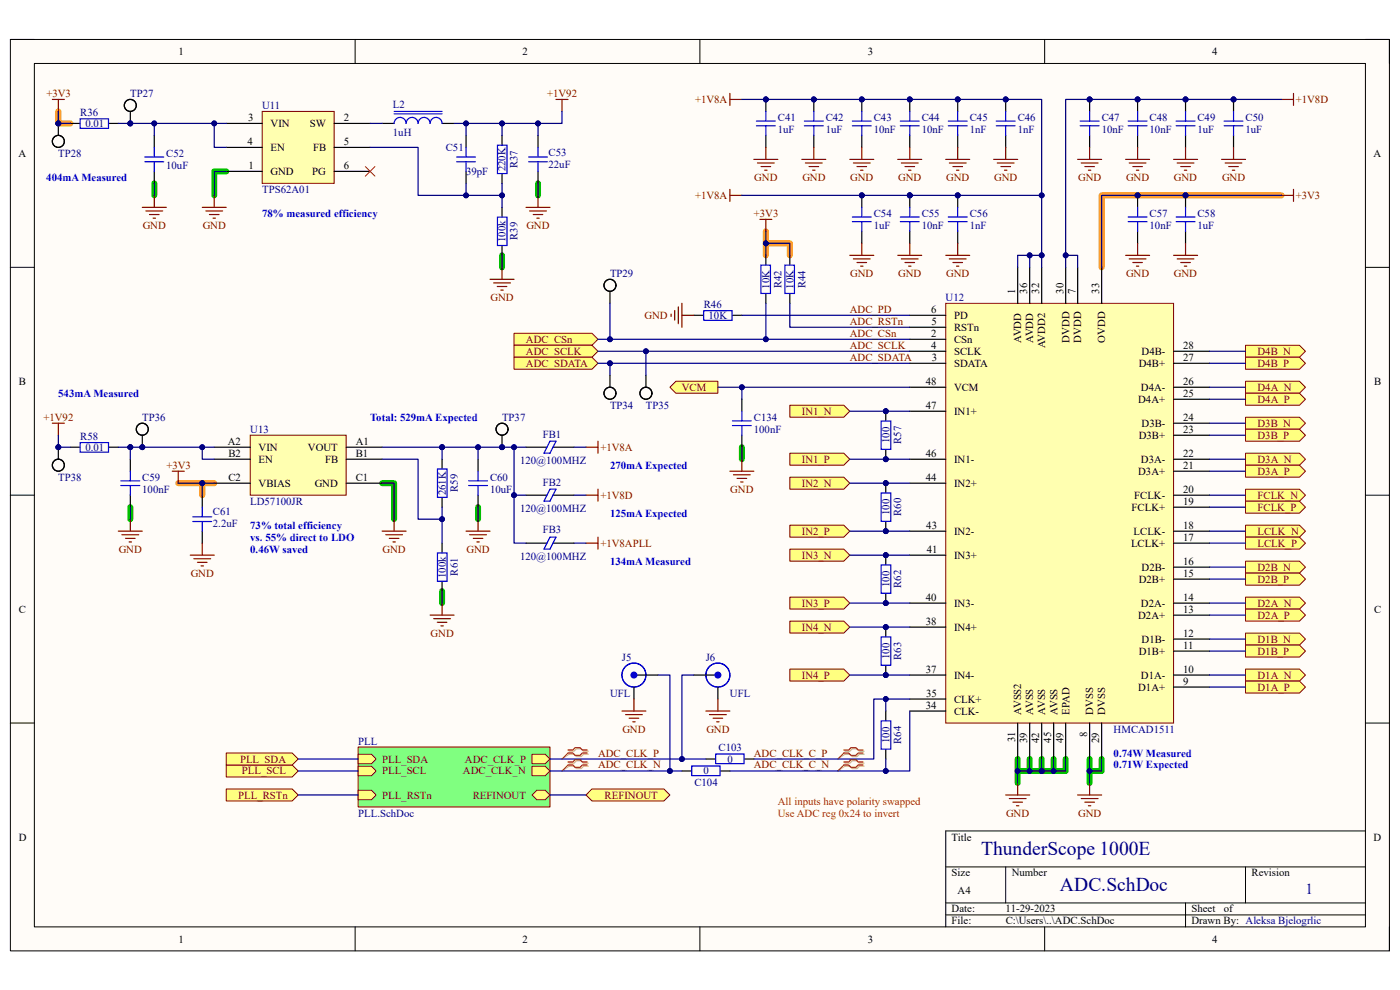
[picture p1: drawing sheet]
<svg xmlns="http://www.w3.org/2000/svg" width="297mm" height="210mm" viewBox="0 0 297 210" stroke-linecap="round" stroke-linejoin="round" font-family="sans-serif">
<defs><g id="words">
<g font-size="4.1" fill="#000080">
<text x="208.2" y="181.5">ThunderScope 1000E</text>
<text x="224.9" y="189.1">ADC.SchDoc</text>
</g>
<text font-size="3.2" fill="#000080" x="276.9" y="189.6">1</text>
<g font-size="2.3">
<text x="37.9" y="11.7">1</text>
<text x="110.9" y="11.7">2</text>
<text x="184.1" y="11.7">3</text>
<text x="257.1" y="11.7">4</text>
<text x="52.6" y="25.7">3</text>
<text x="57.4" y="26.9">VIN</text>
<text x="65.7" y="26.9">SW</text>
<text x="72.9" y="25.7">2</text>
<text x="3.9" y="33.3">A</text>
<text x="52.5" y="30.7">4</text>
<text x="52.7" y="35.9">1</text>
<text x="57.4" y="32">EN</text>
<text x="66.4" y="32">FB</text>
<text x="72.9" y="30.7">5</text>
<text x="72.9" y="35.9">6</text>
<text x="291.4" y="33.3">A</text>
<text x="57.4" y="37.1">GND</text>
<text x="66.2" y="37.1">PG</text>
<text x="215.4" y="62.3" transform="rotate(-90 215.4 62.3)">1</text>
<text x="217.9" y="62.3" transform="rotate(-90 217.9 62.3)">36</text>
<text x="220.5" y="62.3" transform="rotate(-90 220.5 62.3)">32</text>
<text x="225.6" y="62.3" transform="rotate(-90 225.6 62.3)">30</text>
<text x="228.1" y="62.3" transform="rotate(-90 228.1 62.3)">7</text>
<text x="233.2" y="62.3" transform="rotate(-90 233.2 62.3)">33</text>
<text x="197.5" y="66.4">6</text>
<text x="197.5" y="71.5">2</text>
<text x="197.6" y="68.9">5</text>
<text x="202.4" y="67.6">PD</text>
<text x="202.4" y="70.2">RSTn</text>
<text x="197.5" y="74">4</text>
<text x="197.7" y="76.5">3</text>
<text x="202.4" y="72.7">CSn</text>
<text x="202.4" y="75.3">SCLK</text>
<text x="202.4" y="77.8">SDATA</text>
<text x="216.7" y="72.7" transform="rotate(-90 216.7 72.7)">AVDD</text>
<text x="219.2" y="72.7" transform="rotate(-90 219.2 72.7)">AVDD</text>
<text x="221.7" y="73.8" transform="rotate(-90 221.7 73.8)">AVDD2</text>
<text x="226.9" y="72.7" transform="rotate(-90 226.9 72.7)">DVDD</text>
<text x="229.4" y="72.7" transform="rotate(-90 229.4 72.7)">DVDD</text>
<text x="234.5" y="72.7" transform="rotate(-90 234.5 72.7)">OVDD</text>
<text x="241.6" y="77.8">D4B+</text>
<text x="242.2" y="75.3">D4B-</text>
<text x="251" y="76.5">27</text>
<text x="251" y="74">28</text>
<text x="4" y="81.6">B</text>
<text x="196.4" y="81.6">48</text>
<text x="202.4" y="82.9">VCM</text>
<text x="242.1" y="82.9">D4A-</text>
<text x="251" y="81.6">26</text>
<text x="291.5" y="81.6">B</text>
<text x="196.4" y="86.7">47</text>
<text x="202.4" y="88">IN1+</text>
<text x="241.5" y="85.4">D4A+</text>
<text x="251" y="89.3">24</text>
<text x="251" y="84.2">25</text>
<text x="48.3" y="94.4">A2</text>
<text x="54.9" y="95.6">VIN</text>
<text x="65.3" y="95.6">VOUT</text>
<text x="75.5" y="94.4">A1</text>
<text x="241.6" y="93.1">D3B+</text>
<text x="242.2" y="90.6">D3B-</text>
<text x="251" y="91.8">23</text>
<text x="48.5" y="96.9">B2</text>
<text x="48.5" y="102">C2</text>
<text x="54.9" y="98.2">EN</text>
<text x="69" y="98.2">FB</text>
<text x="75.5" y="96.9">B1</text>
<text x="75.5" y="102">C1</text>
<text x="196.4" y="96.9">46</text>
<text x="196.4" y="102">44</text>
<text x="202.4" y="98.2">IN1-</text>
<text x="241.5" y="100.7">D3A+</text>
<text x="242.1" y="98.2">D3A-</text>
<text x="251" y="99.4">21</text>
<text x="251" y="96.9">22</text>
<text x="54.9" y="103.3">VBIAS</text>
<text x="66.8" y="103.3">GND</text>
<text x="202.4" y="103.3">IN2+</text>
<text x="240.6" y="105.8">FCLK-</text>
<text x="251" y="107.1">19</text>
<text x="251" y="104.5">20</text>
<text x="196.5" y="112.1">43</text>
<text x="202.4" y="113.4">IN2-</text>
<text x="240.1" y="108.3">FCLK+</text>
<text x="240.5" y="113.4">LCLK-</text>
<text x="251" y="112.1">18</text>
<text x="196.6" y="117.3">41</text>
<text x="202.4" y="118.5">IN3+</text>
<text x="239.9" y="116">LCLK+</text>
<text x="251" y="119.8">16</text>
<text x="251" y="114.7">17</text>
<text x="241.6" y="123.6">D2B+</text>
<text x="242.2" y="121.1">D2B-</text>
<text x="251" y="122.3">15</text>
<text x="4" y="130">C</text>
<text x="196.4" y="127.4">40</text>
<text x="202.4" y="128.7">IN3-</text>
<text x="241.5" y="131.2">D2A+</text>
<text x="242.1" y="128.7">D2A-</text>
<text x="251" y="130">13</text>
<text x="251" y="127.4">14</text>
<text x="291.5" y="130">C</text>
<text x="196.4" y="132.5">38</text>
<text x="202.4" y="133.8">IN4+</text>
<text x="242.2" y="136.3">D1B-</text>
<text x="251" y="137.6">11</text>
<text x="251" y="135">12</text>
<text x="196.4" y="142.7">37</text>
<text x="202.4" y="144">IN4-</text>
<text x="241.6" y="138.9">D1B+</text>
<text x="242.1" y="144">D1A-</text>
<text x="251" y="142.7">10</text>
<text x="196.5" y="147.8">35</text>
<text x="202.4" y="149.1">CLK+</text>
<text x="241.5" y="146.5">D1A+</text>
<text x="251" y="145.2">9</text>
<text x="196.4" y="150.3">34</text>
<text x="202.4" y="151.6">CLK-</text>
<text x="216.7" y="151.6" transform="rotate(-90 216.7 151.6)">AVSS2</text>
<text x="219.2" y="151.6" transform="rotate(-90 219.2 151.6)">AVSS</text>
<text x="221.7" y="151.6" transform="rotate(-90 221.7 151.6)">AVSS</text>
<text x="224.3" y="151.6" transform="rotate(-90 224.3 151.6)">AVSS</text>
<text x="226.9" y="151.6" transform="rotate(-90 226.9 151.6)">EPAD</text>
<text x="231.9" y="151.6" transform="rotate(-90 231.9 151.6)">DVSS</text>
<text x="234.5" y="151.6" transform="rotate(-90 234.5 151.6)">DVSS</text>
<text x="215.4" y="157.4" transform="rotate(-90 215.4 157.4)">31</text>
<text x="217.9" y="157.6" transform="rotate(-90 217.9 157.6)">39</text>
<text x="220.5" y="157.6" transform="rotate(-90 220.5 157.6)">42</text>
<text x="223" y="157.6" transform="rotate(-90 223 157.6)">45</text>
<text x="225.6" y="157.6" transform="rotate(-90 225.6 157.6)">49</text>
<text x="230.7" y="156.4" transform="rotate(-90 230.7 156.4)">8</text>
<text x="233.2" y="157.6" transform="rotate(-90 233.2 157.6)">29</text>
<text x="4" y="178.3">D</text>
<text x="201.9" y="178.3">Title</text>
<text x="291.4" y="178.3">D</text>
<text x="201.9" y="185.9">Size</text>
<text x="214.6" y="185.9">Number</text>
<text x="265.5" y="185.9">Revision</text>
<text x="203.2" y="189.7">A4</text>
<text x="201.9" y="193.5">Date:</text>
<text x="201.9" y="196.1">File:</text>
<text x="213.3" y="193.5">11-29-2023</text>
<text x="213.4" y="196.1">C:\Users\..\ADC.SchDoc</text>
<text x="252.8" y="193.5">Sheet</text>
<text x="252.8" y="196.1">Drawn By: Aleksa Bjelogrlic</text>
<text x="259.6" y="193.5">of</text>
<text x="37.9" y="199.9">1</text>
<text x="110.9" y="199.9">2</text>
<text x="184.1" y="199.9">3</text>
<text x="257.1" y="199.9">4</text>
</g>
<g font-size="2.3" fill="#800000">
<text x="9.9" y="20.6">+3V3</text>
<text x="116.1" y="20.6">+1V92</text>
<text x="147.4" y="21.8">+1V8A</text>
<text x="274.9" y="21.8">+1V8D</text>
<text x="160" y="38.4">GND</text>
<text x="170.2" y="38.4">GND</text>
<text x="180.4" y="38.4">GND</text>
<text x="190.5" y="38.4">GND</text>
<text x="200.7" y="38.4">GND</text>
<text x="210.9" y="38.4">GND</text>
<text x="228.7" y="38.4">GND</text>
<text x="238.9" y="38.4">GND</text>
<text x="249" y="38.4">GND</text>
<text x="259.2" y="38.4">GND</text>
<text x="147.4" y="42.2">+1V8A</text>
<text x="159.9" y="46">+3V3</text>
<text x="274.9" y="42.2">+3V3</text>
<text x="30.3" y="48.6">GND</text>
<text x="43" y="48.6">GND</text>
<text x="111.7" y="48.6">GND</text>
<text x="180.4" y="58.7">GND</text>
<text x="190.5" y="58.7">GND</text>
<text x="200.7" y="58.7">GND</text>
<text x="238.9" y="58.7">GND</text>
<text x="249" y="58.7">GND</text>
<text x="104.1" y="63.8">GND</text>
<text x="136.7" y="67.6">GND</text>
<text x="180.3" y="66.4">ADC_PD</text>
<text x="180.3" y="68.9">ADC_RSTn</text>
<text x="180.3" y="71.5">ADC_CSn</text>
<text x="111.6" y="72.7">ADC_CSn</text>
<text x="111.6" y="75.3">ADC_SCLK</text>
<text x="111.6" y="77.8">ADC_SDATA</text>
<text x="180.3" y="74">ADC_SCLK</text>
<text x="180.3" y="76.5">ADC_SDATA</text>
<text x="266.8" y="75.3">D4B_N</text>
<text x="266.8" y="77.8">D4B_P</text>
<text x="144.7" y="82.9">VCM</text>
<text x="266.8" y="82.9">D4A_N</text>
<text x="9.2" y="89.3">+1V92</text>
<text x="170.1" y="88">IN1_N</text>
<text x="266.8" y="85.4">D4A_P</text>
<text x="127.4" y="95.6">+1V8A</text>
<text x="266.8" y="90.6">D3B_N</text>
<text x="266.8" y="93.1">D3B_P</text>
<text x="35.3" y="99.4">+3V3</text>
<text x="170.1" y="98.2">IN1_P</text>
<text x="266.8" y="98.2">D3A_N</text>
<text x="266.8" y="100.7">D3A_P</text>
<text x="127.4" y="105.8">+1V8D</text>
<text x="154.9" y="104.5">GND</text>
<text x="170.1" y="103.3">IN2_N</text>
<text x="266.8" y="105.8">FCLK_N</text>
<text x="170.1" y="113.4">IN2_P</text>
<text x="266.8" y="108.3">FCLK_P</text>
<text x="266.8" y="113.4">LCLK_N</text>
<text x="25.2" y="117.3">GND</text>
<text x="81.2" y="117.3">GND</text>
<text x="99" y="117.3">GND</text>
<text x="127.4" y="116">+1V8APLL</text>
<text x="170.1" y="118.5">IN3_N</text>
<text x="266.8" y="116">LCLK_P</text>
<text x="40.5" y="122.3">GND</text>
<text x="266.8" y="121.1">D2B_N</text>
<text x="266.8" y="123.6">D2B_P</text>
<text x="170.1" y="128.7">IN3_P</text>
<text x="266.8" y="128.7">D2A_N</text>
<text x="266.8" y="131.2">D2A_P</text>
<text x="91.4" y="135">GND</text>
<text x="170.1" y="133.8">IN4_N</text>
<text x="266.8" y="136.3">D1B_N</text>
<text x="170.1" y="144">IN4_P</text>
<text x="266.8" y="138.9">D1B_P</text>
<text x="266.8" y="144">D1A_N</text>
<text x="266.8" y="146.5">D1A_P</text>
<text x="132" y="155.4">GND</text>
<text x="149.9" y="155.4">GND</text>
<text x="50.9" y="161.8">PLL_SDA</text>
<text x="81.1" y="161.8">PLL_SDA</text>
<text x="98.6" y="161.8">ADC_CLK_P</text>
<text x="126.9" y="160.5">ADC_CLK_P</text>
<text x="159.9" y="160.5">ADC_CLK_C_P</text>
<text x="51.3" y="164.3">PLL_SCL</text>
<text x="81.1" y="164.3">PLL_SCL</text>
<text x="98.2" y="164.3">ADC_CLK_N</text>
<text x="126.9" y="163">ADC_CLK_N</text>
<text x="159.9" y="163">ADC_CLK_C_N</text>
<text x="50.5" y="169.4">PLL_RSTn</text>
<text x="81.1" y="169.4">PLL_RSTn</text>
<text x="100.3" y="169.4">REFINOUT</text>
<text x="128.3" y="169.4">REFINOUT</text>
<text x="213.4" y="173.2">GND</text>
<text x="228.7" y="173.2">GND</text>
</g>
<g font-size="2.3" fill="#000080">
<text x="27.6" y="20.6">TP27</text>
<text x="55.6" y="23.1">U11</text>
<text x="83.4" y="22.9">L2</text>
<text x="17" y="24.7">R36</text>
<text x="18.1" y="26.9">0.01</text>
<text x="83.4" y="29">1uH</text>
<text x="165" y="25.7">C41</text>
<text x="165" y="28.2">1uF</text>
<text x="175.2" y="25.7">C42</text>
<text x="175.2" y="28.2">1uF</text>
<text x="185.4" y="25.7">C43</text>
<text x="185.4" y="28.2">10nF</text>
<text x="195.5" y="25.7">C44</text>
<text x="195.5" y="28.2">10nF</text>
<text x="205.7" y="25.7">C45</text>
<text x="205.7" y="28.2">1nF</text>
<text x="215.9" y="25.7">C46</text>
<text x="215.9" y="28.2">1nF</text>
<text x="233.7" y="25.7">C47</text>
<text x="233.7" y="28.2">10nF</text>
<text x="243.9" y="25.7">C48</text>
<text x="243.9" y="28.2">10nF</text>
<text x="254" y="25.7">C49</text>
<text x="254" y="28.2">1uF</text>
<text x="264.2" y="25.7">C50</text>
<text x="264.2" y="28.2">1uF</text>
<text x="12.4" y="33.3">TP28</text>
<text x="35.3" y="33.3">C52</text>
<text x="35.3" y="35.9">10uF</text>
<text x="94.6" y="32">C51</text>
<text x="109.8" y="35.7" transform="rotate(-90 109.8 35.7)">R37</text>
<text x="116.4" y="33">C53</text>
<text x="116.4" y="35.6">22uF</text>
<text x="55.6" y="40.9">TPS62A01</text>
<text x="98.9" y="37.1">39pF</text>
<text x="107.3" y="36.4" transform="rotate(-90 107.3 36.4)">220K</text>
<text x="185.4" y="46">C54</text>
<text x="195.5" y="46">C55</text>
<text x="205.7" y="46">C56</text>
<text x="243.9" y="46">C57</text>
<text x="254" y="46">C58</text>
<text x="107.3" y="51.4" transform="rotate(-90 107.3 51.4)">100k</text>
<text x="109.8" y="50.9" transform="rotate(-90 109.8 50.9)">R39</text>
<text x="185.4" y="48.6">1uF</text>
<text x="195.5" y="48.6">10nF</text>
<text x="205.7" y="48.6">1nF</text>
<text x="243.9" y="48.6">10nF</text>
<text x="254" y="48.6">1uF</text>
<text x="129.4" y="58.7">TP29</text>
<text x="149.3" y="65.4">R46</text>
<text x="163.2" y="61.3" transform="rotate(-90 163.2 61.3)">10K</text>
<text x="165.8" y="61.1" transform="rotate(-90 165.8 61.1)">R42</text>
<text x="168.3" y="61.3" transform="rotate(-90 168.3 61.3)">10K</text>
<text x="170.9" y="61.1" transform="rotate(-90 170.9 61.1)">R44</text>
<text x="200.6" y="63.8">U12</text>
<text x="150.3" y="67.6">10K</text>
<text x="30.2" y="89.3">TP36</text>
<text x="106.5" y="89.3">TP37</text>
<text x="129.4" y="86.7">TP34</text>
<text x="137" y="86.7">TP35</text>
<text x="159.9" y="89.3">C134</text>
<text x="17" y="93.4">R58</text>
<text x="18.1" y="95.6">0.01</text>
<text x="53.1" y="91.8">U13</text>
<text x="115.1" y="92.8">FB1</text>
<text x="159.9" y="91.8">100nF</text>
<text x="188.7" y="94" transform="rotate(-90 188.7 94)">100</text>
<text x="191.2" y="94.2" transform="rotate(-90 191.2 94.2)">R57</text>
<text x="12.4" y="102">TP38</text>
<text x="30.2" y="102">C59</text>
<text x="104" y="102">C60</text>
<text x="110.3" y="98.4">120@100MHZ</text>
<text x="30.2" y="104.5">100nF</text>
<text x="53.1" y="107.1">LD57100JR</text>
<text x="94.6" y="105.1" transform="rotate(-90 94.6 105.1)">261K</text>
<text x="97.1" y="104.4" transform="rotate(-90 97.1 104.4)">R59</text>
<text x="104" y="104.5">10uF</text>
<text x="115.1" y="103">FB2</text>
<text x="45.2" y="109.3">C61</text>
<text x="45.2" y="111.9">2.2uF</text>
<text x="110.3" y="108.6">120@100MHZ</text>
<text x="115.1" y="113.2">FB3</text>
<text x="188.7" y="109.3" transform="rotate(-90 188.7 109.3)">100</text>
<text x="191.2" y="109.5" transform="rotate(-90 191.2 109.5)">R60</text>
<text x="110.3" y="118.8">120@100MHZ</text>
<text x="94.6" y="122.6" transform="rotate(-90 94.6 122.6)">100k</text>
<text x="97.1" y="122.1" transform="rotate(-90 97.1 122.1)">R61</text>
<text x="188.7" y="124.5" transform="rotate(-90 188.7 124.5)">100</text>
<text x="191.2" y="124.7" transform="rotate(-90 191.2 124.7)">R62</text>
<text x="132" y="140.1">J5</text>
<text x="149.7" y="140.1">J6</text>
<text x="188.7" y="139.8" transform="rotate(-90 188.7 139.8)">100</text>
<text x="191.2" y="140" transform="rotate(-90 191.2 140)">R63</text>
<text x="129.4" y="147.8">UFL</text>
<text x="154.9" y="147.8">UFL</text>
<text x="236.3" y="155.4">HMCAD1511</text>
<text x="76" y="157.9">PLL</text>
<text x="152.4" y="159.2">C103</text>
<text x="154.3" y="161.8">0</text>
<text x="188.7" y="157.6" transform="rotate(-90 188.7 157.6)">100</text>
<text x="191.2" y="157.8" transform="rotate(-90 191.2 157.8)">R64</text>
<text x="147.3" y="166.8">C104</text>
<text x="149.2" y="164.3">0</text>
<text x="76" y="173.2">PLL.SchDoc</text>
</g>
<g font-size="2.3" fill="#00f">
<text x="9.8" y="38.4">404mA Measured</text>
<text x="55.6" y="46">78% measured efficiency</text>
<text x="12.4" y="84.2">543mA Measured</text>
<text x="78.5" y="89.3">Total: 529mA Expected</text>
<text x="129.4" y="99.4">270mA Expected</text>
<text x="53.1" y="112.1">73% total efficiency</text>
<text x="129.4" y="109.6">125mA Expected</text>
<text x="53.1" y="114.7">vs. 55% direct to LDO</text>
<text x="53.1" y="117.3">0.46W saved</text>
<text x="129.4" y="119.8">134mA Measured</text>
<text x="236.3" y="160.5">0.74W Measured</text>
<text x="236.3" y="163">0.71W Expected</text>
</g>
<g font-size="2.3" fill="#f00">
<text x="165" y="170.7">All inputs have polarity swapped</text>
<text x="165" y="173.2">Use ADC reg 0x24 to invert</text>
</g>
</g></defs>
<path d="M2.2 8.4h292.6v193.3h-292.6z" fill-rule="evenodd" fill="#fffcf8"/>
<path d="M2.2 8.4h292.6v193.3h-292.6z" fill="none" stroke="#000" stroke-width=".21"/>
<path d="M7.3 13.5h282.4v183.1h-282.4z" fill-rule="evenodd" fill="#fffcf8"/>
<g fill="none" stroke="#000" stroke-width=".21">
<path d="M2.2 8.4h5.1M7.3 13.5h282.4v183.1h-282.4zM75.3 8.4v5.1M148.5 8.4v5.1M221.6 8.4v5.1M289.7 8.4h5.1v5.1M2.2 56.7h5.1M289.7 56.7h5.1M2.2 105h5.1M289.7 105.1h5.1M2.2 153.4h5.1M289.7 153.4h5.1"/>
<path d="M289.7 176.3h-89.1v20.3M75.3 196.6v5.1M148.5 196.6v5.1M200.6 183.9h89.1M200.6 191.5h89.1M200.6 194.1h89.1M213.4 183.9v7.6M221.6 196.6v5.1M251.5 191.5v5.1M264.2 183.9v7.6M294.8 196.6v5.1"/>
</g>
<g fill="none" stroke="#00be00" stroke-width="1.3">
<path d="M32.7 38.9v2.5M48 36.4h-2.5v5M114.1 38.9v2.5M106.5 54.2v2.5M157.4 94.9v2.5M27.6 107.6v2.5M81.1 102.5h2.5v7.6M101.4 107.6v2.5M93.8 125.4v2.5M215.9 161v2.6M218.5 161v2.6M221 163.6h-5.1v2.5"/>
<path d="M221 161v2.6M223.5 161v2.6M226.1 161v2.6h-5.1M231.2 161v2.6h2.5v-2.6M231.2 163.6v2.5"/>
</g>
<path d="M12.4 23.6v2.6h2.5M162.5 54.2v-2.6h5.1v2.6M162.5 49.1v2.5M271.9 41.4h-38.2v15.3M37.8 102.5h5.1M45.5 102.5h-2.6v2.5" fill="none" stroke="#f90" stroke-width="1.3"/>
<path d="M93.8 97.4v2M101.4 97.4v2.6M93.8 105.6v2M93.8 115.2v2M101.4 105v2.6M93.8 123.4v2" fill="none" stroke="#000" stroke-width=".25"/>
<path d="M92.8 99.5h2v6h-2zM101.4 100v2M92.8 117.3h2v6h-2zM99.4 103h4M99.4 102h4M101.4 103v2" fill="none" stroke="#00f" stroke-width=".25"/>
<path d="M98.9 112.7h5.1M99.6 113.4h3.6M100.4 114.2h2M101.2 115h.5M101.4 110.1v2.6M91.2 130.5h5.1M92 131.2h3.6M92.8 132h2M93.5 132.8h.5M93.8 127.9v2.6" fill="none" stroke="#800000" stroke-width=".25"/>
<circle cx="241.3" cy="41.4" r=".51" fill="#000080"/>
<circle cx="241.3" cy="41.4" r=".51" fill="none" stroke="#000080" stroke-width=".21"/>
<path d="M241.3 41.4v2.6M241.3 49.1v2.5" fill="none" stroke="#000" stroke-width=".25"/>
<circle cx="241.3" cy="41.4" r=".51" fill="#000080"/>
<circle cx="241.3" cy="41.4" r=".51" fill="none" stroke="#000080" stroke-width=".21"/>
<path d="M239.3 47h4M239.3 46h4M241.3 44v2M241.3 47v2.1" fill="none" stroke="#00f" stroke-width=".25"/>
<circle cx="251.5" cy="41.4" r=".51" fill="#000080"/>
<circle cx="251.5" cy="41.4" r=".51" fill="none" stroke="#000080" stroke-width=".21"/>
<path d="M251.5 41.4v2.6M251.5 49.1v2.5" fill="none" stroke="#000" stroke-width=".25"/>
<circle cx="251.5" cy="41.4" r=".51" fill="#000080"/>
<circle cx="251.5" cy="41.4" r=".51" fill="none" stroke="#000080" stroke-width=".21"/>
<path d="M249.5 47h4M249.5 46h4M251.5 44v2M251.5 47v2.1" fill="none" stroke="#00f" stroke-width=".25"/>
<path d="M238.8 54.2h5.1M239.6 54.9h3.5M240.3 55.7h2.1M241.1 56.5h.5M241.3 51.6v2.6M249 54.2h5.1M249.7 54.9h3.6M250.5 55.7h2M251.3 56.5h.5M251.5 51.6v2.6M271.9 41.4h2.5M274.4 40.2v2.5" fill="none" stroke="#800000" stroke-width=".25"/>
<circle cx="231.2" cy="21.1" r=".51" fill="#000080"/>
<circle cx="231.2" cy="21.1" r=".51" fill="none" stroke="#000080" stroke-width=".21"/>
<path d="M231.2 21.1v2.5M231.2 28.7v2.6" fill="none" stroke="#000" stroke-width=".25"/>
<circle cx="231.2" cy="21.1" r=".51" fill="#000080"/>
<circle cx="231.2" cy="21.1" r=".51" fill="none" stroke="#000080" stroke-width=".21"/>
<path d="M229.2 26.7h4M229.2 25.7h4M231.2 23.6v2.1M231.2 26.7v2" fill="none" stroke="#00f" stroke-width=".25"/>
<circle cx="261.7" cy="21.1" r=".51" fill="#000080"/>
<circle cx="261.7" cy="21.1" r=".51" fill="none" stroke="#000080" stroke-width=".21"/>
<path d="M261.7 21.1v2.5M261.7 28.7v2.6" fill="none" stroke="#000" stroke-width=".25"/>
<circle cx="261.7" cy="21.1" r=".51" fill="#000080"/>
<circle cx="261.7" cy="21.1" r=".51" fill="none" stroke="#000080" stroke-width=".21"/>
<path d="M259.7 26.7h4M259.7 25.7h4M261.7 23.6v2.1M261.7 26.7v2" fill="none" stroke="#00f" stroke-width=".25"/>
<path d="M228.6 33.8h5.1M229.4 34.6h3.5M230.1 35.3h2.1M230.9 36.1h.5M231.2 31.3v2.5M259.2 33.8h5M259.9 34.6h3.6M260.7 35.3h2M261.4 36.1h.5M261.7 31.3v2.5" fill="none" stroke="#800000" stroke-width=".25"/>
<circle cx="241.3" cy="21.1" r=".51" fill="#000080"/>
<circle cx="241.3" cy="21.1" r=".51" fill="none" stroke="#000080" stroke-width=".21"/>
<path d="M241.3 21.1v2.5M241.3 28.7v2.6" fill="none" stroke="#000" stroke-width=".25"/>
<circle cx="241.3" cy="21.1" r=".51" fill="#000080"/>
<circle cx="241.3" cy="21.1" r=".51" fill="none" stroke="#000080" stroke-width=".21"/>
<path d="M239.3 26.7h4M239.3 25.7h4M241.3 23.6v2.1M241.3 26.7v2" fill="none" stroke="#00f" stroke-width=".25"/>
<circle cx="251.5" cy="21.1" r=".51" fill="#000080"/>
<circle cx="251.5" cy="21.1" r=".51" fill="none" stroke="#000080" stroke-width=".21"/>
<path d="M251.5 21.1v2.5M251.5 28.7v2.6" fill="none" stroke="#000" stroke-width=".25"/>
<circle cx="251.5" cy="21.1" r=".51" fill="#000080"/>
<circle cx="251.5" cy="21.1" r=".51" fill="none" stroke="#000080" stroke-width=".21"/>
<path d="M249.5 26.7h4M249.5 25.7h4M251.5 23.6v2.1M251.5 26.7v2" fill="none" stroke="#00f" stroke-width=".25"/>
<path d="M274.4 19.8v2.6M238.8 33.8h5.1M239.6 34.6h3.5M240.3 35.3h2.1M241.1 36.1h.5M241.3 31.3v2.5M249 33.8h5.1M249.7 34.6h3.6M250.5 35.3h2M251.3 36.1h.5M251.5 31.3v2.5M271.9 21.1h2.5" fill="none" stroke="#800000" stroke-width=".25"/>
<circle cx="193" cy="21.1" r=".51" fill="#000080"/>
<circle cx="193" cy="21.1" r=".51" fill="none" stroke="#000080" stroke-width=".21"/>
<path d="M193 21.1v2.5M193 28.7v2.6" fill="none" stroke="#000" stroke-width=".25"/>
<circle cx="193" cy="21.1" r=".51" fill="#000080"/>
<circle cx="193" cy="21.1" r=".51" fill="none" stroke="#000080" stroke-width=".21"/>
<path d="M191 26.7h4M191 25.7h4M193 23.6v2.1M193 26.7v2" fill="none" stroke="#00f" stroke-width=".25"/>
<circle cx="162.5" cy="21.1" r=".51" fill="#000080"/>
<circle cx="162.5" cy="21.1" r=".51" fill="none" stroke="#000080" stroke-width=".21"/>
<path d="M162.5 21.1v2.5M162.5 28.7v2.6" fill="none" stroke="#000" stroke-width=".25"/>
<circle cx="162.5" cy="21.1" r=".51" fill="#000080"/>
<circle cx="162.5" cy="21.1" r=".51" fill="none" stroke="#000080" stroke-width=".21"/>
<path d="M160.5 26.7h4M160.5 25.7h4M162.5 23.6v2.1M162.5 26.7v2" fill="none" stroke="#00f" stroke-width=".25"/>
<path d="M159.9 33.8h5.1M160.7 34.6h3.6M161.5 35.3h2M162.2 36.1h.5M162.5 31.3v2.5M190.5 33.8h5M191.2 34.6h3.6M192 35.3h2M192.8 36.1h.5M193 31.3v2.5" fill="none" stroke="#800000" stroke-width=".25"/>
<circle cx="182.8" cy="21.1" r=".51" fill="#000080"/>
<circle cx="182.8" cy="21.1" r=".51" fill="none" stroke="#000080" stroke-width=".21"/>
<path d="M182.8 21.1v2.5M182.8 28.7v2.6" fill="none" stroke="#000" stroke-width=".25"/>
<circle cx="182.8" cy="21.1" r=".51" fill="#000080"/>
<circle cx="182.8" cy="21.1" r=".51" fill="none" stroke="#000080" stroke-width=".21"/>
<path d="M180.8 26.7h4M180.8 25.7h4M182.8 23.6v2.1M182.8 26.7v2" fill="none" stroke="#00f" stroke-width=".25"/>
<circle cx="172.7" cy="21.1" r=".51" fill="#000080"/>
<circle cx="172.7" cy="21.1" r=".51" fill="none" stroke="#000080" stroke-width=".21"/>
<path d="M172.7 21.1v2.5M172.7 28.7v2.6" fill="none" stroke="#000" stroke-width=".25"/>
<circle cx="172.7" cy="21.1" r=".51" fill="#000080"/>
<circle cx="172.7" cy="21.1" r=".51" fill="none" stroke="#000080" stroke-width=".21"/>
<path d="M170.6 26.7h4.1M170.6 25.7h4.1M172.7 23.6v2.1M172.7 26.7v2" fill="none" stroke="#00f" stroke-width=".25"/>
<path d="M170.1 33.8h5.1M170.9 34.6h3.5M171.6 35.3h2.1M172.4 36.1h.5M172.7 31.3v2.5M180.3 33.8h5.1M181 34.6h3.6M181.8 35.3h2M182.6 36.1h.5M182.8 31.3v2.5" fill="none" stroke="#800000" stroke-width=".25"/>
<circle cx="203.2" cy="21.1" r=".51" fill="#000080"/>
<circle cx="203.2" cy="21.1" r=".51" fill="none" stroke="#000080" stroke-width=".21"/>
<path d="M203.2 21.1v2.5M203.2 28.7v2.6" fill="none" stroke="#000" stroke-width=".25"/>
<circle cx="203.2" cy="21.1" r=".51" fill="#000080"/>
<circle cx="203.2" cy="21.1" r=".51" fill="none" stroke="#000080" stroke-width=".21"/>
<path d="M201.2 26.7h4M201.2 25.7h4M203.2 23.6v2.1M203.2 26.7v2" fill="none" stroke="#00f" stroke-width=".25"/>
<path d="M200.6 33.8h5.1M201.4 34.6h3.6M202.2 35.3h2M202.9 36.1h.5M203.2 31.3v2.5" fill="none" stroke="#800000" stroke-width=".25"/>
<circle cx="213.4" cy="21.1" r=".51" fill="#000080"/>
<circle cx="213.4" cy="21.1" r=".51" fill="none" stroke="#000080" stroke-width=".21"/>
<path d="M213.4 21.1v2.5M213.4 28.7v2.6" fill="none" stroke="#000" stroke-width=".25"/>
<circle cx="213.4" cy="21.1" r=".51" fill="#000080"/>
<circle cx="213.4" cy="21.1" r=".51" fill="none" stroke="#000080" stroke-width=".21"/>
<path d="M211.3 26.7h4.1M211.3 25.7h4.1M213.4 23.6v2.1M213.4 26.7v2" fill="none" stroke="#00f" stroke-width=".25"/>
<path d="M210.8 33.8h5.1M211.6 34.6h3.5M212.3 35.3h2.1M213.1 36.1h.5M213.4 31.3v2.5" fill="none" stroke="#800000" stroke-width=".25"/>
<circle cx="182.8" cy="41.4" r=".51" fill="#000080"/>
<circle cx="182.8" cy="41.4" r=".51" fill="none" stroke="#000080" stroke-width=".21"/>
<path d="M182.8 41.4v2.6M182.8 49.1v2.5" fill="none" stroke="#000" stroke-width=".25"/>
<circle cx="182.8" cy="41.4" r=".51" fill="#000080"/>
<circle cx="182.8" cy="41.4" r=".51" fill="none" stroke="#000080" stroke-width=".21"/>
<path d="M180.8 47h4M180.8 46h4M182.8 44v2M182.8 47v2.1" fill="none" stroke="#00f" stroke-width=".25"/>
<path d="M180.3 54.2h5.1M181 54.9h3.6M181.8 55.7h2M182.6 56.5h.5M182.8 51.6v2.6" fill="none" stroke="#800000" stroke-width=".25"/>
<circle cx="193" cy="41.4" r=".51" fill="#000080"/>
<circle cx="193" cy="41.4" r=".51" fill="none" stroke="#000080" stroke-width=".21"/>
<path d="M193 41.4v2.6M193 49.1v2.5" fill="none" stroke="#000" stroke-width=".25"/>
<circle cx="193" cy="41.4" r=".51" fill="#000080"/>
<circle cx="193" cy="41.4" r=".51" fill="none" stroke="#000080" stroke-width=".21"/>
<path d="M191 47h4M191 46h4M193 44v2M193 47v2.1" fill="none" stroke="#00f" stroke-width=".25"/>
<path d="M190.5 54.2h5M191.2 54.9h3.6M192 55.7h2M192.8 56.5h.5M193 51.6v2.6" fill="none" stroke="#800000" stroke-width=".25"/>
<circle cx="203.2" cy="41.4" r=".51" fill="#000080"/>
<circle cx="203.2" cy="41.4" r=".51" fill="none" stroke="#000080" stroke-width=".21"/>
<path d="M203.2 41.4v2.6M203.2 49.1v2.5" fill="none" stroke="#000" stroke-width=".25"/>
<circle cx="203.2" cy="41.4" r=".51" fill="#000080"/>
<circle cx="203.2" cy="41.4" r=".51" fill="none" stroke="#000080" stroke-width=".21"/>
<path d="M161.4 56.3h2.1v6h-2.1zM166.5 56.3h2v6h-2zM201.2 47h4M201.2 46h4M203.2 44v2M203.2 47v2.1M149.3 65.9h6v2h-6z" fill="none" stroke="#00f" stroke-width=".25"/>
<path d="M200.6 54.2h5.1M201.4 54.9h3.6M202.2 55.7h2M202.9 56.5h.5M203.2 51.6v2.6" fill="none" stroke="#800000" stroke-width=".25"/>
<path d="M162.5 54.2v2M167.6 54.2v2M147.2 66.9h2M155.4 66.9h2M162.5 62.3v2M167.6 62.3v2" fill="none" stroke="#000" stroke-width=".25"/>
<path d="M200.6 64.3h48.4v89.1h-48.4z" fill-rule="evenodd" fill="#ffffb0"/>
<path d="M200.6 64.3h48.4v89.1h-48.4z" fill="none" stroke="#800000" stroke-width=".21"/>
<g fill="none" stroke="#000" stroke-width=".25">
<path d="M215.9 56.7v7.6M218.5 56.7v7.6M221 56.7v7.6M226.1 56.7v7.6M228.6 56.7v7.6M233.7 56.7v7.6M193 66.9h7.6M193 69.4h7.6M193 72h7.6M193 74.5h7.6M193 77.1h7.6M249 74.5h7.6"/>
<path d="M249 77.1h7.6M193 82.1h7.6M193 87.2h7.6M193 97.4h7.6M249 82.1h7.6M249 97.4h7.6M249 100h7.6M249 92.3h7.6M249 89.8h7.6M249 84.7h7.6M193 102.5h7.6M193 112.7h7.6"/>
<path d="M193 117.8h7.6M249 112.7h7.6M249 115.2h7.6M249 107.6h7.6M249 105.1h7.6M193 127.9h7.6M193 133h7.6M249 127.9h7.6M249 138.1h7.6M249 135.6h7.6M249 130.5h7.6M249 122.9h7.6"/>
<path d="M249 120.3h7.6M193 143.2h7.6M193 148.3h7.6M193 150.8h7.6M215.9 153.4v7.6M218.5 153.4v7.6M221 153.4v7.6M223.5 153.4v7.6M226.1 153.4v7.6M231.2 153.4v7.6M233.7 153.4v7.6M249 143.2h7.6"/>
<path d="M249 145.8h7.6"/>
</g>
<g fill="none" stroke="#800000" stroke-width=".25">
<path d="M154.8 19.8v2.6M154.8 21.1h2.6M154.8 40.2v2.5M154.8 41.4h2.6M161.2 46.5h2.5M162.5 46.5v2.6M213.4 168.6h5.1M214.1 169.4h3.6M214.9 170.2h2M215.6 170.9h.6M215.9 166.1v2.5M228.6 168.6h5.1"/>
<path d="M229.4 169.4h3.5M230.1 170.2h2.1M230.9 170.9h.5M231.2 166.1v2.5"/>
</g>
<circle cx="187.9" cy="87.2" r=".51" fill="#000080"/>
<circle cx="187.9" cy="87.2" r=".51" fill="none" stroke="#000080" stroke-width=".21"/>
<circle cx="187.9" cy="97.4" r=".51" fill="#000080"/>
<circle cx="187.9" cy="97.4" r=".51" fill="none" stroke="#000080" stroke-width=".21"/>
<path d="M187.9 87.2v2" fill="none" stroke="#000" stroke-width=".25"/>
<circle cx="187.9" cy="87.2" r=".51" fill="#000080"/>
<circle cx="187.9" cy="87.2" r=".51" fill="none" stroke="#000080" stroke-width=".21"/>
<path d="M187.9 95.4v2" fill="none" stroke="#000" stroke-width=".25"/>
<circle cx="187.9" cy="97.4" r=".51" fill="#000080"/>
<circle cx="187.9" cy="97.4" r=".51" fill="none" stroke="#000080" stroke-width=".21"/>
<path d="M186.9 89.3h2.1v6h-2.1z" fill="none" stroke="#00f" stroke-width=".25"/>
<circle cx="187.9" cy="102.5" r=".51" fill="#000080"/>
<circle cx="187.9" cy="102.5" r=".51" fill="none" stroke="#000080" stroke-width=".21"/>
<circle cx="187.9" cy="112.7" r=".51" fill="#000080"/>
<circle cx="187.9" cy="112.7" r=".51" fill="none" stroke="#000080" stroke-width=".21"/>
<path d="M187.9 102.5v2" fill="none" stroke="#000" stroke-width=".25"/>
<circle cx="187.9" cy="102.5" r=".51" fill="#000080"/>
<circle cx="187.9" cy="102.5" r=".51" fill="none" stroke="#000080" stroke-width=".21"/>
<path d="M187.9 110.7v2" fill="none" stroke="#000" stroke-width=".25"/>
<circle cx="187.9" cy="112.7" r=".51" fill="#000080"/>
<circle cx="187.9" cy="112.7" r=".51" fill="none" stroke="#000080" stroke-width=".21"/>
<path d="M186.9 104.6h2.1v6h-2.1z" fill="none" stroke="#00f" stroke-width=".25"/>
<circle cx="187.9" cy="117.8" r=".51" fill="#000080"/>
<circle cx="187.9" cy="117.8" r=".51" fill="none" stroke="#000080" stroke-width=".21"/>
<circle cx="187.9" cy="127.9" r=".51" fill="#000080"/>
<circle cx="187.9" cy="127.9" r=".51" fill="none" stroke="#000080" stroke-width=".21"/>
<path d="M187.9 117.8v2" fill="none" stroke="#000" stroke-width=".25"/>
<circle cx="187.9" cy="117.8" r=".51" fill="#000080"/>
<circle cx="187.9" cy="117.8" r=".51" fill="none" stroke="#000080" stroke-width=".21"/>
<path d="M187.9 125.9v2" fill="none" stroke="#000" stroke-width=".25"/>
<circle cx="187.9" cy="127.9" r=".51" fill="#000080"/>
<circle cx="187.9" cy="127.9" r=".51" fill="none" stroke="#000080" stroke-width=".21"/>
<path d="M186.9 119.8h2.1v6.1h-2.1z" fill="none" stroke="#00f" stroke-width=".25"/>
<circle cx="187.9" cy="133" r=".51" fill="#000080"/>
<circle cx="187.9" cy="133" r=".51" fill="none" stroke="#000080" stroke-width=".21"/>
<circle cx="187.9" cy="143.2" r=".51" fill="#000080"/>
<circle cx="187.9" cy="143.2" r=".51" fill="none" stroke="#000080" stroke-width=".21"/>
<path d="M187.9 133v2" fill="none" stroke="#000" stroke-width=".25"/>
<circle cx="187.9" cy="133" r=".51" fill="#000080"/>
<circle cx="187.9" cy="133" r=".51" fill="none" stroke="#000080" stroke-width=".21"/>
<path d="M187.9 141.2v2" fill="none" stroke="#000" stroke-width=".25"/>
<circle cx="187.9" cy="143.2" r=".51" fill="#000080"/>
<circle cx="187.9" cy="143.2" r=".51" fill="none" stroke="#000080" stroke-width=".21"/>
<path d="M186.9 135.1h2.1v6h-2.1z" fill="none" stroke="#00f" stroke-width=".25"/>
<path d="M264.2 73.2h11.5l1.3 1.3-1.3 1.3h-11.5z" fill-rule="evenodd" fill="#ffff80"/>
<path d="M264.2 73.2h11.5l1.3 1.3-1.3 1.3h-11.5z" fill="none" stroke="#800000" stroke-width=".21"/>
<path d="M264.2 75.8h11.5l1.3 1.3-1.3 1.2h-11.5z" fill-rule="evenodd" fill="#ffff80"/>
<path d="M264.2 75.8h11.5l1.3 1.3-1.3 1.2h-11.5z" fill="none" stroke="#800000" stroke-width=".21"/>
<path d="M264.2 80.9h11.5l1.3 1.2-1.3 1.3h-11.5z" fill-rule="evenodd" fill="#ffff80"/>
<path d="M264.2 80.9h11.5l1.3 1.2-1.3 1.3h-11.5z" fill="none" stroke="#800000" stroke-width=".21"/>
<path d="M264.2 83.4h11.5l1.3 1.3-1.3 1.3h-11.5z" fill-rule="evenodd" fill="#ffff80"/>
<path d="M264.2 83.4h11.5l1.3 1.3-1.3 1.3h-11.5z" fill="none" stroke="#800000" stroke-width=".21"/>
<path d="M264.2 88.5h11.5l1.3 1.3-1.3 1.3h-11.5z" fill-rule="evenodd" fill="#ffff80"/>
<path d="M264.2 88.5h11.5l1.3 1.3-1.3 1.3h-11.5z" fill="none" stroke="#800000" stroke-width=".21"/>
<path d="M264.2 91.1h11.5l1.3 1.2-1.3 1.3h-11.5z" fill-rule="evenodd" fill="#ffff80"/>
<path d="M264.2 91.1h11.5l1.3 1.2-1.3 1.3h-11.5z" fill="none" stroke="#800000" stroke-width=".21"/>
<path d="M264.2 96.1h11.5l1.3 1.3-1.3 1.3h-11.5z" fill-rule="evenodd" fill="#ffff80"/>
<path d="M264.2 96.1h11.5l1.3 1.3-1.3 1.3h-11.5z" fill="none" stroke="#800000" stroke-width=".21"/>
<path d="M264.2 98.7h11.5l1.3 1.3-1.3 1.2h-11.5z" fill-rule="evenodd" fill="#ffff80"/>
<path d="M264.2 98.7h11.5l1.3 1.3-1.3 1.2h-11.5z" fill="none" stroke="#800000" stroke-width=".21"/>
<path d="M264.2 103.8h11.5l1.3 1.3-1.3 1.2h-11.5z" fill-rule="evenodd" fill="#ffff80"/>
<path d="M264.2 103.8h11.5l1.3 1.3-1.3 1.2h-11.5z" fill="none" stroke="#800000" stroke-width=".21"/>
<path d="M264.2 106.3h11.5l1.3 1.3-1.3 1.3h-11.5z" fill-rule="evenodd" fill="#ffff80"/>
<path d="M264.2 106.3h11.5l1.3 1.3-1.3 1.3h-11.5z" fill="none" stroke="#800000" stroke-width=".21"/>
<path d="M264.2 111.4h11.5l1.3 1.3-1.3 1.3h-11.5z" fill-rule="evenodd" fill="#ffff80"/>
<path d="M264.2 111.4h11.5l1.3 1.3-1.3 1.3h-11.5z" fill="none" stroke="#800000" stroke-width=".21"/>
<path d="M264.2 114h11.5l1.3 1.2-1.3 1.3h-11.5z" fill-rule="evenodd" fill="#ffff80"/>
<path d="M264.2 114h11.5l1.3 1.2-1.3 1.3h-11.5z" fill="none" stroke="#800000" stroke-width=".21"/>
<path d="M264.2 119h11.5l1.3 1.3-1.3 1.3h-11.5z" fill-rule="evenodd" fill="#ffff80"/>
<path d="M264.2 119h11.5l1.3 1.3-1.3 1.3h-11.5z" fill="none" stroke="#800000" stroke-width=".21"/>
<path d="M264.2 121.6h11.5l1.3 1.3-1.3 1.2h-11.5z" fill-rule="evenodd" fill="#ffff80"/>
<path d="M264.2 121.6h11.5l1.3 1.3-1.3 1.2h-11.5z" fill="none" stroke="#800000" stroke-width=".21"/>
<path d="M264.2 126.7h11.5l1.3 1.2-1.3 1.3h-11.5z" fill-rule="evenodd" fill="#ffff80"/>
<path d="M264.2 126.7h11.5l1.3 1.2-1.3 1.3h-11.5z" fill="none" stroke="#800000" stroke-width=".21"/>
<path d="M264.2 129.2h11.5l1.3 1.3-1.3 1.3h-11.5z" fill-rule="evenodd" fill="#ffff80"/>
<path d="M264.2 129.2h11.5l1.3 1.3-1.3 1.3h-11.5z" fill="none" stroke="#800000" stroke-width=".21"/>
<path d="M264.2 134.3h11.5l1.3 1.3-1.3 1.2h-11.5z" fill-rule="evenodd" fill="#ffff80"/>
<path d="M264.2 134.3h11.5l1.3 1.3-1.3 1.2h-11.5z" fill="none" stroke="#800000" stroke-width=".21"/>
<path d="M264.2 136.8h11.5l1.3 1.3-1.3 1.3h-11.5z" fill-rule="evenodd" fill="#ffff80"/>
<path d="M264.2 136.8h11.5l1.3 1.3-1.3 1.3h-11.5z" fill="none" stroke="#800000" stroke-width=".21"/>
<path d="M264.2 141.9h11.5l1.3 1.3-1.3 1.3h-11.5z" fill-rule="evenodd" fill="#ffff80"/>
<path d="M264.2 141.9h11.5l1.3 1.3-1.3 1.3h-11.5z" fill="none" stroke="#800000" stroke-width=".21"/>
<path d="M264.2 144.5h11.5l1.3 1.3-1.3 1.2h-11.5z" fill-rule="evenodd" fill="#ffff80"/>
<path d="M264.2 144.5h11.5l1.3 1.3-1.3 1.2h-11.5z" fill="none" stroke="#800000" stroke-width=".21"/>
<path d="M109.1 70.7h16.5l1.3 1.3-1.3 1.2h-16.5z" fill-rule="evenodd" fill="#ffff80"/>
<path d="M109.1 70.7h16.5l1.3 1.3-1.3 1.2h-16.5z" fill="none" stroke="#800000" stroke-width=".21"/>
<path d="M142.1 82.1l1.3-1.2h8.9v2.5h-8.9z" fill-rule="evenodd" fill="#ffff80"/>
<path d="M142.1 82.1l1.3-1.2h8.9v2.5h-8.9z" fill="none" stroke="#800000" stroke-width=".21"/>
<path d="M109.1 73.2h16.5l1.3 1.3-1.3 1.3h-16.5z" fill-rule="evenodd" fill="#ffff80"/>
<path d="M109.1 73.2h16.5l1.3 1.3-1.3 1.3h-16.5z" fill="none" stroke="#800000" stroke-width=".21"/>
<path d="M109.1 75.8h16.5l1.3 1.3-1.3 1.2h-16.5z" fill-rule="evenodd" fill="#ffff80"/>
<path d="M109.1 75.8h16.5l1.3 1.3-1.3 1.2h-16.5z" fill="none" stroke="#800000" stroke-width=".21"/>
<path d="M111.6 94.9h4.4M117.3 94.9h4.5M111.6 105h4.4M117.3 105h4.5M134.5 143.2h5.1M134.5 145.7v2.6M187.9 150.8v2M187.9 159v2M144.7 163.6h2M149.8 161h2M152.8 163.6h2M157.9 161h2" fill="none" stroke="#000" stroke-width=".25"/>
<g fill="none" stroke="#00f" stroke-width=".25">
<path d="M116.7 93.6h1.3l-1.3 2.5h-1.3zM116.7 103.8h1.3l-1.3 2.5h-1.3zM151.8 160h6.1v2h-6.1zM186.9 152.9h2.1v6h-2.1zM146.7 162.5h6.1v2h-6.1z"/>
<circle cx="134.5" cy="143.2" r="2.54"/>
</g>
<path d="M124.3 94.9h2.6M126.9 93.6v2.5M124.3 105h2.6M126.9 103.8v2.5" fill="none" stroke="#800000" stroke-width=".25"/>
<circle cx="134.5" cy="143.2" r=".64" fill="#00f"/>
<circle cx="134.5" cy="143.2" r=".64" fill="none" stroke="#00f" stroke-width=".21"/>
<path d="M131.9 150.8h5.1M132.7 151.6h3.6M133.5 152.4h2M134.2 153.1h.5M134.5 148.3v2.5" fill="none" stroke="#800000" stroke-width=".25"/>
<circle cx="152.3" cy="143.2" r="2.54" fill="none" stroke="#00f" stroke-width=".25"/>
<path d="M147.2 143.2h5.1M152.3 145.7v2.6" fill="none" stroke="#000" stroke-width=".25"/>
<circle cx="152.3" cy="143.2" r=".64" fill="#00f"/>
<circle cx="152.3" cy="143.2" r=".64" fill="none" stroke="#00f" stroke-width=".21"/>
<path d="M149.8 150.8h5M150.5 151.6h3.6M151.3 152.4h2M152 153.1h.6M152.3 148.3v2.5" fill="none" stroke="#800000" stroke-width=".25"/>
<circle cx="106.5" cy="94.9" r=".51" fill="#000080"/>
<circle cx="106.5" cy="94.9" r=".51" fill="none" stroke="#000080" stroke-width=".21"/>
<path d="M106.5 92.3v2.6" fill="none" stroke="#000" stroke-width=".25"/>
<circle cx="106.5" cy="94.9" r=".51" fill="#000080"/>
<circle cx="106.5" cy="94.9" r=".51" fill="none" stroke="#000080" stroke-width=".21"/>
<g fill="none" stroke="#000" stroke-width=".25">
<path d="M129.4 61.8v2.5M129.4 79.6v2.5M137 79.6v2.5"/>
<circle cx="129.4" cy="60.5" r="1.27"/>
<circle cx="106.5" cy="91.1" r="1.27"/>
<circle cx="129.4" cy="83.4" r="1.27"/>
<circle cx="137" cy="83.4" r="1.27"/>
</g>
<path d="M167.6 96.1h11.4l1.3 1.3-1.3 1.3h-11.4z" fill-rule="evenodd" fill="#ffff80"/>
<path d="M167.6 96.1h11.4l1.3 1.3-1.3 1.3h-11.4z" fill="none" stroke="#800000" stroke-width=".21"/>
<path d="M167.6 86h11.4l1.3 1.2-1.3 1.3h-11.4z" fill-rule="evenodd" fill="#ffff80"/>
<path d="M167.6 86h11.4l1.3 1.2-1.3 1.3h-11.4z" fill="none" stroke="#800000" stroke-width=".21"/>
<path d="M167.6 111.4h11.4l1.3 1.3-1.3 1.3h-11.4z" fill-rule="evenodd" fill="#ffff80"/>
<path d="M167.6 111.4h11.4l1.3 1.3-1.3 1.3h-11.4z" fill="none" stroke="#800000" stroke-width=".21"/>
<path d="M167.6 101.2h11.4l1.3 1.3-1.3 1.3h-11.4z" fill-rule="evenodd" fill="#ffff80"/>
<path d="M167.6 101.2h11.4l1.3 1.3-1.3 1.3h-11.4z" fill="none" stroke="#800000" stroke-width=".21"/>
<path d="M167.6 126.7h11.4l1.3 1.2-1.3 1.3h-11.4z" fill-rule="evenodd" fill="#ffff80"/>
<path d="M167.6 126.7h11.4l1.3 1.2-1.3 1.3h-11.4z" fill="none" stroke="#800000" stroke-width=".21"/>
<path d="M167.6 116.5h11.4l1.3 1.3-1.3 1.2h-11.4z" fill-rule="evenodd" fill="#ffff80"/>
<path d="M167.6 116.5h11.4l1.3 1.3-1.3 1.2h-11.4z" fill="none" stroke="#800000" stroke-width=".21"/>
<path d="M167.6 141.9h11.4l1.3 1.3-1.3 1.3h-11.4z" fill-rule="evenodd" fill="#ffff80"/>
<path d="M167.6 141.9h11.4l1.3 1.3-1.3 1.3h-11.4z" fill="none" stroke="#800000" stroke-width=".21"/>
<path d="M167.6 131.8h11.4l1.3 1.2-1.3 1.3h-11.4z" fill-rule="evenodd" fill="#ffff80"/>
<path d="M167.6 131.8h11.4l1.3 1.2-1.3 1.3h-11.4z" fill="none" stroke="#800000" stroke-width=".21"/>
<path d="M76 158.5h40.7v12.7h-40.7z" fill-rule="evenodd" fill="#80ff80"/>
<path d="M76 158.5h40.7v12.7h-40.7z" fill="none" stroke="#800000" stroke-width=".21"/>
<path d="M112.9 160h2.8l1 1-1 1h-2.8z" fill-rule="evenodd" fill="#ffff80"/>
<path d="M112.9 160h2.8l1 1-1 1h-2.8z" fill="none" stroke="#800000" stroke-width=".21"/>
<path d="M112.9 162.5h2.8l1 1.1-1 1h-2.8z" fill-rule="evenodd" fill="#ffff80"/>
<path d="M112.9 162.5h2.8l1 1.1-1 1h-2.8z" fill="none" stroke="#800000" stroke-width=".21"/>
<path d="M76 167.6h2.8l1 1-1 1.1h-2.8z" fill-rule="evenodd" fill="#ffff80"/>
<path d="M76 167.6h2.8l1 1-1 1.1h-2.8z" fill="none" stroke="#800000" stroke-width=".21"/>
<path d="M76 160h2.8l1 1-1 1h-2.8z" fill-rule="evenodd" fill="#ffff80"/>
<path d="M76 160h2.8l1 1-1 1h-2.8z" fill="none" stroke="#800000" stroke-width=".21"/>
<path d="M76 162.5h2.8l1 1.1-1 1h-2.8z" fill-rule="evenodd" fill="#ffff80"/>
<path d="M76 162.5h2.8l1 1.1-1 1h-2.8z" fill="none" stroke="#800000" stroke-width=".21"/>
<path d="M112.9 168.6l1-1h1.8l1 1-1 1.1h-1.8z" fill-rule="evenodd" fill="#ffff80"/>
<path d="M112.9 168.6l1-1h1.8l1 1-1 1.1h-1.8z" fill="none" stroke="#800000" stroke-width=".21"/>
<path d="M120.8 159.4h1l.5-.5h1l.5 .5h1M120.8 160h1l.5 .5h1l.5-.5h1M120.8 161.9h1l.5-.5h1l.5 .5h1M120.8 162.5h1l.5 .5h1l.5-.5h1" fill="none" stroke="#d0a19e" stroke-width=".25"/>
<path d="M120.8 160l-1.6 1M120.8 162.5l-1.6 1.1" fill="none" stroke="#d0a19e" stroke-width=".21"/>
<path d="M120.5 159.1h1l.5-.5h1l.5 .5h1.1M120.5 159.7h1l.5 .5h1l.5-.5h1.1M120.5 161.6h1l.5-.5h1l.5 .5h1.1M120.5 162.3h1l.5 .5h1l.5-.5h1.1" fill="none" stroke="#f00" stroke-width=".25"/>
<path d="M120.5 159.7l-1.3 1.3M120.5 162.3l-1.3 1.3" fill="none" stroke="#f00" stroke-width=".21"/>
<path d="M55.6 23.6h15.3v15.3h-15.3z" fill-rule="evenodd" fill="#ffffb0"/>
<path d="M55.6 23.6h15.3v15.3h-15.3z" fill="none" stroke="#800000" stroke-width=".21"/>
<g fill="none" stroke="#000" stroke-width=".25">
<path d="M14.9 26.2h2M23.1 26.2h2M32.7 28.7v2.6M32.7 36.4v2.5M48 26.2h7.6M48 36.4h7.6M48 31.3h7.6M70.9 26.2h7.6M70.9 36.4h7.6M70.9 31.3h7.6M81.1 26.2h2.5M93.8 26.2h2.5"/>
<path d="M98.9 28.7v2.6M98.9 36.4v2.5M106.5 28.7v2M106.5 36.9v2M114.1 28.7v2.6M114.1 36.4v2.5M106.5 44v2M106.5 52.2v2"/>
</g>
<g fill="none" stroke="#800000" stroke-width=".25">
<path d="M118 21.1h2.5M119.2 21.1v2.5M30.2 44h5.1M31 44.8h3.5M31.7 45.5h2M32.5 46.3h.5M32.7 41.4v2.6M42.9 44h5.1M43.7 44.8h3.5M44.4 45.5h2.1M45.2 46.3h.5M45.5 41.4v2.6"/>
<path d="M104 59.3h5.1M106.5 56.7v2.6M111.6 44h5.1M112.4 44.8h3.5M113.1 45.5h2.1M113.9 46.3h.5M114.1 41.4v2.6M104.7 60h3.6M105.5 60.8h2M106.3 61.5h.5"/>
</g>
<g fill="none" stroke="#00f" stroke-width=".25">
<path d="M17 25.2h6v2h-6zM30.7 34.3h4M30.7 33.3h4M32.7 31.3v2M32.7 34.3v2.1M83.6 26.2a1.27 1.27 0 0 1 1.3-1.3 1.27 1.27 0 0 1 1.3 1.3 1.27 1.27 0 0 1 1.2-1.3 1.27 1.27 0 0 1 1.3 1.3 1.27 1.27 0 0 1 1.3-1.3 1.27 1.27 0 0 1 1.2 1.3 1.27 1.27 0 0 1 1.3-1.3 1.27 1.27 0 0 1 1.3 1.3M83.6 24.1h10.2M83.6 23.6h10.2M96.9 34.3h4M96.9 33.3h4M98.9 31.3v2M98.9 34.3v2.1"/>
<path d="M105.5 30.8h2.1v6h-2.1zM112.1 34.3h4M112.1 33.3h4M114.1 31.3v2M114.1 34.3v2.1M105.5 46.1h2.1v6h-2.1z"/>
</g>
<path d="M77.5 35.3l2 2.1M79.5 35.3l-2 2.1" fill="none" stroke="#f00" stroke-width=".21"/>
<circle cx="12.4" cy="26.2" r=".51" fill="#000080"/>
<circle cx="12.4" cy="26.2" r=".51" fill="none" stroke="#000080" stroke-width=".21"/>
<path d="M12.4 26.2v2.5" fill="none" stroke="#000" stroke-width=".25"/>
<circle cx="12.4" cy="26.2" r=".51" fill="#000080"/>
<circle cx="12.4" cy="26.2" r=".51" fill="none" stroke="#000080" stroke-width=".21"/>
<circle cx="12.4" cy="30" r="1.27" fill="none" stroke="#000" stroke-width=".25"/>
<circle cx="27.6" cy="26.2" r=".51" fill="#000080"/>
<circle cx="27.6" cy="26.2" r=".51" fill="none" stroke="#000080" stroke-width=".21"/>
<path d="M27.6 23.6v2.6" fill="none" stroke="#000" stroke-width=".25"/>
<circle cx="27.6" cy="26.2" r=".51" fill="#000080"/>
<circle cx="27.6" cy="26.2" r=".51" fill="none" stroke="#000080" stroke-width=".21"/>
<circle cx="27.6" cy="22.4" r="1.27" fill="none" stroke="#000" stroke-width=".25"/>
<path d="M11.1 21.1h2.5M12.4 21.1v2.5" fill="none" stroke="#800000" stroke-width=".25"/>
<path d="M53.1 92.3h20.3v12.7h-20.3z" fill-rule="evenodd" fill="#ffffb0"/>
<path d="M53.1 92.3h20.3v12.7h-20.3z" fill="none" stroke="#800000" stroke-width=".21"/>
<path d="M14.9 94.9h2M23.1 94.9h2M27.6 97.4v2.6M45.5 94.9h7.6M45.5 97.4h7.6M73.4 94.9h7.7M73.4 97.4h7.7M27.6 105v2.6M45.5 102.5h7.6M73.4 102.5h7.7" fill="none" stroke="#000" stroke-width=".25"/>
<path d="M17 93.9h6v2h-6zM27.6 100v2M25.6 103h4M25.6 102h4M27.6 103v2" fill="none" stroke="#00f" stroke-width=".25"/>
<path d="M25.1 112.7h5.1M25.9 113.4h3.5M26.6 114.2h2.1M27.4 115h.5M27.6 110.1v2.6" fill="none" stroke="#800000" stroke-width=".25"/>
<circle cx="12.4" cy="94.9" r=".51" fill="#000080"/>
<circle cx="12.4" cy="94.9" r=".51" fill="none" stroke="#000080" stroke-width=".21"/>
<path d="M12.4 94.9v2.5" fill="none" stroke="#000" stroke-width=".25"/>
<circle cx="12.4" cy="94.9" r=".51" fill="#000080"/>
<circle cx="12.4" cy="94.9" r=".51" fill="none" stroke="#000080" stroke-width=".21"/>
<circle cx="12.4" cy="98.7" r="1.27" fill="none" stroke="#000" stroke-width=".25"/>
<circle cx="30.2" cy="94.9" r=".51" fill="#000080"/>
<circle cx="30.2" cy="94.9" r=".51" fill="none" stroke="#000080" stroke-width=".21"/>
<path d="M30.2 92.3v2.6" fill="none" stroke="#000" stroke-width=".25"/>
<circle cx="30.2" cy="94.9" r=".51" fill="#000080"/>
<circle cx="30.2" cy="94.9" r=".51" fill="none" stroke="#000080" stroke-width=".21"/>
<g fill="none" stroke="#000" stroke-width=".25">
<path d="M42.9 105v2.6M42.9 112.7v2.5M111.6 115.2h4.4M117.3 115.2h4.5"/>
<circle cx="30.2" cy="91.1" r="1.27"/>
</g>
<g fill="none" stroke="#800000" stroke-width=".25">
<path d="M11.1 89.8h2.6M12.4 89.8v2.5M36.5 100h2.6M37.8 100v2.5M40.4 117.8h5.1M41.1 118.5h3.6M41.9 119.3h2M42.9 115.2v2.6M81.1 112.7h5.1M81.8 113.4h3.6M82.6 114.2h2M83.4 115h.5"/>
<path d="M83.6 110.1v2.6M124.3 115.2h2.6M126.9 114v2.5M42.7 120.1h.5"/>
</g>
<path d="M40.9 110.6h4M40.9 109.6h4M42.9 107.6v2M42.9 110.6v2.1M116.7 114h1.3l-1.3 2.5h-1.3z" fill="none" stroke="#00f" stroke-width=".25"/>
<path d="M48 167.4h14l1.3 1.2-1.3 1.3h-14z" fill-rule="evenodd" fill="#ffff80"/>
<path d="M48 167.4h14l1.3 1.2-1.3 1.3h-14z" fill="none" stroke="#800000" stroke-width=".21"/>
<path d="M48 162.3h14l1.3 1.3-1.3 1.2h-14z" fill-rule="evenodd" fill="#ffff80"/>
<path d="M48 162.3h14l1.3 1.3-1.3 1.2h-14z" fill="none" stroke="#800000" stroke-width=".21"/>
<path d="M48 159.7h14l1.3 1.3-1.3 1.3h-14z" fill-rule="evenodd" fill="#ffff80"/>
<path d="M48 159.7h14l1.3 1.3-1.3 1.3h-14z" fill="none" stroke="#800000" stroke-width=".21"/>
<path d="M142.4 66.6v.5M143.1 65.9v2M143.9 65.1v3.6M144.7 64.3v5.1M144.7 66.9h2.5" fill="none" stroke="#800000" stroke-width=".25"/>
<path d="M179.3 159.4h1l.5-.5h1l.5 .5h1M179.3 160h1l.5 .5h1l.5-.5h1M179.3 161.9h1l.5-.5h1l.5 .5h1M179.3 162.5h1l.5 .5h1l.5-.5h1" fill="none" stroke="#d0a19e" stroke-width=".25"/>
<path d="M179.3 160l-1.6 1M179.3 162.5l-1.6 1.1" fill="none" stroke="#d0a19e" stroke-width=".21"/>
<path d="M179 159.1h1l.5-.5h1.1l.5 .5h1M179 159.7h1l.5 .6h1.1l.5-.6h1M179 161.6h1l.5-.5h1.1l.5 .5h1M179 162.3h1l.5 .5h1.1l.5-.5h1" fill="none" stroke="#f00" stroke-width=".25"/>
<path d="M179 159.7l-1.3 1.3M179 162.3l-1.3 1.3" fill="none" stroke="#f00" stroke-width=".21"/>
<path d="M125.6 167.4h15.3l1.2 1.2-1.2 1.3h-15.3l-1.3-1.3z" fill-rule="evenodd" fill="#ffff80"/>
<path d="M125.6 167.4h15.3l1.2 1.2-1.2 1.3h-15.3l-1.3-1.3z" fill="none" stroke="#800000" stroke-width=".21"/>
<path d="M157.4 84.7v2.5M157.4 92.3v2.6" fill="none" stroke="#000" stroke-width=".25"/>
<path d="M155.4 90.3h4M155.4 89.3h4M157.4 87.2v2.1M157.4 90.3v2" fill="none" stroke="#00f" stroke-width=".25"/>
<path d="M154.8 100h5.1M157.4 97.4v2.6M155.6 100.7h3.6M156.4 101.5h2M157.1 102.2h.5" fill="none" stroke="#800000" stroke-width=".25"/>
<path d="M93.8 107.6v2.5M101.4 107.6v2.5M93.8 125.4v2.5" fill="none" stroke="#000080" stroke-width=".25"/>
<circle cx="93.8" cy="110.1" r=".51" fill="#000080"/>
<circle cx="93.8" cy="110.1" r=".51" fill="none" stroke="#000080" stroke-width=".21"/>
<path d="M93.8 94.9v2.5" fill="none" stroke="#000080" stroke-width=".25"/>
<circle cx="93.8" cy="94.9" r=".51" fill="#000080"/>
<circle cx="93.8" cy="94.9" r=".51" fill="none" stroke="#000080" stroke-width=".21"/>
<path d="M221 163.6h-5.1v2.5" fill="none" stroke="#000080" stroke-width=".25"/>
<circle cx="215.9" cy="163.6" r=".51" fill="#000080"/>
<circle cx="215.9" cy="163.6" r=".51" fill="none" stroke="#000080" stroke-width=".21"/>
<circle cx="218.4" cy="163.6" r=".51" fill="#000080"/>
<circle cx="218.4" cy="163.6" r=".51" fill="none" stroke="#000080" stroke-width=".21"/>
<circle cx="221" cy="163.6" r=".51" fill="#000080"/>
<circle cx="221" cy="163.6" r=".51" fill="none" stroke="#000080" stroke-width=".21"/>
<path d="M218.5 161v2.6" fill="none" stroke="#000080" stroke-width=".25"/>
<circle cx="218.4" cy="163.6" r=".51" fill="#000080"/>
<circle cx="218.4" cy="163.6" r=".51" fill="none" stroke="#000080" stroke-width=".21"/>
<path d="M221 161v2.6" fill="none" stroke="#000080" stroke-width=".25"/>
<circle cx="221" cy="163.6" r=".51" fill="#000080"/>
<circle cx="221" cy="163.6" r=".51" fill="none" stroke="#000080" stroke-width=".21"/>
<path d="M223.5 161v2.6" fill="none" stroke="#000080" stroke-width=".25"/>
<circle cx="223.5" cy="163.6" r=".51" fill="#000080"/>
<circle cx="223.5" cy="163.6" r=".51" fill="none" stroke="#000080" stroke-width=".21"/>
<path d="M231.2 161v2.6h2.5v-2.6" fill="none" stroke="#000080" stroke-width=".25"/>
<circle cx="231.2" cy="163.6" r=".51" fill="#000080"/>
<circle cx="231.2" cy="163.6" r=".51" fill="none" stroke="#000080" stroke-width=".21"/>
<path d="M231.2 163.6v2.5" fill="none" stroke="#000080" stroke-width=".25"/>
<circle cx="231.2" cy="163.6" r=".51" fill="#000080"/>
<circle cx="231.2" cy="163.6" r=".51" fill="none" stroke="#000080" stroke-width=".21"/>
<path d="M226.1 161v2.6h-5.1" fill="none" stroke="#000080" stroke-width=".25"/>
<circle cx="223.5" cy="163.6" r=".51" fill="#000080"/>
<circle cx="223.5" cy="163.6" r=".51" fill="none" stroke="#000080" stroke-width=".21"/>
<circle cx="221" cy="163.6" r=".51" fill="#000080"/>
<circle cx="221" cy="163.6" r=".51" fill="none" stroke="#000080" stroke-width=".21"/>
<path d="M215.9 161v2.6" fill="none" stroke="#000080" stroke-width=".25"/>
<circle cx="215.9" cy="163.6" r=".51" fill="#000080"/>
<circle cx="215.9" cy="163.6" r=".51" fill="none" stroke="#000080" stroke-width=".21"/>
<path d="M193 41.4h28v12.8" fill="none" stroke="#000080" stroke-width=".25"/>
<circle cx="221" cy="54.2" r=".51" fill="#000080"/>
<circle cx="221" cy="54.2" r=".51" fill="none" stroke="#000080" stroke-width=".21"/>
<circle cx="221" cy="41.4" r=".51" fill="#000080"/>
<circle cx="221" cy="41.4" r=".51" fill="none" stroke="#000080" stroke-width=".21"/>
<circle cx="203.2" cy="41.4" r=".51" fill="#000080"/>
<circle cx="203.2" cy="41.4" r=".51" fill="none" stroke="#000080" stroke-width=".21"/>
<circle cx="193" cy="41.4" r=".51" fill="#000080"/>
<circle cx="193" cy="41.4" r=".51" fill="none" stroke="#000080" stroke-width=".21"/>
<path d="M271.9 21.1h-45.8v33.1" fill="none" stroke="#000080" stroke-width=".25"/>
<circle cx="226.1" cy="54.2" r=".51" fill="#000080"/>
<circle cx="226.1" cy="54.2" r=".51" fill="none" stroke="#000080" stroke-width=".21"/>
<circle cx="231.2" cy="21.1" r=".51" fill="#000080"/>
<circle cx="231.2" cy="21.1" r=".51" fill="none" stroke="#000080" stroke-width=".21"/>
<circle cx="241.3" cy="21.1" r=".51" fill="#000080"/>
<circle cx="241.3" cy="21.1" r=".51" fill="none" stroke="#000080" stroke-width=".21"/>
<circle cx="251.5" cy="21.1" r=".51" fill="#000080"/>
<circle cx="251.5" cy="21.1" r=".51" fill="none" stroke="#000080" stroke-width=".21"/>
<circle cx="261.7" cy="21.1" r=".51" fill="#000080"/>
<circle cx="261.7" cy="21.1" r=".51" fill="none" stroke="#000080" stroke-width=".21"/>
<path d="M162.5 54.2v-2.6h5.1v2.6" fill="none" stroke="#000080" stroke-width=".25"/>
<circle cx="162.5" cy="51.6" r=".51" fill="#000080"/>
<circle cx="162.5" cy="51.6" r=".51" fill="none" stroke="#000080" stroke-width=".21"/>
<path d="M162.5 49.1v2.5" fill="none" stroke="#000080" stroke-width=".25"/>
<circle cx="162.5" cy="51.6" r=".51" fill="#000080"/>
<circle cx="162.5" cy="51.6" r=".51" fill="none" stroke="#000080" stroke-width=".21"/>
<path d="M271.9 41.4h-38.2v15.3" fill="none" stroke="#000080" stroke-width=".25"/>
<circle cx="251.5" cy="41.4" r=".51" fill="#000080"/>
<circle cx="251.5" cy="41.4" r=".51" fill="none" stroke="#000080" stroke-width=".21"/>
<circle cx="241.3" cy="41.4" r=".51" fill="#000080"/>
<circle cx="241.3" cy="41.4" r=".51" fill="none" stroke="#000080" stroke-width=".21"/>
<path d="M218.5 54.2v2.5" fill="none" stroke="#000080" stroke-width=".25"/>
<circle cx="218.4" cy="54.2" r=".51" fill="#000080"/>
<circle cx="218.4" cy="54.2" r=".51" fill="none" stroke="#000080" stroke-width=".21"/>
<path d="M226.1 56.7v-2.5h2.5v2.5" fill="none" stroke="#000080" stroke-width=".25"/>
<circle cx="226.1" cy="54.2" r=".51" fill="#000080"/>
<circle cx="226.1" cy="54.2" r=".51" fill="none" stroke="#000080" stroke-width=".21"/>
<path d="M215.9 56.7v-2.5h5.1v2.5" fill="none" stroke="#000080" stroke-width=".25"/>
<circle cx="218.4" cy="54.2" r=".51" fill="#000080"/>
<circle cx="218.4" cy="54.2" r=".51" fill="none" stroke="#000080" stroke-width=".21"/>
<circle cx="221" cy="54.2" r=".51" fill="#000080"/>
<circle cx="221" cy="54.2" r=".51" fill="none" stroke="#000080" stroke-width=".21"/>
<path d="M157.4 21.1h63.6v20.3" fill="none" stroke="#000080" stroke-width=".25"/>
<circle cx="221" cy="41.4" r=".51" fill="#000080"/>
<circle cx="221" cy="41.4" r=".51" fill="none" stroke="#000080" stroke-width=".21"/>
<circle cx="213.4" cy="21.1" r=".51" fill="#000080"/>
<circle cx="213.4" cy="21.1" r=".51" fill="none" stroke="#000080" stroke-width=".21"/>
<circle cx="203.2" cy="21.1" r=".51" fill="#000080"/>
<circle cx="203.2" cy="21.1" r=".51" fill="none" stroke="#000080" stroke-width=".21"/>
<circle cx="193" cy="21.1" r=".51" fill="#000080"/>
<circle cx="193" cy="21.1" r=".51" fill="none" stroke="#000080" stroke-width=".21"/>
<circle cx="182.8" cy="21.1" r=".51" fill="#000080"/>
<circle cx="182.8" cy="21.1" r=".51" fill="none" stroke="#000080" stroke-width=".21"/>
<circle cx="172.7" cy="21.1" r=".51" fill="#000080"/>
<circle cx="172.7" cy="21.1" r=".51" fill="none" stroke="#000080" stroke-width=".21"/>
<circle cx="162.5" cy="21.1" r=".51" fill="#000080"/>
<circle cx="162.5" cy="21.1" r=".51" fill="none" stroke="#000080" stroke-width=".21"/>
<path d="M157.4 41.4h35.6" fill="none" stroke="#000080" stroke-width=".25"/>
<circle cx="182.8" cy="41.4" r=".51" fill="#000080"/>
<circle cx="182.8" cy="41.4" r=".51" fill="none" stroke="#000080" stroke-width=".21"/>
<circle cx="193" cy="41.4" r=".51" fill="#000080"/>
<circle cx="193" cy="41.4" r=".51" fill="none" stroke="#000080" stroke-width=".21"/>
<path d="M180.3 87.2h12.7" fill="none" stroke="#000080" stroke-width=".25"/>
<circle cx="187.9" cy="87.2" r=".51" fill="#000080"/>
<circle cx="187.9" cy="87.2" r=".51" fill="none" stroke="#000080" stroke-width=".21"/>
<path d="M180.3 97.4h12.7" fill="none" stroke="#000080" stroke-width=".25"/>
<circle cx="187.9" cy="97.4" r=".51" fill="#000080"/>
<circle cx="187.9" cy="97.4" r=".51" fill="none" stroke="#000080" stroke-width=".21"/>
<path d="M180.3 102.5h12.7" fill="none" stroke="#000080" stroke-width=".25"/>
<circle cx="187.9" cy="102.5" r=".51" fill="#000080"/>
<circle cx="187.9" cy="102.5" r=".51" fill="none" stroke="#000080" stroke-width=".21"/>
<path d="M180.3 112.7h12.7" fill="none" stroke="#000080" stroke-width=".25"/>
<circle cx="187.9" cy="112.7" r=".51" fill="#000080"/>
<circle cx="187.9" cy="112.7" r=".51" fill="none" stroke="#000080" stroke-width=".21"/>
<path d="M180.3 117.8h12.7" fill="none" stroke="#000080" stroke-width=".25"/>
<circle cx="187.9" cy="117.8" r=".51" fill="#000080"/>
<circle cx="187.9" cy="117.8" r=".51" fill="none" stroke="#000080" stroke-width=".21"/>
<path d="M180.3 127.9h12.7" fill="none" stroke="#000080" stroke-width=".25"/>
<circle cx="187.9" cy="127.9" r=".51" fill="#000080"/>
<circle cx="187.9" cy="127.9" r=".51" fill="none" stroke="#000080" stroke-width=".21"/>
<path d="M180.3 133h12.7" fill="none" stroke="#000080" stroke-width=".25"/>
<circle cx="187.9" cy="133" r=".51" fill="#000080"/>
<circle cx="187.9" cy="133" r=".51" fill="none" stroke="#000080" stroke-width=".21"/>
<path d="M180.3 143.2h12.7" fill="none" stroke="#000080" stroke-width=".25"/>
<circle cx="187.9" cy="143.2" r=".51" fill="#000080"/>
<circle cx="187.9" cy="143.2" r=".51" fill="none" stroke="#000080" stroke-width=".21"/>
<g fill="none" stroke="#000080" stroke-width=".25">
<path d="M256.6 74.5h7.6M256.6 77.1h7.6M109.1 94.9v10.1h2.5M256.6 82.1h7.6M256.6 84.7h7.6M256.6 89.8h7.6M256.6 92.3h7.6M256.6 97.4h7.6M256.6 100h7.6M256.6 105.1h7.6M256.6 107.6h7.6M256.6 112.7h7.6"/>
<path d="M256.6 115.2h7.6M256.6 120.3h7.6M256.6 122.9h7.6M256.6 127.9h7.6M256.6 130.5h7.6M256.6 135.6h7.6M256.6 138.1h7.6M256.6 143.2h7.6M256.6 145.8h7.6"/>
</g>
<circle cx="109" cy="105" r=".51" fill="#000080"/>
<circle cx="109" cy="105" r=".51" fill="none" stroke="#000080" stroke-width=".21"/>
<circle cx="109" cy="94.9" r=".51" fill="#000080"/>
<circle cx="109" cy="94.9" r=".51" fill="none" stroke="#000080" stroke-width=".21"/>
<path d="M93.8 94.9h17.8M121.8 94.9h2.5M121.8 105h2.5" fill="none" stroke="#000080" stroke-width=".25"/>
<circle cx="93.8" cy="94.9" r=".51" fill="#000080"/>
<circle cx="93.8" cy="94.9" r=".51" fill="none" stroke="#000080" stroke-width=".21"/>
<circle cx="101.4" cy="94.9" r=".51" fill="#000080"/>
<circle cx="101.4" cy="94.9" r=".51" fill="none" stroke="#000080" stroke-width=".21"/>
<circle cx="106.5" cy="94.9" r=".51" fill="#000080"/>
<circle cx="106.5" cy="94.9" r=".51" fill="none" stroke="#000080" stroke-width=".21"/>
<circle cx="109" cy="94.9" r=".51" fill="#000080"/>
<circle cx="109" cy="94.9" r=".51" fill="none" stroke="#000080" stroke-width=".21"/>
<path d="M81.1 94.9h12.7" fill="none" stroke="#000080" stroke-width=".25"/>
<circle cx="93.8" cy="94.9" r=".51" fill="#000080"/>
<circle cx="93.8" cy="94.9" r=".51" fill="none" stroke="#000080" stroke-width=".21"/>
<path d="M101.4 94.9v2.5" fill="none" stroke="#000080" stroke-width=".25"/>
<circle cx="101.4" cy="94.9" r=".51" fill="#000080"/>
<circle cx="101.4" cy="94.9" r=".51" fill="none" stroke="#000080" stroke-width=".21"/>
<path d="M187.9 161v2.6" fill="none" stroke="#000080" stroke-width=".25"/>
<circle cx="187.9" cy="163.6" r=".51" fill="#000080"/>
<circle cx="187.9" cy="163.6" r=".51" fill="none" stroke="#000080" stroke-width=".21"/>
<path d="M187.9 148.3v2.5" fill="none" stroke="#000080" stroke-width=".25"/>
<circle cx="187.9" cy="148.3" r=".51" fill="#000080"/>
<circle cx="187.9" cy="148.3" r=".51" fill="none" stroke="#000080" stroke-width=".21"/>
<path d="M139.6 143.2h2.5v20.4" fill="none" stroke="#000080" stroke-width=".25"/>
<circle cx="142.1" cy="163.6" r=".51" fill="#000080"/>
<circle cx="142.1" cy="163.6" r=".51" fill="none" stroke="#000080" stroke-width=".21"/>
<path d="M147.2 143.2h-2.5v17.8" fill="none" stroke="#000080" stroke-width=".25"/>
<circle cx="144.7" cy="161" r=".51" fill="#000080"/>
<circle cx="144.7" cy="161" r=".51" fill="none" stroke="#000080" stroke-width=".21"/>
<path d="M129.4 77.1v2.5" fill="none" stroke="#000080" stroke-width=".25"/>
<circle cx="129.4" cy="77.1" r=".51" fill="#000080"/>
<circle cx="129.4" cy="77.1" r=".51" fill="none" stroke="#000080" stroke-width=".21"/>
<path d="M45.5 26.2v5.1h2.5M48 36.4h-2.5v5" fill="none" stroke="#000080" stroke-width=".25"/>
<circle cx="45.4" cy="26.2" r=".51" fill="#000080"/>
<circle cx="45.4" cy="26.2" r=".51" fill="none" stroke="#000080" stroke-width=".21"/>
<path d="M32.7 38.9v2.5M48 26.2h-15.3v2.5M78.5 26.2h2.6" fill="none" stroke="#000080" stroke-width=".25"/>
<circle cx="45.4" cy="26.2" r=".51" fill="#000080"/>
<circle cx="45.4" cy="26.2" r=".51" fill="none" stroke="#000080" stroke-width=".21"/>
<circle cx="32.7" cy="26.2" r=".51" fill="#000080"/>
<circle cx="32.7" cy="26.2" r=".51" fill="none" stroke="#000080" stroke-width=".21"/>
<path d="M114.1 38.9v2.5M119.2 23.6v2.6h-5.1" fill="none" stroke="#000080" stroke-width=".25"/>
<circle cx="114.1" cy="26.2" r=".51" fill="#000080"/>
<circle cx="114.1" cy="26.2" r=".51" fill="none" stroke="#000080" stroke-width=".21"/>
<path d="M106.5 26.2v2.5" fill="none" stroke="#000080" stroke-width=".25"/>
<circle cx="106.5" cy="26.2" r=".51" fill="#000080"/>
<circle cx="106.5" cy="26.2" r=".51" fill="none" stroke="#000080" stroke-width=".21"/>
<path d="M96.3 26.2h17.8v2.5" fill="none" stroke="#000080" stroke-width=".25"/>
<circle cx="98.9" cy="26.2" r=".51" fill="#000080"/>
<circle cx="98.9" cy="26.2" r=".51" fill="none" stroke="#000080" stroke-width=".21"/>
<circle cx="106.5" cy="26.2" r=".51" fill="#000080"/>
<circle cx="106.5" cy="26.2" r=".51" fill="none" stroke="#000080" stroke-width=".21"/>
<circle cx="114.1" cy="26.2" r=".51" fill="#000080"/>
<circle cx="114.1" cy="26.2" r=".51" fill="none" stroke="#000080" stroke-width=".21"/>
<path d="M98.9 26.2v2.5" fill="none" stroke="#000080" stroke-width=".25"/>
<circle cx="98.9" cy="26.2" r=".51" fill="#000080"/>
<circle cx="98.9" cy="26.2" r=".51" fill="none" stroke="#000080" stroke-width=".21"/>
<path d="M106.5 38.9v5.1M106.5 54.2v2.5" fill="none" stroke="#000080" stroke-width=".25"/>
<circle cx="106.5" cy="41.4" r=".51" fill="#000080"/>
<circle cx="106.5" cy="41.4" r=".51" fill="none" stroke="#000080" stroke-width=".21"/>
<path d="M78.5 31.3h10.2v10.1h17.8" fill="none" stroke="#000080" stroke-width=".25"/>
<circle cx="106.5" cy="41.4" r=".51" fill="#000080"/>
<circle cx="106.5" cy="41.4" r=".51" fill="none" stroke="#000080" stroke-width=".21"/>
<circle cx="98.9" cy="41.4" r=".51" fill="#000080"/>
<circle cx="98.9" cy="41.4" r=".51" fill="none" stroke="#000080" stroke-width=".21"/>
<path d="M98.9 38.9v2.5" fill="none" stroke="#000080" stroke-width=".25"/>
<circle cx="98.9" cy="41.4" r=".51" fill="#000080"/>
<circle cx="98.9" cy="41.4" r=".51" fill="none" stroke="#000080" stroke-width=".21"/>
<path d="M12.4 23.6v2.6h2.5" fill="none" stroke="#000080" stroke-width=".25"/>
<circle cx="12.4" cy="26.2" r=".51" fill="#000080"/>
<circle cx="12.4" cy="26.2" r=".51" fill="none" stroke="#000080" stroke-width=".21"/>
<path d="M25.1 26.2h7.6" fill="none" stroke="#000080" stroke-width=".25"/>
<circle cx="27.6" cy="26.2" r=".51" fill="#000080"/>
<circle cx="27.6" cy="26.2" r=".51" fill="none" stroke="#000080" stroke-width=".21"/>
<circle cx="32.7" cy="26.2" r=".51" fill="#000080"/>
<circle cx="32.7" cy="26.2" r=".51" fill="none" stroke="#000080" stroke-width=".21"/>
<path d="M12.4 92.3v2.6h2.5M27.6 107.6v2.5" fill="none" stroke="#000080" stroke-width=".25"/>
<circle cx="12.4" cy="94.9" r=".51" fill="#000080"/>
<circle cx="12.4" cy="94.9" r=".51" fill="none" stroke="#000080" stroke-width=".21"/>
<path d="M25.1 94.9h2.5" fill="none" stroke="#000080" stroke-width=".25"/>
<circle cx="27.6" cy="94.9" r=".51" fill="#000080"/>
<circle cx="27.6" cy="94.9" r=".51" fill="none" stroke="#000080" stroke-width=".21"/>
<path d="M27.6 94.9v2.5" fill="none" stroke="#000080" stroke-width=".25"/>
<circle cx="27.6" cy="94.9" r=".51" fill="#000080"/>
<circle cx="27.6" cy="94.9" r=".51" fill="none" stroke="#000080" stroke-width=".21"/>
<path d="M42.9 94.9v2.5h2.6" fill="none" stroke="#000080" stroke-width=".25"/>
<circle cx="42.9" cy="94.9" r=".51" fill="#000080"/>
<circle cx="42.9" cy="94.9" r=".51" fill="none" stroke="#000080" stroke-width=".21"/>
<path d="M27.6 94.9h17.9M81.1 102.5h2.5v7.6" fill="none" stroke="#000080" stroke-width=".25"/>
<circle cx="27.6" cy="94.9" r=".51" fill="#000080"/>
<circle cx="27.6" cy="94.9" r=".51" fill="none" stroke="#000080" stroke-width=".21"/>
<circle cx="30.2" cy="94.9" r=".51" fill="#000080"/>
<circle cx="30.2" cy="94.9" r=".51" fill="none" stroke="#000080" stroke-width=".21"/>
<circle cx="42.9" cy="94.9" r=".51" fill="#000080"/>
<circle cx="42.9" cy="94.9" r=".51" fill="none" stroke="#000080" stroke-width=".21"/>
<path d="M81.1 97.4h7.6v12.7h5.1v5.1" fill="none" stroke="#000080" stroke-width=".25"/>
<circle cx="93.8" cy="110.1" r=".51" fill="#000080"/>
<circle cx="93.8" cy="110.1" r=".51" fill="none" stroke="#000080" stroke-width=".21"/>
<path d="M45.5 102.5h-2.6v2.5" fill="none" stroke="#000080" stroke-width=".25"/>
<circle cx="42.9" cy="102.5" r=".51" fill="#000080"/>
<circle cx="42.9" cy="102.5" r=".51" fill="none" stroke="#000080" stroke-width=".21"/>
<path d="M37.8 102.5h5.1" fill="none" stroke="#000080" stroke-width=".25"/>
<circle cx="42.9" cy="102.5" r=".51" fill="#000080"/>
<circle cx="42.9" cy="102.5" r=".51" fill="none" stroke="#000080" stroke-width=".21"/>
<path d="M109.1 105v10.2h2.5M121.8 115.2h2.5" fill="none" stroke="#000080" stroke-width=".25"/>
<circle cx="109" cy="105" r=".51" fill="#000080"/>
<circle cx="109" cy="105" r=".51" fill="none" stroke="#000080" stroke-width=".21"/>
<path d="M162.5 64.3v7.7M63.3 161h12.7M63.3 163.6h12.7M63.3 168.6h12.7" fill="none" stroke="#000080" stroke-width=".25"/>
<circle cx="162.5" cy="72" r=".51" fill="#000080"/>
<circle cx="162.5" cy="72" r=".51" fill="none" stroke="#000080" stroke-width=".21"/>
<path d="M157.4 66.9h35.6M167.6 64.3v5.1h25.4M193 150.8v12.8h-38.2" fill="none" stroke="#000080" stroke-width=".25"/>
<circle cx="187.9" cy="163.6" r=".51" fill="#000080"/>
<circle cx="187.9" cy="163.6" r=".51" fill="none" stroke="#000080" stroke-width=".21"/>
<path d="M193 148.3h-7.6v12.7h-25.5" fill="none" stroke="#000080" stroke-width=".25"/>
<circle cx="187.9" cy="148.3" r=".51" fill="#000080"/>
<circle cx="187.9" cy="148.3" r=".51" fill="none" stroke="#000080" stroke-width=".21"/>
<path d="M116.7 163.6h28" fill="none" stroke="#000080" stroke-width=".25"/>
<circle cx="142.1" cy="163.6" r=".51" fill="#000080"/>
<circle cx="142.1" cy="163.6" r=".51" fill="none" stroke="#000080" stroke-width=".21"/>
<path d="M116.7 161h33.1" fill="none" stroke="#000080" stroke-width=".25"/>
<circle cx="144.7" cy="161" r=".51" fill="#000080"/>
<circle cx="144.7" cy="161" r=".51" fill="none" stroke="#000080" stroke-width=".21"/>
<path d="M126.9 77.1h66.1M116.7 168.6h7.6" fill="none" stroke="#000080" stroke-width=".25"/>
<circle cx="129.4" cy="77.1" r=".51" fill="#000080"/>
<circle cx="129.4" cy="77.1" r=".51" fill="none" stroke="#000080" stroke-width=".21"/>
<path d="M137 74.5v5.1" fill="none" stroke="#000080" stroke-width=".25"/>
<circle cx="137" cy="74.5" r=".51" fill="#000080"/>
<circle cx="137" cy="74.5" r=".51" fill="none" stroke="#000080" stroke-width=".21"/>
<path d="M126.9 74.5h66.1" fill="none" stroke="#000080" stroke-width=".25"/>
<circle cx="137" cy="74.5" r=".51" fill="#000080"/>
<circle cx="137" cy="74.5" r=".51" fill="none" stroke="#000080" stroke-width=".21"/>
<path d="M157.4 82.1v2.6M157.4 94.9v2.5" fill="none" stroke="#000080" stroke-width=".25"/>
<circle cx="157.4" cy="82.1" r=".51" fill="#000080"/>
<circle cx="157.4" cy="82.1" r=".51" fill="none" stroke="#000080" stroke-width=".21"/>
<path d="M126.9 72h66.1" fill="none" stroke="#000080" stroke-width=".25"/>
<circle cx="129.4" cy="72" r=".51" fill="#000080"/>
<circle cx="129.4" cy="72" r=".51" fill="none" stroke="#000080" stroke-width=".21"/>
<circle cx="162.5" cy="72" r=".51" fill="#000080"/>
<circle cx="162.5" cy="72" r=".51" fill="none" stroke="#000080" stroke-width=".21"/>
<path d="M129.4 64.3v7.7" fill="none" stroke="#000080" stroke-width=".25"/>
<circle cx="129.4" cy="72" r=".51" fill="#000080"/>
<circle cx="129.4" cy="72" r=".51" fill="none" stroke="#000080" stroke-width=".21"/>
<path d="M152.3 82.1h40.7" fill="none" stroke="#000080" stroke-width=".25"/>
<circle cx="157.4" cy="82.1" r=".51" fill="#000080"/>
<circle cx="157.4" cy="82.1" r=".51" fill="none" stroke="#000080" stroke-width=".21"/>
<use href="#words"/>
</svg>
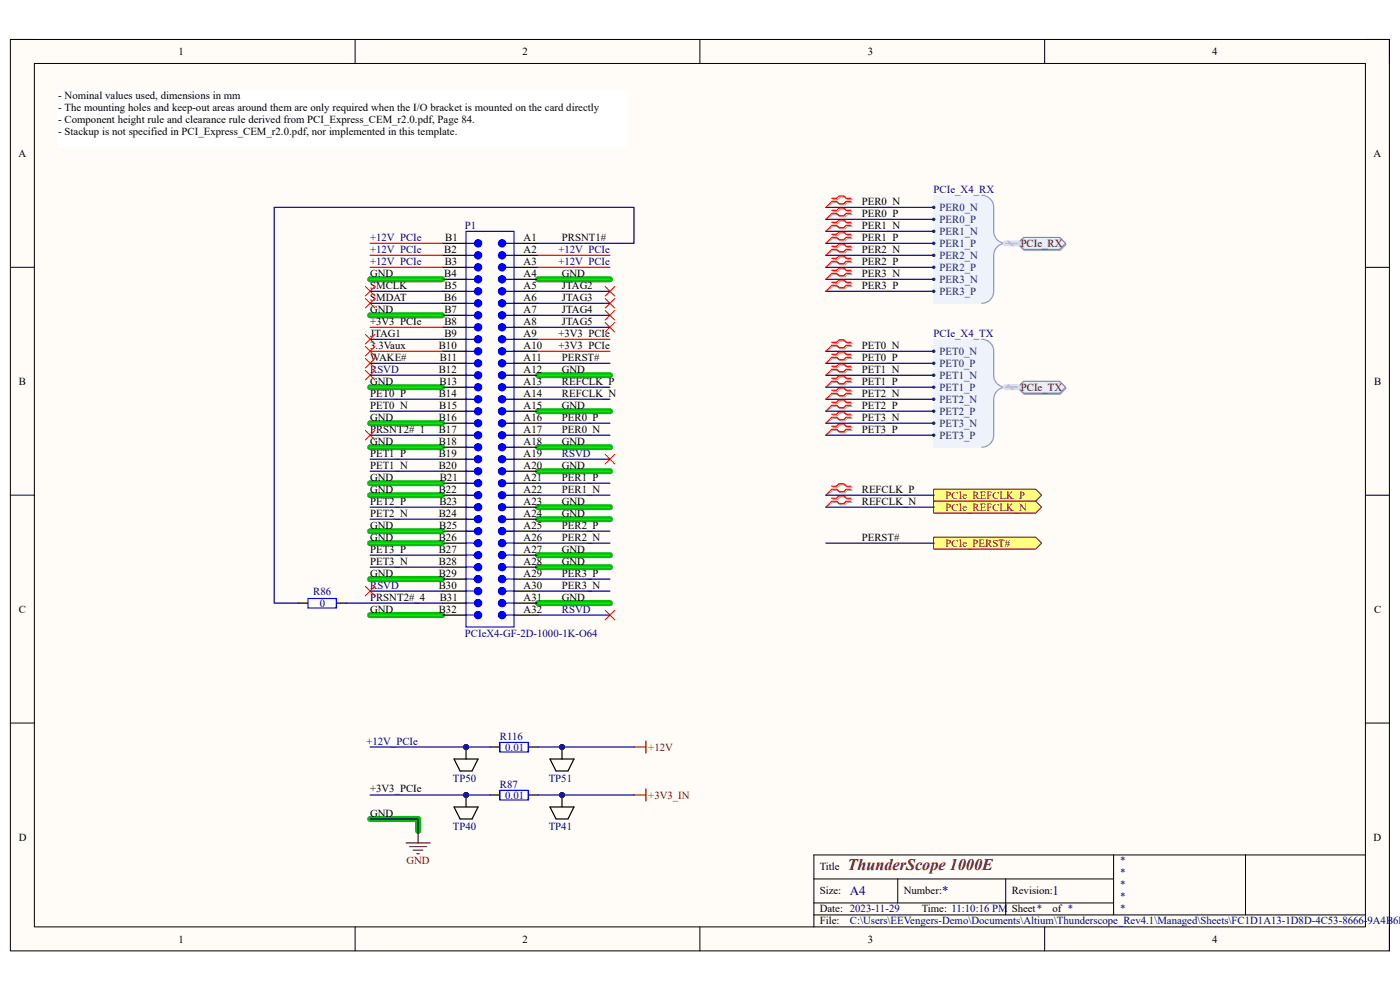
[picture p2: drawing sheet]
<svg xmlns="http://www.w3.org/2000/svg" width="297mm" height="210mm" viewBox="0 0 297 210" stroke-linecap="round" stroke-linejoin="round" font-family="sans-serif">
<defs><g id="words">
<text font-size="3.4" fill="#800000" x="179.8" y="184.7">ThunderScope 1000E</text>
<g font-size="2.8" fill="#000080">
<text x="180.3" y="189.9">A4</text>
<text x="199.9" y="189.9">*</text>
<text x="223.3" y="189.9">1</text>
</g>
<g font-size="2.3">
<text x="37.9" y="11.7">1</text>
<text x="110.9" y="11.7">2</text>
<text x="184.1" y="11.7">3</text>
<text x="257.1" y="11.7">4</text>
<text x="12.4" y="21.1">- Nominal values used, dimensions in mm</text>
<text x="12.4" y="23.6">- The mounting holes and keep-out areas around them are only required when the I/O bracket is mounted on the card directly</text>
<text x="12.4" y="26.2">- Component height rule and clearance rule derived from PCI_Express_CEM_r2.0.pdf, Page 84.</text>
<text x="12.4" y="28.7">- Stackup is not specified in PCI_Express_CEM_r2.0.pdf, nor implemented in this template.</text>
<text x="3.9" y="33.3">A</text>
<text x="291.4" y="33.3">A</text>
<text x="182.8" y="43.5">PER0_N</text>
<text x="182.8" y="46">PER0_P</text>
<text x="94.2" y="53.6">B2</text>
<text x="94.4" y="51.1">B1</text>
<text x="111.1" y="51.1">A1</text>
<text x="111.1" y="53.6">A2</text>
<text x="119.2" y="51.1">PRSNT1#</text>
<text x="182.8" y="48.6">PER1_N</text>
<text x="182.8" y="51.1">PER1_P</text>
<text x="182.8" y="53.6">PER2_N</text>
<text x="78.5" y="58.7">GND</text>
<text x="94.2" y="58.7">B4</text>
<text x="94.4" y="56.2">B3</text>
<text x="111.1" y="56.2">A3</text>
<text x="111.1" y="58.7">A4</text>
<text x="119.2" y="58.7">GND</text>
<text x="182.8" y="56.2">PER2_P</text>
<text x="182.8" y="58.7">PER3_N</text>
<text x="78.5" y="61.3">SMCLK</text>
<text x="78.5" y="63.8">SMDAT</text>
<text x="94.2" y="63.8">B6</text>
<text x="94.3" y="61.3">B5</text>
<text x="111.1" y="61.3">A5</text>
<text x="111.1" y="63.8">A6</text>
<text x="119.2" y="61.3">JTAG2</text>
<text x="119.2" y="63.8">JTAG3</text>
<text x="182.8" y="61.3">PER3_P</text>
<text x="78.5" y="66.4">GND</text>
<text x="78.5" y="71.5">JTAG1</text>
<text x="78.5" y="68.9">+3V3_PCIe</text>
<text x="94.3" y="66.4">B7</text>
<text x="94.3" y="68.9">B8</text>
<text x="94.3" y="71.5">B9</text>
<text x="111.1" y="66.4">A7</text>
<text x="111.1" y="68.9">A8</text>
<text x="111.1" y="71.5">A9</text>
<text x="118.5" y="71.5">+3V3_PCIe</text>
<text x="119.2" y="66.4">JTAG4</text>
<text x="119.2" y="68.9">JTAG5</text>
<text x="78.5" y="74">3.3Vaux</text>
<text x="78.5" y="76.5">WAKE#</text>
<text x="93.1" y="74">B10</text>
<text x="93.3" y="76.5">B11</text>
<text x="111.1" y="74">A10</text>
<text x="111.1" y="76.5">A11</text>
<text x="118.5" y="74">+3V3_PCIe</text>
<text x="119.2" y="76.5">PERST#</text>
<text x="182.8" y="74">PET0_N</text>
<text x="182.8" y="76.5">PET0_P</text>
<text x="4" y="81.6">B</text>
<text x="78.5" y="81.6">GND</text>
<text x="93.1" y="79.1">B12</text>
<text x="93.2" y="81.6">B13</text>
<text x="111.1" y="79.1">A12</text>
<text x="111.1" y="81.6">A13</text>
<text x="119.2" y="79.1">GND</text>
<text x="119.2" y="81.6">REFCLK_P</text>
<text x="182.8" y="79.1">PET1_N</text>
<text x="182.8" y="81.6">PET1_P</text>
<text x="291.5" y="81.6">B</text>
<text x="78.5" y="84.2">PET0_P</text>
<text x="78.5" y="86.7">PET0_N</text>
<text x="78.5" y="89.3">GND</text>
<text x="93.1" y="84.2">B14</text>
<text x="93.1" y="89.3">B16</text>
<text x="93.2" y="86.7">B15</text>
<text x="111.1" y="84.2">A14</text>
<text x="111.1" y="86.7">A15</text>
<text x="111.1" y="89.3">A16</text>
<text x="119.2" y="86.7">GND</text>
<text x="119.2" y="89.3">PER0_P</text>
<text x="119.2" y="84.2">REFCLK_N</text>
<text x="182.8" y="84.2">PET2_N</text>
<text x="182.8" y="86.7">PET2_P</text>
<text x="182.8" y="89.3">PET3_N</text>
<text x="78.5" y="91.8">PRSNT2#_1</text>
<text x="78.5" y="94.4">GND</text>
<text x="93.1" y="91.8">B17</text>
<text x="93.1" y="94.4">B18</text>
<text x="111.1" y="91.8">A17</text>
<text x="111.1" y="94.4">A18</text>
<text x="119.2" y="91.8">PER0_N</text>
<text x="119.2" y="94.4">GND</text>
<text x="182.8" y="91.8">PET3_P</text>
<text x="78.5" y="96.9">PET1_P</text>
<text x="78.5" y="99.4">PET1_N</text>
<text x="78.5" y="102">GND</text>
<text x="93.1" y="96.9">B19</text>
<text x="93.1" y="99.4">B20</text>
<text x="93.3" y="102">B21</text>
<text x="111.1" y="96.9">A19</text>
<text x="111.1" y="99.4">A20</text>
<text x="111.1" y="102">A21</text>
<text x="119.2" y="99.4">GND</text>
<text x="119.2" y="102">PER1_P</text>
<text x="78.5" y="104.5">GND</text>
<text x="78.5" y="107.1">PET2_P</text>
<text x="93.1" y="104.5">B22</text>
<text x="93.2" y="107.1">B23</text>
<text x="111.1" y="104.5">A22</text>
<text x="111.1" y="107.1">A23</text>
<text x="119.2" y="104.5">PER1_N</text>
<text x="119.2" y="107.1">GND</text>
<text x="182.8" y="107.1">REFCLK_N</text>
<text x="182.8" y="104.5">REFCLK_P</text>
<text x="78.5" y="109.6">PET2_N</text>
<text x="78.5" y="112.1">GND</text>
<text x="93.1" y="109.6">B24</text>
<text x="93.2" y="112.1">B25</text>
<text x="111.1" y="109.6">A24</text>
<text x="111.1" y="112.1">A25</text>
<text x="119.2" y="109.6">GND</text>
<text x="119.2" y="112.1">PER2_P</text>
<text x="78.5" y="114.7">GND</text>
<text x="78.5" y="117.3">PET3_P</text>
<text x="78.5" y="119.8">PET3_N</text>
<text x="93.1" y="114.7">B26</text>
<text x="93.1" y="117.3">B27</text>
<text x="93.1" y="119.8">B28</text>
<text x="111.1" y="114.7">A26</text>
<text x="111.1" y="117.3">A27</text>
<text x="111.1" y="119.8">A28</text>
<text x="119.2" y="114.7">PER2_N</text>
<text x="119.2" y="117.3">GND</text>
<text x="119.2" y="119.8">GND</text>
<text x="182.8" y="114.7">PERST#</text>
<text x="78.5" y="122.3">GND</text>
<text x="93.1" y="122.3">B29</text>
<text x="93.1" y="124.9">B30</text>
<text x="111.1" y="122.3">A29</text>
<text x="111.1" y="124.9">A30</text>
<text x="119.2" y="122.3">PER3_P</text>
<text x="119.2" y="124.9">PER3_N</text>
<text x="4" y="130">C</text>
<text x="78.5" y="127.4">PRSNT2#_4</text>
<text x="78.5" y="130">GND</text>
<text x="93.1" y="130">B32</text>
<text x="93.3" y="127.4">B31</text>
<text x="111.1" y="127.4">A31</text>
<text x="111.1" y="130">A32</text>
<text x="119.2" y="127.4">GND</text>
<text x="291.5" y="130">C</text>
<text x="78.5" y="173.2">GND</text>
<text x="78.5" y="168.1">+3V3_PCIe</text>
<text x="4" y="178.3">D</text>
<text x="291.4" y="178.3">D</text>
<text x="173.9" y="184.7">Title</text>
<text x="173.9" y="189.7">Size:</text>
<text x="191.7" y="189.7">Number:</text>
<text x="214.6" y="189.7">Revision:</text>
<text x="173.9" y="193.5">Date: 2023-11-29</text>
<text x="173.9" y="196.1">File:</text>
<text x="195.5" y="193.5">Time: 11:10:16 PM</text>
<text x="214.6" y="193.5">Sheet*</text>
<text x="223.3" y="193.5">of *</text>
<text x="37.9" y="199.9">1</text>
<text x="110.9" y="199.9">2</text>
<text x="184.1" y="199.9">3</text>
<text x="257.1" y="199.9">4</text>
</g>
<g font-size="2.3" fill="#000080">
<text x="198.1" y="40.9">PCIe_X4_RX</text>
<text x="78.5" y="51.1">+12V_PCIe</text>
<text x="78.5" y="53.6">+12V_PCIe</text>
<text x="98.6" y="48.6">P1</text>
<text x="118.5" y="53.6">+12V_PCIe</text>
<text x="78.5" y="56.2">+12V_PCIe</text>
<text x="118.5" y="56.2">+12V_PCIe</text>
<text x="198.1" y="71.5">PCIe_X4_TX</text>
<text x="78.5" y="79.1">RSVD</text>
<text x="119.2" y="96.9">RSVD</text>
<text x="78.5" y="124.9">RSVD</text>
<text x="66.5" y="126.2">R86</text>
<text x="67.8" y="128.7">0</text>
<text x="119.2" y="130">RSVD</text>
<text x="98.6" y="135">PCIeX4-GF-2D-1000-1K-O64</text>
<text x="77.8" y="157.9">+12V_PCIe</text>
<text x="106" y="157">R116</text>
<text x="107.2" y="159.2">0.01</text>
<text x="96.1" y="165.8">TP50</text>
<text x="106" y="167.1">R87</text>
<text x="116.4" y="165.8">TP51</text>
<text x="107.2" y="169.4">0.01</text>
<text x="96.1" y="176">TP40</text>
<text x="116.4" y="176">TP41</text>
<text x="237.5" y="183.4">*</text>
<text x="237.5" y="185.9">*</text>
<text x="237.5" y="188.5">*</text>
<text x="237.5" y="191">*</text>
<text x="180.3" y="196.1">C:\Users\EEVengers-Demo\Documents\Altium\Thunderscope_Rev4.1\Managed\Sheets\FC1D1A13-1D8D-4C53-8666-9A4B6D</text>
<text x="237.5" y="193.5">*</text>
</g>
<g font-size="2.3" fill="#003a70">
<text x="199.3" y="44.7">PER0_N</text>
<text x="199.3" y="47.3">PER0_P</text>
<text x="199.3" y="49.8">PER1_N</text>
<text x="199.3" y="52.4">PER1_P</text>
<text x="199.3" y="54.9">PER2_N</text>
<text x="199.3" y="57.4">PER2_P</text>
<text x="199.3" y="60">PER3_N</text>
<text x="199.3" y="62.6">PER3_P</text>
<text x="199.3" y="75.3">PET0_N</text>
<text x="199.3" y="77.8">PET0_P</text>
<text x="199.3" y="80.3">PET1_N</text>
<text x="199.3" y="82.9">PET1_P</text>
<text x="199.3" y="85.4">PET2_N</text>
<text x="199.3" y="88">PET2_P</text>
<text x="199.3" y="90.6">PET3_N</text>
<text x="199.3" y="93.1">PET3_P</text>
</g>
<g font-size="2.3" fill="#800000">
<text x="216.5" y="52.4">PCIe_RX</text>
<text x="216.6" y="82.9">PCIe_TX</text>
<text x="200.6" y="105.8">PCIe_REFCLK_P</text>
<text x="200.6" y="108.3">PCIe_REFCLK_N</text>
<text x="200.6" y="116">PCIe_PERST#</text>
<text x="137.5" y="159.2">+12V</text>
<text x="137.5" y="169.4">+3V3_IN</text>
<text x="86.2" y="183.4">GND</text>
</g>
</g></defs>
<path d="M2.2 8.4h292.6v193.3h-292.6z" fill-rule="evenodd" fill="#fffcf8"/>
<path d="M2.2 8.4h292.6v193.3h-292.6z" fill="none" stroke="#000" stroke-width=".21"/>
<path d="M7.3 13.5h282.4v183.1h-282.4z" fill-rule="evenodd" fill="#fffcf8"/>
<g fill="none" stroke="#000" stroke-width=".21">
<path d="M2.2 8.4h5.1M7.3 13.5h282.4v183.1h-282.4zM75.3 8.4v5.1M148.5 8.4v5.1M221.6 8.4v5.1M289.7 8.4h5.1v5.1M2.2 56.7h5.1M289.7 56.7h5.1M2.2 105h5.1M289.7 105.1h5.1M2.2 153.4h5.1M289.7 153.4h5.1"/>
<path d="M75.3 196.6v5.1M148.5 196.6v5.1M172.7 186.5h63.6M172.7 194.1h117M172.7 191.5h63.6M190.5 186.5v5M213.4 186.5v7.6M221.6 196.6v5.1M236.3 181.4v12.7M264.2 181.4v12.7M289.7 181.4h-117v15.2M294.8 196.6v5.1"/>
</g>
<g fill="none" stroke="#00be00" stroke-width="1.3">
<path d="M78.5 59.3h15.3M114.1 59.3h15.3M78.5 66.9h15.3M114.1 79.6h15.3M78.5 94.9h15.3M78.5 82.1h15.3M78.5 89.8h15.3M114.1 87.2h15.3M114.1 94.9h15.3M114.1 100h15.3M78.5 102.5h15.3M78.5 105h15.3"/>
<path d="M78.5 112.7h15.3M78.5 115.2h15.3M114.1 107.6h15.3M114.1 110.1h15.3M114.1 117.8h15.3M78.5 122.9h15.3M78.5 130.5h15.3M114.1 120.3h15.3M114.1 127.9h15.3M78.5 173.7h10.2v2.6"/>
</g>
<path d="M77.5 78.6l2 2M79.5 78.6l-2 2M128.4 96.4l2 2M130.4 96.4l-2 2M77.5 124.4l2 2M79.5 124.4l-2 2M128.4 129.5l2 2M130.4 129.5l-2 2" fill="none" stroke="#f00" stroke-width=".21"/>
<path d="M98.9 49.1h10.2v83.9h-10.2zM107.3 51.6h1.8" fill="none" stroke="#00f" stroke-width=".25"/>
<path d="M109.1 51.6h5" fill="none" stroke="#000" stroke-width=".25"/>
<circle cx="106.5" cy="51.6" r=".76" fill="#00f"/>
<g fill="none" stroke="#00f" stroke-width=".25">
<path d="M98.9 51.6h1.8"/>
<circle cx="106.5" cy="51.6" r=".76"/>
</g>
<circle cx="101.4" cy="51.6" r=".76" fill="#00f"/>
<g fill="none" stroke="#00f" stroke-width=".25">
<path d="M107.3 54.2h1.8"/>
<circle cx="101.4" cy="51.6" r=".76"/>
</g>
<circle cx="106.5" cy="54.2" r=".76" fill="#00f"/>
<g fill="none" stroke="#00f" stroke-width=".25">
<path d="M98.9 54.2h1.8"/>
<circle cx="106.5" cy="54.2" r=".76"/>
</g>
<circle cx="101.4" cy="54.2" r=".76" fill="#00f"/>
<g fill="none" stroke="#00f" stroke-width=".25">
<path d="M107.3 56.7h1.8"/>
<circle cx="101.4" cy="54.2" r=".76"/>
</g>
<circle cx="106.5" cy="56.7" r=".76" fill="#00f"/>
<g fill="none" stroke="#00f" stroke-width=".25">
<path d="M98.9 56.7h1.8"/>
<circle cx="106.5" cy="56.7" r=".76"/>
</g>
<circle cx="101.4" cy="56.7" r=".76" fill="#00f"/>
<g fill="none" stroke="#00f" stroke-width=".25">
<path d="M107.3 59.3h1.8"/>
<circle cx="101.4" cy="56.7" r=".76"/>
</g>
<circle cx="106.5" cy="59.3" r=".76" fill="#00f"/>
<g fill="none" stroke="#00f" stroke-width=".25">
<path d="M98.9 59.3h1.8"/>
<circle cx="106.5" cy="59.3" r=".76"/>
</g>
<circle cx="101.4" cy="59.3" r=".76" fill="#00f"/>
<g fill="none" stroke="#00f" stroke-width=".25">
<path d="M107.3 61.8h1.8"/>
<circle cx="101.4" cy="59.3" r=".76"/>
</g>
<circle cx="106.5" cy="61.8" r=".76" fill="#00f"/>
<g fill="none" stroke="#00f" stroke-width=".25">
<path d="M98.9 61.8h1.8"/>
<circle cx="106.5" cy="61.8" r=".76"/>
</g>
<circle cx="101.4" cy="61.8" r=".76" fill="#00f"/>
<g fill="none" stroke="#00f" stroke-width=".25">
<path d="M107.3 64.3h1.8"/>
<circle cx="101.4" cy="61.8" r=".76"/>
</g>
<circle cx="106.5" cy="64.3" r=".76" fill="#00f"/>
<g fill="none" stroke="#00f" stroke-width=".25">
<path d="M98.9 64.3h1.8"/>
<circle cx="106.5" cy="64.3" r=".76"/>
</g>
<circle cx="101.4" cy="64.3" r=".76" fill="#00f"/>
<g fill="none" stroke="#00f" stroke-width=".25">
<path d="M107.3 66.9h1.8"/>
<circle cx="101.4" cy="64.3" r=".76"/>
</g>
<circle cx="106.5" cy="66.9" r=".76" fill="#00f"/>
<g fill="none" stroke="#00f" stroke-width=".25">
<path d="M98.9 66.9h1.8"/>
<circle cx="106.5" cy="66.9" r=".76"/>
</g>
<circle cx="101.4" cy="66.9" r=".76" fill="#00f"/>
<g fill="none" stroke="#00f" stroke-width=".25">
<path d="M107.3 69.4h1.8"/>
<circle cx="101.4" cy="66.9" r=".76"/>
</g>
<circle cx="106.5" cy="69.4" r=".76" fill="#00f"/>
<g fill="none" stroke="#00f" stroke-width=".25">
<path d="M98.9 69.4h1.8"/>
<circle cx="106.5" cy="69.4" r=".76"/>
</g>
<circle cx="101.4" cy="69.4" r=".76" fill="#00f"/>
<g fill="none" stroke="#00f" stroke-width=".25">
<path d="M107.3 72h1.8"/>
<circle cx="101.4" cy="69.4" r=".76"/>
</g>
<circle cx="106.5" cy="72" r=".76" fill="#00f"/>
<g fill="none" stroke="#00f" stroke-width=".25">
<path d="M98.9 72h1.8"/>
<circle cx="106.5" cy="72" r=".76"/>
</g>
<circle cx="101.4" cy="72" r=".76" fill="#00f"/>
<g fill="none" stroke="#00f" stroke-width=".25">
<path d="M107.3 74.5h1.8"/>
<circle cx="101.4" cy="72" r=".76"/>
</g>
<circle cx="106.5" cy="74.5" r=".76" fill="#00f"/>
<g fill="none" stroke="#00f" stroke-width=".25">
<path d="M98.9 74.5h1.8"/>
<circle cx="106.5" cy="74.5" r=".76"/>
</g>
<circle cx="101.4" cy="74.5" r=".76" fill="#00f"/>
<g fill="none" stroke="#00f" stroke-width=".25">
<path d="M107.3 77.1h1.8"/>
<circle cx="101.4" cy="74.5" r=".76"/>
</g>
<circle cx="106.5" cy="77.1" r=".76" fill="#00f"/>
<g fill="none" stroke="#00f" stroke-width=".25">
<path d="M98.9 77.1h1.8"/>
<circle cx="106.5" cy="77.1" r=".76"/>
</g>
<circle cx="101.4" cy="77.1" r=".76" fill="#00f"/>
<g fill="none" stroke="#00f" stroke-width=".25">
<path d="M107.3 79.6h1.8"/>
<circle cx="101.4" cy="77.1" r=".76"/>
</g>
<circle cx="106.5" cy="79.6" r=".76" fill="#00f"/>
<g fill="none" stroke="#00f" stroke-width=".25">
<path d="M98.9 79.6h1.8"/>
<circle cx="106.5" cy="79.6" r=".76"/>
</g>
<circle cx="101.4" cy="79.6" r=".76" fill="#00f"/>
<g fill="none" stroke="#00f" stroke-width=".25">
<path d="M107.3 82.1h1.8"/>
<circle cx="101.4" cy="79.6" r=".76"/>
</g>
<circle cx="106.5" cy="82.1" r=".76" fill="#00f"/>
<g fill="none" stroke="#00f" stroke-width=".25">
<path d="M98.9 82.1h1.8"/>
<circle cx="106.5" cy="82.1" r=".76"/>
</g>
<circle cx="101.4" cy="82.1" r=".76" fill="#00f"/>
<g fill="none" stroke="#00f" stroke-width=".25">
<path d="M107.3 84.7h1.8"/>
<circle cx="101.4" cy="82.1" r=".76"/>
</g>
<circle cx="106.5" cy="84.7" r=".76" fill="#00f"/>
<g fill="none" stroke="#00f" stroke-width=".25">
<path d="M98.9 84.7h1.8"/>
<circle cx="106.5" cy="84.7" r=".76"/>
</g>
<circle cx="101.4" cy="84.7" r=".76" fill="#00f"/>
<g fill="none" stroke="#00f" stroke-width=".25">
<path d="M107.3 87.2h1.8"/>
<circle cx="101.4" cy="84.7" r=".76"/>
</g>
<circle cx="106.5" cy="87.2" r=".76" fill="#00f"/>
<g fill="none" stroke="#00f" stroke-width=".25">
<path d="M98.9 87.2h1.8"/>
<circle cx="106.5" cy="87.2" r=".76"/>
</g>
<circle cx="101.4" cy="87.2" r=".76" fill="#00f"/>
<g fill="none" stroke="#00f" stroke-width=".25">
<path d="M107.3 89.8h1.8"/>
<circle cx="101.4" cy="87.2" r=".76"/>
</g>
<circle cx="106.5" cy="89.8" r=".76" fill="#00f"/>
<g fill="none" stroke="#00f" stroke-width=".25">
<path d="M98.9 89.8h1.8"/>
<circle cx="106.5" cy="89.8" r=".76"/>
</g>
<circle cx="101.4" cy="89.8" r=".76" fill="#00f"/>
<g fill="none" stroke="#00f" stroke-width=".25">
<path d="M107.3 92.3h1.8"/>
<circle cx="101.4" cy="89.8" r=".76"/>
</g>
<circle cx="106.5" cy="92.3" r=".76" fill="#00f"/>
<g fill="none" stroke="#00f" stroke-width=".25">
<path d="M98.9 92.3h1.8"/>
<circle cx="106.5" cy="92.3" r=".76"/>
</g>
<circle cx="101.4" cy="92.3" r=".76" fill="#00f"/>
<g fill="none" stroke="#00f" stroke-width=".25">
<path d="M107.3 94.9h1.8"/>
<circle cx="101.4" cy="92.3" r=".76"/>
</g>
<circle cx="106.5" cy="94.9" r=".76" fill="#00f"/>
<g fill="none" stroke="#00f" stroke-width=".25">
<path d="M98.9 94.9h1.8"/>
<circle cx="106.5" cy="94.9" r=".76"/>
</g>
<circle cx="101.4" cy="94.9" r=".76" fill="#00f"/>
<g fill="none" stroke="#00f" stroke-width=".25">
<path d="M107.3 97.4h1.8"/>
<circle cx="101.4" cy="94.9" r=".76"/>
</g>
<g fill="none" stroke="#000" stroke-width=".25">
<path d="M93.8 54.2h5.1M93.8 56.7h5.1M93.8 59.3h5.1M93.8 51.6h5.1M109.1 54.2h5M109.1 56.7h5M109.1 59.3h5M93.8 61.8h5.1M93.8 64.3h5.1M93.8 66.9h5.1M93.8 69.4h5.1M93.8 72h5.1"/>
<path d="M93.8 74.5h5.1M93.8 77.1h5.1M93.8 79.6h5.1M109.1 61.8h5M109.1 64.3h5M109.1 66.9h5M109.1 69.4h5M109.1 72h5M109.1 74.5h5M109.1 77.1h5M109.1 79.6h5M93.8 82.1h5.1"/>
<path d="M93.8 84.7h5.1M93.8 87.2h5.1M93.8 89.8h5.1M93.8 92.3h5.1M93.8 94.9h5.1M109.1 82.1h5M109.1 84.7h5M109.1 87.2h5M109.1 89.8h5M109.1 92.3h5M109.1 94.9h5"/>
</g>
<circle cx="106.5" cy="97.4" r=".76" fill="#00f"/>
<g fill="none" stroke="#00f" stroke-width=".25">
<path d="M98.9 97.4h1.8"/>
<circle cx="106.5" cy="97.4" r=".76"/>
</g>
<circle cx="101.4" cy="97.4" r=".76" fill="#00f"/>
<g fill="none" stroke="#00f" stroke-width=".25">
<path d="M107.3 100h1.8"/>
<circle cx="101.4" cy="97.4" r=".76"/>
</g>
<circle cx="106.5" cy="100" r=".76" fill="#00f"/>
<g fill="none" stroke="#00f" stroke-width=".25">
<path d="M98.9 100h1.8"/>
<circle cx="106.5" cy="100" r=".76"/>
</g>
<circle cx="101.4" cy="100" r=".76" fill="#00f"/>
<g fill="none" stroke="#00f" stroke-width=".25">
<path d="M107.3 102.5h1.8"/>
<circle cx="101.4" cy="100" r=".76"/>
</g>
<circle cx="106.5" cy="102.5" r=".76" fill="#00f"/>
<g fill="none" stroke="#00f" stroke-width=".25">
<path d="M98.9 102.5h1.8"/>
<circle cx="106.5" cy="102.5" r=".76"/>
</g>
<circle cx="101.4" cy="102.5" r=".76" fill="#00f"/>
<g fill="none" stroke="#00f" stroke-width=".25">
<path d="M107.3 105h1.8"/>
<circle cx="101.4" cy="102.5" r=".76"/>
</g>
<circle cx="106.5" cy="105" r=".76" fill="#00f"/>
<g fill="none" stroke="#00f" stroke-width=".25">
<path d="M98.9 105h1.8"/>
<circle cx="106.5" cy="105" r=".76"/>
</g>
<circle cx="101.4" cy="105" r=".76" fill="#00f"/>
<g fill="none" stroke="#00f" stroke-width=".25">
<path d="M107.3 107.6h1.8"/>
<circle cx="101.4" cy="105" r=".76"/>
</g>
<circle cx="106.5" cy="107.6" r=".76" fill="#00f"/>
<g fill="none" stroke="#00f" stroke-width=".25">
<path d="M98.9 107.6h1.8"/>
<circle cx="106.5" cy="107.6" r=".76"/>
</g>
<circle cx="101.4" cy="107.6" r=".76" fill="#00f"/>
<g fill="none" stroke="#00f" stroke-width=".25">
<path d="M107.3 110.1h1.8"/>
<circle cx="101.4" cy="107.6" r=".76"/>
</g>
<circle cx="106.5" cy="110.1" r=".76" fill="#00f"/>
<g fill="none" stroke="#00f" stroke-width=".25">
<path d="M98.9 110.1h1.8"/>
<circle cx="106.5" cy="110.1" r=".76"/>
</g>
<circle cx="101.4" cy="110.1" r=".76" fill="#00f"/>
<g fill="none" stroke="#00f" stroke-width=".25">
<path d="M107.3 112.7h1.8"/>
<circle cx="101.4" cy="110.1" r=".76"/>
</g>
<circle cx="106.5" cy="112.7" r=".76" fill="#00f"/>
<g fill="none" stroke="#00f" stroke-width=".25">
<path d="M98.9 112.7h1.8"/>
<circle cx="106.5" cy="112.7" r=".76"/>
</g>
<circle cx="101.4" cy="112.7" r=".76" fill="#00f"/>
<g fill="none" stroke="#00f" stroke-width=".25">
<path d="M107.3 115.2h1.8"/>
<circle cx="101.4" cy="112.7" r=".76"/>
</g>
<circle cx="106.5" cy="115.2" r=".76" fill="#00f"/>
<g fill="none" stroke="#00f" stroke-width=".25">
<path d="M98.9 115.2h1.8"/>
<circle cx="106.5" cy="115.2" r=".76"/>
</g>
<circle cx="101.4" cy="115.2" r=".76" fill="#00f"/>
<g fill="none" stroke="#00f" stroke-width=".25">
<path d="M107.3 117.8h1.8"/>
<circle cx="101.4" cy="115.2" r=".76"/>
</g>
<circle cx="106.5" cy="117.8" r=".76" fill="#00f"/>
<g fill="none" stroke="#00f" stroke-width=".25">
<path d="M98.9 117.8h1.8"/>
<circle cx="106.5" cy="117.8" r=".76"/>
</g>
<circle cx="101.4" cy="117.8" r=".76" fill="#00f"/>
<g fill="none" stroke="#00f" stroke-width=".25">
<path d="M107.3 120.3h1.8"/>
<circle cx="101.4" cy="117.8" r=".76"/>
</g>
<circle cx="106.5" cy="120.3" r=".76" fill="#00f"/>
<g fill="none" stroke="#00f" stroke-width=".25">
<path d="M98.9 120.3h1.8"/>
<circle cx="106.5" cy="120.3" r=".76"/>
</g>
<circle cx="101.4" cy="120.3" r=".76" fill="#00f"/>
<g fill="none" stroke="#00f" stroke-width=".25">
<path d="M107.3 122.9h1.8"/>
<circle cx="101.4" cy="120.3" r=".76"/>
</g>
<circle cx="106.5" cy="122.9" r=".76" fill="#00f"/>
<g fill="none" stroke="#00f" stroke-width=".25">
<path d="M98.9 122.9h1.8"/>
<circle cx="106.5" cy="122.9" r=".76"/>
</g>
<circle cx="101.4" cy="122.9" r=".76" fill="#00f"/>
<g fill="none" stroke="#00f" stroke-width=".25">
<path d="M107.3 125.4h1.8"/>
<circle cx="101.4" cy="122.9" r=".76"/>
</g>
<circle cx="106.5" cy="125.4" r=".76" fill="#00f"/>
<g fill="none" stroke="#00f" stroke-width=".25">
<path d="M98.9 125.4h1.8"/>
<circle cx="106.5" cy="125.4" r=".76"/>
</g>
<circle cx="101.4" cy="125.4" r=".76" fill="#00f"/>
<g fill="none" stroke="#00f" stroke-width=".25">
<path d="M107.3 127.9h1.8"/>
<circle cx="101.4" cy="125.4" r=".76"/>
</g>
<circle cx="106.5" cy="127.9" r=".76" fill="#00f"/>
<g fill="none" stroke="#00f" stroke-width=".25">
<path d="M98.9 127.9h1.8"/>
<circle cx="106.5" cy="127.9" r=".76"/>
</g>
<circle cx="101.4" cy="127.9" r=".76" fill="#00f"/>
<g fill="none" stroke="#00f" stroke-width=".25">
<path d="M107.3 130.5h1.8"/>
<circle cx="101.4" cy="127.9" r=".76"/>
</g>
<circle cx="106.5" cy="130.5" r=".76" fill="#00f"/>
<g fill="none" stroke="#00f" stroke-width=".25">
<path d="M98.9 130.5h1.8"/>
<circle cx="106.5" cy="130.5" r=".76"/>
</g>
<circle cx="101.4" cy="130.5" r=".76" fill="#00f"/>
<circle cx="101.4" cy="130.5" r=".76" fill="none" stroke="#00f" stroke-width=".25"/>
<g fill="none" stroke="#000" stroke-width=".25">
<path d="M93.8 97.4h5.1M93.8 100h5.1M109.1 97.4h5M109.1 100h5M93.8 102.5h5.1M93.8 105h5.1M93.8 107.6h5.1M93.8 110.1h5.1M93.8 112.7h5.1M93.8 115.2h5.1M93.8 117.8h5.1M109.1 102.5h5"/>
<path d="M109.1 105h5M109.1 107.6h5M109.1 110.1h5M109.1 112.7h5M109.1 115.2h5M109.1 117.8h5M93.8 120.3h5.1M93.8 122.9h5.1M93.8 125.4h5.1M93.8 127.9h5.1M93.8 130.5h5.1M109.1 120.3h5"/>
<path d="M109.1 122.9h5M109.1 125.4h5M109.1 127.9h5M109.1 130.5h5"/>
</g>
<path d="M86.2 178.8h5M86.9 179.6h3.6M88.7 176.3v2.5M134.5 168.6h2.5M137 167.4v2.5M87.7 180.4h2M88.4 181.1h.6" fill="none" stroke="#800000" stroke-width=".25"/>
<path d="M12.4 19.1h120.7v12.2h-120.7z" fill-rule="evenodd" fill="#fff"/>
<path d="M12.4 19.1h120.7v12.2h-120.7z" fill="none" stroke="#fff" stroke-width=".21"/>
<g fill="none" stroke="#f00" stroke-width=".21">
<path d="M77.5 71l2 2M77.5 73.5l2 2M77.5 60.8l2 2M77.5 63.3l2 2.1M77.5 76l2 2.1M79.5 71l-2 2M79.5 73.5l-2 2M79.5 60.8l-2 2M79.5 63.3l-2 2.1M79.5 76l-2 2.1M128.4 60.8l2 2M128.4 63.3l2 2.1"/>
<path d="M128.4 65.9l2 2M128.4 68.4l2 2M130.4 60.8l-2 2M130.4 63.3l-2 2.1M130.4 65.9l-2 2M130.4 68.4l-2 2"/>
</g>
<path d="M63.3 127.9h2M71.4 127.9h2" fill="none" stroke="#000" stroke-width=".25"/>
<path d="M65.3 127h6.1v2h-6.1z" fill="none" stroke="#00f" stroke-width=".25"/>
<path d="M198.1 103.8h21.6l1.3 1.3-1.3 1.2h-21.6z" fill-rule="evenodd" fill="#ffff80"/>
<path d="M198.1 103.8h21.6l1.3 1.3-1.3 1.2h-21.6z" fill="none" stroke="#800000" stroke-width=".21"/>
<path d="M198.1 106.3h21.6l1.3 1.3-1.3 1.3h-21.6z" fill-rule="evenodd" fill="#ffff80"/>
<path d="M198.1 106.3h21.6l1.3 1.3-1.3 1.3h-21.6z" fill="none" stroke="#800000" stroke-width=".21"/>
<path d="M198.1 114h21.6l1.3 1.2-1.3 1.3h-21.6z" fill-rule="evenodd" fill="#ffff80"/>
<path d="M198.1 114h21.6l1.3 1.2-1.3 1.3h-21.6z" fill="none" stroke="#800000" stroke-width=".21"/>
<path d="M104 168.6h2M112.1 168.6h2" fill="none" stroke="#000" stroke-width=".25"/>
<path d="M106 167.7h6.1v2h-6.1z" fill="none" stroke="#00f" stroke-width=".25"/>
<circle cx="98.9" cy="168.6" r=".51" fill="#000080"/>
<circle cx="98.9" cy="168.6" r=".51" fill="none" stroke="#000080" stroke-width=".21"/>
<path d="M98.9 168.6v2.6" fill="none" stroke="#000" stroke-width=".25"/>
<circle cx="98.9" cy="168.6" r=".51" fill="#000080"/>
<circle cx="98.9" cy="168.6" r=".51" fill="none" stroke="#000080" stroke-width=".21"/>
<path d="M96.3 171.2h5.1l-1.2 2.5h-2.6z" fill="none" stroke="#000" stroke-width=".25"/>
<circle cx="119.2" cy="168.6" r=".51" fill="#000080"/>
<circle cx="119.2" cy="168.6" r=".51" fill="none" stroke="#000080" stroke-width=".21"/>
<path d="M119.2 168.6v2.6" fill="none" stroke="#000" stroke-width=".25"/>
<circle cx="119.2" cy="168.6" r=".51" fill="#000080"/>
<circle cx="119.2" cy="168.6" r=".51" fill="none" stroke="#000080" stroke-width=".21"/>
<path d="M116.7 171.2h5.1l-1.3 2.5h-2.5z" fill="none" stroke="#000" stroke-width=".25"/>
<path d="M198.1 41.4h10.2l1.2 .4 1 .9 .3 1.3v5.7l.6 1.1 1.3 .8-1.3 .9-.6 1v8.3l-.3 1.3-1 .9-1.2 .3h-10.2z" fill-rule="evenodd" fill="#edf2fb"/>
<path d="M198.1 41.4h10.2l1.2 .4 1 .9 .3 1.3v5.7l.6 1.1 1.3 .8-1.3 .9-.6 1v8.3l-.3 1.3-1 .9-1.2 .3h-10.2z" fill="none" stroke="#edf2fb" stroke-width=".21"/>
<path d="M208.3 41.4a2.54 2.54 0 0 1 2.5 2.6v5.1a2.55 2.55 0 0 0 2.6 2.5 2.54 2.54 0 0 0-2.6 2.6v7.6a2.54 2.54 0 0 1-2.5 2.5" fill="none" stroke="#8f9ec9" stroke-width=".25"/>
<circle cx="198.1" cy="44" r=".26" fill="#003a70"/>
<circle cx="198.1" cy="44" r=".26" fill="none" stroke="#003a70" stroke-width=".21"/>
<circle cx="198.1" cy="46.5" r=".26" fill="#003a70"/>
<circle cx="198.1" cy="46.5" r=".26" fill="none" stroke="#003a70" stroke-width=".21"/>
<circle cx="198.1" cy="49.1" r=".26" fill="#003a70"/>
<circle cx="198.1" cy="49.1" r=".26" fill="none" stroke="#003a70" stroke-width=".21"/>
<circle cx="198.1" cy="51.6" r=".26" fill="#003a70"/>
<circle cx="198.1" cy="51.6" r=".26" fill="none" stroke="#003a70" stroke-width=".21"/>
<circle cx="198.1" cy="54.2" r=".26" fill="#003a70"/>
<circle cx="198.1" cy="54.2" r=".26" fill="none" stroke="#003a70" stroke-width=".21"/>
<circle cx="198.1" cy="56.7" r=".26" fill="#003a70"/>
<circle cx="198.1" cy="56.7" r=".26" fill="none" stroke="#003a70" stroke-width=".21"/>
<circle cx="198.1" cy="59.3" r=".26" fill="#003a70"/>
<circle cx="198.1" cy="59.3" r=".26" fill="none" stroke="#003a70" stroke-width=".21"/>
<circle cx="198.1" cy="61.8" r=".26" fill="#003a70"/>
<circle cx="198.1" cy="61.8" r=".26" fill="none" stroke="#003a70" stroke-width=".21"/>
<path d="M198.1 72h10.2l1.2 .3 1 1 .3 1.2v5.8l.6 1 1.3 .9-1.3 .8-.6 1.1v8.2l-.3 1.3-1 1-1.2 .3h-10.2z" fill-rule="evenodd" fill="#edf2fb"/>
<path d="M198.1 72h10.2l1.2 .3 1 1 .3 1.2v5.8l.6 1 1.3 .9-1.3 .8-.6 1.1v8.2l-.3 1.3-1 1-1.2 .3h-10.2z" fill="none" stroke="#edf2fb" stroke-width=".21"/>
<path d="M208.3 72a2.53 2.53 0 0 1 2.5 2.5v5.1a2.54 2.54 0 0 0 2.6 2.5 2.55 2.55 0 0 0-2.6 2.6v7.6a2.53 2.53 0 0 1-2.5 2.6" fill="none" stroke="#8f9ec9" stroke-width=".25"/>
<circle cx="198.1" cy="74.5" r=".26" fill="#003a70"/>
<circle cx="198.1" cy="74.5" r=".26" fill="none" stroke="#003a70" stroke-width=".21"/>
<circle cx="198.1" cy="77.1" r=".26" fill="#003a70"/>
<circle cx="198.1" cy="77.1" r=".26" fill="none" stroke="#003a70" stroke-width=".21"/>
<circle cx="198.1" cy="79.6" r=".26" fill="#003a70"/>
<circle cx="198.1" cy="79.6" r=".26" fill="none" stroke="#003a70" stroke-width=".21"/>
<circle cx="198.1" cy="82.1" r=".26" fill="#003a70"/>
<circle cx="198.1" cy="82.1" r=".26" fill="none" stroke="#003a70" stroke-width=".21"/>
<circle cx="198.1" cy="84.7" r=".26" fill="#003a70"/>
<circle cx="198.1" cy="84.7" r=".26" fill="none" stroke="#003a70" stroke-width=".21"/>
<circle cx="198.1" cy="87.2" r=".26" fill="#003a70"/>
<circle cx="198.1" cy="87.2" r=".26" fill="none" stroke="#003a70" stroke-width=".21"/>
<circle cx="198.1" cy="89.8" r=".26" fill="#003a70"/>
<circle cx="198.1" cy="89.8" r=".26" fill="none" stroke="#003a70" stroke-width=".21"/>
<circle cx="198.1" cy="92.3" r=".26" fill="#003a70"/>
<circle cx="198.1" cy="92.3" r=".26" fill="none" stroke="#003a70" stroke-width=".21"/>
<path d="M216 51.9l1.3-1.3h7.6l1.3 1.3-1.3 1.2h-7.6z" fill-rule="evenodd" fill="#bac0ca"/>
<path d="M216 51.9l1.3-1.3h7.6l1.3 1.3-1.3 1.2h-7.6z" fill="none" stroke="#a6acb6" stroke-width=".21"/>
<path d="M215.9 51.6l1.3-1.2h7.6l1.3 1.2-1.3 1.3h-7.6z" fill-rule="evenodd" fill="#d5e4ff"/>
<path d="M215.9 51.6l1.3-1.2h7.6l1.3 1.2-1.3 1.3h-7.6z" fill="none" stroke="#71809b" stroke-width=".21"/>
<path d="M216 82.4l1.3-1.3h7.6l1.3 1.3-1.3 1.3h-7.6z" fill-rule="evenodd" fill="#bac0ca"/>
<path d="M216 82.4l1.3-1.3h7.6l1.3 1.3-1.3 1.3h-7.6z" fill="none" stroke="#a6acb6" stroke-width=".21"/>
<path d="M217.2 80.9h7.6l1.3 1.2-1.3 1.3h-7.6l-1.3-1.3z" fill-rule="evenodd" fill="#d5e4ff"/>
<path d="M217.2 80.9h7.6l1.3 1.2-1.3 1.3h-7.6l-1.3-1.3z" fill="none" stroke="#71809b" stroke-width=".21"/>
<g fill="none" stroke="#f00" stroke-width=".21">
<path d="M176.5 42.7l-1.3 1.3M176.5 45.3l-1.3 1.2M176.5 47.8l-1.3 1.3M176.5 50.4l-1.3 1.2M176.5 52.9l-1.3 1.3M176.5 55.4l-1.3 1.3M176.5 58l-1.3 1.3M176.5 60.5l-1.3 1.3M176.5 73.2l-1.3 1.3M176.5 75.8l-1.3 1.3M176.5 78.3l-1.3 1.3M77.5 91.3l2 2"/>
<path d="M79.5 91.3l-2 2M176.5 80.9l-1.3 1.2M176.5 83.4l-1.3 1.3M176.5 86l-1.3 1.2M176.5 88.5l-1.3 1.3M176.5 91.1l-1.3 1.2M176.5 103.8l-1.3 1.3M176.5 106.3l-1.3 1.3"/>
</g>
<g fill="none" stroke="#d0a19e" stroke-width=".25">
<path d="M176.7 42.3h1l.6-.5h1l.5 .5h1M176.7 43h1l.6 .5h1l.5-.5h1M176.7 44.9h1l.6-.5h1l.5 .5h1M176.7 45.5h1l.6 .5h1l.5-.5h1M176.7 47.4h1l.6-.5h1l.5 .5h1M176.7 48.1h1l.6 .5h1l.5-.5h1M176.7 50h1l.6-.5h1l.5 .5h1M176.7 50.6h1l.6 .5h1l.5-.5h1M176.7 52.5h1l.6-.5h1l.5 .5h1M176.7 53.1h1l.6 .6h1l.5-.6h1M176.7 55.1h1l.6-.6h1l.5 .6h1M176.7 55.7h1l.6 .5h1l.5-.5h1"/>
<path d="M176.7 57.6h1l.6-.5h1l.5 .5h1M176.7 58.2h1l.6 .5h1l.5-.5h1M176.7 60.1h1l.6-.5h1l.5 .5h1M176.7 60.8h1l.6 .5h1l.5-.5h1M176.7 72.9h1l.6-.5h1l.5 .5h1M176.7 73.5h1l.6 .5h1l.5-.5h1M176.7 75.4h1l.6-.5h1l.5 .5h1M176.7 76h1l.6 .6h1l.5-.6h1M176.7 78h1l.6-.6h1l.5 .6h1M176.7 78.6h1l.6 .5h1l.5-.5h1M176.7 80.5h1l.6-.5h1l.5 .5h1M176.7 81.1h1l.6 .5h1l.5-.5h1"/>
<path d="M176.7 83h1l.6-.5h1l.5 .5h1M176.7 83.7h1l.6 .5h1l.5-.5h1M176.7 85.6h1l.6-.5h1l.5 .5h1M176.7 86.2h1l.6 .5h1l.5-.5h1M176.7 88.1h1l.6-.5h1l.5 .5h1M176.7 88.8h1l.6 .5h1l.5-.5h1M176.7 90.7h1l.6-.5h1l.5 .5h1M176.7 91.3h1l.6 .5h1l.5-.5h1M176.7 103.4h1l.6-.5h1l.5 .5h1M176.7 104h1l.6 .5h1l.5-.5h1M176.7 105.9h1l.6-.5h1l.5 .5h1M176.7 106.6h1l.6 .5h1l.5-.5h1"/>
</g>
<g fill="none" stroke="#d0a19e" stroke-width=".21">
<path d="M176.7 43l-1.5 1M176.7 45.5l-1.5 1M176.7 48.1l-1.5 1M176.7 50.6l-1.5 1M176.7 53.1l-1.5 1.1M176.7 55.7l-1.5 1M176.7 58.2l-1.5 1.1M176.7 60.8l-1.5 1M176.7 73.5l-1.5 1M176.7 76l-1.5 1.1M176.7 78.6l-1.5 1M176.7 81.1l-1.5 1"/>
<path d="M176.7 83.7l-1.5 1M176.7 86.2l-1.5 1M176.7 88.8l-1.5 1M176.7 91.3l-1.5 1M176.7 104l-1.5 1.1M176.7 106.6l-1.5 1"/>
</g>
<g fill="none" stroke="#f00" stroke-width=".25">
<path d="M78.5 54.2h15.3M78.5 56.7h15.3M78.5 51.6h15.3M114.1 54.2h15.3M114.1 56.7h15.3M176.5 42.1h1l.5-.5h1l.5 .5h1M176.5 42.7h1l.5 .5h1l.5-.5h1M176.5 44.6h1l.5-.5h1l.5 .5h1M176.5 45.3h1l.5 .5h1l.5-.5h1M176.5 47.2h1l.5-.5h1l.5 .5h1M176.5 47.8h1l.5 .5h1l.5-.5h1M176.5 49.7h1l.5-.5h1l.5 .5h1"/>
<path d="M176.5 50.4h1l.5 .5h1l.5-.5h1M176.5 52.3h1l.5-.5h1l.5 .5h1M176.5 52.9h1l.5 .5h1l.5-.5h1M176.5 54.8h1l.5-.5h1l.5 .5h1M176.5 55.4h1l.5 .5h1l.5-.5h1M176.5 57.4h1l.5-.6h1l.5 .6h1M176.5 58h1l.5 .5h1l.5-.5h1M176.5 59.9h1l.5-.5h1l.5 .5h1M78.5 74.5h15.3M78.5 69.4h15.3M114.1 72h15.3M114.1 74.5h15.3"/>
<path d="M176.5 60.5h1l.5 .5h1l.5-.5h1M176.5 72.6h1l.5-.5h1l.5 .5h1M176.5 73.2h1l.5 .6h1l.5-.6h1M176.5 75.2h1l.5-.6h1l.5 .6h1M176.5 75.8h1l.5 .5h1l.5-.5h1M176.5 77.7h1l.5-.5h1l.5 .5h1M176.5 78.3h1l.5 .5h1l.5-.5h1M176.5 80.2h1l.5-.5h1l.5 .5h1M176.5 80.9h1l.5 .5h1l.5-.5h1M176.5 82.8h1l.5-.5h1l.5 .5h1M176.5 83.4h1l.5 .5h1l.5-.5h1M176.5 85.3h1l.5-.5h1l.5 .5h1"/>
<path d="M176.5 86h1l.5 .5h1l.5-.5h1M176.5 87.9h1l.5-.5h1l.5 .5h1M176.5 88.5h1l.5 .5h1l.5-.5h1M176.5 90.4h1l.5-.5h1l.5 .5h1M176.5 91.1h1l.5 .5h1l.5-.5h1M176.5 103.1h1l.5-.5h1l.5 .5h1M176.5 103.8h1l.5 .5h1l.5-.5h1M176.5 105.7h1l.5-.5h1l.5 .5h1M176.5 106.3h1l.5 .5h1l.5-.5h1"/>
</g>
<path d="M134.5 158.5h2.5M137 157.2v2.5" fill="none" stroke="#800000" stroke-width=".25"/>
<g fill="none" stroke="#0f0" stroke-width=".25">
<path d="M78.5 59.3h15.3M114.1 59.3h15.3M78.5 66.9h15.3M114.1 79.6h15.3M78.5 94.9h15.3M78.5 82.1h15.3M78.5 89.8h15.3M114.1 87.2h15.3M114.1 94.9h15.3M114.1 100h15.3M78.5 102.5h15.3M78.5 105h15.3"/>
<path d="M78.5 112.7h15.3M78.5 115.2h15.3M114.1 107.6h15.3M114.1 110.1h15.3M114.1 117.8h15.3M78.5 122.9h15.3M78.5 130.5h15.3M114.1 120.3h15.3M114.1 127.9h15.3"/>
</g>
<g fill="none" stroke="#000080" stroke-width=".25">
<path d="M175.2 44h22.9M175.2 46.5h22.9M175.2 49.1h22.9M175.2 51.6h22.9M175.2 54.2h22.9M175.2 56.7h22.9M175.2 59.3h22.9M78.5 61.8h15.3M78.5 64.3h15.3M78.5 77.1h15.3M78.5 72h15.3M78.5 79.6h15.3"/>
<path d="M114.1 61.8h15.3M114.1 64.3h15.3M114.1 66.9h15.3M114.1 69.4h15.3M114.1 77.1h15.3M175.2 61.8h22.9M175.2 77.1h22.9M175.2 79.6h22.9M175.2 74.5h22.9M78.5 84.7h15.3M78.5 97.4h15.3M78.5 87.2h15.3"/>
<path d="M78.5 100h15.3M114.1 82.1h15.3M114.1 84.7h15.3M114.1 89.8h15.3M114.1 92.3h15.3M114.1 97.4h15.3M175.2 82.1h22.9M175.2 84.7h22.9M175.2 89.8h22.9M175.2 92.3h22.9M175.2 87.2h22.9M78.5 107.6h15.3"/>
<path d="M78.5 110.1h15.3M78.5 117.8h15.3M114.1 102.5h15.3M114.1 105h15.3M114.1 112.7h15.3M114.1 115.2h15.3M175.2 105.1h22.9M175.2 115.2h22.9M175.2 107.6h22.9M78.5 125.4h15.3M78.5 120.3h15.3M114.1 122.9h15.3"/>
<path d="M114.1 125.4h15.3M114.1 130.5h15.3M78.5 168.6h25.5M78.5 173.7h10.2v2.6"/>
</g>
<circle cx="98.9" cy="168.6" r=".51" fill="#000080"/>
<circle cx="98.9" cy="168.6" r=".51" fill="none" stroke="#000080" stroke-width=".21"/>
<path d="M78.5 92.3h15.3M73.4 127.9h20.4M114.1 168.6h20.4" fill="none" stroke="#000080" stroke-width=".25"/>
<circle cx="119.2" cy="168.6" r=".51" fill="#000080"/>
<circle cx="119.2" cy="168.6" r=".51" fill="none" stroke="#000080" stroke-width=".21"/>
<path d="M114.1 51.6h20.4v-7.6h-76.3v83.9h5.1" fill="none" stroke="#000080" stroke-width=".25"/>
<path d="M213.4 51.6h2.5M213.4 82.1h2.5" fill="none" stroke="#cbdaff" stroke-width="1.3"/>
<path d="M213.9 51.2l1 .9M213.9 81.7l1 .9" fill="none" stroke="#adbce7" stroke-width=".38"/>
<path d="M213.4 51.6h2.5M213.4 82.1h2.5" fill="none" stroke="#adbce7" stroke-width=".25"/>
<path d="M104 158.5h2M112.1 158.5h2" fill="none" stroke="#000" stroke-width=".25"/>
<path d="M106 157.5h6.1v2h-6.1z" fill="none" stroke="#00f" stroke-width=".25"/>
<circle cx="98.9" cy="158.5" r=".51" fill="#000080"/>
<circle cx="98.9" cy="158.5" r=".51" fill="none" stroke="#000080" stroke-width=".21"/>
<path d="M98.9 158.5v2.5" fill="none" stroke="#000" stroke-width=".25"/>
<circle cx="98.9" cy="158.5" r=".51" fill="#000080"/>
<circle cx="98.9" cy="158.5" r=".51" fill="none" stroke="#000080" stroke-width=".21"/>
<path d="M96.3 161h5.1l-1.3 2.6h-2.5z" fill="none" stroke="#000" stroke-width=".25"/>
<circle cx="119.2" cy="158.5" r=".51" fill="#000080"/>
<circle cx="119.2" cy="158.5" r=".51" fill="none" stroke="#000080" stroke-width=".21"/>
<path d="M119.2 158.5v2.5" fill="none" stroke="#000" stroke-width=".25"/>
<circle cx="119.2" cy="158.5" r=".51" fill="#000080"/>
<circle cx="119.2" cy="158.5" r=".51" fill="none" stroke="#000080" stroke-width=".21"/>
<path d="M116.7 161h5.1l-1.3 2.6h-2.5z" fill="none" stroke="#000" stroke-width=".25"/>
<path d="M78.5 158.5h25.5" fill="none" stroke="#000080" stroke-width=".25"/>
<circle cx="98.9" cy="158.5" r=".51" fill="#000080"/>
<circle cx="98.9" cy="158.5" r=".51" fill="none" stroke="#000080" stroke-width=".21"/>
<path d="M114.1 158.5h20.4" fill="none" stroke="#000080" stroke-width=".25"/>
<circle cx="119.2" cy="158.5" r=".51" fill="#000080"/>
<circle cx="119.2" cy="158.5" r=".51" fill="none" stroke="#000080" stroke-width=".21"/>
<use href="#words"/>
</svg>
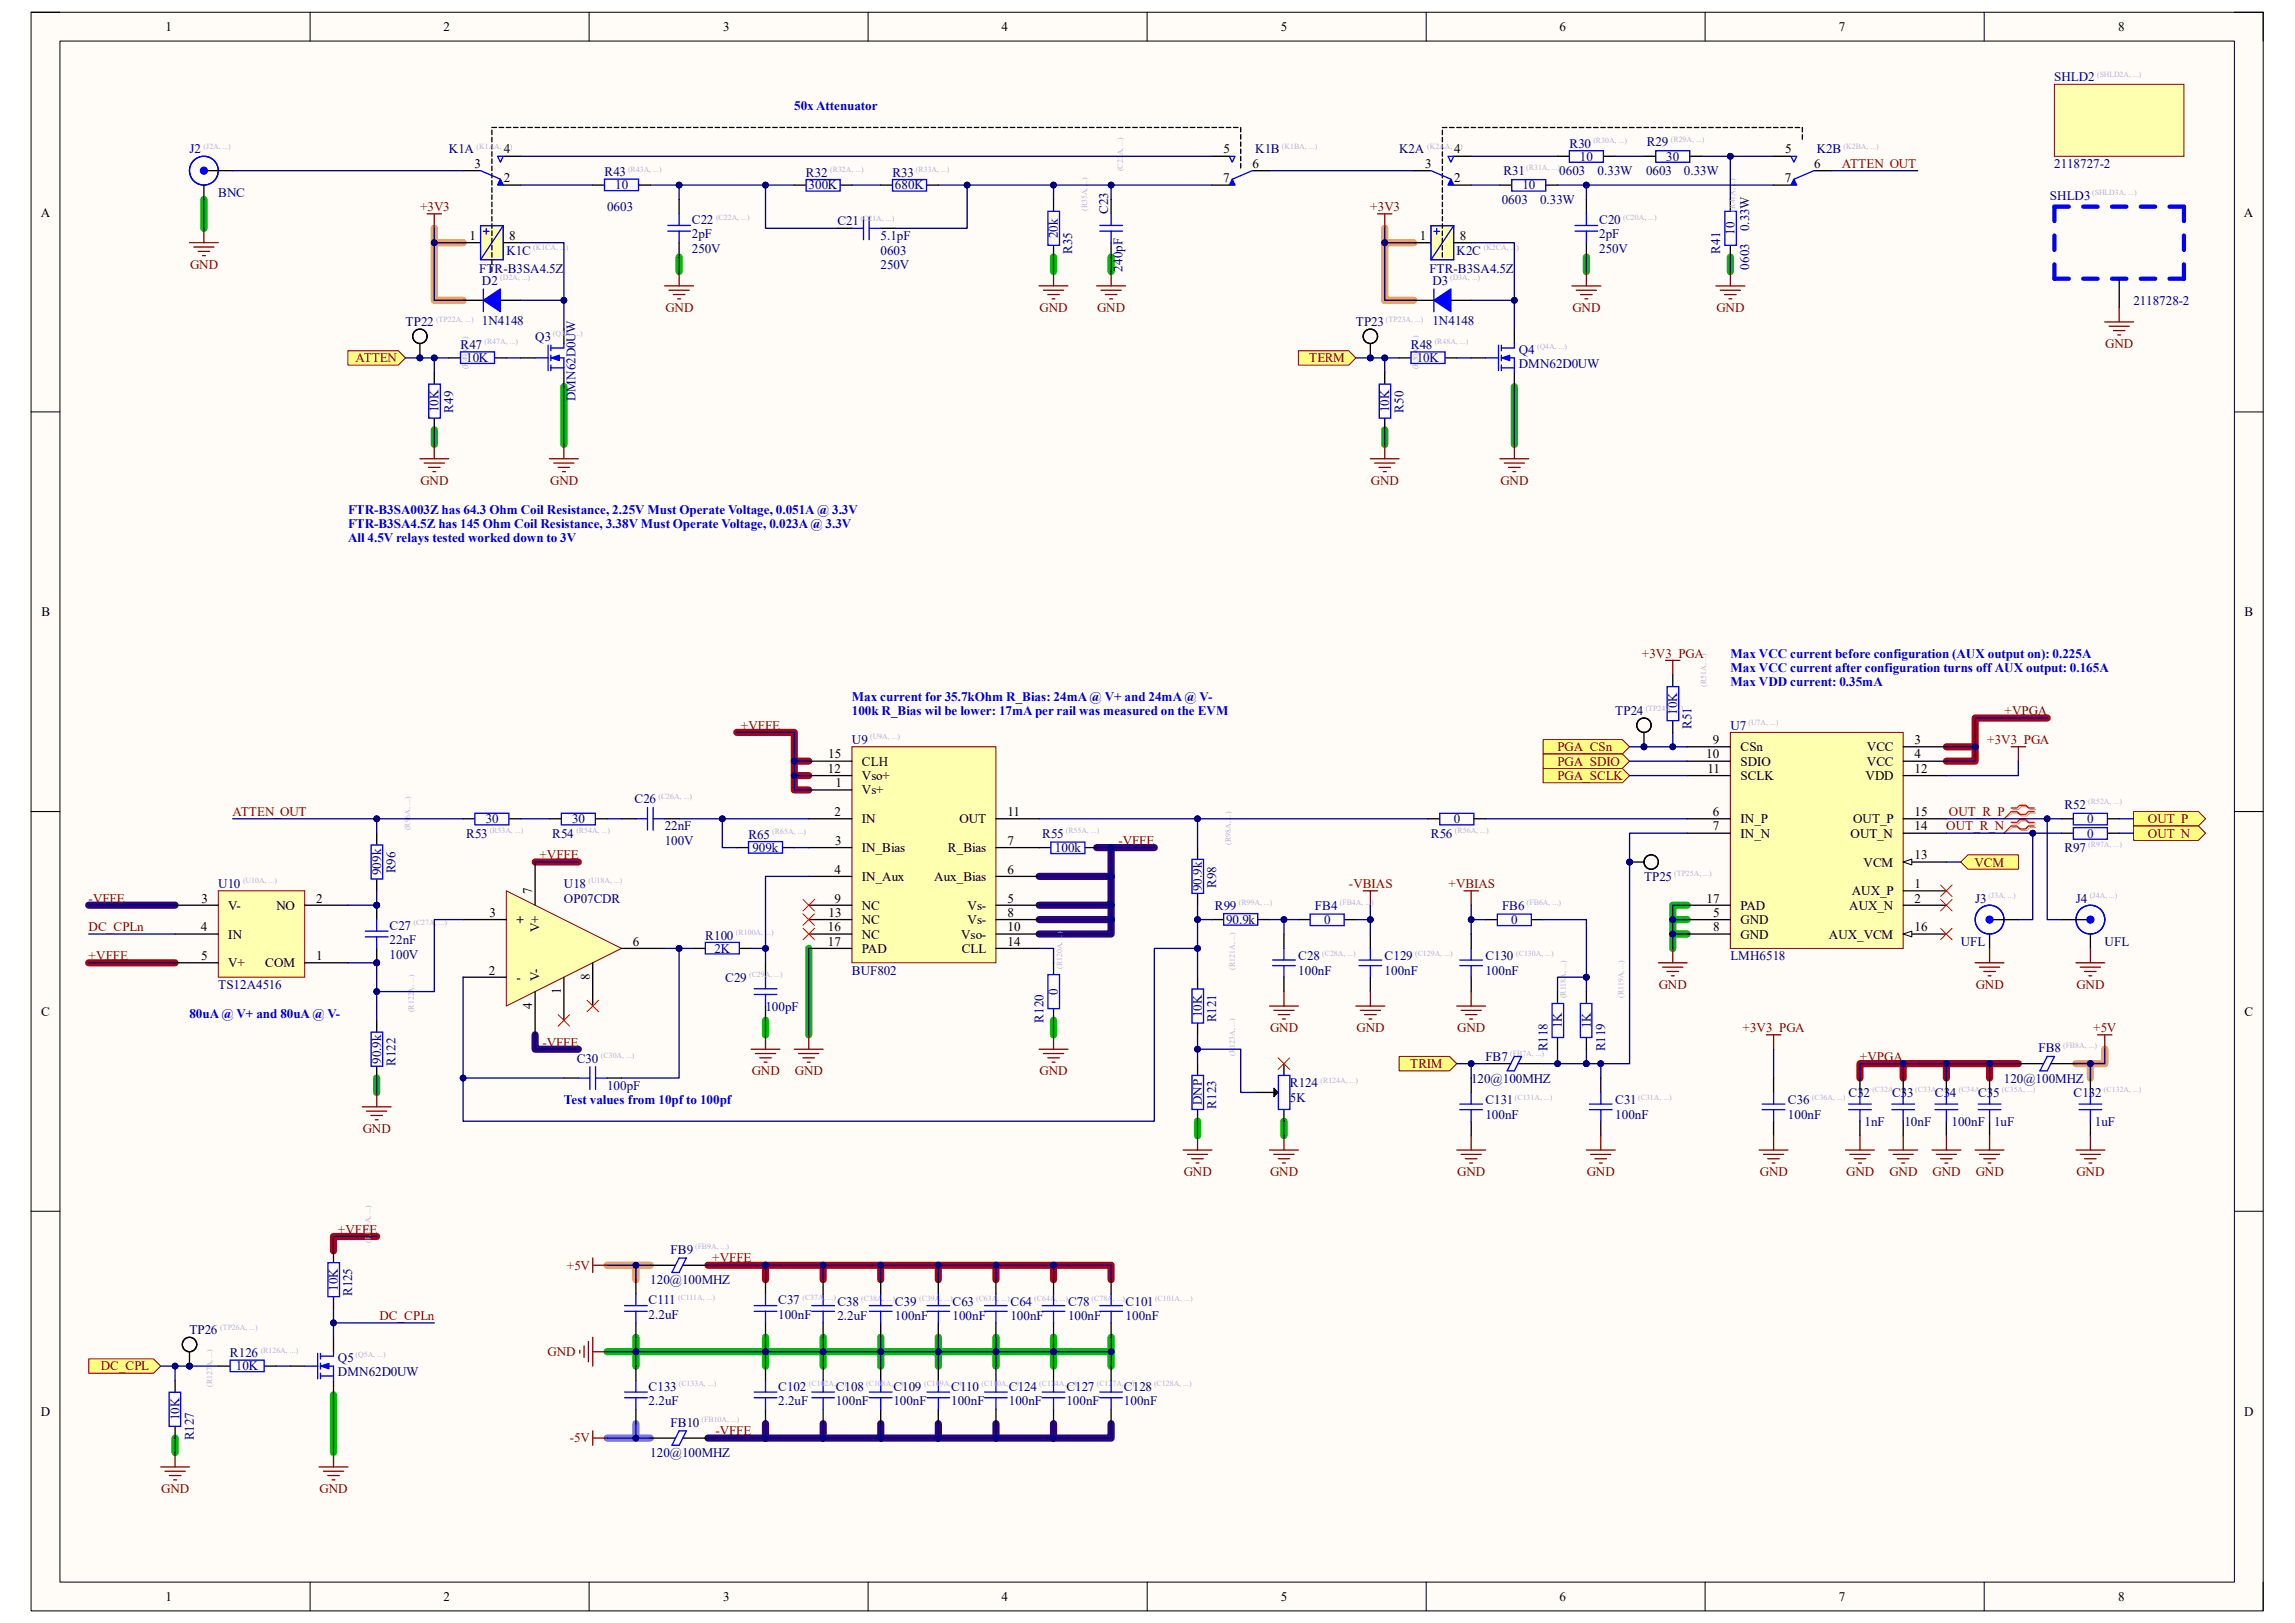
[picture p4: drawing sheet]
<svg xmlns="http://www.w3.org/2000/svg" width="297mm" height="210mm" viewBox="0 0 297 210" stroke-linecap="round" stroke-linejoin="round" font-family="sans-serif">
<defs><g id="words">
<g font-size="1.7">
<text x="21.4" y="4">1</text>
<text x="57.4" y="4">2</text>
<text x="93.6" y="4">3</text>
<text x="129.6" y="4">4</text>
<text x="165.8" y="4">5</text>
<text x="201.8" y="4">6</text>
<text x="238" y="4">7</text>
<text x="274.1" y="4">8</text>
<text x="61.4" y="21.7">3</text>
<text x="65.2" y="23.6">2</text>
<text x="65.2" y="19.9">4</text>
<text x="158.3" y="23.6">7</text>
<text x="158.3" y="19.9">5</text>
<text x="162.1" y="21.7">6</text>
<text x="184.4" y="21.7">3</text>
<text x="188.2" y="23.6">2</text>
<text x="188.2" y="19.9">4</text>
<text x="231" y="23.6">7</text>
<text x="231" y="19.9">5</text>
<text x="234.8" y="21.7">6</text>
<text x="5.3" y="28">A</text>
<text x="290.4" y="28">A</text>
<text x="60.7" y="31.1">1</text>
<text x="65.9" y="31.1">8</text>
<text x="183.8" y="31.1">1</text>
<text x="188.9" y="31.1">8</text>
<text x="5.4" y="79.8">B</text>
<text x="290.5" y="79.8">B</text>
<text x="107.1" y="100">12</text>
<text x="107.2" y="98.1">15</text>
<text x="108.1" y="101.9">1</text>
<text x="111.5" y="100.9">Vso+</text>
<text x="111.5" y="99.1">CLH</text>
<text x="220.8" y="98.1">10</text>
<text x="221" y="100">11</text>
<text x="221.7" y="96.3">9</text>
<text x="225.3" y="97.2">CSn</text>
<text x="225.3" y="99.1">SDIO</text>
<text x="225.3" y="100.9">SCLK</text>
<text x="241.4" y="100.9">VDD</text>
<text x="241.6" y="97.2">VCC</text>
<text x="241.6" y="99.1">VCC</text>
<text x="247.8" y="100">12</text>
<text x="247.8" y="96.3">3</text>
<text x="247.8" y="98.1">4</text>
<text x="108" y="105.6">2</text>
<text x="111.5" y="102.8">Vs+</text>
<text x="111.5" y="106.5">IN</text>
<text x="124.2" y="106.5">OUT</text>
<text x="130.4" y="105.6">11</text>
<text x="221.7" y="105.6">6</text>
<text x="221.7" y="107.4">7</text>
<text x="225.3" y="106.5">IN_P</text>
<text x="239.8" y="106.5">OUT_P</text>
<text x="247.8" y="107.4">14</text>
<text x="247.8" y="105.6">15</text>
<text x="108" y="113.1">4</text>
<text x="108.1" y="109.3">3</text>
<text x="111.5" y="110.3">IN_Bias</text>
<text x="122.7" y="110.3">R_Bias</text>
<text x="130.4" y="113.1">6</text>
<text x="130.4" y="109.3">7</text>
<text x="225.3" y="108.4">IN_N</text>
<text x="239.5" y="108.4">OUT_N</text>
<text x="241.2" y="112.1">VCM</text>
<text x="247.8" y="111.2">13</text>
<text x="26.1" y="116.8">3</text>
<text x="29.5" y="117.7">V-</text>
<text x="35.8" y="117.7">NO</text>
<text x="40.9" y="116.8">2</text>
<text x="63.3" y="118.7">3</text>
<text x="66.8" y="119.6">+</text>
<text x="68.9" y="115.7" transform="rotate(-90 68.9 115.7)">7</text>
<text x="107.2" y="118.7">13</text>
<text x="108" y="116.8">9</text>
<text x="111.5" y="114">IN_Aux</text>
<text x="111.5" y="117.7">NC</text>
<text x="111.5" y="119.6">NC</text>
<text x="120.9" y="114">Aux_Bias</text>
<text x="125.2" y="117.7">Vs-</text>
<text x="125.2" y="119.6">Vs-</text>
<text x="130.4" y="116.8">5</text>
<text x="130.4" y="118.7">8</text>
<text x="220.9" y="116.8">17</text>
<text x="221.7" y="118.7">5</text>
<text x="225.3" y="119.6">GND</text>
<text x="225.3" y="117.7">PAD</text>
<text x="239.3" y="117.7">AUX_N</text>
<text x="239.6" y="115.9">AUX_P</text>
<text x="247.8" y="114.9">1</text>
<text x="247.8" y="116.8">2</text>
<text x="26" y="120.5">4</text>
<text x="26" y="124.2">5</text>
<text x="29.5" y="125.2">V+</text>
<text x="29.5" y="121.5">IN</text>
<text x="34.3" y="125.2">COM</text>
<text x="40.9" y="124.2">1</text>
<text x="69.8" y="120.6" transform="rotate(-90 69.8 120.6)">V+</text>
<text x="81.9" y="122.4">6</text>
<text x="107.1" y="120.5">16</text>
<text x="107.1" y="122.4">17</text>
<text x="111.5" y="121.5">NC</text>
<text x="111.5" y="123.3">PAD</text>
<text x="124.4" y="121.5">Vso-</text>
<text x="124.5" y="123.3">CLL</text>
<text x="130.4" y="120.5">10</text>
<text x="130.4" y="122.4">14</text>
<text x="221.7" y="120.5">8</text>
<text x="225.3" y="121.5">GND</text>
<text x="236.7" y="121.5">AUX_VCM</text>
<text x="247.8" y="120.5">16</text>
<text x="5.3" y="131.4">C</text>
<text x="63.2" y="126.1">2</text>
<text x="66.8" y="127">-</text>
<text x="68.9" y="130.6" transform="rotate(-90 68.9 130.6)">4</text>
<text x="69.8" y="127" transform="rotate(-90 69.8 127)">V-</text>
<text x="72.6" y="128.6" transform="rotate(-90 72.6 128.6)">1</text>
<text x="76.3" y="126.8" transform="rotate(-90 76.3 126.8)">8</text>
<text x="290.5" y="131.4">C</text>
<text x="5.3" y="183.2">D</text>
<text x="290.4" y="183.2">D</text>
<text x="21.4" y="207.2">1</text>
<text x="57.4" y="207.2">2</text>
<text x="93.6" y="207.2">3</text>
<text x="129.6" y="207.2">4</text>
<text x="165.8" y="207.2">5</text>
<text x="201.8" y="207.2">6</text>
<text x="238" y="207.2">7</text>
<text x="274.1" y="207.2">8</text>
</g>
<g font-size="1.7" fill="#000080">
<text x="265.9" y="10.5">SHLD2</text>
<text x="24.5" y="19.9">J2</text>
<text x="58.1" y="19.9">K1A</text>
<text x="78.2" y="22.8">R43</text>
<text x="104.3" y="22.9">R32</text>
<text x="115.5" y="22.9">R33</text>
<text x="162.4" y="19.9">K1B</text>
<text x="181.1" y="19.9">K2A</text>
<text x="194.6" y="22.6">R31</text>
<text x="201.8" y="22.6">0603</text>
<text x="203.1" y="19.1">R30</text>
<text x="204.5" y="20.8">10</text>
<text x="206.8" y="22.6">0.33W</text>
<text x="213" y="22.6">0603</text>
<text x="213.1" y="18.9">R29</text>
<text x="215.6" y="20.8">30</text>
<text x="217.9" y="22.6">0.33W</text>
<text x="235.1" y="19.9">K2B</text>
<text x="265.9" y="21.7">2118727-2</text>
<text x="28.2" y="25.4">BNC</text>
<text x="78.6" y="27.3">0603</text>
<text x="79.6" y="24.5">10</text>
<text x="89.5" y="29">C22</text>
<text x="104.6" y="24.5">300K</text>
<text x="108.4" y="29.2">C21</text>
<text x="115.8" y="24.5">680K</text>
<text x="143.4" y="27.7" transform="rotate(-90 143.4 27.7)">C23</text>
<text x="194.4" y="26.4">0603</text>
<text x="197" y="24.5">10</text>
<text x="199.3" y="26.4">0.33W</text>
<text x="207" y="29">C20</text>
<text x="226.4" y="29.9" transform="rotate(-90 226.4 29.9)">0.33W</text>
<text x="265.3" y="25.8">SHLD3</text>
<text x="62" y="35.3">FTR-B3SA4.5Z</text>
<text x="65.5" y="32.9">K1C</text>
<text x="89.5" y="32.7">250V</text>
<text x="89.5" y="30.9">2pF</text>
<text x="114" y="32.9">0603</text>
<text x="114" y="34.8">250V</text>
<text x="114" y="31.1">5.1pF</text>
<text x="136.9" y="30.8" transform="rotate(-90 136.9 30.8)">20k</text>
<text x="138.8" y="32.9" transform="rotate(-90 138.8 32.9)">R35</text>
<text x="145.3" y="35.1" transform="rotate(-90 145.3 35.1)">240pF</text>
<text x="185" y="35.3">FTR-B3SA4.5Z</text>
<text x="188.5" y="32.9">K2C</text>
<text x="207" y="32.7">250V</text>
<text x="207" y="30.9">2pF</text>
<text x="222.6" y="32.8" transform="rotate(-90 222.6 32.8)">R41</text>
<text x="224.5" y="30.4" transform="rotate(-90 224.5 30.4)">10</text>
<text x="226.4" y="34.9" transform="rotate(-90 226.4 34.9)">0603</text>
<text x="62.4" y="36.9">D2</text>
<text x="185.4" y="36.9">D3</text>
<text x="276.1" y="39.5">2118728-2</text>
<text x="52.5" y="42.2">TP22</text>
<text x="59.6" y="45.2">R47</text>
<text x="60.3" y="46.9">10K</text>
<text x="62.4" y="42">1N4148</text>
<text x="69.3" y="44.1">Q3</text>
<text x="175.5" y="42.2">TP23</text>
<text x="182.6" y="45.2">R48</text>
<text x="183.3" y="46.9">10K</text>
<text x="185.4" y="42">1N4148</text>
<text x="196.6" y="45.8">Q4</text>
<text x="196.6" y="47.6">DMN62D0UW</text>
<text x="56.8" y="53.3" transform="rotate(-90 56.8 53.3)">10K</text>
<text x="58.6" y="53.4" transform="rotate(-90 58.6 53.4)">R49</text>
<text x="74.5" y="51.9" transform="rotate(-90 74.5 51.9)">DMN62D0UW</text>
<text x="179.8" y="53.3" transform="rotate(-90 179.8 53.3)">10K</text>
<text x="181.6" y="53.4" transform="rotate(-90 181.6 53.4)">R50</text>
<text x="209" y="92.5">TP24</text>
<text x="217" y="92.5" transform="rotate(-90 217 92.5)">10K</text>
<text x="218.9" y="94.3" transform="rotate(-90 218.9 94.3)">R51</text>
<text x="223.9" y="94.4">U7</text>
<text x="110.2" y="96.3">U9</text>
<text x="62.9" y="106.5">30</text>
<text x="74" y="106.5">30</text>
<text x="82.1" y="103.9">C26</text>
<text x="86" y="107.4">22nF</text>
<text x="188.1" y="106.5">0</text>
<text x="267.2" y="104.6">R52</text>
<text x="270.1" y="106.5">0</text>
<text x="49.3" y="113.2" transform="rotate(-90 49.3 113.2)">909k</text>
<text x="51.2" y="113" transform="rotate(-90 51.2 113)">R96</text>
<text x="60.3" y="108.4">R53</text>
<text x="71.5" y="108.4">R54</text>
<text x="86" y="109.3">100V</text>
<text x="96.9" y="108.5">R65</text>
<text x="97.4" y="110.3">909k</text>
<text x="134.9" y="108.4">R55</text>
<text x="136.5" y="110.3">100k</text>
<text x="185.2" y="108.4">R56</text>
<text x="267.2" y="110.3">R97</text>
<text x="270.1" y="108.4">0</text>
<text x="28.2" y="114.9">U10</text>
<text x="73" y="114.9">U18</text>
<text x="73" y="116.8">OP07CDR</text>
<text x="155.5" y="115.3" transform="rotate(-90 155.5 115.3)">90.9k</text>
<text x="157.2" y="117.7">R99</text>
<text x="157.4" y="114.9" transform="rotate(-90 157.4 114.9)">R98</text>
<text x="158.7" y="119.6">90.9k</text>
<text x="170.2" y="117.7">FB4</text>
<text x="171.4" y="119.6">0</text>
<text x="194.4" y="117.7">FB6</text>
<text x="195.6" y="119.6">0</text>
<text x="212.8" y="114">TP25</text>
<text x="255.6" y="116.8">J3</text>
<text x="268.6" y="116.8">J4</text>
<text x="50.4" y="124">100V</text>
<text x="50.4" y="120.3">C27</text>
<text x="50.4" y="122.2">22nF</text>
<text x="91.3" y="121.6">R100</text>
<text x="92.5" y="123.3">2K</text>
<text x="168" y="124.2">C28</text>
<text x="179.2" y="124.2">C129</text>
<text x="192.2" y="124.2">C130</text>
<text x="223.9" y="124.2">LMH6518</text>
<text x="253.7" y="122.4">UFL</text>
<text x="272.4" y="122.4">UFL</text>
<text x="28.2" y="128">TS12A4516</text>
<text x="93.9" y="127">C29</text>
<text x="99.1" y="130.8">100pF</text>
<text x="110.2" y="126.1">BUF802</text>
<text x="136.9" y="128.7" transform="rotate(-90 136.9 128.7)">0</text>
<text x="155.5" y="131.6" transform="rotate(-90 155.5 131.6)">10K</text>
<text x="168" y="126.1">100nF</text>
<text x="179.2" y="126.1">100nF</text>
<text x="192.2" y="126.1">100nF</text>
<text x="49.3" y="137.7" transform="rotate(-90 49.3 137.7)">90.9k</text>
<text x="51.2" y="137.9" transform="rotate(-90 51.2 137.9)">R122</text>
<text x="74.6" y="137.5">C30</text>
<text x="135" y="132.3" transform="rotate(-90 135 132.3)">R120</text>
<text x="157.4" y="132.3" transform="rotate(-90 157.4 132.3)">R121</text>
<text x="192.2" y="137.3">FB7</text>
<text x="200.3" y="136.1" transform="rotate(-90 200.3 136.1)">R118</text>
<text x="202.1" y="133.1" transform="rotate(-90 202.1 133.1)">1K</text>
<text x="205.9" y="133.1" transform="rotate(-90 205.9 133.1)">1K</text>
<text x="207.7" y="136.1" transform="rotate(-90 207.7 136.1)">R119</text>
<text x="263.8" y="136.1">FB8</text>
<text x="78.6" y="141">100pF</text>
<text x="155.5" y="143" transform="rotate(-90 155.5 143)">DNP</text>
<text x="157.4" y="143.5" transform="rotate(-90 157.4 143.5)">R123</text>
<text x="166.9" y="140.7">R124</text>
<text x="166.9" y="142.5">5K</text>
<text x="190.4" y="140.1">120@100MHZ</text>
<text x="192.2" y="142.9">C131</text>
<text x="209" y="142.9">C31</text>
<text x="231.4" y="142.9">C36</text>
<text x="239.2" y="141.9">C32</text>
<text x="244.9" y="141.9">C33</text>
<text x="250.4" y="141.9">C34</text>
<text x="256" y="141.9">C35</text>
<text x="259.3" y="140.1">120@100MHZ</text>
<text x="268.4" y="141.9">C132</text>
<text x="192.2" y="144.7">100nF</text>
<text x="209" y="144.7">100nF</text>
<text x="231.4" y="144.7">100nF</text>
<text x="241.3" y="145.7">1nF</text>
<text x="246.5" y="145.7">10nF</text>
<text x="252.6" y="145.7">100nF 1uF</text>
<text x="271.1" y="145.7">1uF</text>
<text x="43.7" y="167" transform="rotate(-90 43.7 167)">10K</text>
<text x="45.6" y="167.7" transform="rotate(-90 45.6 167.7)">R125</text>
<text x="84.2" y="166.2">120@100MHZ</text>
<text x="86.8" y="162.3">FB9</text>
<text x="24.5" y="172.7">TP26</text>
<text x="83.9" y="168.8">C111</text>
<text x="83.9" y="170.6">2.2uF</text>
<text x="100.7" y="168.8">C37</text>
<text x="100.7" y="170.6">100nF</text>
<text x="108.4" y="169">C38</text>
<text x="108.4" y="170.8">2.2uF</text>
<text x="115.8" y="169">C39</text>
<text x="115.8" y="170.8">100nF</text>
<text x="123.3" y="169">C63</text>
<text x="123.3" y="170.8">100nF</text>
<text x="130.8" y="169">C64</text>
<text x="130.8" y="170.8">100nF</text>
<text x="138.2" y="169">C78</text>
<text x="138.2" y="170.8">100nF</text>
<text x="145.7" y="169">C101</text>
<text x="145.7" y="170.8">100nF</text>
<text x="29.8" y="175.6">R126</text>
<text x="30.5" y="177.3">10K</text>
<text x="43.7" y="176.2">Q5</text>
<text x="43.7" y="178.1">DMN62D0UW</text>
<text x="83.9" y="180">C133</text>
<text x="100.7" y="180">C102</text>
<text x="108.2" y="180">C108</text>
<text x="115.6" y="180">C109</text>
<text x="123.1" y="180">C110</text>
<text x="130.6" y="180">C124</text>
<text x="138" y="180">C127</text>
<text x="145.5" y="180">C128</text>
<text x="23.2" y="183.8" transform="rotate(-90 23.2 183.8)">10K</text>
<text x="83.9" y="181.8">2.2uF</text>
<text x="86.8" y="184.6">FB10</text>
<text x="100.7" y="181.8">2.2uF</text>
<text x="108.2" y="181.8">100nF</text>
<text x="115.6" y="181.8">100nF</text>
<text x="123.1" y="181.8">100nF</text>
<text x="130.6" y="181.8">100nF</text>
<text x="138" y="181.8">100nF</text>
<text x="145.5" y="181.8">100nF</text>
<text x="25.1" y="186.4" transform="rotate(-90 25.1 186.4)">R127</text>
<text x="84.2" y="188.5">120@100MHZ</text>
</g>
<g font-size="1.7" fill="#00f">
<text x="102.8" y="14.3">50x Attenuator</text>
<text x="45" y="66.5">FTR-B3SA003Z has 64.3 Ohm Coil Resistance, 2.25V Must Operate Voltage, 0.051A @ 3.3V</text>
<text x="45" y="68.3">FTR-B3SA4.5Z has 145 Ohm Coil Resistance, 3.38V Must Operate Voltage, 0.023A @ 3.3V</text>
<text x="45" y="70.2">All 4.5V relays tested worked down to 3V</text>
<text x="223.9" y="85.1">Max VCC current before configuration (AUX output on): 0.225A</text>
<text x="223.9" y="87">Max VCC current after configuration turns off AUX output: 0.165A</text>
<text x="223.9" y="88.8">Max VDD current: 0.35mA</text>
<text x="110.2" y="90.7">Max current for 35.7kOhm R_Bias: 24mA @ V+ and 24mA @ V-</text>
<text x="110.2" y="92.5">100k R_Bias wil be lower: 17mA per rail was measured on the EVM</text>
<text x="24.5" y="131.7">80uA @ V+ and 80uA @ V-</text>
<text x="73" y="142.9">Test values from 10pf to 100pf</text>
</g>
<g font-size="1.7" fill="#800000">
<text x="238.4" y="21.7">ATTEN_OUT</text>
<text x="54.4" y="27.3">+3V3</text>
<text x="177.3" y="27.3">+3V3</text>
<text x="24.6" y="34.8">GND</text>
<text x="86.1" y="40.4">GND</text>
<text x="134.5" y="40.4">GND</text>
<text x="142" y="40.4">GND</text>
<text x="203.5" y="40.4">GND</text>
<text x="222.1" y="40.4">GND</text>
<text x="46" y="46.9">ATTEN</text>
<text x="169.4" y="46.9">TERM</text>
<text x="272.5" y="45">GND</text>
<text x="54.4" y="62.7">GND</text>
<text x="71.2" y="62.7">GND</text>
<text x="177.4" y="62.7">GND</text>
<text x="194.2" y="62.7">GND</text>
<text x="212.5" y="85.1">+3V3_PGA</text>
<text x="95.9" y="94.4">+VFFE</text>
<text x="259.4" y="92.5">+VPGA</text>
<text x="201.5" y="97.2">PGA_CSn</text>
<text x="201.5" y="100.9">PGA_SCLK</text>
<text x="201.5" y="99.1">PGA_SDIO</text>
<text x="257.2" y="96.3">+3V3_PGA</text>
<text x="30.1" y="105.6">ATTEN_OUT</text>
<text x="251.9" y="107.4">OUT_R_N</text>
<text x="252.2" y="105.6">OUT_R_P</text>
<text x="278" y="106.5">OUT_P</text>
<text x="69.8" y="111.2">+VFFE</text>
<text x="144.7" y="109.3">-VFFE</text>
<text x="255.5" y="112.1">VCM</text>
<text x="278" y="108.4">OUT_N</text>
<text x="11.5" y="116.8">-VFFE</text>
<text x="174.6" y="114.9">-VBIAS</text>
<text x="187.5" y="114.9">+VBIAS</text>
<text x="11.5" y="120.5">DC_CPLn</text>
<text x="11.5" y="124.2">+VFFE</text>
<text x="214.7" y="128">GND</text>
<text x="255.7" y="128">GND</text>
<text x="268.7" y="128">GND</text>
<text x="70.2" y="135.4">-VFFE</text>
<text x="164.4" y="133.6">GND</text>
<text x="175.6" y="133.6">GND</text>
<text x="188.6" y="133.6">GND</text>
<text x="225.5" y="133.6">+3V3_PGA</text>
<text x="240.7" y="137.3">+VPGA</text>
<text x="270.9" y="133.6">+5V</text>
<text x="97.3" y="139.1">GND</text>
<text x="102.9" y="139.1">GND</text>
<text x="134.5" y="139.1">GND</text>
<text x="182.5" y="138.2">TRIM</text>
<text x="46.9" y="146.6">GND</text>
<text x="153.2" y="152.2">GND</text>
<text x="164.4" y="152.2">GND</text>
<text x="188.6" y="152.2">GND</text>
<text x="205.4" y="152.2">GND</text>
<text x="227.8" y="152.2">GND</text>
<text x="238.9" y="152.2">GND</text>
<text x="244.5" y="152.2">GND</text>
<text x="250.1" y="152.2">GND</text>
<text x="255.7" y="152.2">GND</text>
<text x="268.7" y="152.2">GND</text>
<text x="43.7" y="159.6">+VFFE</text>
<text x="73.4" y="164.3">+5V</text>
<text x="92.2" y="163.4">+VFFE</text>
<text x="49.1" y="170.8">DC_CPLn</text>
<text x="13" y="177.3">DC_CPL</text>
<text x="70.9" y="175.5">GND</text>
<text x="92.6" y="185.7">-VFFE</text>
<text x="73.7" y="186.6">-5V</text>
<text x="20.9" y="193.2">GND</text>
<text x="41.4" y="193.2">GND</text>
</g>
<g font-size="1" fill="#b2b0d4">
<text x="271.4" y="9.9">(SHLD2A, ...)</text>
<text x="26.3" y="19.3">(J2A, ...)</text>
<text x="61.7" y="19.3">(K1AA, ...)</text>
<text x="81.3" y="22.2">(R43A, ...)</text>
<text x="107.4" y="22.3">(R32A, ...)</text>
<text x="118.5" y="22.3">(R33A, ...)</text>
<text x="145.3" y="22.1" transform="rotate(-90 145.3 22.1)">(C23A, ...)</text>
<text x="165.9" y="19.3">(K1BA, ...)</text>
<text x="184.7" y="19.3">(K2AA, ...)</text>
<text x="197.5" y="22.1">(R31A, ...)</text>
<text x="206.2" y="18.5">(R30A, ...)</text>
<text x="216.2" y="18.3">(R29A, ...)</text>
<text x="238.6" y="19.3">(K2BA, ...)</text>
<text x="92.7" y="28.4">(C22A, ...)</text>
<text x="111.4" y="28.6">(C21A, ...)</text>
<text x="140.7" y="27.3" transform="rotate(-90 140.7 27.3)">(R35A, ...)</text>
<text x="210.1" y="28.4">(C20A, ...)</text>
<text x="224.5" y="27.4" transform="rotate(-90 224.5 27.4)">(R41A, ...)</text>
<text x="270.8" y="25.2">(SHLD3A, ...)</text>
<text x="69" y="32.3">(K1CA, ...)</text>
<text x="192" y="32.3">(K2CA, ...)</text>
<text x="56.4" y="41.6">(TP22A, ...)</text>
<text x="64.7" y="36.2">(D2A, ...)</text>
<text x="179.4" y="41.6">(TP23A, ...)</text>
<text x="187.7" y="36.2">(D3A, ...)</text>
<text x="60.5" y="47.8" transform="rotate(-90 60.5 47.8)">(R49A, ...)</text>
<text x="62.7" y="44.6">(R47A, ...)</text>
<text x="71.5" y="43.5">(Q3A, ...)</text>
<text x="183.5" y="47.8" transform="rotate(-90 183.5 47.8)">(R50A, ...)</text>
<text x="185.7" y="44.6">(R48A, ...)</text>
<text x="198.9" y="45.2">(Q4A, ...)</text>
<text x="220.8" y="88.9" transform="rotate(-90 220.8 88.9)">(R51A, ...)</text>
<text x="112.6" y="95.7">(U9A, ...)</text>
<text x="213" y="91.9">(TP24A, ...)</text>
<text x="226.3" y="93.8">(U7A, ...)</text>
<text x="53.1" y="107.4" transform="rotate(-90 53.1 107.4)">(R96A, ...)</text>
<text x="63.4" y="107.8">(R53A, ...)</text>
<text x="74.6" y="107.8">(R54A, ...)</text>
<text x="85.2" y="103.3">(C26A, ...)</text>
<text x="99.9" y="107.9">(R65A, ...)</text>
<text x="137.9" y="107.8">(R55A, ...)</text>
<text x="188.3" y="107.8">(R56A, ...)</text>
<text x="270.3" y="104.1">(R52A, ...)</text>
<text x="159.3" y="109.3" transform="rotate(-90 159.3 109.3)">(R98A, ...)</text>
<text x="216.7" y="113.4">(TP25A, ...)</text>
<text x="270.3" y="109.6">(R97A, ...)</text>
<text x="31.5" y="114.3">(U10A, ...)</text>
<text x="53.5" y="119.7">(C27A, ...)</text>
<text x="76.2" y="114.3">(U18A, ...)</text>
<text x="160.3" y="117.1">(R99A, ...)</text>
<text x="173.4" y="117.1">(FB4A, ...)</text>
<text x="197.6" y="117.1">(FB6A, ...)</text>
<text x="257.3" y="116.2">(J3A, ...)</text>
<text x="270.5" y="116.2">(J4A, ...)</text>
<text x="95.2" y="121">(R100A, ...)</text>
<text x="137.5" y="125.4" transform="rotate(-90 137.5 125.4)">(R120A, ...)</text>
<text x="159.8" y="125.5" transform="rotate(-90 159.8 125.5)">(R121A, ...)</text>
<text x="171.1" y="123.7">(C28A, ...)</text>
<text x="183.1" y="123.7">(C129A, ...)</text>
<text x="196.2" y="123.7">(C130A, ...)</text>
<text x="53.6" y="131" transform="rotate(-90 53.6 131)">(R122A, ...)</text>
<text x="96.9" y="126.4">(C29A, ...)</text>
<text x="202.7" y="129.2" transform="rotate(-90 202.7 129.2)">(R118A, ...)</text>
<text x="210.1" y="129.1" transform="rotate(-90 210.1 129.1)">(R119A, ...)</text>
<text x="77.8" y="136.9">(C30A, ...)</text>
<text x="159.8" y="136.6" transform="rotate(-90 159.8 136.6)">(R123A, ...)</text>
<text x="195.5" y="136.7">(FB7A, ...)</text>
<text x="267" y="135.6">(FB8A, ...)</text>
<text x="170.9" y="140.1">(R124A, ...)</text>
<text x="196" y="142.3">(C131A, ...)</text>
<text x="212" y="142.3">(C31A, ...)</text>
<text x="234.5" y="142.3">(C36A, ...)</text>
<text x="242.3" y="141.4">(C32A, ...)</text>
<text x="247.9" y="141.4">(C33A, ...)</text>
<text x="253.5" y="141.4">(C34A, ...)</text>
<text x="259.1" y="141.4">(C35A, ...)</text>
<text x="272.3" y="141.4">(C132A, ...)</text>
<text x="48" y="160.8" transform="rotate(-90 48 160.8)">(R125A, ...)</text>
<text x="90" y="161.7">(FB9A, ...)</text>
<text x="28.5" y="172.1">(TP26A, ...)</text>
<text x="87.8" y="168.2">(C111A, ...)</text>
<text x="103.8" y="168.2">(C37A, ...)</text>
<text x="111.5" y="168.4">(C38A, ...)</text>
<text x="119" y="168.4">(C39A, ...)</text>
<text x="126.3" y="168.4">(C63A, ...)</text>
<text x="133.9" y="168.4">(C64A, ...)</text>
<text x="141.3" y="168.4">(C78A, ...)</text>
<text x="149.5" y="168.4">(C101A, ...)</text>
<text x="27.5" y="179.4" transform="rotate(-90 27.5 179.4)">(R127A, ...)</text>
<text x="33.7" y="175">(R126A, ...)</text>
<text x="46" y="175.6">(Q5A, ...)</text>
<text x="87.8" y="179.4">(C133A, ...)</text>
<text x="104.7" y="179.4">(C102A, ...)</text>
<text x="112.1" y="179.4">(C108A, ...)</text>
<text x="119.6" y="179.4">(C109A, ...)</text>
<text x="127" y="179.4">(C110A, ...)</text>
<text x="134.5" y="179.4">(C124A, ...)</text>
<text x="141.9" y="179.4">(C127A, ...)</text>
<text x="149.4" y="179.4">(C128A, ...)</text>
<text x="90.8" y="184">(FB10A, ...)</text>
</g>
</g></defs>
<path d="M4 1.6h288.9v206.8h-288.9z" fill-rule="evenodd" fill="#fffcf8"/>
<path d="M4 1.6h288.9v206.8h-288.9z" fill="none" stroke="#000" stroke-width=".13"/>
<path d="M7.8 5.3h281.4v199.4h-281.4z" fill-rule="evenodd" fill="#fffcf8"/>
<g fill="none" stroke="#000" stroke-width=".13">
<path d="M4 1.6h3.7M7.8 5.3h281.4v199.4h-281.4zM40.1 1.6v3.7M76.2 1.6v3.7M112.3 1.6v3.7M148.5 1.6v3.7M184.6 1.6v3.7M220.7 1.6v3.7M256.8 1.6v3.7M289.2 1.6h3.7v3.7M4 53.3h3.7M289.2 53.3h3.7"/>
<path d="M4 105h3.8M289.2 105h3.7M4 156.7h3.8M289.2 156.7h3.7M40.1 204.7v3.7M76.2 204.7v3.7M112.4 204.7v3.7M148.5 204.7v3.7M184.6 204.7v3.7M220.7 204.7v3.7M256.8 204.7v3.7M292.9 204.7v3.7"/>
</g>
<g fill="none" stroke="#00be00" stroke-width=".93">
<path d="M26.4 25.8v3.7M87.9 33.3v1.8M136.3 33.3v1.8M143.8 33.3v1.8M205.3 33.3v1.8M223.9 33.3v1.8M56.2 55.6v1.9M73 50v7.5M179.2 55.6v1.9M196 50v7.5M216.5 119h1.8M218.3 117.1h-1.8v3.8h1.8"/>
<path d="M48.8 139.5v1.9M99.1 132v1.9M104.7 122.7v11.2M136.3 132v1.9M216.5 120.9v1.8M155 145.1v1.8M166.2 145.1v1.8M82.3 173v3.8M99.1 173v3.8M106.5 173v3.8M114 173v3.8M121.4 173v3.8"/>
<path d="M128.9 173v3.8M136.3 173v3.8M143.8 173v1.9h-65.2M143.8 174.9v1.9M22.7 186.1v1.8M43.2 180.5v7.4"/>
</g>
<g fill="none" stroke="#a50021" stroke-width=".93">
<path d="M95.3 94.8h7.5v7.4h1.9M102.8 98.5h1.9M251.9 96.6h3.7M264.9 92.9h-9.3v5.6h-3.7M69.3 111.5h5.5M102.8 100.4h1.9M11.5 124.6h11.2M246.3 137.6h-5.6v1.9M251.9 137.6h-5.6v1.9M257.5 137.6v1.9M261.2 137.6h-9.3v1.9M48.8 160h-5.6v1.9"/>
<path d="M91.6 163.7h7.5M99.1 163.7h7.4v1.9M99.1 163.7v1.9M106.5 163.7h29.8v1.9M114 163.7v1.9M121.4 163.7v1.9M128.9 163.7v1.9M136.3 163.7h7.5v1.9"/>
</g>
<path d="M56.2 31.4v7.5h3.7M56.2 29.5v1.9h3.7M179.2 31.4v7.5h3.7M179.2 29.5v1.9h3.7" fill="none" stroke="#f90" stroke-width=".93"/>
<g fill="none" stroke="#30007b" stroke-width=".93">
<path d="M11.5 117.1h11.2M134.5 113.4h9.3v3.7h-9.3M134.5 119h9.3v1.9h-9.3M141.9 109.7h1.9v3.7M143.8 117.1v1.9M143.8 109.7h5.6M69.3 133.9v1.9h5.5M91.6 186.1h7.5M99.1 184.2v1.9M106.5 184.2v1.9M114 184.2v1.9M121.4 184.2v1.9"/>
<path d="M128.9 184.2v1.9M136.3 184.2v1.9h-37.2M143.8 184.2v1.9h-7.5"/>
</g>
<path d="M270.5 137.6v1.9M272.4 135.8v1.8h-3.7M78.6 163.7h5.6M82.3 163.7v1.9" fill="none" stroke="#ff6e6e" stroke-width=".93"/>
<path d="M78.6 186.1h5.6M82.3 184.2v1.9" fill="none" stroke="#6e6eff" stroke-width=".93"/>
<path d="M265.9 30.5v1.8M265.9 34.2v1.9h1.8M267.7 26.7h-1.8v1.9M269.6 36.1h1.9M269.6 26.7h1.9M273.3 36.1h1.9M273.3 26.7h1.9M277.1 36.1h1.8M277.1 26.7h1.8M280.8 26.7h1.8v1.9M282.6 34.2v1.9h-1.8M282.6 30.5v1.8" fill="none" stroke="#00f" stroke-width=".55"/>
<path d="M274.3 36.1v3.7" fill="none" stroke="#000" stroke-width=".17"/>
<path d="M274.3 39.8v1.9M272.4 41.7h3.7M273 42.2h2.6M273.5 42.8h1.5M274.1 43.3h.3" fill="none" stroke="#800000" stroke-width=".17"/>
<path d="M265.9 10.9h16.7v9.3h-16.7z" fill-rule="evenodd" fill="#ffffb0"/>
<path d="M265.9 10.9h16.7v9.3h-16.7z" fill="none" stroke="#800000" stroke-width=".13"/>
<path d="M24.5 31.4h3.7M25.1 32h2.6M25.6 32.5h1.5M26.2 33.1h.4M26.4 29.5v1.9" fill="none" stroke="#800000" stroke-width=".17"/>
<circle cx="26.4" cy="22.1" r="1.86" fill="none" stroke="#00f" stroke-width=".17"/>
<path d="M26.4 22.1h3.7M26.4 23.9v1.9" fill="none" stroke="#000" stroke-width=".17"/>
<circle cx="26.4" cy="22.1" r=".47" fill="#00f"/>
<circle cx="26.4" cy="22.1" r=".47" fill="none" stroke="#00f" stroke-width=".13"/>
<path d="M184.8 105.9h1.5M190.8 105.9h1.5" fill="none" stroke="#000" stroke-width=".17"/>
<path d="M186.3 105.2h4.4v1.5h-4.4z" fill="none" stroke="#00f" stroke-width=".17"/>
<path d="M223.9 94.8h22.4v27.9h-22.4z" fill-rule="evenodd" fill="#ffffb0"/>
<path d="M223.9 94.8h22.4v27.9h-22.4z" fill="none" stroke="#800000" stroke-width=".13"/>
<path d="M218.3 96.6h5.6M218.3 98.5h5.6M218.3 100.4h5.6M246.3 100.4h5.6M246.3 111.5h5.6" fill="none" stroke="#000" stroke-width=".17"/>
<path d="M246.3 111.5l1.1-.3v.7z" fill="#f8fcff"/>
<path d="M246.3 111.5l1.1-.3v.7z" fill="none" stroke="#000" stroke-width=".13"/>
<path d="M246.3 107.8h5.6M246.3 105.9h5.6M246.3 115.3h5.6M246.3 117.1h5.6M246.3 120.9h5.6" fill="none" stroke="#000" stroke-width=".17"/>
<path d="M246.3 120.9l1.1-.4v.7z" fill="#f8fcff"/>
<path d="M246.3 120.9l1.1-.4v.7z" fill="none" stroke="#000" stroke-width=".13"/>
<path d="M246.3 96.6h5.6M246.3 98.5h5.6M218.3 119h5.6M218.3 117.1h5.6M218.3 105.9h5.6M218.3 107.8h5.6M218.3 120.9h5.6" fill="none" stroke="#000" stroke-width=".17"/>
<path d="M199.7 95.7h10.3l.9 .9-.9 1h-10.3z" fill-rule="evenodd" fill="#ffff80"/>
<path d="M199.7 95.7h10.3l.9 .9-.9 1h-10.3z" fill="none" stroke="#800000" stroke-width=".13"/>
<path d="M216.5 87.3v1.5M216.5 93.3v1.5" fill="none" stroke="#000" stroke-width=".17"/>
<path d="M215.8 88.8h1.5v4.4h-1.5z" fill="none" stroke="#00f" stroke-width=".17"/>
<path d="M199.7 99.4h10.3l.9 1-.9 .9h-10.3z" fill-rule="evenodd" fill="#ffff80"/>
<path d="M199.7 99.4h10.3l.9 1-.9 .9h-10.3z" fill="none" stroke="#800000" stroke-width=".13"/>
<path d="M199.7 97.6h10.3l.9 .9-.9 .9h-10.3z" fill-rule="evenodd" fill="#ffff80"/>
<path d="M199.7 97.6h10.3l.9 .9-.9 .9h-10.3z" fill="none" stroke="#800000" stroke-width=".13"/>
<path d="M214.6 124.6h3.7M215.2 125.1h2.6M215.7 125.7h1.5M216.3 126.3h.4M216.5 122.7v1.9" fill="none" stroke="#800000" stroke-width=".17"/>
<path d="M254.7 110.6h6.5v1.9h-6.5l-.9-1z" fill-rule="evenodd" fill="#ffff80"/>
<path d="M254.7 110.6h6.5v1.9h-6.5l-.9-1z" fill="none" stroke="#800000" stroke-width=".13"/>
<path d="M251.1 114.5l1.5 1.5M251.1 116.4l1.5 1.5M252.6 114.5l-1.5 1.5M252.6 116.4l-1.5 1.5M251.1 120.1l1.5 1.5M252.6 120.1l-1.5 1.5" fill="none" stroke="#f00" stroke-width=".13"/>
<path d="M276.1 105h8.4l.9 .9-.9 1h-8.4z" fill-rule="evenodd" fill="#ffff80"/>
<path d="M276.1 105h8.4l.9 .9-.9 1h-8.4z" fill="none" stroke="#800000" stroke-width=".13"/>
<path d="M276.1 106.9h8.4l.9 .9-.9 .9h-8.4z" fill-rule="evenodd" fill="#ffff80"/>
<path d="M276.1 106.9h8.4l.9 .9-.9 .9h-8.4z" fill="none" stroke="#800000" stroke-width=".13"/>
<path d="M257.5 119h3.7M266.8 105.9h1.5M266.8 107.8h1.5M272.8 105.9h1.5M272.8 107.8h1.5M257.5 120.9v1.8" fill="none" stroke="#000" stroke-width=".17"/>
<g fill="none" stroke="#00f" stroke-width=".17">
<path d="M268.3 105.2h4.4v1.5h-4.4zM268.3 107.1h4.4v1.5h-4.4z"/>
<circle cx="257.5" cy="119" r="1.86"/>
</g>
<circle cx="257.5" cy="119" r=".47" fill="#00f"/>
<circle cx="257.5" cy="119" r=".47" fill="none" stroke="#00f" stroke-width=".13"/>
<path d="M255.6 124.6h3.7M256.2 125.1h2.6M256.7 125.7h1.5M257.3 126.3h.4M257.5 122.7v1.9" fill="none" stroke="#800000" stroke-width=".17"/>
<circle cx="270.5" cy="119" r="1.86" fill="none" stroke="#00f" stroke-width=".17"/>
<path d="M266.8 119h3.7M270.5 120.9v1.8" fill="none" stroke="#000" stroke-width=".17"/>
<circle cx="270.5" cy="119" r=".47" fill="#00f"/>
<circle cx="270.5" cy="119" r=".47" fill="none" stroke="#00f" stroke-width=".13"/>
<path d="M268.7 124.6h3.7M269.2 125.1h2.6M269.8 125.7h1.5M270.3 126.3h.4M270.5 122.7v1.9" fill="none" stroke="#800000" stroke-width=".17"/>
<path d="M260.5 104.7h.7l.4-.3h.7l.4 .3h.8M260.5 105.2h.7l.4 .4h.7l.4-.4h.8" fill="none" stroke="#d0a19e" stroke-width=".17"/>
<path d="M260.5 105.2l-1.2 .7" fill="none" stroke="#d0a19e" stroke-width=".13"/>
<path d="M260.3 104.6h.7l.4-.4h.7l.4 .4h.8M260.3 105h.7l.4 .4h.7l.4-.4h.8" fill="none" stroke="#f00" stroke-width=".17"/>
<path d="M260.3 105l-1 .9" fill="none" stroke="#f00" stroke-width=".13"/>
<circle cx="212.8" cy="96.6" r=".37" fill="#000080"/>
<circle cx="212.8" cy="96.6" r=".37" fill="none" stroke="#000080" stroke-width=".13"/>
<path d="M212.8 94.8v1.8" fill="none" stroke="#000" stroke-width=".17"/>
<circle cx="212.8" cy="96.6" r=".37" fill="#000080"/>
<circle cx="212.8" cy="96.6" r=".37" fill="none" stroke="#000080" stroke-width=".13"/>
<g fill="none" stroke="#000" stroke-width=".17">
<path d="M201.6 128.3v1.5M201.6 134.3v1.5M205.3 128.3v1.5M205.3 134.3v1.5M229.5 139.5v1.9M240.7 139.5v1.9M246.3 139.5v1.9M251.9 139.5v1.9M257.5 139.5v1.9M229.5 145.1v1.8M240.7 145.1v1.8M246.3 145.1v1.8"/>
<path d="M251.9 145.1v1.8M257.5 145.1v1.8"/>
<circle cx="212.8" cy="93.8" r=".93"/>
</g>
<g fill="none" stroke="#00f" stroke-width=".17">
<path d="M200.9 129.8h1.5v4.4h-1.5zM204.5 129.8h1.5v4.4h-1.5zM228.1 143.6h2.9M228.1 142.9h2.9M229.5 141.4v1.5M229.5 143.6v1.5M239.2 143.6h3M239.2 142.9h3M240.7 141.4v1.5M240.7 143.6v1.5M244.8 143.6h3M244.8 142.9h3"/>
<path d="M246.3 141.4v1.5M246.3 143.6v1.5M250.4 143.6h3M250.4 142.9h3M251.9 141.4v1.5M251.9 143.6v1.5M256 143.6h3M256 142.9h3M257.5 141.4v1.5M257.5 143.6v1.5"/>
</g>
<g fill="none" stroke="#800000" stroke-width=".17">
<path d="M271.5 133.9h1.8M272.4 133.9v1.9M227.7 148.8h3.7M228.2 149.4h2.6M228.8 149.9h1.5M229.3 150.5h.4M229.5 146.9v1.9M238.8 148.8h3.8M239.4 149.4h2.6M240 149.9h1.5M240.5 150.5h.4M240.7 146.9v1.9"/>
<path d="M244.4 148.8h3.8M245 149.4h2.6M245.6 149.9h1.4M246.1 150.5h.4M246.3 146.9v1.9M250 148.8h3.8M250.6 149.4h2.6M251.1 149.9h1.5M251.7 150.5h.4M251.9 146.9v1.9M255.6 148.8h3.7M256.2 149.4h2.6"/>
<path d="M256.7 149.9h1.5M257.3 150.5h.4M257.5 146.9v1.9"/>
</g>
<path d="M260.5 106.6h.7l.4-.4h.7l.4 .4h.8M260.5 107.1h.7l.4 .3h.7l.4-.3h.8" fill="none" stroke="#d0a19e" stroke-width=".17"/>
<path d="M260.5 107.1l-1.2 .7" fill="none" stroke="#d0a19e" stroke-width=".13"/>
<path d="M260.3 106.4h.7l.4-.4h.7l.4 .4h.8M260.3 106.9h.7l.4 .4h.7l.4-.4h.8" fill="none" stroke="#f00" stroke-width=".17"/>
<path d="M260.3 106.9l-1 .9" fill="none" stroke="#f00" stroke-width=".13"/>
<path d="M181.1 136.7h6.5l.9 .9-.9 1h-6.5z" fill-rule="evenodd" fill="#ffff80"/>
<path d="M181.1 136.7h6.5l.9 .9-.9 1h-6.5z" fill="none" stroke="#800000" stroke-width=".13"/>
<circle cx="210.9" cy="111.5" r=".37" fill="#000080"/>
<circle cx="210.9" cy="111.5" r=".37" fill="none" stroke="#000080" stroke-width=".13"/>
<path d="M210.9 111.5h1.9" fill="none" stroke="#000" stroke-width=".17"/>
<circle cx="210.9" cy="111.5" r=".37" fill="#000080"/>
<circle cx="210.9" cy="111.5" r=".37" fill="none" stroke="#000080" stroke-width=".13"/>
<g fill="none" stroke="#000" stroke-width=".17">
<path d="M207.2 139.5v1.9M207.2 145.1v1.8"/>
<circle cx="213.7" cy="111.5" r=".93"/>
</g>
<path d="M205.7 142.9h2.9M205.7 143.6h2.9M207.2 141.4v1.5M207.2 143.6v1.5" fill="none" stroke="#00f" stroke-width=".17"/>
<path d="M215.6 85.4h1.8M216.5 85.4v1.9M260.3 96.6h1.8M261.2 96.6v1.9M228.6 133.9h1.9M229.5 133.9v1.9M205.3 148.8h3.7M205.9 149.4h2.6M206.4 149.9h1.5M207 150.5h.3M207.2 146.9v1.9" fill="none" stroke="#800000" stroke-width=".17"/>
<path d="M62.2 29.2h2.9v4.4h-2.9z" fill-rule="evenodd" fill="#ffffb0"/>
<path d="M62.2 29.2h2.9v4.4h-2.9z" fill="none" stroke="#800000" stroke-width=".13"/>
<path d="M62.6 29.9h.7M62.9 29.6v.7M65.1 29.2l-2.9 4.4M65.1 29.2h-2.9v4.4M65.1 29.2v4.4h-2.9" fill="none" stroke="#00f" stroke-width=".17"/>
<path d="M59.9 31.4h2.2M59.9 38.9h2.8M64.6 38.9h2.8M65.2 31.4h2.2" fill="none" stroke="#000" stroke-width=".17"/>
<path d="M55.3 27.7h1.8M56.2 27.7v1.8" fill="none" stroke="#800000" stroke-width=".17"/>
<path d="M62.6 38.9l2.2-1.5v2.9z" fill="#00f"/>
<path d="M62.6 38.9l2.2-1.5v2.9zM62.6 37.4v2.9M69.3 46.3h1.6M70.9 44.7v3.3M71.3 45h1.7M71.3 46.3h1.7v1.9M71.3 47.6h1.7M71.3 44.7v.7M71.3 45.9v.8M71.3 47.2v.8" fill="none" stroke="#00f" stroke-width=".17"/>
<path d="M67.4 46.3h1.9M73 42.6v1.8M73 48.2v1.8" fill="none" stroke="#000" stroke-width=".17"/>
<path d="M71.3 46.3l1.1-.4v.8z" fill="#00f"/>
<path d="M71.3 46.3l1.1-.4v.8z" fill="none" stroke="#00f" stroke-width=".13"/>
<path d="M55.5 49.7h1.5v4.4h-1.5zM73 44.4v.6" fill="none" stroke="#00f" stroke-width=".17"/>
<path d="M54.3 59.4h3.8M54.9 59.9h2.6M56.2 57.5v1.9M71.1 59.4h3.7M71.7 59.9h2.6M73 57.5v1.9M55.5 60.5h1.5M56 61h.4M72.2 60.5h1.5M72.8 61h.4" fill="none" stroke="#800000" stroke-width=".17"/>
<path d="M56.2 48.2v1.4M56.2 54.2v1.4" fill="none" stroke="#000" stroke-width=".17"/>
<path d="M45 45.4h6.5l1 .9-1 .9h-6.5z" fill-rule="evenodd" fill="#ffff80"/>
<path d="M45 45.4h6.5l1 .9-1 .9h-6.5z" fill="none" stroke="#800000" stroke-width=".13"/>
<g fill="none" stroke="#000" stroke-width=".17">
<path d="M63.7 16.8v.6M63.7 17.8v.6M63.7 18.7v.6M63.7 19.6v.6M63.7 16.5h.5M64.6 16.5h.6M65.5 16.5h.6M66.5 16.5h.5M67.4 16.5h.6M68.3 16.5h.6M69.3 16.5h.5M70.2 16.5h.6"/>
<path d="M71.1 16.5h.6M72 16.5h.6M73 16.5h.6M73.9 16.5h.6M74.8 16.5h.6M75.8 16.5h.6M76.7 16.5h.6M77.6 16.5h.6M78.6 16.5h.6M79.5 16.5h.6M80.4 16.5h.6M81.4 16.5h.5"/>
<path d="M82.3 16.5h.6M83.2 16.5h.6M84.2 16.5h.5M85.1 16.5h.6M86 16.5h.6M87 16.5h.5M87.9 16.5h.6M88.8 16.5h.6M89.8 16.5h.5M90.7 16.5h.6M91.6 16.5h.6M92.5 16.5h.6"/>
<path d="M93.5 16.5h.6M94.4 16.5h.6M95.3 16.5h.6M96.3 16.5h.6M97.2 16.5h.6M98.1 16.5h.6M99.1 16.5h.6M100 16.5h.6M100.9 16.5h.6M101.9 16.5h.5M102.8 16.5h.6M103.7 16.5h.6"/>
<path d="M104.7 16.5h.5M105.6 16.5h.6M106.5 16.5h.6M107.5 16.5h.5M108.4 16.5h.6M109.3 16.5h.6M110.3 16.5h.5M111.2 16.5h.6M112.1 16.5h.6M113 16.5h.6M114 16.5h.6M114.9 16.5h.6"/>
<path d="M115.8 16.5h.6M116.8 16.5h.6M117.7 16.5h.6M118.6 16.5h.6M119.6 16.5h.6M120.5 16.5h.6M121.4 16.5h.6M122.4 16.5h.5M123.3 16.5h.6M124.2 16.5h.6M125.2 16.5h.5M126.1 16.5h.6"/>
<path d="M127 16.5h.6M128 16.5h.5M128.9 16.5h.6M129.8 16.5h.6M130.8 16.5h.5M131.7 16.5h.6M132.6 16.5h.6M133.5 16.5h.6M134.5 16.5h.6M135.4 16.5h.6M136.3 16.5h.6M137.3 16.5h.6"/>
<path d="M138.2 16.5h.6M139.1 16.5h.6M140.1 16.5h.6M141 16.5h.6M141.9 16.5h.6M142.9 16.5h.5M143.8 16.5h.6M144.7 16.5h.6M145.7 16.5h.5M146.6 16.5h.6M147.5 16.5h.6M148.5 16.5h.5"/>
<path d="M149.4 16.5h.6M150.3 16.5h.6M151.3 16.5h.5M152.2 16.5h.6M153.1 16.5h.6M154 16.5h.6M155 16.5h.6M155.9 16.5h.6M156.8 16.5h.6M157.8 16.5h.6M158.7 16.5h.6M159.6 16.5h.6"/>
<path d="M160.6 16.5v.6M160.6 17.4v.6M160.6 18.4v.5M160.6 19.3v.6M59.9 22.1h2.2M63.7 20.6v.6M63.7 21.5v.6M63.7 22.4v.6M63.7 23.4v.5M63.7 24.3v.6M63.7 25.2v.6M63.7 26.2v.5"/>
<path d="M63.7 27.1v.6M63.7 28v.6M63.7 29v.5M63.7 29.9v.6M63.7 30.8v.6M63.7 31.8v.5M63.7 32.7v.6M63.7 33.6v.6M63.7 34.5v.6M102.8 24h1.5M108.4 29.5h1.9M108.8 24h1.5"/>
<path d="M114 24h1.4M114 29.5h1.8M120 24h1.4M136.3 25.8v1.5M136.3 31.8v1.5M143.8 25.8v1.9M143.8 31.4v1.9M160.6 20.2v.6M160.6 21.2v.5"/>
</g>
<path d="M62.2 22.1l2.6 1.1M104.3 23.2h4.4v1.5h-4.4zM110.3 29.5h1.4M111.7 28.1v2.9M112.5 29.5h1.5M112.5 28.1v2.9M115.5 23.2h4.4v1.5h-4.4zM135.6 27.3h1.5v4.4h-1.5zM142.3 29.9h3M142.3 29.2h3M143.8 27.7v1.5M143.8 29.9v1.5" fill="none" stroke="#00f" stroke-width=".17"/>
<path d="M134.5 37h3.7M135 37.6h2.6M135.6 38.1h1.5M136.2 38.7h.3M136.3 35.1v1.9M141.9 37h3.8M142.5 37.6h2.6M143.1 38.1h1.4M143.6 38.7h.4M143.8 35.1v1.9" fill="none" stroke="#800000" stroke-width=".17"/>
<path d="M64.8 23.2l.3 .7h-.7z" fill="#00f"/>
<path d="M64.4 20.2h.7l-.3 .8zM64.8 23.2l.3 .7h-.7zM159.1 20.2h.7l-.3 .8zM162.1 22.1l-2.6 1.1" fill="none" stroke="#00f" stroke-width=".17"/>
<path d="M65.2 23.9h2.2M65.2 20.2h2.2M162.1 22.1h2.2" fill="none" stroke="#000" stroke-width=".17"/>
<path d="M159.5 23.2l.3 .8h-.7z" fill="#00f"/>
<path d="M159.5 23.2l.3 .8h-.7zM59.6 45.5h4.4v1.5h-4.4z" fill="none" stroke="#00f" stroke-width=".17"/>
<path d="M156.8 20.2h2.2M156.8 24h2.2M58.1 46.3h1.4M64.1 46.3h1.4" fill="none" stroke="#000" stroke-width=".17"/>
<circle cx="54.3" cy="46.3" r=".37" fill="#000080"/>
<circle cx="54.3" cy="46.3" r=".37" fill="none" stroke="#000080" stroke-width=".13"/>
<path d="M54.3 44.4v1.9" fill="none" stroke="#000" stroke-width=".17"/>
<circle cx="54.3" cy="46.3" r=".37" fill="#000080"/>
<circle cx="54.3" cy="46.3" r=".37" fill="none" stroke="#000080" stroke-width=".13"/>
<circle cx="54.3" cy="43.5" r=".93" fill="none" stroke="#000" stroke-width=".17"/>
<path d="M168 45.4h6.6l.9 .9-.9 .9h-6.6z" fill-rule="evenodd" fill="#ffff80"/>
<path d="M168 45.4h6.6l.9 .9-.9 .9h-6.6z" fill="none" stroke="#800000" stroke-width=".13"/>
<path d="M203.4 37h3.8M204 37.6h2.6M204.6 38.1h1.4M205.1 38.7h.4M205.3 35.1v1.9" fill="none" stroke="#800000" stroke-width=".17"/>
<path d="M205.3 25.8v1.9M205.3 31.4v1.9" fill="none" stroke="#000" stroke-width=".17"/>
<path d="M203.8 29.2h3M203.8 29.9h3M205.3 27.7v1.5M205.3 29.9v1.5" fill="none" stroke="#00f" stroke-width=".17"/>
<path d="M185.2 29.2h2.9v4.4h-2.9z" fill-rule="evenodd" fill="#ffffb0"/>
<path d="M185.2 29.2h2.9v4.4h-2.9z" fill="none" stroke="#800000" stroke-width=".13"/>
<path d="M185.6 29.9h.7M185.9 29.6v.7M188.1 29.2l-2.9 4.4M188.1 29.2h-2.9v4.4M188.1 29.2v4.4h-2.9" fill="none" stroke="#00f" stroke-width=".17"/>
<path d="M182.9 31.4h2.2M182.9 38.9h2.8M187.6 38.9h2.8M188.2 31.4h2.2" fill="none" stroke="#000" stroke-width=".17"/>
<path d="M178.3 27.7h1.8M179.2 27.7v1.8" fill="none" stroke="#800000" stroke-width=".17"/>
<path d="M185.6 38.9l2.2-1.5v2.9z" fill="#00f"/>
<path d="M185.6 38.9l2.2-1.5v2.9zM185.6 37.4v2.9M192.3 46.3h1.6M193.9 44.7v3.3M194.3 45h1.7M194.3 46.3h1.7v1.9M194.3 47.6h1.7M194.3 44.7v.7M194.3 46v.7M194.3 47.2v.8" fill="none" stroke="#00f" stroke-width=".17"/>
<path d="M190.4 46.3h1.9M196 42.6v1.8M196 48.2v1.8" fill="none" stroke="#000" stroke-width=".17"/>
<path d="M194.3 46.3l1.1-.3v.7z" fill="#00f"/>
<path d="M194.3 46.3l1.1-.3v.7z" fill="none" stroke="#00f" stroke-width=".13"/>
<path d="M185.2 22.1l2.6 1.1M178.5 49.7h1.5v4.4h-1.5zM196 44.4v.6" fill="none" stroke="#00f" stroke-width=".17"/>
<path d="M177.3 59.4h3.8M177.9 59.9h2.6M179.2 57.5v1.9M194.1 59.4h3.7M194.7 59.9h2.6M196 57.5v1.9M178.5 60.5h1.5M179 61h.4M195.2 60.5h1.5M195.8 61h.4" fill="none" stroke="#800000" stroke-width=".17"/>
<g fill="none" stroke="#000" stroke-width=".17">
<path d="M186.7 16.8v.6M186.7 17.8v.6M186.7 18.7v.6M186.7 19.6v.6M186.7 16.5h.6M187.6 16.5h.6M188.5 16.5h.6M189.5 16.5h.5M190.4 16.5h.6M191.3 16.5h.6M192.3 16.5h.5M193.2 16.5h.6"/>
<path d="M194.1 16.5h.6M195.1 16.5h.5M196 16.5h.6M196.9 16.5h.6M197.8 16.5h.6M198.8 16.5h.6M199.7 16.5h.6M200.6 16.5h.6M201.6 16.5h.6M202.5 16.5h.6M203.4 16.5h.6M204.4 16.5h.6"/>
<path d="M205.3 16.5h.6M206.2 16.5h.6M207.2 16.5h.6M208.1 16.5h.6M209 16.5h.6M210 16.5h.5M210.9 16.5h.6M211.8 16.5h.6M212.8 16.5h.5M213.7 16.5h.6M214.6 16.5h.6M215.6 16.5h.5"/>
<path d="M216.5 16.5h.6M217.4 16.5h.6M218.3 16.5h.6M219.3 16.5h.6M220.2 16.5h.6M221.1 16.5h.6M222.1 16.5h.6M223 16.5h.6M223.9 16.5h.6M224.9 16.5h.6M225.8 16.5h.6M226.7 16.5h.6"/>
<path d="M227.7 16.5h.6M228.6 16.5h.6M229.5 16.5h.6M230.5 16.5h.5M231.4 16.5h.6M232.3 16.5h.6M233.3 16.5v.6M233.3 17.4v.6M182.9 22.1h2.2M186.7 20.6v.6M186.7 21.5v.6M186.7 22.4v.6"/>
<path d="M186.7 23.4v.6M186.7 24.3v.6M186.7 25.2v.6M186.7 26.2v.5M186.7 27.1v.6M186.7 28v.6M186.7 29v.5M186.7 29.9v.6M186.7 30.8v.6M186.7 31.8v.5M186.7 32.7v.6M179.2 48.2v1.4"/>
<path d="M179.2 54.2v1.4"/>
</g>
<path d="M187.8 23.2l.3 .8h-.7z" fill="#00f"/>
<path d="M187.4 20.2h.7l-.3 .8zM187.8 23.2l.3 .8h-.7zM231.8 20.2h.7l-.3 .8zM234.7 22.1l-2.5 1.1" fill="none" stroke="#00f" stroke-width=".17"/>
<path d="M188.2 24h2.2M188.2 20.2h2.2M234.8 22.1h2.2" fill="none" stroke="#000" stroke-width=".17"/>
<path d="M232.2 23.2l.3 .8h-.7z" fill="#00f"/>
<path d="M232.2 23.2l.3 .8h-.7zM182.6 45.5h4.4v1.5h-4.4z" fill="none" stroke="#00f" stroke-width=".17"/>
<path d="M229.5 20.2h2.2M229.5 24h2.2M181.1 46.3h1.4M187.1 46.3h1.4" fill="none" stroke="#000" stroke-width=".17"/>
<circle cx="177.3" cy="46.3" r=".37" fill="#000080"/>
<circle cx="177.3" cy="46.3" r=".37" fill="none" stroke="#000080" stroke-width=".13"/>
<path d="M177.3 44.4v1.9" fill="none" stroke="#000" stroke-width=".17"/>
<circle cx="177.3" cy="46.3" r=".37" fill="#000080"/>
<circle cx="177.3" cy="46.3" r=".37" fill="none" stroke="#000080" stroke-width=".13"/>
<g fill="none" stroke="#000" stroke-width=".17">
<path d="M76.7 23.9h1.5M82.7 23.9h1.5M87.9 25.8v1.9M87.9 31.4v1.9M194.1 24h1.5M200.1 24h1.5M201.6 20.2h1.4M207.6 20.2h1.4M212.8 20.2h1.4M218.7 20.2h1.5M223.9 25.8v1.5M223.9 31.8v1.5"/>
<circle cx="177.3" cy="43.5" r=".93"/>
</g>
<path d="M203.1 19.5h4.4v1.5h-4.4zM214.3 19.5h4.4v1.5h-4.4zM78.2 23.2h4.4v1.5h-4.4zM86.4 29.9h3M86.4 29.2h3M87.9 27.7v1.5M87.9 29.9v1.5M195.6 23.2h4.4v1.5h-4.4zM223.2 27.3h1.5v4.4h-1.5z" fill="none" stroke="#00f" stroke-width=".17"/>
<g fill="none" stroke="#800000" stroke-width=".17">
<path d="M86 37h3.8M86.6 37.6h2.6M87.1 38.1h1.5M87.7 38.7h.4M87.9 35.1v1.9M222.1 37h3.7M222.6 37.6h2.6M223.2 38.1h1.5M223.8 38.7h.3M223.9 35.1v1.9M46.9 143.2h3.7M47.4 143.8h2.7"/>
<path d="M48 144.3h1.5M48.6 144.9h.3M48.8 141.4v1.8"/>
</g>
<path d="M65.5 115.3l14.9 7.4-14.9 7.5z" fill="#ffffb0"/>
<path d="M65.5 115.3l14.9 7.4-14.9 7.5z" fill="none" stroke="#800000" stroke-width=".13"/>
<g fill="none" stroke="#000" stroke-width=".17">
<path d="M48.8 107.8v1.5M48.8 113.8v1.5M59.9 119h5.6M69.3 111.5v5.6M71.1 105.9h1.5M77.1 105.9h1.5M80.4 105.9h1.9M86 105.9h1.9M155 109.7v1.4M155 115.7v1.4M156.8 119h1.5M162.8 119h1.5"/>
<path d="M48.8 132v1.5M48.8 138v1.5M59.9 126.4h5.6M69.3 128.3v5.6M73 126.4v5.6M73 139.5h1.8M76.7 124.6v5.6M78.6 139.5h1.8M80.4 122.7h5.6M89.8 122.7h1.4M95.7 122.7h1.5M155 126.4v1.5"/>
<path d="M155 132.4v1.5M155 137.6v1.5M166.2 120.9v1.8M166.2 126.4v1.9M155 143.6v1.5M106.5 165.6v1.8M106.5 171.2v1.8M114 165.6v1.8M114 171.2v1.8M121.4 165.6v1.8M121.4 171.2v1.8M128.9 165.6v1.8"/>
<path d="M128.9 171.2v1.8M136.3 165.6v1.8M136.3 171.2v1.8"/>
</g>
<path d="M72.2 131.3l1.5 1.5M73.7 131.3l-1.5 1.5M76 129.4l1.5 1.5M77.5 129.4l-1.5 1.5" fill="none" stroke="#f00" stroke-width=".13"/>
<g fill="none" stroke="#00f" stroke-width=".17">
<path d="M48 109.3h1.5v4.4h-1.5zM72.6 105.2h4.4v1.5h-4.4zM82.3 105.9h1.5M83.8 104.5v2.9M84.5 105.9h1.5M84.5 104.5v2.9M154.3 111.2h1.5v4.4h-1.5zM158.4 118.2h4.4v1.5h-4.4zM48 133.6h1.5v4.4h-1.5zM74.8 139.5h1.5M76.3 138v3M77.1 139.5h1.5"/>
<path d="M77.1 138v3M91.3 121.9h4.4v1.5h-4.4zM154.3 128h1.5v4.4h-1.5zM154.3 139.2h1.5v4.4h-1.5zM164.7 124.2h2.9M164.7 125h2.9M166.2 122.7v1.5M166.2 125v1.4M105.1 168.9h2.9M105.1 169.7h2.9M106.5 167.4v1.5M106.5 169.7v1.5"/>
<path d="M112.5 168.9h2.9M112.5 169.7h2.9M114 167.4v1.5M114 169.7v1.5M120 168.9h2.9M120 169.7h2.9M121.4 167.4v1.5M121.4 169.7v1.5M127.4 168.9h3M127.4 169.7h3M128.9 167.4v1.5M128.9 169.7v1.5"/>
<path d="M134.9 168.9h2.9M134.9 169.7h2.9M136.3 167.4v1.5M136.3 169.7v1.5"/>
</g>
<path d="M176.4 115.3h1.9M177.3 115.3v1.8M164.3 130.2h3.7M164.9 130.7h2.6M165.4 131.3h1.5M166 131.9h.3M166.2 128.3v1.9M153.1 148.8h3.7M153.7 149.4h2.6M154.2 149.9h1.5M154.8 150.5h.4M155 146.9v1.9" fill="none" stroke="#800000" stroke-width=".17"/>
<path d="M110.3 96.6h18.6v28h-18.6z" fill-rule="evenodd" fill="#ffffb0"/>
<path d="M110.3 96.6h18.6v28h-18.6z" fill="none" stroke="#800000" stroke-width=".13"/>
<g fill="none" stroke="#000" stroke-width=".17">
<path d="M104.7 98.5h5.6M95.3 109.7h1.5M101.3 109.7h1.5M104.7 102.2h5.6M104.7 105.9h5.6M104.7 109.7h5.6M104.7 113.4h5.6M104.7 117.1h5.6M104.7 119h5.6M104.7 100.4h5.6M128.9 105.9h5.6M128.9 109.7h7"/>
<path d="M128.9 113.4h5.6M128.9 117.1h5.6M128.9 119h5.6M140.5 109.7h1.4M99.1 124.6v1.8M99.1 130.2v1.8M104.7 120.9h5.6M104.7 122.7h5.6M128.9 120.9h5.6M128.9 122.7h5.6M136.3 124.6v1.5M136.3 130.6v1.4"/>
<path d="M166.2 137.6v1.5M162.4 141.4h3M166.2 143.6v1.5M43.2 161.9v1.4M43.2 167.8v1.5M99.1 165.6v1.8M99.1 171.2v1.8M106.5 176.8v1.8M114 176.8v1.8M121.4 176.8v1.8M128.9 176.8v1.8M106.5 182.4v1.8"/>
<path d="M114 182.4v1.8M121.4 182.4v1.8M128.9 182.4v1.8"/>
</g>
<path d="M103.9 116.4l1.5 1.5M103.9 118.3l1.5 1.4M105.4 116.4l-1.5 1.5M105.4 118.3l-1.5 1.4M103.9 120.1l1.5 1.5M105.4 120.1l-1.5 1.5M165.4 136.9l1.5 1.5M166.9 136.9l-1.5 1.5" fill="none" stroke="#f00" stroke-width=".13"/>
<g fill="none" stroke="#800000" stroke-width=".17">
<path d="M97.2 135.8h3.7M97.8 136.3h2.6M98.3 136.9h1.5M98.9 137.4h.4M99.1 133.9v1.9M102.8 135.8h3.7M103.4 136.3h2.6M103.9 136.9h1.5M104.5 137.4h.3M104.7 133.9v1.9M134.5 135.8h3.7M135 136.3h2.6"/>
<path d="M135.6 136.9h1.5M136.2 137.4h.3M136.3 133.9v1.9M164.3 148.8h3.7M164.9 149.4h2.6M165.4 149.9h1.5M166 150.5h.3M166.2 146.9v1.9M75 174.7v.4M75.6 174.2v1.5M76.1 173.6v2.6M76.7 162.8v1.9"/>
<path d="M76.7 173v3.8M76.7 163.7h1.9M76.7 174.9h1.9M76.7 185.2v1.8M76.7 186.1h1.9"/>
</g>
<g fill="none" stroke="#00f" stroke-width=".17">
<path d="M96.9 108.9h4.4v1.5h-4.4zM136 109h4.4v1.5h-4.4zM97.6 128.7h2.9M97.6 127.9h2.9M99.1 126.4v1.5M99.1 128.7v1.5M135.6 126.1h1.5v4.4h-1.5zM165.4 139.2h1.5v4.4h-1.5zM42.4 163.4h1.5v4.4h-1.5zM97.6 169.7h2.9M97.6 168.9h2.9M99.1 167.4v1.5"/>
<path d="M99.1 169.7v1.5M106.5 178.6v1.5M114 178.6v1.5M121.4 178.6v1.5M128.9 178.6v1.5M105.1 180.9h2.9M105.1 180.1h2.9M106.5 180.9v1.5M112.5 180.9h3M112.5 180.1h3M114 180.9v1.5M120 180.9h2.9"/>
<path d="M120 180.1h2.9M121.4 180.9v1.5M127.4 180.9h3M127.4 180.1h3M128.9 180.9v1.5"/>
</g>
<path d="M164.9 140.8l.5 .6-.5 .5z" fill="#000"/>
<path d="M164.9 140.8l.5 .6-.5 .5z" fill="none" stroke="#000" stroke-width=".13"/>
<circle cx="24.5" cy="176.8" r=".37" fill="#000080"/>
<circle cx="24.5" cy="176.8" r=".37" fill="none" stroke="#000080" stroke-width=".13"/>
<path d="M24.5 174.9v1.9" fill="none" stroke="#000" stroke-width=".17"/>
<circle cx="24.5" cy="176.8" r=".37" fill="#000080"/>
<circle cx="24.5" cy="176.8" r=".37" fill="none" stroke="#000080" stroke-width=".13"/>
<g fill="none" stroke="#000" stroke-width=".17">
<path d="M22.7 178.6v1.5M22.7 184.6v1.5"/>
<circle cx="24.5" cy="174" r=".93"/>
</g>
<path d="M21.9 180.2h1.5v4.4h-1.5z" fill="none" stroke="#00f" stroke-width=".17"/>
<path d="M20.8 189.8h3.7M21.4 190.4h2.6M21.9 190.9h1.5M22.5 191.5h.3M22.7 187.9v1.9" fill="none" stroke="#800000" stroke-width=".17"/>
<path d="M11.5 175.8h8.4l.9 1-.9 .9h-8.4z" fill-rule="evenodd" fill="#ffff80"/>
<path d="M11.5 175.8h8.4l.9 1-.9 .9h-8.4z" fill="none" stroke="#800000" stroke-width=".13"/>
<path d="M99.1 176.8v1.8M136.3 176.8v1.8M143.8 165.6v1.8M143.8 171.2v1.8M143.8 176.8v1.8M99.1 182.4v1.8M136.3 182.4v1.8M143.8 182.4v1.8" fill="none" stroke="#000" stroke-width=".17"/>
<g fill="none" stroke="#00f" stroke-width=".17">
<path d="M99.1 178.6v1.5M136.3 178.6v1.5M142.3 169.7h3M142.3 168.9h3M143.8 167.4v1.5M143.8 169.7v1.5M143.8 178.6v1.5M97.6 180.1h2.9M97.6 180.9h2.9M99.1 180.9v1.5M134.9 180.1h2.9M134.9 180.9h2.9"/>
<path d="M136.3 180.9v1.5M142.3 180.1h3M142.3 180.9h3M143.8 180.9v1.5"/>
</g>
<path d="M28.3 115.3h11.1v11.1h-11.1z" fill-rule="evenodd" fill="#ffffb0"/>
<path d="M28.3 115.3h11.1v11.1h-11.1z" fill="none" stroke="#800000" stroke-width=".13"/>
<path d="M22.7 117.1h5.6M39.4 117.1h5.6M22.7 124.6h5.6M22.7 120.9h5.6M39.4 124.6h5.6" fill="none" stroke="#000" stroke-width=".17"/>
<circle cx="48.8" cy="117.1" r=".37" fill="#000080"/>
<circle cx="48.8" cy="117.1" r=".37" fill="none" stroke="#000080" stroke-width=".13"/>
<circle cx="48.8" cy="124.6" r=".37" fill="#000080"/>
<circle cx="48.8" cy="124.6" r=".37" fill="none" stroke="#000080" stroke-width=".13"/>
<path d="M48.8 117.1v1.9" fill="none" stroke="#000" stroke-width=".17"/>
<circle cx="48.8" cy="117.1" r=".37" fill="#000080"/>
<circle cx="48.8" cy="117.1" r=".37" fill="none" stroke="#000080" stroke-width=".13"/>
<path d="M48.8 122.7v1.9" fill="none" stroke="#000" stroke-width=".17"/>
<circle cx="48.8" cy="124.6" r=".37" fill="#000080"/>
<circle cx="48.8" cy="124.6" r=".37" fill="none" stroke="#000080" stroke-width=".13"/>
<path d="M48.8 119v1.5M47.3 120.5h2.9M47.3 121.2h2.9M48.8 121.2v1.5M39.4 176.8h1.7M41.1 175.1v3.3M41.5 175.5h1.7M41.5 176.8h1.7v1.8M41.5 178.1h1.7M41.5 175.1v.8M41.5 176.4v.7M41.5 177.7v.7" fill="none" stroke="#00f" stroke-width=".17"/>
<path d="M37.6 176.8h1.8M43.2 173v1.9M43.2 178.6v1.9" fill="none" stroke="#000" stroke-width=".17"/>
<path d="M41.5 176.8l1.1-.4v.7z" fill="#00f"/>
<path d="M41.5 176.8l1.1-.4v.7z" fill="none" stroke="#00f" stroke-width=".13"/>
<g fill="none" stroke="#00f" stroke-width=".17">
<path d="M61.5 105.2h4.4v1.5h-4.4zM169.6 118.3h4.4v1.5h-4.4zM193.8 118.3h4.4v1.5h-4.4zM175.9 124.2h2.9M175.9 125h2.9M177.3 122.7v1.5M177.3 125v1.4M188.9 124.2h3M188.9 125h3M190.4 122.7v1.5M190.4 125v1.4M196 136.7h.9l-.9 1.9h-.9z"/>
<path d="M264.9 136.7h1l-1 1.9h-.9zM188.9 142.9h3M188.9 143.6h3M190.4 141.4v1.5M190.4 143.6v1.5M269.1 142.9h2.9M269.1 143.6h2.9M270.5 141.4v1.5M270.5 143.6v1.5M29.8 176h4.4v1.5h-4.4zM43.2 174.9v.6M80.8 169.7h3"/>
<path d="M80.8 168.9h3M82.3 167.4v1.5M82.3 169.7v1.5M82.3 178.6v1.5M87.9 162.8h.9l-.9 1.9h-.9zM80.8 180.9h3M80.8 180.1h3M82.3 180.9v1.5M87.9 185.2h.9l-.9 1.8h-.9z"/>
</g>
<g fill="none" stroke="#800000" stroke-width=".17">
<path d="M189.5 115.3h1.8M190.4 115.3v1.8M175.5 130.2h3.7M176 130.7h2.6M176.6 131.3h1.5M177.2 131.9h.3M177.3 128.3v1.9M188.5 130.2h3.8M189.1 130.7h2.6M189.6 131.3h1.5M190.2 131.9h.4M190.4 128.3v1.9"/>
<path d="M188.5 148.8h3.8M189.1 149.4h2.6M189.6 149.9h1.5M190.2 150.5h.4M190.4 146.9v1.9M268.7 148.8h3.7M269.2 149.4h2.6M269.8 149.9h1.5M270.3 150.5h.4M270.5 146.9v1.9M41.3 189.8h3.7M41.9 190.4h2.6"/>
<path d="M42.4 190.9h1.5M43 191.5h.3M43.2 187.9v1.9"/>
</g>
<g fill="none" stroke="#000" stroke-width=".17">
<path d="M59.9 105.9h1.5M65.9 105.9h1.5M168 119h1.5M174 119h1.5M192.3 119h1.4M198.2 119h1.5M177.3 120.9v1.8M177.3 126.4v1.9M190.4 120.9v1.8M190.4 126.4v1.9M190.4 139.5v1.9M192.3 137.6h3.2"/>
<path d="M196.4 137.6h3.3M261.2 137.6h3.3M265.4 137.6h3.3M270.5 139.5v1.9M190.4 145.1v1.8M270.5 145.1v1.8M28.3 176.8h1.4M34.2 176.8h1.5M82.3 165.6v1.8M82.3 171.2v1.8M82.3 176.8v1.8M84.2 163.7h3.2"/>
<path d="M88.4 163.7h3.2M82.3 182.4v1.8M84.2 186.1h3.2M88.4 186.1h3.2"/>
</g>
<path d="M26.4 25.8v3.7M210.9 98.5h7.4M192.3 105.9h26M210.9 100.4h7.4M216.5 119h1.8" fill="none" stroke="#000080" stroke-width=".17"/>
<circle cx="216.5" cy="119" r=".37" fill="#000080"/>
<circle cx="216.5" cy="119" r=".37" fill="none" stroke="#000080" stroke-width=".13"/>
<path d="M251.9 96.6h3.7M251.9 111.5h1.9" fill="none" stroke="#000080" stroke-width=".17"/>
<circle cx="255.6" cy="96.6" r=".37" fill="#000080"/>
<circle cx="255.6" cy="96.6" r=".37" fill="none" stroke="#000080" stroke-width=".13"/>
<path d="M216.5 120.9v1.8" fill="none" stroke="#000080" stroke-width=".17"/>
<circle cx="216.5" cy="120.9" r=".37" fill="#000080"/>
<circle cx="216.5" cy="120.9" r=".37" fill="none" stroke="#000080" stroke-width=".13"/>
<path d="M216.5 94.8v1.8" fill="none" stroke="#000080" stroke-width=".17"/>
<circle cx="216.5" cy="96.6" r=".37" fill="#000080"/>
<circle cx="216.5" cy="96.6" r=".37" fill="none" stroke="#000080" stroke-width=".13"/>
<path d="M261.2 98.5v1.9h-9.3M263.1 107.8v11.2h-1.9M274.3 105.9h1.8M274.3 107.8h1.8" fill="none" stroke="#000080" stroke-width=".17"/>
<circle cx="263.1" cy="107.8" r=".37" fill="#000080"/>
<circle cx="263.1" cy="107.8" r=".37" fill="none" stroke="#000080" stroke-width=".13"/>
<path d="M257.5 137.6v1.9" fill="none" stroke="#000080" stroke-width=".17"/>
<circle cx="257.5" cy="137.6" r=".37" fill="#000080"/>
<circle cx="257.5" cy="137.6" r=".37" fill="none" stroke="#000080" stroke-width=".13"/>
<path d="M246.3 137.6h-5.6v1.9" fill="none" stroke="#000080" stroke-width=".17"/>
<circle cx="246.3" cy="137.6" r=".37" fill="#000080"/>
<circle cx="246.3" cy="137.6" r=".37" fill="none" stroke="#000080" stroke-width=".13"/>
<path d="M251.9 137.6h-5.6v1.9" fill="none" stroke="#000080" stroke-width=".17"/>
<circle cx="246.3" cy="137.6" r=".37" fill="#000080"/>
<circle cx="246.3" cy="137.6" r=".37" fill="none" stroke="#000080" stroke-width=".13"/>
<circle cx="251.9" cy="137.6" r=".37" fill="#000080"/>
<circle cx="251.9" cy="137.6" r=".37" fill="none" stroke="#000080" stroke-width=".13"/>
<path d="M264.9 105.9v13.1h1.9M229.5 135.8v3.7" fill="none" stroke="#000080" stroke-width=".17"/>
<circle cx="264.9" cy="105.9" r=".37" fill="#000080"/>
<circle cx="264.9" cy="105.9" r=".37" fill="none" stroke="#000080" stroke-width=".13"/>
<path d="M52.5 46.3h3.7" fill="none" stroke="#000080" stroke-width=".17"/>
<circle cx="56.2" cy="46.3" r=".37" fill="#000080"/>
<circle cx="56.2" cy="46.3" r=".37" fill="none" stroke="#000080" stroke-width=".13"/>
<circle cx="54.3" cy="46.3" r=".37" fill="#000080"/>
<circle cx="54.3" cy="46.3" r=".37" fill="none" stroke="#000080" stroke-width=".13"/>
<path d="M58.1 46.3h-1.9v1.9" fill="none" stroke="#000080" stroke-width=".17"/>
<circle cx="56.2" cy="46.3" r=".37" fill="#000080"/>
<circle cx="56.2" cy="46.3" r=".37" fill="none" stroke="#000080" stroke-width=".13"/>
<path d="M56.2 31.4v7.5h3.7" fill="none" stroke="#000080" stroke-width=".17"/>
<circle cx="56.2" cy="31.4" r=".37" fill="#000080"/>
<circle cx="56.2" cy="31.4" r=".37" fill="none" stroke="#000080" stroke-width=".13"/>
<path d="M56.2 29.5v1.9h3.7" fill="none" stroke="#000080" stroke-width=".17"/>
<circle cx="56.2" cy="31.4" r=".37" fill="#000080"/>
<circle cx="56.2" cy="31.4" r=".37" fill="none" stroke="#000080" stroke-width=".13"/>
<path d="M67.4 38.9h5.6M65.5 46.3h1.9" fill="none" stroke="#000080" stroke-width=".17"/>
<circle cx="73" cy="38.9" r=".37" fill="#000080"/>
<circle cx="73" cy="38.9" r=".37" fill="none" stroke="#000080" stroke-width=".13"/>
<path d="M67.4 31.4h5.6v11.2M110.3 24h3.7M136.3 33.3v1.8M56.2 55.6v1.9M73 50v7.5" fill="none" stroke="#000080" stroke-width=".17"/>
<circle cx="73" cy="38.9" r=".37" fill="#000080"/>
<circle cx="73" cy="38.9" r=".37" fill="none" stroke="#000080" stroke-width=".13"/>
<path d="M164.3 22.1h18.6M205.3 33.3v1.8M175.5 46.3h3.7" fill="none" stroke="#000080" stroke-width=".17"/>
<circle cx="179.2" cy="46.3" r=".37" fill="#000080"/>
<circle cx="179.2" cy="46.3" r=".37" fill="none" stroke="#000080" stroke-width=".13"/>
<circle cx="177.3" cy="46.3" r=".37" fill="#000080"/>
<circle cx="177.3" cy="46.3" r=".37" fill="none" stroke="#000080" stroke-width=".13"/>
<path d="M181.1 46.3h-1.9v1.9" fill="none" stroke="#000080" stroke-width=".17"/>
<circle cx="179.2" cy="46.3" r=".37" fill="#000080"/>
<circle cx="179.2" cy="46.3" r=".37" fill="none" stroke="#000080" stroke-width=".13"/>
<path d="M179.2 31.4v7.5h3.7" fill="none" stroke="#000080" stroke-width=".17"/>
<circle cx="179.2" cy="31.4" r=".37" fill="#000080"/>
<circle cx="179.2" cy="31.4" r=".37" fill="none" stroke="#000080" stroke-width=".13"/>
<path d="M179.2 29.5v1.9h3.7" fill="none" stroke="#000080" stroke-width=".17"/>
<circle cx="179.2" cy="31.4" r=".37" fill="#000080"/>
<circle cx="179.2" cy="31.4" r=".37" fill="none" stroke="#000080" stroke-width=".13"/>
<path d="M190.4 38.9h5.6M188.5 46.3h1.9" fill="none" stroke="#000080" stroke-width=".17"/>
<circle cx="196" cy="38.9" r=".37" fill="#000080"/>
<circle cx="196" cy="38.9" r=".37" fill="none" stroke="#000080" stroke-width=".13"/>
<path d="M190.4 31.4h5.6v11.2M179.2 55.6v1.9M196 50v7.5" fill="none" stroke="#000080" stroke-width=".17"/>
<circle cx="196" cy="38.9" r=".37" fill="#000080"/>
<circle cx="196" cy="38.9" r=".37" fill="none" stroke="#000080" stroke-width=".13"/>
<path d="M67.4 20.2h89.4M87.9 33.3v1.8M143.8 33.3v1.8M190.4 20.2h11.2M190.4 24h3.7M201.6 24h27.9M209 20.2h3.8M223.9 33.3v1.8M237 22.1h11.2" fill="none" stroke="#000080" stroke-width=".17"/>
<circle cx="205.3" cy="23.9" r=".37" fill="#000080"/>
<circle cx="205.3" cy="23.9" r=".37" fill="none" stroke="#000080" stroke-width=".13"/>
<path d="M205.3 24v1.8" fill="none" stroke="#000080" stroke-width=".17"/>
<circle cx="205.3" cy="23.9" r=".37" fill="#000080"/>
<circle cx="205.3" cy="23.9" r=".37" fill="none" stroke="#000080" stroke-width=".13"/>
<path d="M220.2 20.2h9.3" fill="none" stroke="#000080" stroke-width=".17"/>
<circle cx="223.9" cy="20.2" r=".37" fill="#000080"/>
<circle cx="223.9" cy="20.2" r=".37" fill="none" stroke="#000080" stroke-width=".13"/>
<path d="M223.9 20.2v5.6" fill="none" stroke="#000080" stroke-width=".17"/>
<circle cx="223.9" cy="20.2" r=".37" fill="#000080"/>
<circle cx="223.9" cy="20.2" r=".37" fill="none" stroke="#000080" stroke-width=".13"/>
<path d="M136.3 24v1.8" fill="none" stroke="#000080" stroke-width=".17"/>
<circle cx="136.3" cy="23.9" r=".37" fill="#000080"/>
<circle cx="136.3" cy="23.9" r=".37" fill="none" stroke="#000080" stroke-width=".13"/>
<path d="M30.1 22.1h29.8M166.2 119v1.9" fill="none" stroke="#000080" stroke-width=".17"/>
<circle cx="166.2" cy="119" r=".37" fill="#000080"/>
<circle cx="166.2" cy="119" r=".37" fill="none" stroke="#000080" stroke-width=".13"/>
<path d="M86 122.7h1.9v16.8h-7.5" fill="none" stroke="#000080" stroke-width=".17"/>
<circle cx="87.9" cy="122.7" r=".37" fill="#000080"/>
<circle cx="87.9" cy="122.7" r=".37" fill="none" stroke="#000080" stroke-width=".13"/>
<path d="M155 119h1.8" fill="none" stroke="#000080" stroke-width=".17"/>
<circle cx="155" cy="119" r=".37" fill="#000080"/>
<circle cx="155" cy="119" r=".37" fill="none" stroke="#000080" stroke-width=".13"/>
<path d="M99.1 163.7v1.9" fill="none" stroke="#000080" stroke-width=".17"/>
<circle cx="99.1" cy="163.7" r=".37" fill="#000080"/>
<circle cx="99.1" cy="163.7" r=".37" fill="none" stroke="#000080" stroke-width=".13"/>
<path d="M114 163.7v1.9" fill="none" stroke="#000080" stroke-width=".17"/>
<circle cx="114" cy="163.7" r=".37" fill="#000080"/>
<circle cx="114" cy="163.7" r=".37" fill="none" stroke="#000080" stroke-width=".13"/>
<path d="M121.4 163.7v1.9" fill="none" stroke="#000080" stroke-width=".17"/>
<circle cx="121.4" cy="163.7" r=".37" fill="#000080"/>
<circle cx="121.4" cy="163.7" r=".37" fill="none" stroke="#000080" stroke-width=".13"/>
<path d="M48.8 139.5v1.9M128.9 163.7v1.9" fill="none" stroke="#000080" stroke-width=".17"/>
<circle cx="128.9" cy="163.7" r=".37" fill="#000080"/>
<circle cx="128.9" cy="163.7" r=".37" fill="none" stroke="#000080" stroke-width=".13"/>
<path d="M78.6 105.9h1.8M87.9 122.7h1.9M155 145.1v1.8" fill="none" stroke="#000080" stroke-width=".17"/>
<circle cx="87.9" cy="122.7" r=".37" fill="#000080"/>
<circle cx="87.9" cy="122.7" r=".37" fill="none" stroke="#000080" stroke-width=".13"/>
<path d="M141.9 109.7h1.9v3.7M104.7 122.7v11.2M136.3 132v1.9" fill="none" stroke="#000080" stroke-width=".17"/>
<circle cx="143.8" cy="109.7" r=".37" fill="#000080"/>
<circle cx="143.8" cy="109.7" r=".37" fill="none" stroke="#000080" stroke-width=".13"/>
<circle cx="143.8" cy="113.4" r=".37" fill="#000080"/>
<circle cx="143.8" cy="113.4" r=".37" fill="none" stroke="#000080" stroke-width=".13"/>
<path d="M102.8 100.4h1.9" fill="none" stroke="#000080" stroke-width=".17"/>
<circle cx="102.8" cy="100.4" r=".37" fill="#000080"/>
<circle cx="102.8" cy="100.4" r=".37" fill="none" stroke="#000080" stroke-width=".13"/>
<path d="M102.8 98.5h1.9" fill="none" stroke="#000080" stroke-width=".17"/>
<circle cx="102.8" cy="98.5" r=".37" fill="#000080"/>
<circle cx="102.8" cy="98.5" r=".37" fill="none" stroke="#000080" stroke-width=".13"/>
<path d="M99.1 122.7v1.9" fill="none" stroke="#000080" stroke-width=".17"/>
<circle cx="99.1" cy="122.7" r=".37" fill="#000080"/>
<circle cx="99.1" cy="122.7" r=".37" fill="none" stroke="#000080" stroke-width=".13"/>
<path d="M99.1 132v1.9M155 135.8h5.6v5.6h1.8M166.2 145.1v1.8" fill="none" stroke="#000080" stroke-width=".17"/>
<circle cx="155" cy="135.8" r=".37" fill="#000080"/>
<circle cx="155" cy="135.8" r=".37" fill="none" stroke="#000080" stroke-width=".13"/>
<path d="M121.4 184.2v1.9" fill="none" stroke="#000080" stroke-width=".17"/>
<circle cx="121.4" cy="186.1" r=".37" fill="#000080"/>
<circle cx="121.4" cy="186.1" r=".37" fill="none" stroke="#000080" stroke-width=".13"/>
<path d="M114 184.2v1.9" fill="none" stroke="#000080" stroke-width=".17"/>
<circle cx="114" cy="186.1" r=".37" fill="#000080"/>
<circle cx="114" cy="186.1" r=".37" fill="none" stroke="#000080" stroke-width=".13"/>
<path d="M106.5 184.2v1.9" fill="none" stroke="#000080" stroke-width=".17"/>
<circle cx="106.5" cy="186.1" r=".37" fill="#000080"/>
<circle cx="106.5" cy="186.1" r=".37" fill="none" stroke="#000080" stroke-width=".13"/>
<path d="M93.5 105.9v3.8h1.8M102.8 109.7h1.9" fill="none" stroke="#000080" stroke-width=".17"/>
<circle cx="93.5" cy="105.9" r=".37" fill="#000080"/>
<circle cx="93.5" cy="105.9" r=".37" fill="none" stroke="#000080" stroke-width=".13"/>
<path d="M134.5 113.4h9.3v3.7h-9.3M134.5 122.7h1.8v1.9" fill="none" stroke="#000080" stroke-width=".17"/>
<circle cx="143.8" cy="117.1" r=".37" fill="#000080"/>
<circle cx="143.8" cy="117.1" r=".37" fill="none" stroke="#000080" stroke-width=".13"/>
<circle cx="143.8" cy="113.4" r=".37" fill="#000080"/>
<circle cx="143.8" cy="113.4" r=".37" fill="none" stroke="#000080" stroke-width=".13"/>
<path d="M143.8 117.1v1.9" fill="none" stroke="#000080" stroke-width=".17"/>
<circle cx="143.8" cy="119" r=".37" fill="#000080"/>
<circle cx="143.8" cy="119" r=".37" fill="none" stroke="#000080" stroke-width=".13"/>
<circle cx="143.8" cy="117.1" r=".37" fill="#000080"/>
<circle cx="143.8" cy="117.1" r=".37" fill="none" stroke="#000080" stroke-width=".13"/>
<path d="M104.7 113.4h-5.6v9.3h-1.9" fill="none" stroke="#000080" stroke-width=".17"/>
<circle cx="99.1" cy="122.7" r=".37" fill="#000080"/>
<circle cx="99.1" cy="122.7" r=".37" fill="none" stroke="#000080" stroke-width=".13"/>
<path d="M99.1 184.2v1.9" fill="none" stroke="#000080" stroke-width=".17"/>
<circle cx="99.1" cy="186.1" r=".37" fill="#000080"/>
<circle cx="99.1" cy="186.1" r=".37" fill="none" stroke="#000080" stroke-width=".13"/>
<path d="M128.9 184.2v1.9" fill="none" stroke="#000080" stroke-width=".17"/>
<circle cx="128.9" cy="186.1" r=".37" fill="#000080"/>
<circle cx="128.9" cy="186.1" r=".37" fill="none" stroke="#000080" stroke-width=".13"/>
<path d="M22.7 176.8v1.8M22.7 186.1v1.8" fill="none" stroke="#000080" stroke-width=".17"/>
<circle cx="22.7" cy="176.8" r=".37" fill="#000080"/>
<circle cx="22.7" cy="176.8" r=".37" fill="none" stroke="#000080" stroke-width=".13"/>
<path d="M155 122.7h-5.6v22.4h-89.5v-5.6h13.1" fill="none" stroke="#000080" stroke-width=".17"/>
<circle cx="155" cy="122.7" r=".37" fill="#000080"/>
<circle cx="155" cy="122.7" r=".37" fill="none" stroke="#000080" stroke-width=".13"/>
<circle cx="59.9" cy="139.5" r=".37" fill="#000080"/>
<circle cx="59.9" cy="139.5" r=".37" fill="none" stroke="#000080" stroke-width=".13"/>
<path d="M59.9 126.4v13.1" fill="none" stroke="#000080" stroke-width=".17"/>
<circle cx="59.9" cy="139.5" r=".37" fill="#000080"/>
<circle cx="59.9" cy="139.5" r=".37" fill="none" stroke="#000080" stroke-width=".13"/>
<path d="M134.5 119h9.3v1.9h-9.3" fill="none" stroke="#000080" stroke-width=".17"/>
<circle cx="143.8" cy="119" r=".37" fill="#000080"/>
<circle cx="143.8" cy="119" r=".37" fill="none" stroke="#000080" stroke-width=".13"/>
<path d="M121.4 174.9v1.9" fill="none" stroke="#000080" stroke-width=".17"/>
<circle cx="121.4" cy="174.9" r=".37" fill="#000080"/>
<circle cx="121.4" cy="174.9" r=".37" fill="none" stroke="#000080" stroke-width=".13"/>
<path d="M136.3 163.7h7.5v1.9" fill="none" stroke="#000080" stroke-width=".17"/>
<circle cx="136.3" cy="163.7" r=".37" fill="#000080"/>
<circle cx="136.3" cy="163.7" r=".37" fill="none" stroke="#000080" stroke-width=".13"/>
<path d="M143.8 184.2v1.9h-7.5" fill="none" stroke="#000080" stroke-width=".17"/>
<circle cx="136.3" cy="186.1" r=".37" fill="#000080"/>
<circle cx="136.3" cy="186.1" r=".37" fill="none" stroke="#000080" stroke-width=".13"/>
<path d="M143.8 173v1.9h-7.5" fill="none" stroke="#000080" stroke-width=".17"/>
<circle cx="136.3" cy="174.9" r=".37" fill="#000080"/>
<circle cx="136.3" cy="174.9" r=".37" fill="none" stroke="#000080" stroke-width=".13"/>
<circle cx="143.8" cy="174.9" r=".37" fill="#000080"/>
<circle cx="143.8" cy="174.9" r=".37" fill="none" stroke="#000080" stroke-width=".13"/>
<path d="M143.8 174.9v1.9" fill="none" stroke="#000080" stroke-width=".17"/>
<circle cx="143.8" cy="174.9" r=".37" fill="#000080"/>
<circle cx="143.8" cy="174.9" r=".37" fill="none" stroke="#000080" stroke-width=".13"/>
<path d="M128.9 173v1.9" fill="none" stroke="#000080" stroke-width=".17"/>
<circle cx="128.9" cy="174.9" r=".37" fill="#000080"/>
<circle cx="128.9" cy="174.9" r=".37" fill="none" stroke="#000080" stroke-width=".13"/>
<path d="M128.9 174.9v1.9" fill="none" stroke="#000080" stroke-width=".17"/>
<circle cx="128.9" cy="174.9" r=".37" fill="#000080"/>
<circle cx="128.9" cy="174.9" r=".37" fill="none" stroke="#000080" stroke-width=".13"/>
<path d="M121.4 173v1.9" fill="none" stroke="#000080" stroke-width=".17"/>
<circle cx="121.4" cy="174.9" r=".37" fill="#000080"/>
<circle cx="121.4" cy="174.9" r=".37" fill="none" stroke="#000080" stroke-width=".13"/>
<path d="M114 173v1.9" fill="none" stroke="#000080" stroke-width=".17"/>
<circle cx="114" cy="174.9" r=".37" fill="#000080"/>
<circle cx="114" cy="174.9" r=".37" fill="none" stroke="#000080" stroke-width=".13"/>
<path d="M114 174.9v1.9" fill="none" stroke="#000080" stroke-width=".17"/>
<circle cx="114" cy="174.9" r=".37" fill="#000080"/>
<circle cx="114" cy="174.9" r=".37" fill="none" stroke="#000080" stroke-width=".13"/>
<path d="M106.5 174.9v1.9" fill="none" stroke="#000080" stroke-width=".17"/>
<circle cx="106.5" cy="174.9" r=".37" fill="#000080"/>
<circle cx="106.5" cy="174.9" r=".37" fill="none" stroke="#000080" stroke-width=".13"/>
<path d="M106.5 173v1.9" fill="none" stroke="#000080" stroke-width=".17"/>
<circle cx="106.5" cy="174.9" r=".37" fill="#000080"/>
<circle cx="106.5" cy="174.9" r=".37" fill="none" stroke="#000080" stroke-width=".13"/>
<path d="M30.1 105.9h18.7" fill="none" stroke="#000080" stroke-width=".17"/>
<circle cx="48.8" cy="105.9" r=".37" fill="#000080"/>
<circle cx="48.8" cy="105.9" r=".37" fill="none" stroke="#000080" stroke-width=".13"/>
<path d="M48.8 115.3v1.8" fill="none" stroke="#000080" stroke-width=".17"/>
<circle cx="48.8" cy="117.1" r=".37" fill="#000080"/>
<circle cx="48.8" cy="117.1" r=".37" fill="none" stroke="#000080" stroke-width=".13"/>
<path d="M59.9 119h-3.7v9.3h-7.4" fill="none" stroke="#000080" stroke-width=".17"/>
<circle cx="48.8" cy="128.3" r=".37" fill="#000080"/>
<circle cx="48.8" cy="128.3" r=".37" fill="none" stroke="#000080" stroke-width=".13"/>
<path d="M11.5 124.6h11.2M35.7 176.8h1.9M43.2 171.2h13M43.2 180.5v7.4" fill="none" stroke="#000080" stroke-width=".17"/>
<circle cx="43.2" cy="171.2" r=".37" fill="#000080"/>
<circle cx="43.2" cy="171.2" r=".37" fill="none" stroke="#000080" stroke-width=".13"/>
<path d="M45 117.1h3.8M11.5 120.9h11.2" fill="none" stroke="#000080" stroke-width=".17"/>
<circle cx="48.8" cy="117.1" r=".37" fill="#000080"/>
<circle cx="48.8" cy="117.1" r=".37" fill="none" stroke="#000080" stroke-width=".13"/>
<path d="M45 124.6h3.8" fill="none" stroke="#000080" stroke-width=".17"/>
<circle cx="48.8" cy="124.6" r=".37" fill="#000080"/>
<circle cx="48.8" cy="124.6" r=".37" fill="none" stroke="#000080" stroke-width=".13"/>
<path d="M59.9 105.9h-11.1v1.9" fill="none" stroke="#000080" stroke-width=".17"/>
<circle cx="48.8" cy="105.9" r=".37" fill="#000080"/>
<circle cx="48.8" cy="105.9" r=".37" fill="none" stroke="#000080" stroke-width=".13"/>
<path d="M67.4 105.9h3.7M78.6 174.9h20.5" fill="none" stroke="#000080" stroke-width=".17"/>
<circle cx="82.3" cy="174.9" r=".37" fill="#000080"/>
<circle cx="82.3" cy="174.9" r=".37" fill="none" stroke="#000080" stroke-width=".13"/>
<circle cx="99.1" cy="174.9" r=".37" fill="#000080"/>
<circle cx="99.1" cy="174.9" r=".37" fill="none" stroke="#000080" stroke-width=".13"/>
<path d="M205.3 126.4v1.9" fill="none" stroke="#000080" stroke-width=".17"/>
<circle cx="205.3" cy="126.4" r=".37" fill="#000080"/>
<circle cx="205.3" cy="126.4" r=".37" fill="none" stroke="#000080" stroke-width=".13"/>
<path d="M205.3 126.4h-3.7v1.9" fill="none" stroke="#000080" stroke-width=".17"/>
<circle cx="205.3" cy="126.4" r=".37" fill="#000080"/>
<circle cx="205.3" cy="126.4" r=".37" fill="none" stroke="#000080" stroke-width=".13"/>
<path d="M207.2 137.6v1.9" fill="none" stroke="#000080" stroke-width=".17"/>
<circle cx="207.2" cy="137.6" r=".37" fill="#000080"/>
<circle cx="207.2" cy="137.6" r=".37" fill="none" stroke="#000080" stroke-width=".13"/>
<path d="M125.2 24v5.5h-9.4" fill="none" stroke="#000080" stroke-width=".17"/>
<circle cx="125.2" cy="23.9" r=".37" fill="#000080"/>
<circle cx="125.2" cy="23.9" r=".37" fill="none" stroke="#000080" stroke-width=".13"/>
<path d="M20.8 176.8h7.5" fill="none" stroke="#000080" stroke-width=".17"/>
<circle cx="22.7" cy="176.8" r=".37" fill="#000080"/>
<circle cx="22.7" cy="176.8" r=".37" fill="none" stroke="#000080" stroke-width=".13"/>
<circle cx="24.5" cy="176.8" r=".37" fill="#000080"/>
<circle cx="24.5" cy="176.8" r=".37" fill="none" stroke="#000080" stroke-width=".13"/>
<path d="M87.9 105.9h16.8" fill="none" stroke="#000080" stroke-width=".17"/>
<circle cx="93.5" cy="105.9" r=".37" fill="#000080"/>
<circle cx="93.5" cy="105.9" r=".37" fill="none" stroke="#000080" stroke-width=".13"/>
<path d="M99.1 174.9h37.2" fill="none" stroke="#000080" stroke-width=".17"/>
<circle cx="136.3" cy="174.9" r=".37" fill="#000080"/>
<circle cx="136.3" cy="174.9" r=".37" fill="none" stroke="#000080" stroke-width=".13"/>
<circle cx="128.9" cy="174.9" r=".37" fill="#000080"/>
<circle cx="128.9" cy="174.9" r=".37" fill="none" stroke="#000080" stroke-width=".13"/>
<circle cx="121.4" cy="174.9" r=".37" fill="#000080"/>
<circle cx="121.4" cy="174.9" r=".37" fill="none" stroke="#000080" stroke-width=".13"/>
<circle cx="114" cy="174.9" r=".37" fill="#000080"/>
<circle cx="114" cy="174.9" r=".37" fill="none" stroke="#000080" stroke-width=".13"/>
<circle cx="106.5" cy="174.9" r=".37" fill="#000080"/>
<circle cx="106.5" cy="174.9" r=".37" fill="none" stroke="#000080" stroke-width=".13"/>
<circle cx="99.1" cy="174.9" r=".37" fill="#000080"/>
<circle cx="99.1" cy="174.9" r=".37" fill="none" stroke="#000080" stroke-width=".13"/>
<path d="M106.5 163.7h29.8v1.9" fill="none" stroke="#000080" stroke-width=".17"/>
<circle cx="106.5" cy="163.7" r=".37" fill="#000080"/>
<circle cx="106.5" cy="163.7" r=".37" fill="none" stroke="#000080" stroke-width=".13"/>
<circle cx="114" cy="163.7" r=".37" fill="#000080"/>
<circle cx="114" cy="163.7" r=".37" fill="none" stroke="#000080" stroke-width=".13"/>
<circle cx="121.4" cy="163.7" r=".37" fill="#000080"/>
<circle cx="121.4" cy="163.7" r=".37" fill="none" stroke="#000080" stroke-width=".13"/>
<circle cx="128.9" cy="163.7" r=".37" fill="#000080"/>
<circle cx="128.9" cy="163.7" r=".37" fill="none" stroke="#000080" stroke-width=".13"/>
<circle cx="136.3" cy="163.7" r=".37" fill="#000080"/>
<circle cx="136.3" cy="163.7" r=".37" fill="none" stroke="#000080" stroke-width=".13"/>
<path d="M210.9 96.6h7.4" fill="none" stroke="#000080" stroke-width=".17"/>
<circle cx="212.8" cy="96.6" r=".37" fill="#000080"/>
<circle cx="212.8" cy="96.6" r=".37" fill="none" stroke="#000080" stroke-width=".13"/>
<circle cx="216.5" cy="96.6" r=".37" fill="#000080"/>
<circle cx="216.5" cy="96.6" r=".37" fill="none" stroke="#000080" stroke-width=".13"/>
<path d="M218.3 117.1h-1.8v3.8h1.8" fill="none" stroke="#000080" stroke-width=".17"/>
<circle cx="216.5" cy="119" r=".37" fill="#000080"/>
<circle cx="216.5" cy="119" r=".37" fill="none" stroke="#000080" stroke-width=".13"/>
<circle cx="216.5" cy="120.9" r=".37" fill="#000080"/>
<circle cx="216.5" cy="120.9" r=".37" fill="none" stroke="#000080" stroke-width=".13"/>
<path d="M251.9 107.8h14.9" fill="none" stroke="#000080" stroke-width=".17"/>
<circle cx="263.1" cy="107.8" r=".37" fill="#000080"/>
<circle cx="263.1" cy="107.8" r=".37" fill="none" stroke="#000080" stroke-width=".13"/>
<path d="M251.9 105.9h14.9" fill="none" stroke="#000080" stroke-width=".17"/>
<circle cx="264.9" cy="105.9" r=".37" fill="#000080"/>
<circle cx="264.9" cy="105.9" r=".37" fill="none" stroke="#000080" stroke-width=".13"/>
<path d="M43.2 169.3v3.7" fill="none" stroke="#000080" stroke-width=".17"/>
<circle cx="43.2" cy="171.2" r=".37" fill="#000080"/>
<circle cx="43.2" cy="171.2" r=".37" fill="none" stroke="#000080" stroke-width=".13"/>
<path d="M48.8 124.6v7.4" fill="none" stroke="#000080" stroke-width=".17"/>
<circle cx="48.8" cy="128.3" r=".37" fill="#000080"/>
<circle cx="48.8" cy="128.3" r=".37" fill="none" stroke="#000080" stroke-width=".13"/>
<circle cx="48.8" cy="124.6" r=".37" fill="#000080"/>
<circle cx="48.8" cy="124.6" r=".37" fill="none" stroke="#000080" stroke-width=".13"/>
<path d="M99.1 173v3.8" fill="none" stroke="#000080" stroke-width=".17"/>
<circle cx="99.1" cy="174.9" r=".37" fill="#000080"/>
<circle cx="99.1" cy="174.9" r=".37" fill="none" stroke="#000080" stroke-width=".13"/>
<path d="M136.3 173v3.8" fill="none" stroke="#000080" stroke-width=".17"/>
<circle cx="136.3" cy="174.9" r=".37" fill="#000080"/>
<circle cx="136.3" cy="174.9" r=".37" fill="none" stroke="#000080" stroke-width=".13"/>
<path d="M175.5 119h1.8v1.9" fill="none" stroke="#000080" stroke-width=".17"/>
<circle cx="177.3" cy="119" r=".37" fill="#000080"/>
<circle cx="177.3" cy="119" r=".37" fill="none" stroke="#000080" stroke-width=".13"/>
<path d="M177.3 117.1v1.9" fill="none" stroke="#000080" stroke-width=".17"/>
<circle cx="177.3" cy="119" r=".37" fill="#000080"/>
<circle cx="177.3" cy="119" r=".37" fill="none" stroke="#000080" stroke-width=".13"/>
<path d="M192.3 119h-1.9v1.9" fill="none" stroke="#000080" stroke-width=".17"/>
<circle cx="190.4" cy="119" r=".37" fill="#000080"/>
<circle cx="190.4" cy="119" r=".37" fill="none" stroke="#000080" stroke-width=".13"/>
<path d="M190.4 117.1v1.9" fill="none" stroke="#000080" stroke-width=".17"/>
<circle cx="190.4" cy="119" r=".37" fill="#000080"/>
<circle cx="190.4" cy="119" r=".37" fill="none" stroke="#000080" stroke-width=".13"/>
<path d="M199.7 119h5.6v7.4" fill="none" stroke="#000080" stroke-width=".17"/>
<circle cx="205.3" cy="126.4" r=".37" fill="#000080"/>
<circle cx="205.3" cy="126.4" r=".37" fill="none" stroke="#000080" stroke-width=".13"/>
<path d="M155 105.9v3.8" fill="none" stroke="#000080" stroke-width=".17"/>
<circle cx="155" cy="105.9" r=".37" fill="#000080"/>
<circle cx="155" cy="105.9" r=".37" fill="none" stroke="#000080" stroke-width=".13"/>
<path d="M205.3 135.8v1.8" fill="none" stroke="#000080" stroke-width=".17"/>
<circle cx="205.3" cy="137.6" r=".37" fill="#000080"/>
<circle cx="205.3" cy="137.6" r=".37" fill="none" stroke="#000080" stroke-width=".13"/>
<path d="M218.3 107.8h-7.4v29.8h-5.6" fill="none" stroke="#000080" stroke-width=".17"/>
<circle cx="205.3" cy="137.6" r=".37" fill="#000080"/>
<circle cx="205.3" cy="137.6" r=".37" fill="none" stroke="#000080" stroke-width=".13"/>
<circle cx="207.2" cy="137.6" r=".37" fill="#000080"/>
<circle cx="207.2" cy="137.6" r=".37" fill="none" stroke="#000080" stroke-width=".13"/>
<circle cx="210.9" cy="111.5" r=".37" fill="#000080"/>
<circle cx="210.9" cy="111.5" r=".37" fill="none" stroke="#000080" stroke-width=".13"/>
<path d="M201.6 135.8v1.8" fill="none" stroke="#000080" stroke-width=".17"/>
<circle cx="201.6" cy="137.6" r=".37" fill="#000080"/>
<circle cx="201.6" cy="137.6" r=".37" fill="none" stroke="#000080" stroke-width=".13"/>
<path d="M199.7 137.6h5.6" fill="none" stroke="#000080" stroke-width=".17"/>
<circle cx="201.6" cy="137.6" r=".37" fill="#000080"/>
<circle cx="201.6" cy="137.6" r=".37" fill="none" stroke="#000080" stroke-width=".13"/>
<circle cx="205.3" cy="137.6" r=".37" fill="#000080"/>
<circle cx="205.3" cy="137.6" r=".37" fill="none" stroke="#000080" stroke-width=".13"/>
<path d="M190.4 137.6v1.9" fill="none" stroke="#000080" stroke-width=".17"/>
<circle cx="190.4" cy="137.6" r=".37" fill="#000080"/>
<circle cx="190.4" cy="137.6" r=".37" fill="none" stroke="#000080" stroke-width=".13"/>
<path d="M188.5 137.6h3.8" fill="none" stroke="#000080" stroke-width=".17"/>
<circle cx="190.4" cy="137.6" r=".37" fill="#000080"/>
<circle cx="190.4" cy="137.6" r=".37" fill="none" stroke="#000080" stroke-width=".13"/>
<path d="M261.2 137.6h-9.3v1.9" fill="none" stroke="#000080" stroke-width=".17"/>
<circle cx="251.9" cy="137.6" r=".37" fill="#000080"/>
<circle cx="251.9" cy="137.6" r=".37" fill="none" stroke="#000080" stroke-width=".13"/>
<circle cx="257.5" cy="137.6" r=".37" fill="#000080"/>
<circle cx="257.5" cy="137.6" r=".37" fill="none" stroke="#000080" stroke-width=".13"/>
<path d="M272.4 135.8v1.8h-3.7" fill="none" stroke="#000080" stroke-width=".17"/>
<circle cx="270.5" cy="137.6" r=".37" fill="#000080"/>
<circle cx="270.5" cy="137.6" r=".37" fill="none" stroke="#000080" stroke-width=".13"/>
<path d="M264.9 92.9h-9.3v5.6h-3.7" fill="none" stroke="#000080" stroke-width=".17"/>
<circle cx="255.6" cy="96.6" r=".37" fill="#000080"/>
<circle cx="255.6" cy="96.6" r=".37" fill="none" stroke="#000080" stroke-width=".13"/>
<path d="M270.5 137.6v1.9" fill="none" stroke="#000080" stroke-width=".17"/>
<circle cx="270.5" cy="137.6" r=".37" fill="#000080"/>
<circle cx="270.5" cy="137.6" r=".37" fill="none" stroke="#000080" stroke-width=".13"/>
<path d="M91.6 163.7h7.5" fill="none" stroke="#000080" stroke-width=".17"/>
<circle cx="99.1" cy="163.7" r=".37" fill="#000080"/>
<circle cx="99.1" cy="163.7" r=".37" fill="none" stroke="#000080" stroke-width=".13"/>
<path d="M99.1 163.7h7.4v1.9" fill="none" stroke="#000080" stroke-width=".17"/>
<circle cx="99.1" cy="163.7" r=".37" fill="#000080"/>
<circle cx="99.1" cy="163.7" r=".37" fill="none" stroke="#000080" stroke-width=".13"/>
<circle cx="106.5" cy="163.7" r=".37" fill="#000080"/>
<circle cx="106.5" cy="163.7" r=".37" fill="none" stroke="#000080" stroke-width=".13"/>
<path d="M82.3 163.7v1.9" fill="none" stroke="#000080" stroke-width=".17"/>
<circle cx="82.3" cy="163.7" r=".37" fill="#000080"/>
<circle cx="82.3" cy="163.7" r=".37" fill="none" stroke="#000080" stroke-width=".13"/>
<path d="M82.3 173v1.9" fill="none" stroke="#000080" stroke-width=".17"/>
<circle cx="82.3" cy="174.9" r=".37" fill="#000080"/>
<circle cx="82.3" cy="174.9" r=".37" fill="none" stroke="#000080" stroke-width=".13"/>
<path d="M78.6 163.7h5.6" fill="none" stroke="#000080" stroke-width=".17"/>
<circle cx="82.3" cy="163.7" r=".37" fill="#000080"/>
<circle cx="82.3" cy="163.7" r=".37" fill="none" stroke="#000080" stroke-width=".13"/>
<path d="M95.3 94.8h7.5v7.4h1.9M69.3 111.5h5.5" fill="none" stroke="#000080" stroke-width=".17"/>
<circle cx="102.8" cy="100.4" r=".37" fill="#000080"/>
<circle cx="102.8" cy="100.4" r=".37" fill="none" stroke="#000080" stroke-width=".13"/>
<circle cx="102.8" cy="98.5" r=".37" fill="#000080"/>
<circle cx="102.8" cy="98.5" r=".37" fill="none" stroke="#000080" stroke-width=".13"/>
<path d="M48.8 160h-5.6v1.9M82.3 174.9v1.9" fill="none" stroke="#000080" stroke-width=".17"/>
<circle cx="82.3" cy="174.9" r=".37" fill="#000080"/>
<circle cx="82.3" cy="174.9" r=".37" fill="none" stroke="#000080" stroke-width=".13"/>
<path d="M82.3 184.2v1.9" fill="none" stroke="#000080" stroke-width=".17"/>
<circle cx="82.3" cy="186.1" r=".37" fill="#000080"/>
<circle cx="82.3" cy="186.1" r=".37" fill="none" stroke="#000080" stroke-width=".13"/>
<path d="M78.6 186.1h5.6" fill="none" stroke="#000080" stroke-width=".17"/>
<circle cx="82.3" cy="186.1" r=".37" fill="#000080"/>
<circle cx="82.3" cy="186.1" r=".37" fill="none" stroke="#000080" stroke-width=".13"/>
<path d="M91.6 186.1h7.5" fill="none" stroke="#000080" stroke-width=".17"/>
<circle cx="99.1" cy="186.1" r=".37" fill="#000080"/>
<circle cx="99.1" cy="186.1" r=".37" fill="none" stroke="#000080" stroke-width=".13"/>
<path d="M136.3 184.2v1.9h-37.2" fill="none" stroke="#000080" stroke-width=".17"/>
<circle cx="99.1" cy="186.1" r=".37" fill="#000080"/>
<circle cx="99.1" cy="186.1" r=".37" fill="none" stroke="#000080" stroke-width=".13"/>
<circle cx="106.5" cy="186.1" r=".37" fill="#000080"/>
<circle cx="106.5" cy="186.1" r=".37" fill="none" stroke="#000080" stroke-width=".13"/>
<circle cx="114" cy="186.1" r=".37" fill="#000080"/>
<circle cx="114" cy="186.1" r=".37" fill="none" stroke="#000080" stroke-width=".13"/>
<circle cx="121.4" cy="186.1" r=".37" fill="#000080"/>
<circle cx="121.4" cy="186.1" r=".37" fill="none" stroke="#000080" stroke-width=".13"/>
<circle cx="128.9" cy="186.1" r=".37" fill="#000080"/>
<circle cx="128.9" cy="186.1" r=".37" fill="none" stroke="#000080" stroke-width=".13"/>
<circle cx="136.3" cy="186.1" r=".37" fill="#000080"/>
<circle cx="136.3" cy="186.1" r=".37" fill="none" stroke="#000080" stroke-width=".13"/>
<path d="M11.5 117.1h11.2M143.8 109.7h5.6M69.3 133.9v1.9h5.5" fill="none" stroke="#000080" stroke-width=".17"/>
<circle cx="143.8" cy="109.7" r=".37" fill="#000080"/>
<circle cx="143.8" cy="109.7" r=".37" fill="none" stroke="#000080" stroke-width=".13"/>
<path d="M134.5 105.9h50.3" fill="none" stroke="#000080" stroke-width=".17"/>
<circle cx="155" cy="105.9" r=".37" fill="#000080"/>
<circle cx="155" cy="105.9" r=".37" fill="none" stroke="#000080" stroke-width=".13"/>
<path d="M164.3 119h3.7" fill="none" stroke="#000080" stroke-width=".17"/>
<circle cx="166.2" cy="119" r=".37" fill="#000080"/>
<circle cx="166.2" cy="119" r=".37" fill="none" stroke="#000080" stroke-width=".13"/>
<path d="M155 133.9v3.7" fill="none" stroke="#000080" stroke-width=".17"/>
<circle cx="155" cy="135.8" r=".37" fill="#000080"/>
<circle cx="155" cy="135.8" r=".37" fill="none" stroke="#000080" stroke-width=".13"/>
<path d="M155 117.1v9.3" fill="none" stroke="#000080" stroke-width=".17"/>
<circle cx="155" cy="119" r=".37" fill="#000080"/>
<circle cx="155" cy="119" r=".37" fill="none" stroke="#000080" stroke-width=".13"/>
<circle cx="155" cy="122.7" r=".37" fill="#000080"/>
<circle cx="155" cy="122.7" r=".37" fill="none" stroke="#000080" stroke-width=".13"/>
<path d="M67.4 23.9h9.3M143.8 24v1.8" fill="none" stroke="#000080" stroke-width=".17"/>
<circle cx="143.8" cy="23.9" r=".37" fill="#000080"/>
<circle cx="143.8" cy="23.9" r=".37" fill="none" stroke="#000080" stroke-width=".13"/>
<path d="M99.1 24v5.5h9.3" fill="none" stroke="#000080" stroke-width=".17"/>
<circle cx="99.1" cy="23.9" r=".37" fill="#000080"/>
<circle cx="99.1" cy="23.9" r=".37" fill="none" stroke="#000080" stroke-width=".13"/>
<path d="M87.9 24v1.8" fill="none" stroke="#000080" stroke-width=".17"/>
<circle cx="87.9" cy="23.9" r=".37" fill="#000080"/>
<circle cx="87.9" cy="23.9" r=".37" fill="none" stroke="#000080" stroke-width=".13"/>
<path d="M84.2 24h18.6" fill="none" stroke="#000080" stroke-width=".17"/>
<circle cx="87.9" cy="23.9" r=".37" fill="#000080"/>
<circle cx="87.9" cy="23.9" r=".37" fill="none" stroke="#000080" stroke-width=".13"/>
<circle cx="99.1" cy="23.9" r=".37" fill="#000080"/>
<circle cx="99.1" cy="23.9" r=".37" fill="none" stroke="#000080" stroke-width=".13"/>
<path d="M121.4 24h35.4" fill="none" stroke="#000080" stroke-width=".17"/>
<circle cx="125.2" cy="23.9" r=".37" fill="#000080"/>
<circle cx="125.2" cy="23.9" r=".37" fill="none" stroke="#000080" stroke-width=".13"/>
<circle cx="136.3" cy="23.9" r=".37" fill="#000080"/>
<circle cx="136.3" cy="23.9" r=".37" fill="none" stroke="#000080" stroke-width=".13"/>
<circle cx="143.8" cy="23.9" r=".37" fill="#000080"/>
<circle cx="143.8" cy="23.9" r=".37" fill="none" stroke="#000080" stroke-width=".13"/>
<use href="#words"/>
</svg>
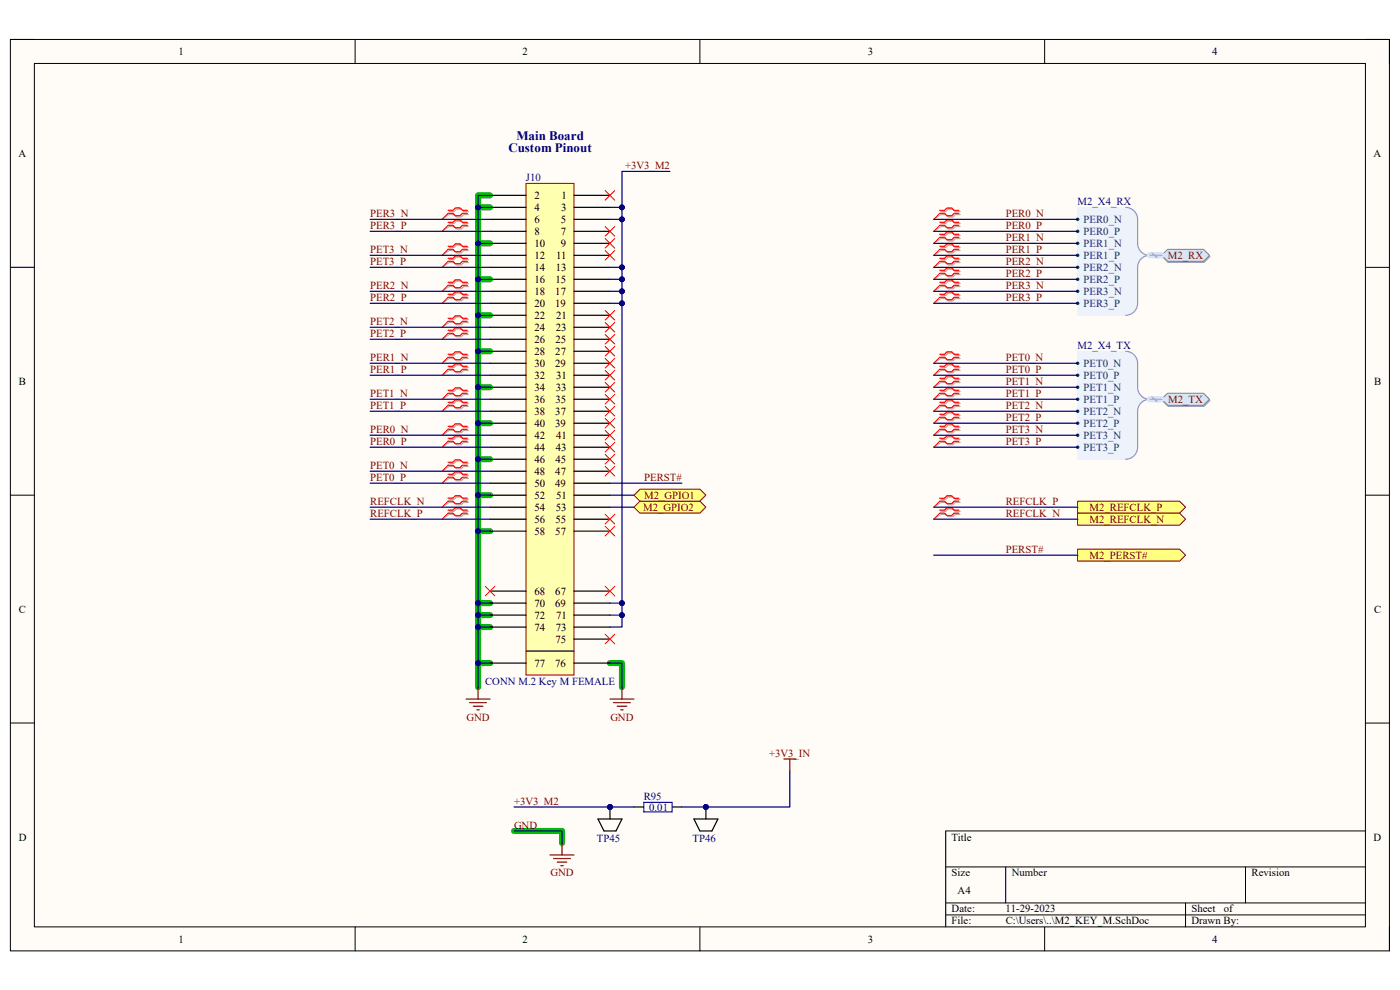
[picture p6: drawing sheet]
<svg xmlns="http://www.w3.org/2000/svg" width="297mm" height="210mm" viewBox="0 0 297 210" stroke-linecap="round" stroke-linejoin="round" font-family="sans-serif">
<defs><g id="words">
<g font-size="2.8" fill="#000080">
<text x="109.6" y="29.6">Main Board</text>
<text x="107.9" y="32.2">Custom Pinout</text>
</g>
<g font-size="2.3">
<text x="37.9" y="11.7">1</text>
<text x="110.9" y="11.7">2</text>
<text x="184.1" y="11.7">3</text>
<text x="257.1" y="11.7">4</text>
<text x="3.9" y="33.3">A</text>
<text x="291.4" y="33.3">A</text>
<text x="113.4" y="42.2">2</text>
<text x="113.4" y="44.7">4</text>
<text x="113.4" y="47.3">6</text>
<text x="119" y="47.3">5</text>
<text x="119" y="44.7">3</text>
<text x="119.1" y="42.2">1</text>
<text x="113.4" y="49.8">8</text>
<text x="113.4" y="52.4">10</text>
<text x="119" y="49.8">7</text>
<text x="119" y="52.4">9</text>
<text x="113.4" y="54.9">12</text>
<text x="113.4" y="57.4">14</text>
<text x="113.4" y="60">16</text>
<text x="117.9" y="60">15</text>
<text x="117.9" y="57.4">13</text>
<text x="118" y="54.9">11</text>
<text x="113.4" y="62.6">18</text>
<text x="113.4" y="65.1">20</text>
<text x="117.8" y="65.1">19</text>
<text x="117.8" y="62.6">17</text>
<text x="113.4" y="67.6">22</text>
<text x="113.4" y="70.2">24</text>
<text x="117.9" y="70.2">23</text>
<text x="118" y="67.6">21</text>
<text x="113.4" y="72.7">26</text>
<text x="113.4" y="75.3">28</text>
<text x="113.4" y="77.8">30</text>
<text x="117.8" y="77.8">29</text>
<text x="117.8" y="75.3">27</text>
<text x="117.9" y="72.7">25</text>
<text x="4" y="81.6">B</text>
<text x="113.4" y="80.3">32</text>
<text x="113.4" y="82.9">34</text>
<text x="117.9" y="82.9">33</text>
<text x="118" y="80.3">31</text>
<text x="291.5" y="81.6">B</text>
<text x="113.4" y="85.4">36</text>
<text x="113.4" y="88">38</text>
<text x="117.8" y="88">37</text>
<text x="117.9" y="85.4">35</text>
<text x="113.4" y="90.6">40</text>
<text x="113.4" y="93.1">42</text>
<text x="113.4" y="95.6">44</text>
<text x="117.8" y="90.6">39</text>
<text x="117.9" y="95.6">43</text>
<text x="118" y="93.1">41</text>
<text x="113.4" y="98.2">46</text>
<text x="113.4" y="100.7">48</text>
<text x="117.8" y="100.7">47</text>
<text x="117.9" y="98.2">45</text>
<text x="113.4" y="103.3">50</text>
<text x="113.4" y="105.8">52</text>
<text x="117.8" y="103.3">49</text>
<text x="118" y="105.8">51</text>
<text x="113.4" y="108.3">54</text>
<text x="113.4" y="110.9">56</text>
<text x="113.4" y="113.4">58</text>
<text x="117.8" y="113.4">57</text>
<text x="117.9" y="110.9">55</text>
<text x="117.9" y="108.3">53</text>
<text x="4" y="130">C</text>
<text x="113.4" y="126.2">68</text>
<text x="113.4" y="128.7">70</text>
<text x="113.4" y="131.2">72</text>
<text x="117.8" y="128.7">69</text>
<text x="117.8" y="126.2">67</text>
<text x="118" y="131.2">71</text>
<text x="291.5" y="130">C</text>
<text x="113.4" y="133.8">74</text>
<text x="117.9" y="136.3">75</text>
<text x="117.9" y="133.8">73</text>
<text x="113.4" y="141.4">77</text>
<text x="117.8" y="141.4">76</text>
<text x="4" y="178.3">D</text>
<text x="201.9" y="178.3">Title</text>
<text x="291.4" y="178.3">D</text>
<text x="201.9" y="185.9">Size</text>
<text x="214.6" y="185.9">Number</text>
<text x="265.5" y="185.9">Revision</text>
<text x="203.2" y="189.7">A4</text>
<text x="201.9" y="193.5">Date:</text>
<text x="201.9" y="196.1">File:</text>
<text x="213.3" y="193.5">11-29-2023</text>
<text x="213.4" y="196.1">C:\Users\..\M2_KEY_M.SchDoc</text>
<text x="252.8" y="193.5">Sheet</text>
<text x="252.8" y="196.1">Drawn By:</text>
<text x="259.6" y="193.5">of</text>
<text x="37.9" y="199.9">1</text>
<text x="110.9" y="199.9">2</text>
<text x="184.1" y="199.9">3</text>
<text x="257.1" y="199.9">4</text>
</g>
<g font-size="2.3" fill="#800000">
<text x="132.6" y="35.9">+3V3_M2</text>
<text x="78.5" y="46">PER3_N</text>
<text x="213.4" y="46">PER0_N</text>
<text x="78.5" y="48.6">PER3_P</text>
<text x="78.5" y="53.6">PET3_N</text>
<text x="213.4" y="48.6">PER0_P</text>
<text x="213.4" y="51.1">PER1_N</text>
<text x="213.4" y="53.6">PER1_P</text>
<text x="78.5" y="56.2">PET3_P</text>
<text x="213.4" y="56.2">PER2_N</text>
<text x="213.4" y="58.7">PER2_P</text>
<text x="247.8" y="54.9">M2_RX</text>
<text x="78.5" y="61.3">PER2_N</text>
<text x="78.5" y="63.8">PER2_P</text>
<text x="213.4" y="61.3">PER3_N</text>
<text x="213.4" y="63.8">PER3_P</text>
<text x="78.5" y="68.9">PET2_N</text>
<text x="78.5" y="71.5">PET2_P</text>
<text x="78.5" y="76.5">PER1_N</text>
<text x="213.4" y="76.5">PET0_N</text>
<text x="78.5" y="79.1">PER1_P</text>
<text x="213.4" y="79.1">PET0_P</text>
<text x="213.4" y="81.6">PET1_N</text>
<text x="78.5" y="84.2">PET1_N</text>
<text x="78.5" y="86.7">PET1_P</text>
<text x="213.4" y="84.2">PET1_P</text>
<text x="213.4" y="86.7">PET2_N</text>
<text x="213.4" y="89.3">PET2_P</text>
<text x="247.8" y="85.4">M2_TX</text>
<text x="78.5" y="91.8">PER0_N</text>
<text x="78.5" y="94.4">PER0_P</text>
<text x="213.4" y="91.8">PET3_N</text>
<text x="213.4" y="94.4">PET3_P</text>
<text x="78.5" y="99.4">PET0_N</text>
<text x="78.5" y="102">PET0_P</text>
<text x="136.7" y="102">PERST#</text>
<text x="78.5" y="107.1">REFCLK_N</text>
<text x="136.7" y="105.8">M2_GPIO1</text>
<text x="213.4" y="107.1">REFCLK_P</text>
<text x="78.5" y="109.6">REFCLK_P</text>
<text x="136.4" y="108.3">M2_GPIO2</text>
<text x="213.4" y="109.6">REFCLK_N</text>
<text x="231.1" y="108.3">M2_REFCLK_P</text>
<text x="231.1" y="110.9">M2_REFCLK_N</text>
<text x="213.4" y="117.3">PERST#</text>
<text x="231.1" y="118.5">M2_PERST#</text>
<text x="99" y="152.9">GND</text>
<text x="129.5" y="152.9">GND</text>
<text x="163.2" y="160.5">+3V3_IN</text>
<text x="109.1" y="170.7">+3V3_M2</text>
<text x="109.1" y="175.8">GND</text>
<text x="116.8" y="185.9">GND</text>
</g>
<g font-size="2.3" fill="#000080">
<text x="111.6" y="38.4">J10</text>
<text x="228.6" y="43.5">M2_X4_RX</text>
<text x="228.6" y="74">M2_X4_TX</text>
<text x="102.9" y="145.2">CONN M.2 Key M FEMALE</text>
<text x="136.6" y="169.7">R95</text>
<text x="137.7" y="172">0.01</text>
<text x="126.6" y="178.6">TP45</text>
<text x="146.9" y="178.6">TP46</text>
</g>
<g font-size="2.3" fill="#003a70">
<text x="229.9" y="47.3">PER0_N</text>
<text x="229.9" y="49.8">PER0_P</text>
<text x="229.9" y="52.4">PER1_N</text>
<text x="229.9" y="54.9">PER1_P</text>
<text x="229.9" y="57.4">PER2_N</text>
<text x="229.9" y="60">PER2_P</text>
<text x="229.9" y="62.6">PER3_N</text>
<text x="229.9" y="65.1">PER3_P</text>
<text x="229.9" y="77.8">PET0_N</text>
<text x="229.9" y="80.3">PET0_P</text>
<text x="229.9" y="82.9">PET1_N</text>
<text x="229.9" y="85.4">PET1_P</text>
<text x="229.9" y="88">PET2_N</text>
<text x="229.9" y="90.6">PET2_P</text>
<text x="229.9" y="93.1">PET3_N</text>
<text x="229.9" y="95.6">PET3_P</text>
</g>
</g></defs>
<path d="M2.2 8.4h292.6v193.3h-292.6z" fill-rule="evenodd" fill="#fffcf8"/>
<path d="M2.2 8.4h292.6v193.3h-292.6z" fill="none" stroke="#000" stroke-width=".21"/>
<path d="M7.3 13.5h282.4v183.1h-282.4z" fill-rule="evenodd" fill="#fffcf8"/>
<g fill="none" stroke="#000" stroke-width=".21">
<path d="M2.2 8.4h5.1M7.3 13.5h282.4v183.1h-282.4zM75.3 8.4v5.1M148.5 8.4v5.1M221.6 8.4v5.1M289.7 8.4h5.1v5.1M2.2 56.7h5.1M289.7 56.7h5.1M2.2 105h5.1M289.7 105.1h5.1M2.2 153.4h5.1M289.7 153.4h5.1"/>
<path d="M289.7 176.3h-89.1v20.3M75.3 196.6v5.1M148.5 196.6v5.1M200.6 183.9h89.1M200.6 191.5h89.1M200.6 194.1h89.1M213.4 183.9v7.6M221.6 196.6v5.1M251.5 191.5v5.1M264.2 183.9v7.6M294.8 196.6v5.1"/>
</g>
<g fill="none" stroke="#00be00" stroke-width="1.3">
<path d="M101.4 44h2.6M101.4 51.6h2.6M101.4 59.3h2.6M104 41.4h-2.6v104.3M101.4 66.9h2.6M101.4 74.5h2.6M101.4 82.1h2.6M101.4 89.8h2.6M101.4 97.4h2.6M101.4 105h2.6M101.4 112.7h2.6M101.4 130.5h2.6"/>
<path d="M101.4 133h2.6M101.4 127.9h2.6M101.4 140.7h2.6M129.4 140.7h2.5v5M109.1 176.3h10.1v2.5"/>
</g>
<path d="M119.2 178.8v2.6M116.7 181.4h5.1M117.5 182.1h3.5M118.2 182.9h2M119 183.7h.5" fill="none" stroke="#800000" stroke-width=".25"/>
<path d="M228.6 106.3h21.6l1.3 1.3-1.3 1.3h-21.6z" fill-rule="evenodd" fill="#ffff80"/>
<path d="M228.6 106.3h21.6l1.3 1.3-1.3 1.3h-21.6z" fill="none" stroke="#800000" stroke-width=".21"/>
<path d="M228.6 108.9h21.6l1.3 1.2-1.3 1.3h-21.6z" fill-rule="evenodd" fill="#ffff80"/>
<path d="M228.6 108.9h21.6l1.3 1.2-1.3 1.3h-21.6z" fill="none" stroke="#800000" stroke-width=".21"/>
<path d="M228.6 116.5h21.6l1.3 1.3-1.3 1.2h-21.6z" fill-rule="evenodd" fill="#ffff80"/>
<path d="M228.6 116.5h21.6l1.3 1.3-1.3 1.2h-21.6z" fill="none" stroke="#800000" stroke-width=".21"/>
<path d="M134.5 171.2h2M142.7 171.2h2" fill="none" stroke="#000" stroke-width=".25"/>
<path d="M136.6 170.2h6v2h-6z" fill="none" stroke="#00f" stroke-width=".25"/>
<circle cx="129.4" cy="171.2" r=".51" fill="#000080"/>
<circle cx="129.4" cy="171.2" r=".51" fill="none" stroke="#000080" stroke-width=".21"/>
<path d="M129.4 171.2v2.5" fill="none" stroke="#000" stroke-width=".25"/>
<circle cx="129.4" cy="171.2" r=".51" fill="#000080"/>
<circle cx="129.4" cy="171.2" r=".51" fill="none" stroke="#000080" stroke-width=".21"/>
<path d="M126.9 173.7h5.1l-1.3 2.6h-2.6z" fill="none" stroke="#000" stroke-width=".25"/>
<circle cx="149.8" cy="171.2" r=".51" fill="#000080"/>
<circle cx="149.8" cy="171.2" r=".51" fill="none" stroke="#000080" stroke-width=".21"/>
<path d="M149.8 171.2v2.5" fill="none" stroke="#000" stroke-width=".25"/>
<circle cx="149.8" cy="171.2" r=".51" fill="#000080"/>
<circle cx="149.8" cy="171.2" r=".51" fill="none" stroke="#000080" stroke-width=".21"/>
<path d="M147.2 173.7h5.1l-1.3 2.6h-2.5z" fill="none" stroke="#000" stroke-width=".25"/>
<path d="M228.6 44h10.2l1.3 .3 .9 1 .3 1.2v5.8l.7 1 1.3 .9-1.3 .8-.7 1.1v8.2l-.3 1.3-.9 1-1.3 .3h-10.2z" fill-rule="evenodd" fill="#edf2fb"/>
<path d="M228.6 44h10.2l1.3 .3 .9 1 .3 1.2v5.8l.7 1 1.3 .9-1.3 .8-.7 1.1v8.2l-.3 1.3-.9 1-1.3 .3h-10.2z" fill="none" stroke="#edf2fb" stroke-width=".21"/>
<path d="M238.8 44a2.54 2.54 0 0 1 2.5 2.5v5.1a2.54 2.54 0 0 0 2.6 2.6 2.55 2.55 0 0 0-2.6 2.5v7.6a2.55 2.55 0 0 1-2.5 2.6" fill="none" stroke="#8f9ec9" stroke-width=".25"/>
<circle cx="228.6" cy="46.5" r=".26" fill="#003a70"/>
<circle cx="228.6" cy="46.5" r=".26" fill="none" stroke="#003a70" stroke-width=".21"/>
<circle cx="228.6" cy="49.1" r=".26" fill="#003a70"/>
<circle cx="228.6" cy="49.1" r=".26" fill="none" stroke="#003a70" stroke-width=".21"/>
<circle cx="228.6" cy="51.6" r=".26" fill="#003a70"/>
<circle cx="228.6" cy="51.6" r=".26" fill="none" stroke="#003a70" stroke-width=".21"/>
<circle cx="228.6" cy="54.2" r=".26" fill="#003a70"/>
<circle cx="228.6" cy="54.2" r=".26" fill="none" stroke="#003a70" stroke-width=".21"/>
<circle cx="228.6" cy="56.7" r=".26" fill="#003a70"/>
<circle cx="228.6" cy="56.7" r=".26" fill="none" stroke="#003a70" stroke-width=".21"/>
<circle cx="228.6" cy="59.3" r=".26" fill="#003a70"/>
<circle cx="228.6" cy="59.3" r=".26" fill="none" stroke="#003a70" stroke-width=".21"/>
<circle cx="228.6" cy="61.8" r=".26" fill="#003a70"/>
<circle cx="228.6" cy="61.8" r=".26" fill="none" stroke="#003a70" stroke-width=".21"/>
<circle cx="228.6" cy="64.3" r=".26" fill="#003a70"/>
<circle cx="228.6" cy="64.3" r=".26" fill="none" stroke="#003a70" stroke-width=".21"/>
<path d="M228.6 74.5h10.2l1.3 .3 .9 1 .3 1.3v5.7l.7 1.1 1.3 .8-1.3 .8-.7 1.1v8.3l-.3 1.2-.9 1-1.3 .3h-10.2z" fill-rule="evenodd" fill="#edf2fb"/>
<path d="M228.6 74.5h10.2l1.3 .3 .9 1 .3 1.3v5.7l.7 1.1 1.3 .8-1.3 .8-.7 1.1v8.3l-.3 1.2-.9 1-1.3 .3h-10.2z" fill="none" stroke="#edf2fb" stroke-width=".21"/>
<path d="M238.8 74.5a2.55 2.55 0 0 1 2.5 2.6v5a2.55 2.55 0 0 0 2.6 2.6 2.54 2.54 0 0 0-2.6 2.5v7.7a2.55 2.55 0 0 1-2.5 2.5" fill="none" stroke="#8f9ec9" stroke-width=".25"/>
<circle cx="228.6" cy="77.1" r=".26" fill="#003a70"/>
<circle cx="228.6" cy="77.1" r=".26" fill="none" stroke="#003a70" stroke-width=".21"/>
<circle cx="228.6" cy="79.6" r=".26" fill="#003a70"/>
<circle cx="228.6" cy="79.6" r=".26" fill="none" stroke="#003a70" stroke-width=".21"/>
<circle cx="228.6" cy="82.1" r=".26" fill="#003a70"/>
<circle cx="228.6" cy="82.1" r=".26" fill="none" stroke="#003a70" stroke-width=".21"/>
<circle cx="228.6" cy="84.7" r=".26" fill="#003a70"/>
<circle cx="228.6" cy="84.7" r=".26" fill="none" stroke="#003a70" stroke-width=".21"/>
<circle cx="228.6" cy="87.2" r=".26" fill="#003a70"/>
<circle cx="228.6" cy="87.2" r=".26" fill="none" stroke="#003a70" stroke-width=".21"/>
<circle cx="228.6" cy="89.8" r=".26" fill="#003a70"/>
<circle cx="228.6" cy="89.8" r=".26" fill="none" stroke="#003a70" stroke-width=".21"/>
<circle cx="228.6" cy="92.3" r=".26" fill="#003a70"/>
<circle cx="228.6" cy="92.3" r=".26" fill="none" stroke="#003a70" stroke-width=".21"/>
<circle cx="228.6" cy="94.9" r=".26" fill="#003a70"/>
<circle cx="228.6" cy="94.9" r=".26" fill="none" stroke="#003a70" stroke-width=".21"/>
<path d="M246.6 54.4l1.2-1.3h7.7l1.2 1.3-1.2 1.3h-7.7z" fill-rule="evenodd" fill="#bac0ca"/>
<path d="M246.6 54.4l1.2-1.3h7.7l1.2 1.3-1.2 1.3h-7.7z" fill="none" stroke="#a6acb6" stroke-width=".21"/>
<path d="M247.7 52.9h7.6l1.3 1.3-1.3 1.2h-7.6l-1.3-1.2z" fill-rule="evenodd" fill="#d5e4ff"/>
<path d="M247.7 52.9h7.6l1.3 1.3-1.3 1.2h-7.6l-1.3-1.2z" fill="none" stroke="#71809b" stroke-width=".21"/>
<path d="M246.6 85l1.2-1.3h7.7l1.2 1.3-1.2 1.2h-7.7z" fill-rule="evenodd" fill="#bac0ca"/>
<path d="M246.6 85l1.2-1.3h7.7l1.2 1.3-1.2 1.2h-7.7z" fill="none" stroke="#a6acb6" stroke-width=".21"/>
<path d="M246.4 84.7l1.3-1.3h7.6l1.3 1.3-1.3 1.3h-7.6z" fill-rule="evenodd" fill="#d5e4ff"/>
<path d="M246.4 84.7l1.3-1.3h7.6l1.3 1.3-1.3 1.3h-7.6z" fill="none" stroke="#71809b" stroke-width=".21"/>
<path d="M111.6 38.9h10.2v104.3h-10.2z" fill-rule="evenodd" fill="#ffffb0"/>
<path d="M111.6 38.9h10.2v104.3h-10.2z" fill="none" stroke="#800000" stroke-width=".21"/>
<g fill="none" stroke="#000" stroke-width=".25">
<path d="M104 41.4h7.6M104 44h7.6M104 46.5h7.6M104 49.1h7.6M104 51.6h7.6M104 54.2h7.6M104 56.7h7.6M104 59.3h7.6M121.8 41.4h7.6M121.8 44h7.6M121.8 46.5h7.6M121.8 49.1h7.6"/>
<path d="M121.8 51.6h7.6M121.8 54.2h7.6M121.8 56.7h7.6M121.8 59.3h7.6M104 61.8h7.6M104 64.3h7.6M104 66.9h7.6M104 69.4h7.6M104 72h7.6M104 74.5h7.6M104 77.1h7.6M104 79.6h7.6"/>
<path d="M121.8 61.8h7.6M121.8 64.3h7.6M121.8 66.9h7.6M121.8 69.4h7.6M121.8 72h7.6M121.8 74.5h7.6M121.8 77.1h7.6M121.8 79.6h7.6M104 82.1h7.6M104 84.7h7.6M104 87.2h7.6M104 89.8h7.6"/>
<path d="M104 92.3h7.6M104 94.9h7.6M104 97.4h7.6M104 100h7.6M121.8 82.1h7.6M121.8 84.7h7.6M121.8 87.2h7.6M121.8 89.8h7.6M121.8 92.3h7.6M121.8 94.9h7.6M121.8 97.4h7.6M121.8 100h7.6"/>
<path d="M104 102.5h7.6M104 105h7.6M104 107.6h7.6M104 110.1h7.6M104 112.7h7.6M121.8 102.5h7.6M121.8 105h7.6M121.8 107.6h7.6M121.8 110.1h7.6M121.8 112.7h7.6M104 125.4h7.6M104 127.9h7.6"/>
<path d="M104 130.5h7.6M104 133h7.6M111.6 138.1h10.2M121.8 125.4h7.6M121.8 127.9h7.6M121.8 130.5h7.6M121.8 133h7.6M121.8 135.6h7.6M104 140.7h7.6M121.8 140.7h7.6"/>
</g>
<path d="M98.9 148.3h5.1M99.6 149.1h3.6M100.4 149.8h2M101.2 150.6h.5M101.4 145.7v2.6M129.4 148.3h5.1M130.2 149.1h3.5M130.9 149.8h2.1M131.7 150.6h.5M131.9 145.7v2.6M166.3 161h2.5M167.6 161v2.6" fill="none" stroke="#800000" stroke-width=".25"/>
<g fill="none" stroke="#f00" stroke-width=".21">
<path d="M95.1 45.3l-1.3 1.2M95.1 47.8l-1.3 1.3M95.1 52.9l-1.3 1.3M95.1 55.4l-1.3 1.3M128.4 50.6l2 2M128.4 48.1l2 2M128.4 53.1l2 2.1M128.4 40.4l2 2.1M130.4 50.6l-2 2M130.4 48.1l-2 2M130.4 40.4l-2 2.1M130.4 53.1l-2 2.1"/>
<path d="M199.4 55.4l-1.3 1.3M199.4 45.3l-1.3 1.2M199.4 47.8l-1.3 1.3M199.4 50.4l-1.3 1.2M199.4 52.9l-1.3 1.3M199.4 58l-1.3 1.3M95.1 60.5l-1.3 1.3M95.1 63.1l-1.3 1.2M95.1 68.2l-1.3 1.2M95.1 70.7l-1.3 1.3M95.1 75.8l-1.3 1.3M95.1 78.3l-1.3 1.3"/>
<path d="M128.4 78.6l2 2M128.4 76l2 2.1M128.4 73.5l2 2M128.4 71l2 2M128.4 68.4l2 2M128.4 65.9l2 2M130.4 78.6l-2 2M130.4 76l-2 2.1M130.4 73.5l-2 2M130.4 71l-2 2M130.4 68.4l-2 2M130.4 65.9l-2 2"/>
<path d="M199.4 60.5l-1.3 1.3M199.4 63.1l-1.3 1.2M199.4 75.8l-1.3 1.3M199.4 78.3l-1.3 1.3M95.1 83.4l-1.3 1.3M95.1 86l-1.3 1.2M95.1 91.1l-1.3 1.2M95.1 93.6l-1.3 1.3M95.1 98.7l-1.3 1.3M128.4 98.9l2 2.1M128.4 96.4l2 2M128.4 93.9l2 2"/>
<path d="M128.4 91.3l2 2M128.4 88.8l2 2M128.4 86.2l2 2.1M128.4 83.7l2 2M128.4 81.1l2 2.1M130.4 98.9l-2 2.1M130.4 96.4l-2 2M130.4 93.9l-2 2M130.4 91.3l-2 2M130.4 88.8l-2 2M130.4 86.2l-2 2.1M130.4 83.7l-2 2"/>
<path d="M130.4 81.1l-2 2.1M199.4 80.9l-1.3 1.2M199.4 83.4l-1.3 1.3M199.4 86l-1.3 1.2M199.4 88.5l-1.3 1.3M199.4 91.1l-1.3 1.2M199.4 93.6l-1.3 1.3M95.1 108.9l-1.3 1.2M95.1 106.3l-1.3 1.3M95.1 101.2l-1.3 1.3M128.4 111.7l2 2M128.4 109.1l2 2.1"/>
<path d="M130.4 111.7l-2 2M130.4 109.1l-2 2.1M199.4 106.3l-1.3 1.3M199.4 108.9l-1.3 1.2M102.9 124.4l2.1 2M105 124.4l-2.1 2M128.4 134.6l2 2M128.4 124.4l2 2M130.4 134.6l-2 2M130.4 124.4l-2 2"/>
</g>
<g fill="none" stroke="#d0a19e" stroke-width=".25">
<path d="M95.3 44.9h1l.5-.5h1.1l.5 .5h1M95.3 45.5h1l.5 .5h1.1l.5-.5h1M95.3 47.4h1l.5-.5h1.1l.5 .5h1M95.3 48.1h1l.5 .5h1.1l.5-.5h1M95.3 52.5h1l.5-.5h1.1l.5 .5h1M95.3 53.1h1l.5 .6h1.1l.5-.6h1M95.3 55.1h1l.5-.6h1.1l.5 .6h1M95.3 55.7h1l.5 .5h1.1l.5-.5h1M199.6 44.9h1l.5-.5h1.1l.5 .5h1M199.6 45.5h1l.5 .5h1.1l.5-.5h1M199.6 47.4h1l.5-.5h1.1l.5 .5h1M199.6 48.1h1l.5 .5h1.1l.5-.5h1"/>
<path d="M199.6 50h1l.5-.5h1.1l.5 .5h1M199.6 50.6h1l.5 .5h1.1l.5-.5h1M199.6 52.5h1l.5-.5h1.1l.5 .5h1M199.6 53.1h1l.5 .6h1.1l.5-.6h1M199.6 55.1h1l.5-.6h1.1l.5 .6h1M199.6 55.7h1l.5 .5h1.1l.5-.5h1M199.6 57.6h1l.5-.5h1.1l.5 .5h1M199.6 58.2h1l.5 .5h1.1l.5-.5h1M95.3 60.1h1l.5-.5h1.1l.5 .5h1M95.3 60.8h1l.5 .5h1.1l.5-.5h1M95.3 62.7h1l.5-.5h1.1l.5 .5h1M95.3 63.3h1l.5 .5h1.1l.5-.5h1"/>
<path d="M95.3 67.8h1l.5-.5h1.1l.5 .5h1M95.3 68.4h1l.5 .5h1.1l.5-.5h1M95.3 70.3h1l.5-.5h1.1l.5 .5h1M95.3 71h1l.5 .5h1.1l.5-.5h1M95.3 75.4h1l.5-.5h1.1l.5 .5h1M95.3 76h1l.5 .6h1.1l.5-.6h1M95.3 78h1l.5-.6h1.1l.5 .6h1M95.3 78.6h1l.5 .5h1.1l.5-.5h1M199.6 60.1h1l.5-.5h1.1l.5 .5h1M199.6 60.8h1l.5 .5h1.1l.5-.5h1M199.6 62.7h1l.5-.5h1.1l.5 .5h1M199.6 63.3h1l.5 .5h1.1l.5-.5h1"/>
<path d="M199.6 75.4h1l.5-.5h1.1l.5 .5h1M199.6 76h1l.5 .6h1.1l.5-.6h1M199.6 78h1l.5-.6h1.1l.5 .6h1M199.6 78.6h1l.5 .5h1.1l.5-.5h1M95.3 83h1l.5-.5h1.1l.5 .5h1M95.3 83.7h1l.5 .5h1.1l.5-.5h1M95.3 85.6h1l.5-.5h1.1l.5 .5h1M95.3 86.2h1l.5 .5h1.1l.5-.5h1M95.3 90.7h1l.5-.5h1.1l.5 .5h1M95.3 91.3h1l.5 .5h1.1l.5-.5h1M95.3 93.2h1l.5-.5h1.1l.5 .5h1M95.3 93.9h1l.5 .5h1.1l.5-.5h1"/>
<path d="M95.3 98.3h1l.5-.5h1.1l.5 .5h1M95.3 98.9h1l.5 .5h1.1l.5-.5h1M199.6 80.5h1l.5-.5h1.1l.5 .5h1M199.6 81.1h1l.5 .5h1.1l.5-.5h1M199.6 83h1l.5-.5h1.1l.5 .5h1M199.6 83.7h1l.5 .5h1.1l.5-.5h1M199.6 85.6h1l.5-.5h1.1l.5 .5h1M199.6 86.2h1l.5 .5h1.1l.5-.5h1M199.6 88.1h1l.5-.5h1.1l.5 .5h1M199.6 88.8h1l.5 .5h1.1l.5-.5h1M199.6 90.7h1l.5-.5h1.1l.5 .5h1M199.6 91.3h1l.5 .5h1.1l.5-.5h1"/>
<path d="M199.6 93.2h1l.5-.5h1.1l.5 .5h1M199.6 93.9h1l.5 .5h1.1l.5-.5h1M95.3 100.8h1l.5-.5h1.1l.5 .5h1M95.3 101.5h1l.5 .5h1.1l.5-.5h1M95.3 105.9h1l.5-.5h1.1l.5 .5h1M95.3 106.6h1l.5 .5h1.1l.5-.5h1M95.3 108.5h1l.5-.5h1.1l.5 .5h1M95.3 109.1h1l.5 .5h1.1l.5-.5h1M199.6 105.9h1l.5-.5h1.1l.5 .5h1M199.6 106.6h1l.5 .5h1.1l.5-.5h1M199.6 108.5h1l.5-.5h1.1l.5 .5h1M199.6 109.1h1l.5 .5h1.1l.5-.5h1"/>
</g>
<g fill="none" stroke="#d0a19e" stroke-width=".21">
<path d="M95.3 45.5l-1.5 1M95.3 48.1l-1.5 1M95.3 53.1l-1.5 1.1M95.3 55.7l-1.5 1M199.6 45.5l-1.5 1M199.6 48.1l-1.5 1M199.6 50.6l-1.5 1M199.6 53.1l-1.5 1.1M199.6 55.7l-1.5 1M199.6 58.2l-1.5 1.1M95.3 60.8l-1.5 1M95.3 63.3l-1.5 1"/>
<path d="M95.3 68.4l-1.5 1M95.3 71l-1.5 1M95.3 76l-1.5 1.1M95.3 78.6l-1.5 1M199.6 60.8l-1.5 1M199.6 63.3l-1.5 1M199.6 76l-1.5 1.1M199.6 78.6l-1.5 1M95.3 83.7l-1.5 1M95.3 86.2l-1.5 1M95.3 91.3l-1.5 1M95.3 93.9l-1.5 1"/>
<path d="M95.3 98.9l-1.5 1.1M199.6 81.1l-1.5 1M199.6 83.7l-1.5 1M199.6 86.2l-1.5 1M199.6 88.8l-1.5 1M199.6 91.3l-1.5 1M199.6 93.9l-1.5 1M95.3 101.5l-1.5 1M95.3 106.6l-1.5 1M95.3 109.1l-1.5 1M199.6 106.6l-1.5 1M199.6 109.1l-1.5 1"/>
</g>
<g fill="none" stroke="#f00" stroke-width=".25">
<path d="M95.1 44.6h1l.5-.5h1l.5 .5h1M95.1 45.3h1l.5 .5h1l.5-.5h1M95.1 47.2h1l.5-.5h1l.5 .5h1M95.1 47.8h1l.5 .5h1l.5-.5h1M95.1 52.3h1l.5-.6h1l.5 .6h1M95.1 52.9h1l.5 .5h1l.5-.5h1M95.1 54.8h1l.5-.5h1l.5 .5h1M95.1 55.4h1l.5 .5h1l.5-.5h1M95.1 59.9h1l.5-.5h1l.5 .5h1M199.4 44.6h1l.5-.5h1l.5 .5h1M199.4 45.3h1l.5 .5h1l.5-.5h1M199.4 47.2h1l.5-.5h1l.5 .5h1"/>
<path d="M199.4 47.8h1l.5 .5h1l.5-.5h1M199.4 49.7h1l.5-.5h1l.5 .5h1M199.4 50.4h1l.5 .5h1l.5-.5h1M199.4 52.3h1l.5-.5h1l.5 .5h1M199.4 52.9h1l.5 .5h1l.5-.5h1M199.4 54.8h1l.5-.5h1l.5 .5h1M199.4 55.4h1l.5 .5h1l.5-.5h1M199.4 57.4h1l.5-.6h1l.5 .6h1M199.4 58h1l.5 .5h1l.5-.5h1M199.4 59.9h1l.5-.5h1l.5 .5h1M95.1 60.5h1l.5 .5h1l.5-.5h1M95.1 62.4h1l.5-.5h1l.5 .5h1"/>
<path d="M95.1 63.1h1l.5 .5h1l.5-.5h1M95.1 67.5h1l.5-.5h1l.5 .5h1M95.1 68.2h1l.5 .5h1l.5-.5h1M95.1 70.1h1l.5-.5h1l.5 .5h1M95.1 70.7h1l.5 .5h1l.5-.5h1M95.1 75.2h1l.5-.6h1l.5 .6h1M95.1 75.8h1l.5 .5h1l.5-.5h1M95.1 77.7h1l.5-.5h1l.5 .5h1M95.1 78.3h1l.5 .5h1l.5-.5h1M199.4 60.5h1l.5 .5h1l.5-.5h1M199.4 62.4h1l.5-.5h1l.5 .5h1M199.4 63.1h1l.5 .5h1l.5-.5h1"/>
<path d="M199.4 75.2h1l.5-.6h1l.5 .6h1M199.4 75.8h1l.5 .5h1l.5-.5h1M199.4 77.7h1l.5-.5h1l.5 .5h1M199.4 78.3h1l.5 .5h1l.5-.5h1M95.1 82.8h1l.5-.5h1l.5 .5h1M95.1 83.4h1l.5 .5h1l.5-.5h1M95.1 85.3h1l.5-.5h1l.5 .5h1M95.1 86h1l.5 .5h1l.5-.5h1M95.1 90.4h1l.5-.5h1l.5 .5h1M95.1 91.1h1l.5 .5h1l.5-.5h1M95.1 93h1l.5-.5h1l.5 .5h1M95.1 93.6h1l.5 .5h1l.5-.5h1"/>
<path d="M95.1 98h1l.5-.5h1l.5 .5h1M95.1 98.7h1l.5 .5h1l.5-.5h1M199.4 80.2h1l.5-.5h1l.5 .5h1M199.4 80.9h1l.5 .5h1l.5-.5h1M199.4 82.8h1l.5-.5h1l.5 .5h1M199.4 83.4h1l.5 .5h1l.5-.5h1M199.4 85.3h1l.5-.5h1l.5 .5h1M199.4 86h1l.5 .5h1l.5-.5h1M199.4 87.9h1l.5-.5h1l.5 .5h1M199.4 88.5h1l.5 .5h1l.5-.5h1M199.4 90.4h1l.5-.5h1l.5 .5h1M199.4 91.1h1l.5 .5h1l.5-.5h1"/>
<path d="M199.4 93h1l.5-.5h1l.5 .5h1M199.4 93.6h1l.5 .5h1l.5-.5h1M95.1 100.6h1l.5-.5h1l.5 .5h1M95.1 101.2h1l.5 .5h1l.5-.5h1M95.1 105.7h1l.5-.5h1l.5 .5h1M95.1 106.3h1l.5 .5h1l.5-.5h1M95.1 108.2h1l.5-.5h1l.5 .5h1M95.1 108.9h1l.5 .5h1l.5-.5h1M199.4 105.7h1l.5-.5h1l.5 .5h1M199.4 106.3h1l.5 .5h1l.5-.5h1M199.4 108.2h1l.5-.5h1l.5 .5h1M199.4 108.9h1l.5 .5h1l.5-.5h1"/>
</g>
<path d="M135.8 106.3h12.7l1.3 1.3-1.3 1.3h-12.7l-1.3-1.3z" fill-rule="evenodd" fill="#ffff80"/>
<path d="M135.8 106.3h12.7l1.3 1.3-1.3 1.3h-12.7l-1.3-1.3z" fill="none" stroke="#800000" stroke-width=".21"/>
<path d="M134.5 105l1.3-1.2h12.7l1.3 1.2-1.3 1.3h-12.7z" fill-rule="evenodd" fill="#ffff80"/>
<path d="M134.5 105l1.3-1.2h12.7l1.3 1.2-1.3 1.3h-12.7z" fill="none" stroke="#800000" stroke-width=".21"/>
<g fill="none" stroke="#000080" stroke-width=".25">
<path d="M198.1 46.5h30.5M198.1 49.1h30.5M198.1 51.6h30.5M198.1 54.2h30.5M198.1 56.7h30.5M198.1 59.3h30.5M198.1 77.1h30.5M198.1 79.6h30.5M198.1 64.3h30.5M198.1 61.8h30.5M198.1 82.1h30.5M198.1 84.7h30.5"/>
<path d="M198.1 87.2h30.5M198.1 89.8h30.5M198.1 92.3h30.5M198.1 94.9h30.5M198.1 110.1h30.5M198.1 107.6h30.5M198.1 117.8h30.5M109.1 176.3h10.1v2.5M109.1 171.2h25.4"/>
</g>
<circle cx="129.4" cy="171.2" r=".51" fill="#000080"/>
<circle cx="129.4" cy="171.2" r=".51" fill="none" stroke="#000080" stroke-width=".21"/>
<path d="M167.6 163.6v7.6h-22.9" fill="none" stroke="#000080" stroke-width=".25"/>
<circle cx="149.8" cy="171.2" r=".51" fill="#000080"/>
<circle cx="149.8" cy="171.2" r=".51" fill="none" stroke="#000080" stroke-width=".21"/>
<path d="M104 41.4h-2.6v104.3" fill="none" stroke="#000080" stroke-width=".25"/>
<circle cx="101.4" cy="44" r=".51" fill="#000080"/>
<circle cx="101.4" cy="44" r=".51" fill="none" stroke="#000080" stroke-width=".21"/>
<circle cx="101.4" cy="51.6" r=".51" fill="#000080"/>
<circle cx="101.4" cy="51.6" r=".51" fill="none" stroke="#000080" stroke-width=".21"/>
<circle cx="101.4" cy="59.3" r=".51" fill="#000080"/>
<circle cx="101.4" cy="59.3" r=".51" fill="none" stroke="#000080" stroke-width=".21"/>
<circle cx="101.4" cy="66.9" r=".51" fill="#000080"/>
<circle cx="101.4" cy="66.9" r=".51" fill="none" stroke="#000080" stroke-width=".21"/>
<circle cx="101.4" cy="74.5" r=".51" fill="#000080"/>
<circle cx="101.4" cy="74.5" r=".51" fill="none" stroke="#000080" stroke-width=".21"/>
<circle cx="101.4" cy="82.1" r=".51" fill="#000080"/>
<circle cx="101.4" cy="82.1" r=".51" fill="none" stroke="#000080" stroke-width=".21"/>
<circle cx="101.4" cy="89.8" r=".51" fill="#000080"/>
<circle cx="101.4" cy="89.8" r=".51" fill="none" stroke="#000080" stroke-width=".21"/>
<circle cx="101.4" cy="97.4" r=".51" fill="#000080"/>
<circle cx="101.4" cy="97.4" r=".51" fill="none" stroke="#000080" stroke-width=".21"/>
<circle cx="101.4" cy="105" r=".51" fill="#000080"/>
<circle cx="101.4" cy="105" r=".51" fill="none" stroke="#000080" stroke-width=".21"/>
<circle cx="101.4" cy="112.7" r=".51" fill="#000080"/>
<circle cx="101.4" cy="112.7" r=".51" fill="none" stroke="#000080" stroke-width=".21"/>
<circle cx="101.4" cy="127.9" r=".51" fill="#000080"/>
<circle cx="101.4" cy="127.9" r=".51" fill="none" stroke="#000080" stroke-width=".21"/>
<circle cx="101.4" cy="130.5" r=".51" fill="#000080"/>
<circle cx="101.4" cy="130.5" r=".51" fill="none" stroke="#000080" stroke-width=".21"/>
<circle cx="101.4" cy="133" r=".51" fill="#000080"/>
<circle cx="101.4" cy="133" r=".51" fill="none" stroke="#000080" stroke-width=".21"/>
<circle cx="101.4" cy="140.7" r=".51" fill="#000080"/>
<circle cx="101.4" cy="140.7" r=".51" fill="none" stroke="#000080" stroke-width=".21"/>
<path d="M101.4 44h2.6" fill="none" stroke="#000080" stroke-width=".25"/>
<circle cx="101.4" cy="44" r=".51" fill="#000080"/>
<circle cx="101.4" cy="44" r=".51" fill="none" stroke="#000080" stroke-width=".21"/>
<path d="M101.4 51.6h2.6" fill="none" stroke="#000080" stroke-width=".25"/>
<circle cx="101.4" cy="51.6" r=".51" fill="#000080"/>
<circle cx="101.4" cy="51.6" r=".51" fill="none" stroke="#000080" stroke-width=".21"/>
<path d="M101.4 59.3h2.6" fill="none" stroke="#000080" stroke-width=".25"/>
<circle cx="101.4" cy="59.3" r=".51" fill="#000080"/>
<circle cx="101.4" cy="59.3" r=".51" fill="none" stroke="#000080" stroke-width=".21"/>
<path d="M101.4 66.9h2.6" fill="none" stroke="#000080" stroke-width=".25"/>
<circle cx="101.4" cy="66.9" r=".51" fill="#000080"/>
<circle cx="101.4" cy="66.9" r=".51" fill="none" stroke="#000080" stroke-width=".21"/>
<path d="M101.4 74.5h2.6" fill="none" stroke="#000080" stroke-width=".25"/>
<circle cx="101.4" cy="74.5" r=".51" fill="#000080"/>
<circle cx="101.4" cy="74.5" r=".51" fill="none" stroke="#000080" stroke-width=".21"/>
<path d="M101.4 82.1h2.6" fill="none" stroke="#000080" stroke-width=".25"/>
<circle cx="101.4" cy="82.1" r=".51" fill="#000080"/>
<circle cx="101.4" cy="82.1" r=".51" fill="none" stroke="#000080" stroke-width=".21"/>
<path d="M101.4 89.8h2.6" fill="none" stroke="#000080" stroke-width=".25"/>
<circle cx="101.4" cy="89.8" r=".51" fill="#000080"/>
<circle cx="101.4" cy="89.8" r=".51" fill="none" stroke="#000080" stroke-width=".21"/>
<path d="M101.4 97.4h2.6" fill="none" stroke="#000080" stroke-width=".25"/>
<circle cx="101.4" cy="97.4" r=".51" fill="#000080"/>
<circle cx="101.4" cy="97.4" r=".51" fill="none" stroke="#000080" stroke-width=".21"/>
<path d="M101.4 105h2.6" fill="none" stroke="#000080" stroke-width=".25"/>
<circle cx="101.4" cy="105" r=".51" fill="#000080"/>
<circle cx="101.4" cy="105" r=".51" fill="none" stroke="#000080" stroke-width=".21"/>
<path d="M101.4 112.7h2.6" fill="none" stroke="#000080" stroke-width=".25"/>
<circle cx="101.4" cy="112.7" r=".51" fill="#000080"/>
<circle cx="101.4" cy="112.7" r=".51" fill="none" stroke="#000080" stroke-width=".21"/>
<path d="M101.4 130.5h2.6" fill="none" stroke="#000080" stroke-width=".25"/>
<circle cx="101.4" cy="130.5" r=".51" fill="#000080"/>
<circle cx="101.4" cy="130.5" r=".51" fill="none" stroke="#000080" stroke-width=".21"/>
<path d="M101.4 133h2.6" fill="none" stroke="#000080" stroke-width=".25"/>
<circle cx="101.4" cy="133" r=".51" fill="#000080"/>
<circle cx="101.4" cy="133" r=".51" fill="none" stroke="#000080" stroke-width=".21"/>
<path d="M101.4 127.9h2.6" fill="none" stroke="#000080" stroke-width=".25"/>
<circle cx="101.4" cy="127.9" r=".51" fill="#000080"/>
<circle cx="101.4" cy="127.9" r=".51" fill="none" stroke="#000080" stroke-width=".21"/>
<path d="M129.4 130.5h2.5" fill="none" stroke="#000080" stroke-width=".25"/>
<circle cx="131.9" cy="130.5" r=".51" fill="#000080"/>
<circle cx="131.9" cy="130.5" r=".51" fill="none" stroke="#000080" stroke-width=".21"/>
<path d="M129.4 127.9h2.5" fill="none" stroke="#000080" stroke-width=".25"/>
<circle cx="131.9" cy="127.9" r=".51" fill="#000080"/>
<circle cx="131.9" cy="127.9" r=".51" fill="none" stroke="#000080" stroke-width=".21"/>
<path d="M129.4 61.8h2.5" fill="none" stroke="#000080" stroke-width=".25"/>
<circle cx="131.9" cy="61.8" r=".51" fill="#000080"/>
<circle cx="131.9" cy="61.8" r=".51" fill="none" stroke="#000080" stroke-width=".21"/>
<path d="M129.4 59.3h2.5" fill="none" stroke="#000080" stroke-width=".25"/>
<circle cx="131.9" cy="59.3" r=".51" fill="#000080"/>
<circle cx="131.9" cy="59.3" r=".51" fill="none" stroke="#000080" stroke-width=".21"/>
<path d="M129.4 56.7h2.5" fill="none" stroke="#000080" stroke-width=".25"/>
<circle cx="131.9" cy="56.7" r=".51" fill="#000080"/>
<circle cx="131.9" cy="56.7" r=".51" fill="none" stroke="#000080" stroke-width=".21"/>
<g fill="none" stroke="#000080" stroke-width=".25">
<path d="M78.5 56.7h25.5M78.5 54.2h25.5M78.5 49.1h25.5M78.5 46.5h25.5M78.5 79.6h25.5M78.5 77.1h25.5M78.5 72h25.5M78.5 69.4h25.5M78.5 64.3h25.5M78.5 61.8h25.5M129.4 64.3h2.5M78.5 100h25.5"/>
<path d="M78.5 94.9h25.5M78.5 92.3h25.5M78.5 87.2h25.5M78.5 84.7h25.5M78.5 102.5h25.5M78.5 107.6h25.5M129.4 102.5h15.3"/>
</g>
<circle cx="131.9" cy="64.3" r=".51" fill="#000080"/>
<circle cx="131.9" cy="64.3" r=".51" fill="none" stroke="#000080" stroke-width=".21"/>
<path d="M131.9 44v89h-2.5" fill="none" stroke="#000080" stroke-width=".25"/>
<circle cx="131.9" cy="130.5" r=".51" fill="#000080"/>
<circle cx="131.9" cy="130.5" r=".51" fill="none" stroke="#000080" stroke-width=".21"/>
<circle cx="131.9" cy="127.9" r=".51" fill="#000080"/>
<circle cx="131.9" cy="127.9" r=".51" fill="none" stroke="#000080" stroke-width=".21"/>
<circle cx="131.9" cy="64.3" r=".51" fill="#000080"/>
<circle cx="131.9" cy="64.3" r=".51" fill="none" stroke="#000080" stroke-width=".21"/>
<circle cx="131.9" cy="61.8" r=".51" fill="#000080"/>
<circle cx="131.9" cy="61.8" r=".51" fill="none" stroke="#000080" stroke-width=".21"/>
<circle cx="131.9" cy="59.3" r=".51" fill="#000080"/>
<circle cx="131.9" cy="59.3" r=".51" fill="none" stroke="#000080" stroke-width=".21"/>
<circle cx="131.9" cy="56.7" r=".51" fill="#000080"/>
<circle cx="131.9" cy="56.7" r=".51" fill="none" stroke="#000080" stroke-width=".21"/>
<circle cx="131.9" cy="46.5" r=".51" fill="#000080"/>
<circle cx="131.9" cy="46.5" r=".51" fill="none" stroke="#000080" stroke-width=".21"/>
<circle cx="131.9" cy="44" r=".51" fill="#000080"/>
<circle cx="131.9" cy="44" r=".51" fill="none" stroke="#000080" stroke-width=".21"/>
<path d="M129.4 46.5h2.5" fill="none" stroke="#000080" stroke-width=".25"/>
<circle cx="131.9" cy="46.5" r=".51" fill="#000080"/>
<circle cx="131.9" cy="46.5" r=".51" fill="none" stroke="#000080" stroke-width=".21"/>
<path d="M78.5 110.1h25.5M101.4 140.7h2.6" fill="none" stroke="#000080" stroke-width=".25"/>
<circle cx="101.4" cy="140.7" r=".51" fill="#000080"/>
<circle cx="101.4" cy="140.7" r=".51" fill="none" stroke="#000080" stroke-width=".21"/>
<path d="M142.1 36.4h-10.2v7.6h-2.5M129.4 140.7h2.5v5" fill="none" stroke="#000080" stroke-width=".25"/>
<circle cx="131.9" cy="44" r=".51" fill="#000080"/>
<circle cx="131.9" cy="44" r=".51" fill="none" stroke="#000080" stroke-width=".21"/>
<path d="M129.4 105h5.1M129.4 107.6h5.1" fill="none" stroke="#000080" stroke-width=".25"/>
<path d="M243.9 54.2h2.5M243.9 84.7h2.5" fill="none" stroke="#cbdaff" stroke-width="1.3"/>
<path d="M244.4 53.7l1 .9M244.4 84.3l1 .8" fill="none" stroke="#adbce7" stroke-width=".38"/>
<path d="M243.9 54.2h2.5M243.9 84.7h2.5" fill="none" stroke="#adbce7" stroke-width=".25"/>
<use href="#words"/>
</svg>
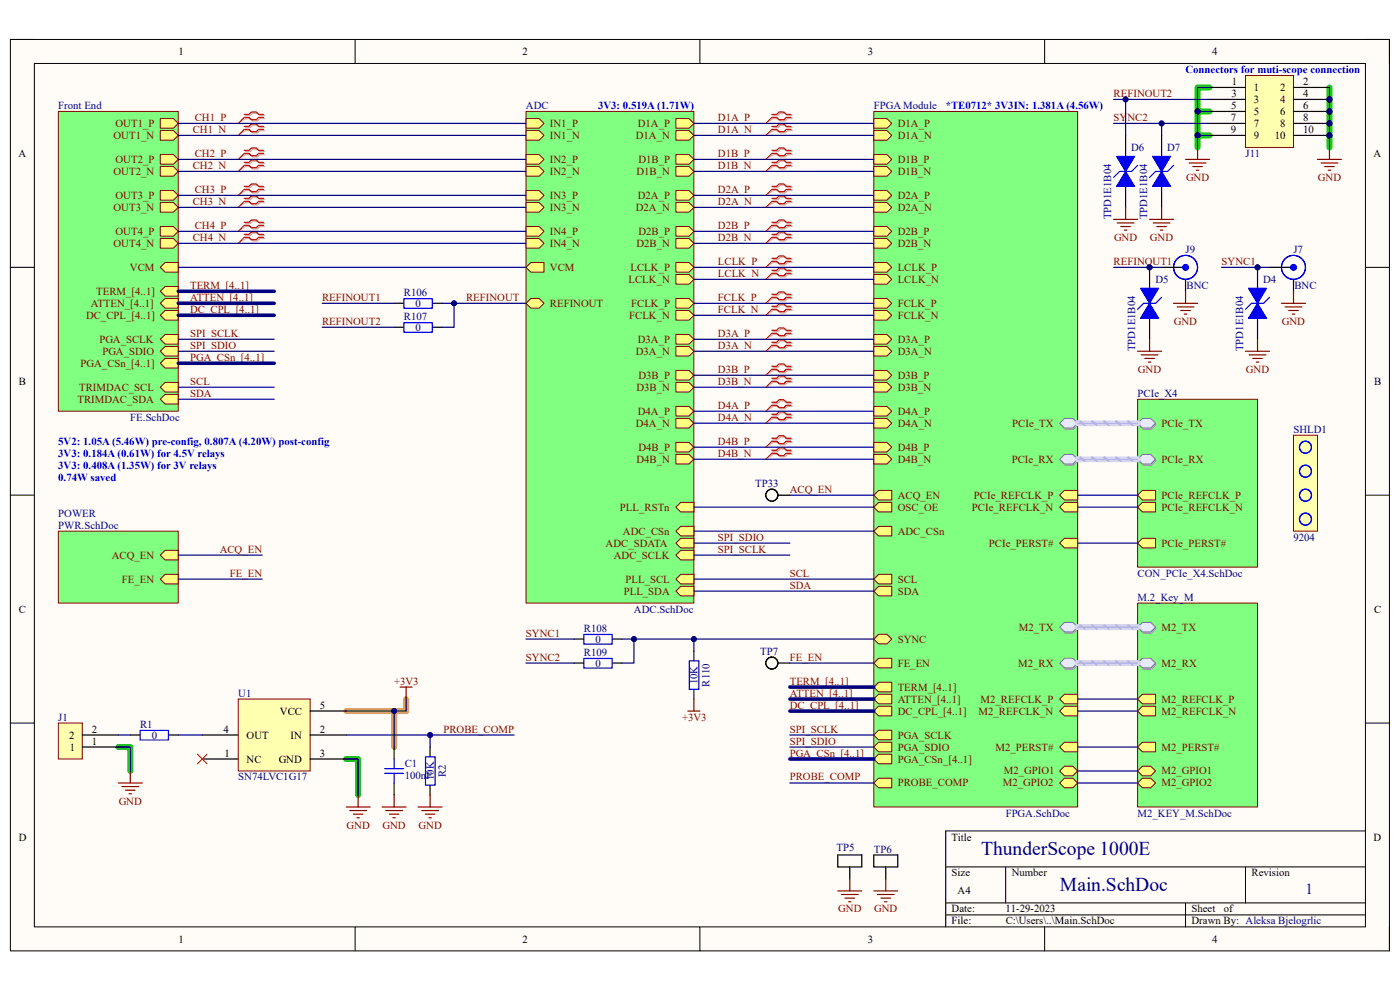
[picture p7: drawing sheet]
<svg xmlns="http://www.w3.org/2000/svg" width="297mm" height="210mm" viewBox="0 0 297 210" stroke-linecap="round" stroke-linejoin="round" font-family="sans-serif">
<defs><g id="words">
<g font-size="4.1" fill="#000080">
<text x="208.2" y="181.5">ThunderScope 1000E</text>
<text x="224.9" y="189.1">Main.SchDoc</text>
</g>
<text font-size="3.2" fill="#000080" x="276.9" y="189.6">1</text>
<g font-size="2.3">
<text x="37.9" y="11.7">1</text>
<text x="110.9" y="11.7">2</text>
<text x="184.1" y="11.7">3</text>
<text x="257.1" y="11.7">4</text>
<text x="261.2" y="23.1">5</text>
<text x="261.2" y="20.6">3</text>
<text x="261.3" y="18">1</text>
<text x="266" y="19.3">1</text>
<text x="266" y="21.8">3</text>
<text x="271.6" y="19.3">2</text>
<text x="271.6" y="21.8">4</text>
<text x="276.4" y="18">2</text>
<text x="276.4" y="20.6">4</text>
<text x="276.4" y="23.1">6</text>
<text x="261.2" y="25.7">7</text>
<text x="261.2" y="28.2">9</text>
<text x="266" y="24.4">5</text>
<text x="266" y="26.9">7</text>
<text x="266" y="29.5">9</text>
<text x="270.4" y="29.5">10</text>
<text x="271.6" y="24.4">6</text>
<text x="271.6" y="26.9">8</text>
<text x="276.4" y="25.7">8</text>
<text x="276.4" y="28.2">10</text>
<text x="3.9" y="33.3">A</text>
<text x="291.4" y="33.3">A</text>
<text x="4" y="81.6">B</text>
<text x="291.5" y="81.6">B</text>
<text x="4" y="130">C</text>
<text x="291.5" y="130">C</text>
<text x="19.5" y="155.4">2</text>
<text x="47.4" y="155.4">4</text>
<text x="59.4" y="151.6">VCC</text>
<text x="67.8" y="155.4">2</text>
<text x="67.8" y="150.3">5</text>
<text x="14.6" y="156.7">2</text>
<text x="14.8" y="159.2">1</text>
<text x="19.5" y="157.9">1</text>
<text x="47.6" y="160.5">1</text>
<text x="52.3" y="156.7">OUT</text>
<text x="52.3" y="161.8">NC</text>
<text x="59.1" y="161.8">GND</text>
<text x="61.6" y="156.7">IN</text>
<text x="67.8" y="160.5">3</text>
<text x="4" y="178.3">D</text>
<text x="201.9" y="178.3">Title</text>
<text x="291.4" y="178.3">D</text>
<text x="201.9" y="185.9">Size</text>
<text x="214.6" y="185.9">Number</text>
<text x="265.5" y="185.9">Revision</text>
<text x="203.2" y="189.7">A4</text>
<text x="201.9" y="193.5">Date:</text>
<text x="201.9" y="196.1">File:</text>
<text x="213.3" y="193.5">11-29-2023</text>
<text x="213.4" y="196.1">C:\Users\..\Main.SchDoc</text>
<text x="252.8" y="196.1">Drawn By: Aleksa Bjelogrlic</text>
<text x="252.8" y="193.5">Sheet</text>
<text x="259.6" y="193.5">of</text>
<text x="37.9" y="199.9">1</text>
<text x="110.9" y="199.9">2</text>
<text x="184.1" y="199.9">3</text>
<text x="257.1" y="199.9">4</text>
</g>
<g font-size="2.3" fill="#00f">
<text x="251.5" y="15.5">Connectors for muti-scope connection</text>
<text x="126.9" y="23.1">3V3: 0.519A (1.71W)</text>
<text x="200.6" y="23.1">*TE0712* 3V3IN: 1.381A (4.56W)</text>
<text x="12.4" y="94.4">5V2: 1.05A (5.46W) pre-config, 0.807A (4.20W) post-config</text>
<text x="12.4" y="96.9">3V3: 0.184A (0.61W) for 4.5V relays</text>
<text x="12.4" y="99.4">3V3: 0.408A (1.35W) for 3V relays</text>
<text x="12.4" y="102">0.74W saved</text>
</g>
<g font-size="2.3" fill="#000080">
<text x="12.4" y="23.1">Front End</text>
<text x="111.6" y="23.1">ADC</text>
<text x="185.4" y="23.1">FPGA Module</text>
<text x="240" y="32">D6</text>
<text x="247.6" y="32">D7</text>
<text x="264.2" y="33.3">J11</text>
<text x="235.8" y="46.5" transform="rotate(-90 235.8 46.5)">TPD1E1B04</text>
<text x="243.4" y="46.5" transform="rotate(-90 243.4 46.5)">TPD1E1B04</text>
<text x="251.5" y="53.6">J9</text>
<text x="274.4" y="53.6">J7</text>
<text x="245.1" y="60">D5</text>
<text x="268" y="60">D4</text>
<text x="85.7" y="62.9">R106</text>
<text x="88.2" y="65.1">0</text>
<text x="251.7" y="61.3">BNC</text>
<text x="274.6" y="61.3">BNC</text>
<text x="85.7" y="67.9">R107</text>
<text x="88.2" y="70.2">0</text>
<text x="240.8" y="74.5" transform="rotate(-90 240.8 74.5)">TPD1E1B04</text>
<text x="263.7" y="74.5" transform="rotate(-90 263.7 74.5)">TPD1E1B04</text>
<text x="27.6" y="89.3">FE.SchDoc</text>
<text x="241.3" y="84.2">PCIe_X4</text>
<text x="274.4" y="91.8">SHLD1</text>
<text x="160.2" y="103.3">TP33</text>
<text x="12.4" y="109.6">POWER</text>
<text x="12.4" y="112.1">PWR.SchDoc</text>
<text x="274.4" y="114.7">9204</text>
<text x="241.3" y="122.3">CON_PCIe_X4.SchDoc</text>
<text x="134.5" y="130">ADC.SchDoc</text>
<text x="241.3" y="127.4">M.2_Key_M</text>
<text x="123.9" y="134.1">R108</text>
<text x="126.3" y="136.3">0</text>
<text x="123.9" y="139.1">R109</text>
<text x="126.3" y="141.4">0</text>
<text x="161.3" y="138.9">TP7</text>
<text x="50.5" y="147.8">U1</text>
<text x="148" y="145.2" transform="rotate(-90 148 145.2)">10K</text>
<text x="150.5" y="145.7" transform="rotate(-90 150.5 145.7)">R110</text>
<text x="12.4" y="152.9">J1</text>
<text x="29.7" y="154.4">R1</text>
<text x="32.2" y="156.7">0</text>
<text x="50.5" y="165.6">SN74LVC1G17</text>
<text x="85.9" y="162.8">C1</text>
<text x="85.9" y="165.3">100nF</text>
<text x="92" y="165.5" transform="rotate(-90 92 165.5)">10K</text>
<text x="94.6" y="164.8" transform="rotate(-90 94.6 164.8)">R2</text>
<text x="213.4" y="173.2">FPGA.SchDoc</text>
<text x="241.3" y="173.2">M2_KEY_M.SchDoc</text>
<text x="177.5" y="180.6">TP5</text>
<text x="185.4" y="180.8">TP6</text>
</g>
<g font-size="2.3" fill="#800000">
<text x="236.3" y="20.6">REFINOUT2</text>
<text x="24.1" y="29.5">OUT1_N</text>
<text x="24.5" y="26.9">OUT1_P</text>
<text x="40.9" y="28.2">CH1_N</text>
<text x="41.3" y="25.7">CH1_P</text>
<text x="116.7" y="29.5">IN1_N</text>
<text x="116.7" y="26.9">IN1_P</text>
<text x="134.9" y="29.5">D1A_N</text>
<text x="135.3" y="26.9">D1A_P</text>
<text x="152.3" y="25.7">D1A_P</text>
<text x="152.3" y="28.2">D1A_N</text>
<text x="190.5" y="26.9">D1A_P</text>
<text x="190.5" y="29.5">D1A_N</text>
<text x="236.3" y="25.7">SYNC2</text>
<text x="24.5" y="34.6">OUT2_P</text>
<text x="40.9" y="35.9">CH2_N</text>
<text x="41.3" y="33.3">CH2_P</text>
<text x="116.7" y="34.6">IN2_P</text>
<text x="135.4" y="34.6">D1B_P</text>
<text x="152.3" y="33.3">D1B_P</text>
<text x="152.3" y="35.9">D1B_N</text>
<text x="190.5" y="34.6">D1B_P</text>
<text x="24.1" y="37.1">OUT2_N</text>
<text x="41.3" y="40.9">CH3_P</text>
<text x="116.7" y="37.1">IN2_N</text>
<text x="135" y="37.1">D1B_N</text>
<text x="152.3" y="40.9">D2A_P</text>
<text x="190.5" y="37.1">D1B_N</text>
<text x="251.6" y="38.4">GND</text>
<text x="279.6" y="38.4">GND</text>
<text x="24.1" y="44.7">OUT3_N</text>
<text x="24.5" y="42.2">OUT3_P</text>
<text x="40.9" y="43.5">CH3_N</text>
<text x="116.7" y="44.7">IN3_N</text>
<text x="116.7" y="42.2">IN3_P</text>
<text x="134.9" y="44.7">D2A_N</text>
<text x="135.3" y="42.2">D2A_P</text>
<text x="152.3" y="43.5">D2A_N</text>
<text x="190.5" y="42.2">D2A_P</text>
<text x="190.5" y="44.7">D2A_N</text>
<text x="24.1" y="52.4">OUT4_N</text>
<text x="24.5" y="49.8">OUT4_P</text>
<text x="40.9" y="51.1">CH4_N</text>
<text x="41.3" y="48.6">CH4_P</text>
<text x="116.7" y="52.4">IN4_N</text>
<text x="116.7" y="49.8">IN4_P</text>
<text x="135" y="52.4">D2B_N</text>
<text x="135.4" y="49.8">D2B_P</text>
<text x="152.3" y="48.6">D2B_P</text>
<text x="152.3" y="51.1">D2B_N</text>
<text x="190.5" y="49.8">D2B_P</text>
<text x="190.5" y="52.4">D2B_N</text>
<text x="236.3" y="51.1">GND</text>
<text x="244" y="51.1">GND</text>
<text x="27.6" y="57.4">VCM</text>
<text x="116.7" y="57.4">VCM</text>
<text x="133.3" y="60">LCLK_N</text>
<text x="133.8" y="57.4">LCLK_P</text>
<text x="152.3" y="56.2">LCLK_P</text>
<text x="152.3" y="58.7">LCLK_N</text>
<text x="190.5" y="57.4">LCLK_P</text>
<text x="190.5" y="60">LCLK_N</text>
<text x="236.3" y="56.2">REFINOUT1</text>
<text x="259.2" y="56.2">SYNC1</text>
<text x="19.3" y="65.1">ATTEN_[4..1]</text>
<text x="20.4" y="62.6">TERM_[4..1]</text>
<text x="40.3" y="63.8">ATTEN_[4..1]</text>
<text x="40.3" y="61.3">TERM_[4..1]</text>
<text x="68.3" y="63.8">REFINOUT1</text>
<text x="98.9" y="63.8">REFINOUT</text>
<text x="116.7" y="65.1">REFINOUT</text>
<text x="133.9" y="65.1">FCLK_P</text>
<text x="152.3" y="63.8">FCLK_P</text>
<text x="190.5" y="65.1">FCLK_P</text>
<text x="18.2" y="67.6">DC_CPL_[4..1]</text>
<text x="40.3" y="66.4">DC_CPL_[4..1]</text>
<text x="40.3" y="71.5">SPI_SCLK</text>
<text x="68.3" y="68.9">REFINOUT2</text>
<text x="133.5" y="67.6">FCLK_N</text>
<text x="152.3" y="71.5">D3A_P</text>
<text x="152.3" y="66.4">FCLK_N</text>
<text x="190.5" y="67.6">FCLK_N</text>
<text x="249" y="68.9">GND</text>
<text x="271.9" y="68.9">GND</text>
<text x="17.1" y="77.8">PGA_CSn_[4..1]</text>
<text x="21.1" y="72.7">PGA_SCLK</text>
<text x="21.7" y="75.3">PGA_SDIO</text>
<text x="40.3" y="74">SPI_SDIO</text>
<text x="40.3" y="76.5">PGA_CSn_[4..1]</text>
<text x="134.9" y="75.3">D3A_N</text>
<text x="135.3" y="72.7">D3A_P</text>
<text x="152.3" y="74">D3A_N</text>
<text x="190.5" y="72.7">D3A_P</text>
<text x="190.5" y="75.3">D3A_N</text>
<text x="16.8" y="82.9">TRIMDAC_SCL</text>
<text x="40.3" y="81.6">SCL</text>
<text x="135" y="82.9">D3B_N</text>
<text x="135.4" y="80.3">D3B_P</text>
<text x="152.3" y="79.1">D3B_P</text>
<text x="152.3" y="81.6">D3B_N</text>
<text x="190.5" y="80.3">D3B_P</text>
<text x="190.5" y="82.9">D3B_N</text>
<text x="241.4" y="79.1">GND</text>
<text x="264.3" y="79.1">GND</text>
<text x="16.4" y="85.4">TRIMDAC_SDA</text>
<text x="40.3" y="84.2">SDA</text>
<text x="135.3" y="88">D4A_P</text>
<text x="152.3" y="86.7">D4A_P</text>
<text x="152.3" y="89.3">D4A_N</text>
<text x="190.5" y="88">D4A_P</text>
<text x="134.9" y="90.6">D4A_N</text>
<text x="135.4" y="95.6">D4B_P</text>
<text x="152.3" y="94.4">D4B_P</text>
<text x="190.5" y="90.6">D4A_N</text>
<text x="190.5" y="95.6">D4B_P</text>
<text x="214.8" y="90.6">PCIe_TX</text>
<text x="246.4" y="90.6">PCIe_TX</text>
<text x="135" y="98.2">D4B_N</text>
<text x="152.3" y="96.9">D4B_N</text>
<text x="190.5" y="98.2">D4B_N</text>
<text x="214.6" y="98.2">PCIe_RX</text>
<text x="246.4" y="98.2">PCIe_RX</text>
<text x="167.6" y="104.5">ACQ_EN</text>
<text x="190.5" y="105.8">ACQ_EN</text>
<text x="206.6" y="105.8">PCIe_REFCLK_P</text>
<text x="246.4" y="105.8">PCIe_REFCLK_P</text>
<text x="131.5" y="108.3">PLL_RSTn</text>
<text x="132.2" y="113.4">ADC_CSn</text>
<text x="190.5" y="108.3">OSC_OE</text>
<text x="190.5" y="113.4">ADC_CSn</text>
<text x="206.2" y="108.3">PCIe_REFCLK_N</text>
<text x="246.4" y="108.3">PCIe_REFCLK_N</text>
<text x="23.7" y="118.5">ACQ_EN</text>
<text x="46.6" y="117.3">ACQ_EN</text>
<text x="128.5" y="116">ADC_SDATA</text>
<text x="130.2" y="118.5">ADC_SCLK</text>
<text x="152.3" y="117.3">SPI_SCLK</text>
<text x="152.3" y="114.7">SPI_SDIO</text>
<text x="209.8" y="116">PCIe_PERST#</text>
<text x="246.4" y="116">PCIe_PERST#</text>
<text x="25.9" y="123.6">FE_EN</text>
<text x="48.8" y="122.3">FE_EN</text>
<text x="132.7" y="123.6">PLL_SCL</text>
<text x="167.6" y="122.3">SCL</text>
<text x="167.6" y="124.9">SDA</text>
<text x="190.5" y="123.6">SCL</text>
<text x="132.3" y="126.2">PLL_SDA</text>
<text x="190.5" y="126.2">SDA</text>
<text x="111.6" y="135">SYNC1</text>
<text x="190.5" y="136.3">SYNC</text>
<text x="216.2" y="133.8">M2_TX</text>
<text x="246.4" y="133.8">M2_TX</text>
<text x="111.6" y="140.1">SYNC2</text>
<text x="167.6" y="140.1">FE_EN</text>
<text x="190.5" y="141.4">FE_EN</text>
<text x="216" y="141.4">M2_RX</text>
<text x="246.4" y="141.4">M2_RX</text>
<text x="83.6" y="145.2">+3V3</text>
<text x="167.6" y="147.8">ATTEN_[4..1]</text>
<text x="167.6" y="145.2">TERM_[4..1]</text>
<text x="190.5" y="149.1">ATTEN_[4..1]</text>
<text x="190.5" y="146.5">TERM_[4..1]</text>
<text x="208" y="149.1">M2_REFCLK_P</text>
<text x="246.4" y="149.1">M2_REFCLK_P</text>
<text x="94.1" y="155.4">PROBE_COMP</text>
<text x="144.7" y="152.9">+3V3</text>
<text x="167.6" y="150.3">DC_CPL_[4..1]</text>
<text x="167.6" y="155.4">SPI_SCLK</text>
<text x="190.5" y="151.6">DC_CPL_[4..1]</text>
<text x="207.6" y="151.6">M2_REFCLK_N</text>
<text x="246.4" y="151.6">M2_REFCLK_N</text>
<text x="167.6" y="157.9">SPI_SDIO</text>
<text x="167.6" y="160.5">PGA_CSn_[4..1]</text>
<text x="190.5" y="156.7">PGA_SCLK</text>
<text x="190.5" y="159.2">PGA_SDIO</text>
<text x="190.5" y="161.8">PGA_CSn_[4..1]</text>
<text x="211.2" y="159.2">M2_PERST#</text>
<text x="246.4" y="159.2">M2_PERST#</text>
<text x="167.6" y="165.6">PROBE_COMP</text>
<text x="190.5" y="166.8">PROBE_COMP</text>
<text x="212.8" y="166.8">M2_GPIO2</text>
<text x="213" y="164.3">M2_GPIO1</text>
<text x="246.4" y="164.3">M2_GPIO1</text>
<text x="246.4" y="166.8">M2_GPIO2</text>
<text x="25.2" y="170.7">GND</text>
<text x="73.5" y="175.8">GND</text>
<text x="81.2" y="175.8">GND</text>
<text x="88.8" y="175.8">GND</text>
<text x="177.8" y="193.5">GND</text>
<text x="185.5" y="193.5">GND</text>
</g>
</g></defs>
<path d="M2.2 8.4h292.6v193.3h-292.6z" fill-rule="evenodd" fill="#fffcf8"/>
<path d="M2.2 8.4h292.6v193.3h-292.6z" fill="none" stroke="#000" stroke-width=".21"/>
<path d="M7.3 13.5h282.4v183.1h-282.4z" fill-rule="evenodd" fill="#fffcf8"/>
<g fill="none" stroke="#000" stroke-width=".21">
<path d="M2.2 8.4h5.1M7.3 13.5h282.4v183.1h-282.4zM75.3 8.4v5.1M148.5 8.4v5.1M221.6 8.4v5.1M289.7 8.4h5.1v5.1M2.2 56.7h5.1M289.7 56.7h5.1M2.2 105h5.1M289.7 105.1h5.1M2.2 153.4h5.1M289.7 153.4h5.1"/>
<path d="M289.7 176.3h-89.1v20.3M75.3 196.6v5.1M148.5 196.6v5.1M200.6 183.9h89.1M200.6 191.5h89.1M200.6 194.1h89.1M213.4 183.9v7.6M221.6 196.6v5.1M251.5 191.5v5.1M264.2 183.9v7.6M294.8 196.6v5.1"/>
</g>
<path d="M256.6 18.6h-2.5v5M282 18.6v12.7M256.6 28.7h-2.5v2.6M256.6 23.6h-2.5v5.1M25.1 158.5h2.5v5.1M73.4 161h2.6v7.6" fill="none" stroke="#00be00" stroke-width="1.3"/>
<path d="M83.6 150.8v7.7M86.2 148.3v2.5h-12.8" fill="none" stroke="#f90" stroke-width="1.3"/>
<path d="M12.4 23.6h25.4v63.6h-25.4z" fill-rule="evenodd" fill="#80ff80"/>
<path d="M12.4 23.6h25.4v63.6h-25.4z" fill="none" stroke="#800000" stroke-width=".21"/>
<path d="M34 25.2h2.8l1 1-1 1h-2.8z" fill-rule="evenodd" fill="#ffff80"/>
<path d="M34 25.2h2.8l1 1-1 1h-2.8z" fill="none" stroke="#800000" stroke-width=".21"/>
<path d="M34 27.7h2.8l1 1-1 1h-2.8z" fill-rule="evenodd" fill="#ffff80"/>
<path d="M34 27.7h2.8l1 1-1 1h-2.8z" fill="none" stroke="#800000" stroke-width=".21"/>
<path d="M34 40.4h2.8l1 1-1 1.1h-2.8z" fill-rule="evenodd" fill="#ffff80"/>
<path d="M34 40.4h2.8l1 1-1 1.1h-2.8z" fill="none" stroke="#800000" stroke-width=".21"/>
<path d="M34 43h2.8l1 1-1 1h-2.8z" fill-rule="evenodd" fill="#ffff80"/>
<path d="M34 43h2.8l1 1-1 1h-2.8z" fill="none" stroke="#800000" stroke-width=".21"/>
<path d="M34 50.6h2.8l1 1-1 1h-2.8z" fill-rule="evenodd" fill="#ffff80"/>
<path d="M34 50.6h2.8l1 1-1 1h-2.8z" fill="none" stroke="#800000" stroke-width=".21"/>
<path d="M34 35.3h2.8l1 1.1-1 1h-2.8z" fill-rule="evenodd" fill="#ffff80"/>
<path d="M34 35.3h2.8l1 1.1-1 1h-2.8z" fill="none" stroke="#800000" stroke-width=".21"/>
<path d="M34 32.8h2.8l1 1-1 1h-2.8z" fill-rule="evenodd" fill="#ffff80"/>
<path d="M34 32.8h2.8l1 1-1 1h-2.8z" fill="none" stroke="#800000" stroke-width=".21"/>
<path d="M34 48.1h2.8l1 1-1 1h-2.8z" fill-rule="evenodd" fill="#ffff80"/>
<path d="M34 48.1h2.8l1 1-1 1h-2.8z" fill="none" stroke="#800000" stroke-width=".21"/>
<path d="M34 56.7l1-1h2.8v2h-2.8z" fill-rule="evenodd" fill="#ffff80"/>
<path d="M34 56.7l1-1h2.8v2h-2.8z" fill="none" stroke="#800000" stroke-width=".21"/>
<path d="M34 66.9l1-1h2.8v2h-2.8z" fill-rule="evenodd" fill="#ffff80"/>
<path d="M34 66.9l1-1h2.8v2h-2.8z" fill="none" stroke="#800000" stroke-width=".21"/>
<path d="M34 64.3l1-1h2.8v2.1h-2.8z" fill-rule="evenodd" fill="#ffff80"/>
<path d="M34 64.3l1-1h2.8v2.1h-2.8z" fill="none" stroke="#800000" stroke-width=".21"/>
<path d="M34 72l1-1h2.8v2h-2.8z" fill-rule="evenodd" fill="#ffff80"/>
<path d="M34 72l1-1h2.8v2h-2.8z" fill="none" stroke="#800000" stroke-width=".21"/>
<path d="M34 77.1l1-1.1h2.8v2.1h-2.8z" fill-rule="evenodd" fill="#ffff80"/>
<path d="M34 77.1l1-1.1h2.8v2.1h-2.8z" fill="none" stroke="#800000" stroke-width=".21"/>
<path d="M34 74.5l1-1h2.8v2h-2.8z" fill-rule="evenodd" fill="#ffff80"/>
<path d="M34 74.5l1-1h2.8v2h-2.8z" fill="none" stroke="#800000" stroke-width=".21"/>
<path d="M34 82.1l1-1h2.8v2.1h-2.8z" fill-rule="evenodd" fill="#ffff80"/>
<path d="M34 82.1l1-1h2.8v2.1h-2.8z" fill="none" stroke="#800000" stroke-width=".21"/>
<path d="M34 84.7l1-1h2.8v2h-2.8z" fill-rule="evenodd" fill="#ffff80"/>
<path d="M34 84.7l1-1h2.8v2h-2.8z" fill="none" stroke="#800000" stroke-width=".21"/>
<path d="M34 61.8l1-1h2.8v2h-2.8z" fill-rule="evenodd" fill="#ffff80"/>
<path d="M34 61.8l1-1h2.8v2h-2.8z" fill="none" stroke="#800000" stroke-width=".21"/>
<path d="M111.6 23.6h35.6v104.3h-35.6z" fill-rule="evenodd" fill="#80ff80"/>
<path d="M111.6 23.6h35.6v104.3h-35.6z" fill="none" stroke="#800000" stroke-width=".21"/>
<path d="M111.6 50.6h2.8l1 1-1 1h-2.8z" fill-rule="evenodd" fill="#ffff80"/>
<path d="M111.6 50.6h2.8l1 1-1 1h-2.8z" fill="none" stroke="#800000" stroke-width=".21"/>
<path d="M111.6 48.1h2.8l1 1-1 1h-2.8z" fill-rule="evenodd" fill="#ffff80"/>
<path d="M111.6 48.1h2.8l1 1-1 1h-2.8z" fill="none" stroke="#800000" stroke-width=".21"/>
<path d="M111.6 43h2.8l1 1-1 1h-2.8z" fill-rule="evenodd" fill="#ffff80"/>
<path d="M111.6 43h2.8l1 1-1 1h-2.8z" fill="none" stroke="#800000" stroke-width=".21"/>
<path d="M111.6 40.4h2.8l1 1-1 1.1h-2.8z" fill-rule="evenodd" fill="#ffff80"/>
<path d="M111.6 40.4h2.8l1 1-1 1.1h-2.8z" fill="none" stroke="#800000" stroke-width=".21"/>
<path d="M111.6 35.3h2.8l1 1.1-1 1h-2.8z" fill-rule="evenodd" fill="#ffff80"/>
<path d="M111.6 35.3h2.8l1 1.1-1 1h-2.8z" fill="none" stroke="#800000" stroke-width=".21"/>
<path d="M111.6 32.8h2.8l1 1-1 1h-2.8z" fill-rule="evenodd" fill="#ffff80"/>
<path d="M111.6 32.8h2.8l1 1-1 1h-2.8z" fill="none" stroke="#800000" stroke-width=".21"/>
<path d="M112.6 55.7h2.8v2h-2.8l-1-1z" fill-rule="evenodd" fill="#ffff80"/>
<path d="M112.6 55.7h2.8v2h-2.8l-1-1z" fill="none" stroke="#800000" stroke-width=".21"/>
<path d="M111.6 27.7h2.8l1 1-1 1h-2.8z" fill-rule="evenodd" fill="#ffff80"/>
<path d="M111.6 27.7h2.8l1 1-1 1h-2.8z" fill="none" stroke="#800000" stroke-width=".21"/>
<path d="M111.6 25.2h2.8l1 1-1 1h-2.8z" fill-rule="evenodd" fill="#ffff80"/>
<path d="M111.6 25.2h2.8l1 1-1 1h-2.8z" fill="none" stroke="#800000" stroke-width=".21"/>
<path d="M143.4 112.7l1-1h2.8v2h-2.8z" fill-rule="evenodd" fill="#ffff80"/>
<path d="M143.4 112.7l1-1h2.8v2h-2.8z" fill="none" stroke="#800000" stroke-width=".21"/>
<path d="M143.4 115.2l1-1h2.8v2h-2.8z" fill-rule="evenodd" fill="#ffff80"/>
<path d="M143.4 115.2l1-1h2.8v2h-2.8z" fill="none" stroke="#800000" stroke-width=".21"/>
<path d="M144.4 116.7h2.8v2.1h-2.8l-1-1z" fill-rule="evenodd" fill="#ffff80"/>
<path d="M144.4 116.7h2.8v2.1h-2.8l-1-1z" fill="none" stroke="#800000" stroke-width=".21"/>
<path d="M143.4 27.7h2.8l1 1-1 1h-2.8z" fill-rule="evenodd" fill="#ffff80"/>
<path d="M143.4 27.7h2.8l1 1-1 1h-2.8z" fill="none" stroke="#800000" stroke-width=".21"/>
<path d="M143.4 25.2h2.8l1 1-1 1h-2.8z" fill-rule="evenodd" fill="#ffff80"/>
<path d="M143.4 25.2h2.8l1 1-1 1h-2.8z" fill="none" stroke="#800000" stroke-width=".21"/>
<path d="M143.4 32.8h2.8l1 1-1 1h-2.8z" fill-rule="evenodd" fill="#ffff80"/>
<path d="M143.4 32.8h2.8l1 1-1 1h-2.8z" fill="none" stroke="#800000" stroke-width=".21"/>
<path d="M143.4 35.3h2.8l1 1.1-1 1h-2.8z" fill-rule="evenodd" fill="#ffff80"/>
<path d="M143.4 35.3h2.8l1 1.1-1 1h-2.8z" fill="none" stroke="#800000" stroke-width=".21"/>
<path d="M143.4 40.4h2.8l1 1-1 1.1h-2.8z" fill-rule="evenodd" fill="#ffff80"/>
<path d="M143.4 40.4h2.8l1 1-1 1.1h-2.8z" fill="none" stroke="#800000" stroke-width=".21"/>
<path d="M143.4 43h2.8l1 1-1 1h-2.8z" fill-rule="evenodd" fill="#ffff80"/>
<path d="M143.4 43h2.8l1 1-1 1h-2.8z" fill="none" stroke="#800000" stroke-width=".21"/>
<path d="M143.4 50.6h2.8l1 1-1 1h-2.8z" fill-rule="evenodd" fill="#ffff80"/>
<path d="M143.4 50.6h2.8l1 1-1 1h-2.8z" fill="none" stroke="#800000" stroke-width=".21"/>
<path d="M143.4 48.1h2.8l1 1-1 1h-2.8z" fill-rule="evenodd" fill="#ffff80"/>
<path d="M143.4 48.1h2.8l1 1-1 1h-2.8z" fill="none" stroke="#800000" stroke-width=".21"/>
<path d="M143.4 55.7h2.8l1 1-1 1h-2.8z" fill-rule="evenodd" fill="#ffff80"/>
<path d="M143.4 55.7h2.8l1 1-1 1h-2.8z" fill="none" stroke="#800000" stroke-width=".21"/>
<path d="M143.4 58.2h2.8l1 1.1-1 1h-2.8z" fill-rule="evenodd" fill="#ffff80"/>
<path d="M143.4 58.2h2.8l1 1.1-1 1h-2.8z" fill="none" stroke="#800000" stroke-width=".21"/>
<path d="M143.4 65.9h2.8l1 1-1 1h-2.8z" fill-rule="evenodd" fill="#ffff80"/>
<path d="M143.4 65.9h2.8l1 1-1 1h-2.8z" fill="none" stroke="#800000" stroke-width=".21"/>
<path d="M143.4 63.3h2.8l1 1-1 1.1h-2.8z" fill-rule="evenodd" fill="#ffff80"/>
<path d="M143.4 63.3h2.8l1 1-1 1.1h-2.8z" fill="none" stroke="#800000" stroke-width=".21"/>
<path d="M143.4 71h2.8l1 1-1 1h-2.8z" fill-rule="evenodd" fill="#ffff80"/>
<path d="M143.4 71h2.8l1 1-1 1h-2.8z" fill="none" stroke="#800000" stroke-width=".21"/>
<path d="M143.4 73.5h2.8l1 1-1 1h-2.8z" fill-rule="evenodd" fill="#ffff80"/>
<path d="M143.4 73.5h2.8l1 1-1 1h-2.8z" fill="none" stroke="#800000" stroke-width=".21"/>
<path d="M143.4 78.6h2.8l1 1-1 1h-2.8z" fill-rule="evenodd" fill="#ffff80"/>
<path d="M143.4 78.6h2.8l1 1-1 1h-2.8z" fill="none" stroke="#800000" stroke-width=".21"/>
<path d="M143.4 81.1h2.8l1 1-1 1.1h-2.8z" fill-rule="evenodd" fill="#ffff80"/>
<path d="M143.4 81.1h2.8l1 1-1 1.1h-2.8z" fill="none" stroke="#800000" stroke-width=".21"/>
<path d="M143.4 86.2h2.8l1 1-1 1.1h-2.8z" fill-rule="evenodd" fill="#ffff80"/>
<path d="M143.4 86.2h2.8l1 1-1 1.1h-2.8z" fill="none" stroke="#800000" stroke-width=".21"/>
<path d="M143.4 88.8h2.8l1 1-1 1h-2.8z" fill-rule="evenodd" fill="#ffff80"/>
<path d="M143.4 88.8h2.8l1 1-1 1h-2.8z" fill="none" stroke="#800000" stroke-width=".21"/>
<path d="M143.4 93.9h2.8l1 1-1 1h-2.8z" fill-rule="evenodd" fill="#ffff80"/>
<path d="M143.4 93.9h2.8l1 1-1 1h-2.8z" fill="none" stroke="#800000" stroke-width=".21"/>
<path d="M143.4 96.4h2.8l1 1-1 1h-2.8z" fill-rule="evenodd" fill="#ffff80"/>
<path d="M143.4 96.4h2.8l1 1-1 1h-2.8z" fill="none" stroke="#800000" stroke-width=".21"/>
<path d="M144.4 106.6h2.8v2h-2.8l-1-1z" fill-rule="evenodd" fill="#ffff80"/>
<path d="M144.4 106.6h2.8v2h-2.8l-1-1z" fill="none" stroke="#800000" stroke-width=".21"/>
<path d="M143.4 125.4l1-1h2.8v2h-2.8z" fill-rule="evenodd" fill="#ffff80"/>
<path d="M143.4 125.4l1-1h2.8v2h-2.8z" fill="none" stroke="#800000" stroke-width=".21"/>
<path d="M143.4 122.9l1-1.1h2.8v2.1h-2.8z" fill-rule="evenodd" fill="#ffff80"/>
<path d="M143.4 122.9l1-1.1h2.8v2.1h-2.8z" fill="none" stroke="#800000" stroke-width=".21"/>
<path d="M112.6 63.3h1.8l1 1-1 1.1h-1.8l-1-1.1z" fill-rule="evenodd" fill="#ffff80"/>
<path d="M112.6 63.3h1.8l1 1-1 1.1h-1.8l-1-1.1z" fill="none" stroke="#800000" stroke-width=".21"/>
<path d="M185.4 23.6h43.2v147.6h-43.2z" fill-rule="evenodd" fill="#80ff80"/>
<path d="M185.4 23.6h43.2v147.6h-43.2z" fill="none" stroke="#800000" stroke-width=".21"/>
<path d="M185.4 25.2h2.8l1 1-1 1h-2.8z" fill-rule="evenodd" fill="#ffff80"/>
<path d="M185.4 25.2h2.8l1 1-1 1h-2.8z" fill="none" stroke="#800000" stroke-width=".21"/>
<path d="M185.4 27.7h2.8l1 1-1 1h-2.8z" fill-rule="evenodd" fill="#ffff80"/>
<path d="M185.4 27.7h2.8l1 1-1 1h-2.8z" fill="none" stroke="#800000" stroke-width=".21"/>
<path d="M185.4 32.8h2.8l1 1-1 1h-2.8z" fill-rule="evenodd" fill="#ffff80"/>
<path d="M185.4 32.8h2.8l1 1-1 1h-2.8z" fill="none" stroke="#800000" stroke-width=".21"/>
<path d="M185.4 35.3h2.8l1 1.1-1 1h-2.8z" fill-rule="evenodd" fill="#ffff80"/>
<path d="M185.4 35.3h2.8l1 1.1-1 1h-2.8z" fill="none" stroke="#800000" stroke-width=".21"/>
<path d="M185.4 40.4h2.8l1 1-1 1.1h-2.8z" fill-rule="evenodd" fill="#ffff80"/>
<path d="M185.4 40.4h2.8l1 1-1 1.1h-2.8z" fill="none" stroke="#800000" stroke-width=".21"/>
<path d="M185.4 43h2.8l1 1-1 1h-2.8z" fill-rule="evenodd" fill="#ffff80"/>
<path d="M185.4 43h2.8l1 1-1 1h-2.8z" fill="none" stroke="#800000" stroke-width=".21"/>
<path d="M185.4 48.1h2.8l1 1-1 1h-2.8z" fill-rule="evenodd" fill="#ffff80"/>
<path d="M185.4 48.1h2.8l1 1-1 1h-2.8z" fill="none" stroke="#800000" stroke-width=".21"/>
<path d="M185.4 50.6h2.8l1 1-1 1h-2.8z" fill-rule="evenodd" fill="#ffff80"/>
<path d="M185.4 50.6h2.8l1 1-1 1h-2.8z" fill="none" stroke="#800000" stroke-width=".21"/>
<path d="M185.4 55.7h2.8l1 1-1 1h-2.8z" fill-rule="evenodd" fill="#ffff80"/>
<path d="M185.4 55.7h2.8l1 1-1 1h-2.8z" fill="none" stroke="#800000" stroke-width=".21"/>
<path d="M185.4 58.2h2.8l1 1.1-1 1h-2.8z" fill-rule="evenodd" fill="#ffff80"/>
<path d="M185.4 58.2h2.8l1 1.1-1 1h-2.8z" fill="none" stroke="#800000" stroke-width=".21"/>
<path d="M185.4 63.3h2.8l1 1-1 1.1h-2.8z" fill-rule="evenodd" fill="#ffff80"/>
<path d="M185.4 63.3h2.8l1 1-1 1.1h-2.8z" fill="none" stroke="#800000" stroke-width=".21"/>
<path d="M185.4 65.9h2.8l1 1-1 1h-2.8z" fill-rule="evenodd" fill="#ffff80"/>
<path d="M185.4 65.9h2.8l1 1-1 1h-2.8z" fill="none" stroke="#800000" stroke-width=".21"/>
<path d="M185.4 71h2.8l1 1-1 1h-2.8z" fill-rule="evenodd" fill="#ffff80"/>
<path d="M185.4 71h2.8l1 1-1 1h-2.8z" fill="none" stroke="#800000" stroke-width=".21"/>
<path d="M185.4 73.5h2.8l1 1-1 1h-2.8z" fill-rule="evenodd" fill="#ffff80"/>
<path d="M185.4 73.5h2.8l1 1-1 1h-2.8z" fill="none" stroke="#800000" stroke-width=".21"/>
<path d="M185.4 78.6h2.8l1 1-1 1h-2.8z" fill-rule="evenodd" fill="#ffff80"/>
<path d="M185.4 78.6h2.8l1 1-1 1h-2.8z" fill="none" stroke="#800000" stroke-width=".21"/>
<path d="M185.4 81.1h2.8l1 1-1 1.1h-2.8z" fill-rule="evenodd" fill="#ffff80"/>
<path d="M185.4 81.1h2.8l1 1-1 1.1h-2.8z" fill="none" stroke="#800000" stroke-width=".21"/>
<path d="M185.4 86.2h2.8l1 1-1 1.1h-2.8z" fill-rule="evenodd" fill="#ffff80"/>
<path d="M185.4 86.2h2.8l1 1-1 1.1h-2.8z" fill="none" stroke="#800000" stroke-width=".21"/>
<path d="M185.4 88.8h2.8l1 1-1 1h-2.8z" fill-rule="evenodd" fill="#ffff80"/>
<path d="M185.4 88.8h2.8l1 1-1 1h-2.8z" fill="none" stroke="#800000" stroke-width=".21"/>
<path d="M185.4 93.9h2.8l1 1-1 1h-2.8z" fill-rule="evenodd" fill="#ffff80"/>
<path d="M185.4 93.9h2.8l1 1-1 1h-2.8z" fill="none" stroke="#800000" stroke-width=".21"/>
<path d="M185.4 96.4h2.8l1 1-1 1h-2.8z" fill-rule="evenodd" fill="#ffff80"/>
<path d="M185.4 96.4h2.8l1 1-1 1h-2.8z" fill="none" stroke="#800000" stroke-width=".21"/>
<path d="M186.4 104h2.8v2.1h-2.8l-1-1z" fill-rule="evenodd" fill="#ffff80"/>
<path d="M186.4 104h2.8v2.1h-2.8l-1-1z" fill="none" stroke="#800000" stroke-width=".21"/>
<path d="M186.4 106.6h2.8v2h-2.8l-1-1z" fill-rule="evenodd" fill="#ffff80"/>
<path d="M186.4 106.6h2.8v2h-2.8l-1-1z" fill="none" stroke="#800000" stroke-width=".21"/>
<path d="M186.4 111.7h2.8v2h-2.8l-1-1z" fill-rule="evenodd" fill="#ffff80"/>
<path d="M186.4 111.7h2.8v2h-2.8l-1-1z" fill="none" stroke="#800000" stroke-width=".21"/>
<path d="M186.4 121.8h2.8v2.1h-2.8l-1-1z" fill-rule="evenodd" fill="#ffff80"/>
<path d="M186.4 121.8h2.8v2.1h-2.8l-1-1z" fill="none" stroke="#800000" stroke-width=".21"/>
<path d="M186.4 124.4h2.8v2h-2.8l-1-1z" fill-rule="evenodd" fill="#ffff80"/>
<path d="M186.4 124.4h2.8v2h-2.8l-1-1z" fill="none" stroke="#800000" stroke-width=".21"/>
<path d="M186.4 139.6h2.8v2.1h-2.8l-1-1z" fill-rule="evenodd" fill="#ffff80"/>
<path d="M186.4 139.6h2.8v2.1h-2.8l-1-1z" fill="none" stroke="#800000" stroke-width=".21"/>
<path d="M185.4 148.3l1-1h2.8v2h-2.8z" fill-rule="evenodd" fill="#ffff80"/>
<path d="M185.4 148.3l1-1h2.8v2h-2.8z" fill="none" stroke="#800000" stroke-width=".21"/>
<path d="M186.4 149.8h2.8v2.1h-2.8l-1-1.1z" fill-rule="evenodd" fill="#ffff80"/>
<path d="M186.4 149.8h2.8v2.1h-2.8l-1-1.1z" fill="none" stroke="#800000" stroke-width=".21"/>
<path d="M186.4 154.9h2.8v2h-2.8l-1-1z" fill-rule="evenodd" fill="#ffff80"/>
<path d="M186.4 154.9h2.8v2h-2.8l-1-1z" fill="none" stroke="#800000" stroke-width=".21"/>
<path d="M186.4 157.5h2.8v2h-2.8l-1-1z" fill-rule="evenodd" fill="#ffff80"/>
<path d="M186.4 157.5h2.8v2h-2.8l-1-1z" fill="none" stroke="#800000" stroke-width=".21"/>
<path d="M186.4 160h2.8v2h-2.8l-1-1z" fill-rule="evenodd" fill="#ffff80"/>
<path d="M186.4 160h2.8v2h-2.8l-1-1z" fill="none" stroke="#800000" stroke-width=".21"/>
<path d="M185.4 166.1l1-1h2.8v2h-2.8z" fill-rule="evenodd" fill="#ffff80"/>
<path d="M185.4 166.1l1-1h2.8v2h-2.8z" fill="none" stroke="#800000" stroke-width=".21"/>
<path d="M224.8 107.6l1-1h2.8v2h-2.8z" fill-rule="evenodd" fill="#ffff80"/>
<path d="M224.8 107.6l1-1h2.8v2h-2.8z" fill="none" stroke="#800000" stroke-width=".21"/>
<path d="M224.8 115.2l1-1h2.8v2h-2.8z" fill-rule="evenodd" fill="#ffff80"/>
<path d="M224.8 115.2l1-1h2.8v2h-2.8z" fill="none" stroke="#800000" stroke-width=".21"/>
<path d="M224.8 105.1l1-1.1h2.8v2.1h-2.8z" fill-rule="evenodd" fill="#ffff80"/>
<path d="M224.8 105.1l1-1.1h2.8v2.1h-2.8z" fill="none" stroke="#800000" stroke-width=".21"/>
<path d="M224.9 90l1.1-1h1.7l1 1-1 1.1h-1.7z" fill-rule="evenodd" fill="#bac0ca"/>
<path d="M224.9 90l1.1-1h1.7l1 1-1 1.1h-1.7z" fill="none" stroke="#a6acb6" stroke-width=".21"/>
<path d="M224.8 89.8l1-1h1.8l1 1-1 1h-1.8z" fill-rule="evenodd" fill="#d5e4ff"/>
<path d="M224.8 89.8l1-1h1.8l1 1-1 1h-1.8z" fill="none" stroke="#71809b" stroke-width=".21"/>
<path d="M224.9 97.7l1.1-1.1h1.7l1 1.1-1 1h-1.7z" fill-rule="evenodd" fill="#bac0ca"/>
<path d="M224.9 97.7l1.1-1.1h1.7l1 1.1-1 1h-1.7z" fill="none" stroke="#a6acb6" stroke-width=".21"/>
<path d="M224.8 97.4l1-1h1.8l1 1-1 1h-1.8z" fill-rule="evenodd" fill="#d5e4ff"/>
<path d="M224.8 97.4l1-1h1.8l1 1-1 1h-1.8z" fill="none" stroke="#71809b" stroke-width=".21"/>
<path d="M224.8 150.8l1-1h2.8v2.1h-2.8z" fill-rule="evenodd" fill="#ffff80"/>
<path d="M224.8 150.8l1-1h2.8v2.1h-2.8z" fill="none" stroke="#800000" stroke-width=".21"/>
<path d="M224.8 158.5l1-1h2.8v2h-2.8z" fill-rule="evenodd" fill="#ffff80"/>
<path d="M224.8 158.5l1-1h2.8v2h-2.8z" fill="none" stroke="#800000" stroke-width=".21"/>
<path d="M224.8 148.3l1-1h2.8v2h-2.8z" fill-rule="evenodd" fill="#ffff80"/>
<path d="M224.8 148.3l1-1h2.8v2h-2.8z" fill="none" stroke="#800000" stroke-width=".21"/>
<path d="M224.9 133.3l1.1-1h1.7l1 1-1 1h-1.7z" fill-rule="evenodd" fill="#bac0ca"/>
<path d="M224.9 133.3l1.1-1h1.7l1 1-1 1h-1.7z" fill="none" stroke="#a6acb6" stroke-width=".21"/>
<path d="M224.8 133l1-1h1.8l1 1-1 1h-1.8z" fill-rule="evenodd" fill="#d5e4ff"/>
<path d="M224.8 133l1-1h1.8l1 1-1 1h-1.8z" fill="none" stroke="#71809b" stroke-width=".21"/>
<path d="M224.9 140.9l1.1-1h1.7l1 1-1 1h-1.7z" fill-rule="evenodd" fill="#bac0ca"/>
<path d="M224.9 140.9l1.1-1h1.7l1 1-1 1h-1.7z" fill="none" stroke="#a6acb6" stroke-width=".21"/>
<path d="M224.8 140.7l1-1.1h1.8l1 1.1-1 1h-1.8z" fill-rule="evenodd" fill="#d5e4ff"/>
<path d="M224.8 140.7l1-1.1h1.8l1 1.1-1 1h-1.8z" fill="none" stroke="#71809b" stroke-width=".21"/>
<path d="M186.4 144.7h2.8v2.1h-2.8l-1-1z" fill-rule="evenodd" fill="#ffff80"/>
<path d="M186.4 144.7h2.8v2.1h-2.8l-1-1z" fill="none" stroke="#800000" stroke-width=".21"/>
<path d="M224.8 163.6l1-1.1h1.8l1 1.1-1 1h-1.8z" fill-rule="evenodd" fill="#ffff80"/>
<path d="M224.8 163.6l1-1.1h1.8l1 1.1-1 1h-1.8z" fill="none" stroke="#800000" stroke-width=".21"/>
<path d="M224.8 166.1l1-1h1.8l1 1-1 1h-1.8z" fill-rule="evenodd" fill="#ffff80"/>
<path d="M224.8 166.1l1-1h1.8l1 1-1 1h-1.8z" fill="none" stroke="#800000" stroke-width=".21"/>
<path d="M186.4 134.6h1.8l1 1-1 1h-1.8l-1-1z" fill-rule="evenodd" fill="#ffff80"/>
<path d="M186.4 134.6h1.8l1 1-1 1h-1.8l-1-1z" fill="none" stroke="#800000" stroke-width=".21"/>
<path d="M25.1 166.1h5.1M25.9 166.9h3.5M26.6 167.6h2.1M27.4 168.4h.5M27.6 163.6v2.5" fill="none" stroke="#800000" stroke-width=".25"/>
<path d="M12.4 153.4h5.1v7.6h-5.1z" fill-rule="evenodd" fill="#ffffb0"/>
<path d="M12.4 153.4h5.1v7.6h-5.1z" fill="none" stroke="#800000" stroke-width=".21"/>
<path d="M17.5 158.5h7.6M17.5 155.9h7.6" fill="none" stroke="#000" stroke-width=".25"/>
<g fill="none" stroke="#d0a19e" stroke-width=".25">
<path d="M164 24.5h1l.5-.5h1l.6 .5h1M164 25.2h1l.5 .5h1l.6-.5h1M164 27.1h1l.5-.5h1l.6 .5h1M164 27.7h1l.5 .5h1l.6-.5h1M164 32.2h1l.5-.6h1l.6 .6h1M164 32.8h1l.5 .5h1l.6-.5h1M164 34.7h1l.5-.5h1l.6 .5h1M164 35.3h1l.5 .6h1l.6-.6h1M164 39.8h1l.5-.5h1l.6 .5h1M164 40.4h1l.5 .5h1l.6-.5h1M164 42.3h1l.5-.5h1l.6 .5h1M164 43h1l.5 .5h1l.6-.5h1"/>
<path d="M164 47.4h1l.5-.5h1l.6 .5h1M164 48.1h1l.5 .5h1l.6-.5h1M164 50h1l.5-.5h1l.6 .5h1M164 50.6h1l.5 .5h1l.6-.5h1M164 55.1h1l.5-.6h1l.6 .6h1M164 55.7h1l.5 .5h1l.6-.5h1M164 57.6h1l.5-.5h1l.6 .5h1M164 58.2h1l.5 .5h1l.6-.5h1M164 70.3h1l.5-.5h1l.6 .5h1M164 71h1l.5 .5h1l.6-.5h1M164 72.9h1l.5-.5h1l.6 .5h1M164 73.5h1l.5 .5h1l.6-.5h1"/>
<path d="M164 78h1l.5-.6h1l.6 .6h1M164 78.6h1l.5 .5h1l.6-.5h1M164 62.7h1l.5-.5h1l.6 .5h1M164 63.3h1l.5 .5h1l.6-.5h1M164 65.2h1l.5-.5h1l.6 .5h1M164 65.9h1l.5 .5h1l.6-.5h1M164 80.5h1l.5-.5h1l.6 .5h1M164 81.1h1l.5 .5h1l.6-.5h1M164 85.6h1l.5-.5h1l.6 .5h1M164 86.2h1l.5 .5h1l.6-.5h1M164 88.1h1l.5-.5h1l.6 .5h1M164 88.8h1l.5 .5h1l.6-.5h1"/>
<path d="M164 93.2h1l.5-.5h1l.6 .5h1M164 93.9h1l.5 .5h1l.6-.5h1M164 95.8h1l.5-.6h1l.6 .6h1M164 96.4h1l.5 .5h1l.6-.5h1"/>
</g>
<g fill="none" stroke="#d0a19e" stroke-width=".21">
<path d="M164 25.2l-1.5 1M164 27.7l-1.5 1M164 32.8l-1.5 1M164 35.3l-1.5 1.1M164 40.4l-1.5 1M164 43l-1.5 1M164 48.1l-1.5 1M164 50.6l-1.5 1M164 55.7l-1.5 1M164 58.2l-1.5 1.1M164 71l-1.5 1M164 73.5l-1.5 1"/>
<path d="M164 78.6l-1.5 1M164 63.3l-1.5 1M164 65.9l-1.5 1M164 81.1l-1.5 1M164 86.2l-1.5 1M164 88.8l-1.5 1M164 93.9l-1.5 1M164 96.4l-1.5 1"/>
</g>
<g fill="none" stroke="#f00" stroke-width=".25">
<path d="M163.7 24.3h1.1l.5-.5h1l.5 .5h1M163.7 24.9h1.1l.5 .5h1l.5-.5h1M163.7 26.8h1.1l.5-.5h1l.5 .5h1M163.7 27.5h1.1l.5 .5h1l.5-.5h1M163.7 31.9h1.1l.5-.5h1l.5 .5h1M163.7 32.5h1.1l.5 .6h1l.5-.6h1M163.7 34.4h1.1l.5-.5h1l.5 .5h1M163.7 35.1h1.1l.5 .5h1l.5-.5h1M163.7 39.5h1.1l.5-.5h1l.5 .5h1M163.7 40.2h1.1l.5 .5h1l.5-.5h1M163.7 42.1h1.1l.5-.5h1l.5 .5h1M163.7 42.7h1.1l.5 .5h1l.5-.5h1"/>
<path d="M163.7 47.2h1.1l.5-.5h1l.5 .5h1M163.7 47.8h1.1l.5 .5h1l.5-.5h1M163.7 49.7h1.1l.5-.5h1l.5 .5h1M163.7 50.4h1.1l.5 .5h1l.5-.5h1M163.7 54.8h1.1l.5-.5h1l.5 .5h1M163.7 55.4h1.1l.5 .5h1l.5-.5h1M163.7 57.3h1.1l.5-.5h1l.5 .5h1M163.7 58h1.1l.5 .5h1l.5-.5h1M163.7 70.1h1.1l.5-.5h1l.5 .5h1M163.7 70.7h1.1l.5 .5h1l.5-.5h1M163.7 72.6h1.1l.5-.5h1l.5 .5h1M163.7 73.2h1.1l.5 .6h1l.5-.6h1"/>
<path d="M163.7 77.7h1.1l.5-.5h1l.5 .5h1M163.7 78.3h1.1l.5 .5h1l.5-.5h1M163.7 62.4h1.1l.5-.5h1l.5 .5h1M163.7 63.1h1.1l.5 .5h1l.5-.5h1M163.7 65h1.1l.5-.5h1l.5 .5h1M163.7 65.6h1.1l.5 .5h1l.5-.5h1M163.7 80.2h1.1l.5-.5h1l.5 .5h1M163.7 80.9h1.1l.5 .5h1l.5-.5h1M163.7 85.3h1.1l.5-.5h1l.5 .5h1M163.7 86h1.1l.5 .5h1l.5-.5h1M163.7 87.9h1.1l.5-.5h1l.5 .5h1M163.7 88.5h1.1l.5 .5h1l.5-.5h1"/>
<path d="M163.7 93h1.1l.5-.5h1l.5 .5h1M163.7 93.6h1.1l.5 .5h1l.5-.5h1M163.7 95.5h1.1l.5-.5h1l.5 .5h1M163.7 96.1h1.1l.5 .6h1l.5-.6h1"/>
</g>
<g fill="none" stroke="#f00" stroke-width=".21">
<path d="M163.7 24.9l-1.2 1.3M163.7 27.5l-1.2 1.2M163.7 32.5l-1.2 1.3M163.7 35.1l-1.2 1.3M163.7 40.2l-1.2 1.2M163.7 42.7l-1.2 1.3M163.7 47.8l-1.2 1.3M163.7 50.4l-1.2 1.2M163.7 55.4l-1.2 1.3M163.7 58l-1.2 1.3M163.7 70.7l-1.2 1.3M163.7 73.2l-1.2 1.3"/>
<path d="M163.7 78.3l-1.2 1.3M163.7 63.1l-1.2 1.2M163.7 65.6l-1.2 1.3M163.7 80.9l-1.2 1.2M163.7 86l-1.2 1.2M163.7 88.5l-1.2 1.3M163.7 93.6l-1.2 1.3M163.7 96.1l-1.2 1.3"/>
</g>
<path d="M50.5 148.3h15.3v15.3h-15.3z" fill-rule="evenodd" fill="#ffffb0"/>
<path d="M50.5 148.3h15.3v15.3h-15.3z" fill="none" stroke="#800000" stroke-width=".21"/>
<g fill="none" stroke="#000" stroke-width=".25">
<path d="M269.3 56.7h5.1M274.4 59.3v2.5M165 105h2.6M27.6 155.9h2M35.8 155.9h2M42.9 155.9h7.6M65.8 155.9h7.6M65.8 150.8h7.6M91.2 158.5v2M42.9 161h7.6M65.8 161h7.6M91.2 166.6v2"/>
<path d="M177.7 181.4h5.1v2.5h-5.1zM180.3 183.9v2.6M185.4 181.4h5.1v2.5h-5.1zM187.9 183.9v2.6"/>
<circle cx="163.7" cy="105" r="1.27"/>
</g>
<g fill="none" stroke="#800000" stroke-width=".25">
<path d="M84.9 145.7h2.5M86.2 145.7v2.6M73.4 171.2h5.1M74.2 172h3.6M75 172.7h2M75.7 173.5h.5M76 168.6v2.6M81.1 171.2h5.1M81.8 172h3.6M82.6 172.7h2M83.4 173.5h.5M83.6 168.6v2.6"/>
<path d="M88.7 171.2h5.1M89.5 172h3.5M90.2 172.7h2.1M91 173.5h.5M91.2 168.6v2.6M177.7 189h5.1M178.5 189.8h3.6M179.3 190.5h2M180 191.3h.5M180.3 186.5v2.5M185.4 189h5.1M186.1 189.8h3.6"/>
<path d="M186.9 190.5h2M187.7 191.3h.5M187.9 186.5v2.5"/>
</g>
<path d="M51.8 24.9l-1.3 1.3M51.8 27.5l-1.3 1.2M51.8 32.5l-1.3 1.3M51.8 35.1l-1.3 1.3M51.8 40.2l-1.3 1.2M51.8 42.7l-1.3 1.3M51.8 47.8l-1.3 1.3M51.8 50.3l-1.3 1.3M41.9 160l2 2M43.9 160l-2 2" fill="none" stroke="#f00" stroke-width=".21"/>
<g fill="none" stroke="#00f" stroke-width=".25">
<path d="M29.7 154.9h6v2.1h-6zM90.3 160.6h2v6h-2z"/>
<circle cx="274.4" cy="56.7" r="2.54"/>
</g>
<g fill="none" stroke="#d0a19e" stroke-width=".25">
<path d="M52.1 24.5h1l.5-.5h1l.5 .5h1M52.1 25.2h1l.5 .5h1l.5-.5h1M52.1 27.1h1l.5-.5h1l.5 .5h1M52.1 27.7h1l.5 .5h1l.5-.5h1M52.1 32.2h1l.5-.6h1l.5 .6h1M52.1 32.8h1l.5 .5h1l.5-.5h1M52.1 34.7h1l.5-.5h1l.5 .5h1M52.1 35.3h1l.5 .5h1l.5-.5h1M52.1 39.8h1l.5-.5h1l.5 .5h1M52.1 40.4h1l.5 .5h1l.5-.5h1M52.1 42.3h1l.5-.5h1l.5 .5h1M52.1 43h1l.5 .5h1l.5-.5h1"/>
<path d="M52.1 47.4h1l.5-.5h1l.5 .5h1M52.1 48.1h1l.5 .5h1l.5-.5h1M52.1 50h1l.5-.5h1l.5 .5h1M52.1 50.6h1l.5 .5h1l.5-.5h1"/>
</g>
<path d="M52.1 25.2l-1.6 1M52.1 27.7l-1.6 1M52.1 32.8l-1.6 1M52.1 35.3l-1.6 1.1M52.1 40.4l-1.6 1M52.1 43l-1.6 1M52.1 48.1l-1.6 1M52.1 50.6l-1.6 1" fill="none" stroke="#d0a19e" stroke-width=".21"/>
<g fill="none" stroke="#f00" stroke-width=".25">
<path d="M51.8 24.3h1l.5-.5h1.1l.5 .5h1M51.8 24.9h1l.5 .5h1.1l.5-.5h1M51.8 26.8h1l.5-.5h1.1l.5 .5h1M51.8 27.5h1l.5 .5h1.1l.5-.5h1M51.8 31.9h1l.5-.5h1.1l.5 .5h1M51.8 32.5h1l.5 .5h1.1l.5-.5h1M51.8 34.4h1l.5-.5h1.1l.5 .5h1M51.8 35.1h1l.5 .5h1.1l.5-.5h1M51.8 39.5h1l.5-.5h1.1l.5 .5h1M51.8 40.2h1l.5 .5h1.1l.5-.5h1M51.8 42.1h1l.5-.5h1.1l.5 .5h1M51.8 42.7h1l.5 .5h1.1l.5-.5h1"/>
<path d="M51.8 47.2h1l.5-.5h1.1l.5 .5h1M51.8 47.8h1l.5 .5h1.1l.5-.5h1M51.8 49.7h1l.5-.5h1.1l.5 .5h1M51.8 50.3h1l.5 .6h1.1l.5-.6h1"/>
</g>
<circle cx="274.4" cy="56.7" r=".64" fill="#00f"/>
<circle cx="274.4" cy="56.7" r=".64" fill="none" stroke="#00f" stroke-width=".21"/>
<path d="M271.9 64.3h5.1M272.6 65.1h3.6M273.4 65.9h2M274.2 66.6h.5M274.4 61.8v2.5" fill="none" stroke="#800000" stroke-width=".25"/>
<circle cx="266.8" cy="56.7" r=".51" fill="#000080"/>
<circle cx="266.8" cy="56.7" r=".51" fill="none" stroke="#000080" stroke-width=".21"/>
<path d="M266.8 56.7v4.5M266.8 67.5v4.5" fill="none" stroke="#000" stroke-width=".25"/>
<circle cx="266.8" cy="56.7" r=".51" fill="#000080"/>
<circle cx="266.8" cy="56.7" r=".51" fill="none" stroke="#000080" stroke-width=".21"/>
<path d="M266.8 64.3l1.9 3.2h-3.8z" fill="#00f"/>
<path d="M265.5 64.3h2.6M266.8 64.3l1.9 3.2h-3.8z" fill="none" stroke="#00f" stroke-width=".25"/>
<path d="M264.9 61.2h3.8l-1.9 3.1z" fill="#00f"/>
<g fill="none" stroke="#00f" stroke-width=".25">
<path d="M264.9 61.2h3.8l-1.9 3.1zM265.5 64.3l-1.3 1.3M269.3 63.1l-1.2 1.2"/>
<circle cx="251.5" cy="56.7" r="2.54"/>
</g>
<path d="M264.2 74.5h5.1M265 75.3h3.6M265.8 76h2M266.5 76.8h.5M266.8 72v2.5" fill="none" stroke="#800000" stroke-width=".25"/>
<path d="M246.4 56.7h5.1M251.5 59.3v2.5" fill="none" stroke="#000" stroke-width=".25"/>
<circle cx="251.5" cy="56.7" r=".64" fill="#00f"/>
<circle cx="251.5" cy="56.7" r=".64" fill="none" stroke="#00f" stroke-width=".21"/>
<path d="M249 64.3h5.1M249.7 65.1h3.6M250.5 65.9h2M251.3 66.6h.5M251.5 61.8v2.5" fill="none" stroke="#800000" stroke-width=".25"/>
<circle cx="243.9" cy="56.7" r=".51" fill="#000080"/>
<circle cx="243.9" cy="56.7" r=".51" fill="none" stroke="#000080" stroke-width=".21"/>
<path d="M243.9 56.7v4.5M243.9 67.5v4.5" fill="none" stroke="#000" stroke-width=".25"/>
<circle cx="243.9" cy="56.7" r=".51" fill="#000080"/>
<circle cx="243.9" cy="56.7" r=".51" fill="none" stroke="#000080" stroke-width=".21"/>
<path d="M243.9 64.3l1.9 3.2h-3.8z" fill="#00f"/>
<path d="M242.6 64.3h2.6M243.9 64.3l1.9 3.2h-3.8z" fill="none" stroke="#00f" stroke-width=".25"/>
<path d="M242 61.2h3.8l-1.9 3.1z" fill="#00f"/>
<path d="M242 61.2h3.8l-1.9 3.1zM242.6 64.3l-1.3 1.3M246.4 63.1l-1.2 1.2" fill="none" stroke="#00f" stroke-width=".25"/>
<path d="M241.3 74.5h5.1M242.1 75.3h3.6M242.9 76h2M243.6 76.8h.5M243.9 72v2.5" fill="none" stroke="#800000" stroke-width=".25"/>
<path d="M274.4 92.3h5.1v20.4h-5.1z" fill-rule="evenodd" fill="#ffffb0"/>
<path d="M274.4 92.3h5.1v20.4h-5.1z" fill="none" stroke="#800000" stroke-width=".21"/>
<g fill="none" stroke="#00f" stroke-width=".25">
<path d="M85.7 63.4h6v2h-6zM85.7 68.5h6v2h-6zM123.9 134.6h6v2h-6zM123.9 139.7h6v2h-6zM81.6 163.1h4M81.6 164.1h4M83.6 161v2.1M83.6 164.1v2"/>
<circle cx="277" cy="94.9" r="1.27"/>
<circle cx="277" cy="100" r="1.27"/>
<circle cx="277" cy="100" r="1.26"/>
<circle cx="277" cy="105" r="1.27"/>
<circle cx="277" cy="110.1" r="1.27"/>
</g>
<path d="M83.6 64.3h2M83.6 69.4h2M91.8 64.3h2M91.8 69.4h2M121.8 135.6h2M129.9 135.6h2M83.6 158.5v2.5M121.8 140.7h2M129.9 140.7h2M83.6 166.1v2.5" fill="none" stroke="#000" stroke-width=".25"/>
<circle cx="282" cy="21.1" r=".51" fill="#000080"/>
<circle cx="282" cy="21.1" r=".51" fill="none" stroke="#000080" stroke-width=".21"/>
<circle cx="282" cy="23.6" r=".51" fill="#000080"/>
<circle cx="282" cy="23.6" r=".51" fill="none" stroke="#000080" stroke-width=".21"/>
<circle cx="282" cy="26.2" r=".51" fill="#000080"/>
<circle cx="282" cy="26.2" r=".51" fill="none" stroke="#000080" stroke-width=".21"/>
<circle cx="282" cy="28.7" r=".51" fill="#000080"/>
<circle cx="282" cy="28.7" r=".51" fill="none" stroke="#000080" stroke-width=".21"/>
<path d="M264.2 16h10.2v15.3h-10.2z" fill-rule="evenodd" fill="#ffffb0"/>
<path d="M264.2 16h10.2v15.3h-10.2z" fill="none" stroke="#800000" stroke-width=".21"/>
<path d="M256.6 18.6h7.6M274.4 18.6h7.6M256.6 21.1h7.6M274.4 21.1h7.6" fill="none" stroke="#000" stroke-width=".25"/>
<circle cx="282" cy="21.1" r=".51" fill="#000080"/>
<circle cx="282" cy="21.1" r=".51" fill="none" stroke="#000080" stroke-width=".21"/>
<path d="M256.6 23.6h7.6M274.4 23.6h7.6" fill="none" stroke="#000" stroke-width=".25"/>
<circle cx="282" cy="23.6" r=".51" fill="#000080"/>
<circle cx="282" cy="23.6" r=".51" fill="none" stroke="#000080" stroke-width=".21"/>
<path d="M256.6 26.2h7.6M274.4 26.2h7.6" fill="none" stroke="#000" stroke-width=".25"/>
<circle cx="282" cy="26.2" r=".51" fill="#000080"/>
<circle cx="282" cy="26.2" r=".51" fill="none" stroke="#000080" stroke-width=".21"/>
<path d="M256.6 28.7h7.6M274.4 28.7h7.6" fill="none" stroke="#000" stroke-width=".25"/>
<circle cx="282" cy="28.7" r=".51" fill="#000080"/>
<circle cx="282" cy="28.7" r=".51" fill="none" stroke="#000080" stroke-width=".21"/>
<path d="M251.5 33.8h5.1M252.3 34.6h3.5M253 35.3h2.1M253.8 36.1h.5M254.1 31.3v2.5M279.5 33.8h5.1M280.3 34.6h3.5M281 35.3h2.1M281.8 36.1h.5M282 31.3v2.5" fill="none" stroke="#800000" stroke-width=".25"/>
<g fill="none" stroke="#000" stroke-width=".25">
<path d="M246.4 28.7v4.5M246.4 39.5v4.5M165 140.7h2.6"/>
<circle cx="163.7" cy="140.7" r="1.27"/>
</g>
<path d="M246.4 36.4l1.9 3.1h-3.8z" fill="#00f"/>
<path d="M245.2 36.4h2.5M246.4 36.4l1.9 3.1h-3.8z" fill="none" stroke="#00f" stroke-width=".25"/>
<path d="M244.5 33.2h3.8l-1.9 3.2z" fill="#00f"/>
<path d="M244.5 33.2h3.8l-1.9 3.2zM245.2 36.4l-1.3 1.2M249 35.1l-1.3 1.3" fill="none" stroke="#00f" stroke-width=".25"/>
<path d="M243.9 46.5h5.1M244.6 47.3h3.6M245.4 48.1h2M246.2 48.8h.5M246.4 44v2.5" fill="none" stroke="#800000" stroke-width=".25"/>
<path d="M238.8 28.7v4.5M238.8 39.5v4.5" fill="none" stroke="#000" stroke-width=".25"/>
<path d="M238.8 36.4l1.9 3.1h-3.8z" fill="#00f"/>
<path d="M237.5 36.4h2.6M238.8 36.4l1.9 3.1h-3.8z" fill="none" stroke="#00f" stroke-width=".25"/>
<path d="M236.9 33.2h3.8l-1.9 3.2z" fill="#00f"/>
<path d="M236.9 33.2h3.8l-1.9 3.2zM237.5 36.4l-1.2 1.2M241.3 35.1l-1.2 1.3" fill="none" stroke="#00f" stroke-width=".25"/>
<path d="M236.3 46.5h5M237 47.3h3.6M237.8 48.1h2M238.5 48.8h.6M238.8 44v2.5" fill="none" stroke="#800000" stroke-width=".25"/>
<path d="M241.3 127.9h25.5v43.3h-25.5z" fill-rule="evenodd" fill="#80ff80"/>
<path d="M241.3 127.9h25.5v43.3h-25.5z" fill="none" stroke="#800000" stroke-width=".21"/>
<path d="M242.4 149.8h2.8v2.1h-2.8l-1.1-1.1z" fill-rule="evenodd" fill="#ffff80"/>
<path d="M242.4 149.8h2.8v2.1h-2.8l-1.1-1.1z" fill="none" stroke="#800000" stroke-width=".21"/>
<path d="M241.3 158.5l1.1-1h2.8v2h-2.8z" fill-rule="evenodd" fill="#ffff80"/>
<path d="M241.3 158.5l1.1-1h2.8v2h-2.8z" fill="none" stroke="#800000" stroke-width=".21"/>
<path d="M241.3 148.3l1.1-1h2.8v2h-2.8z" fill-rule="evenodd" fill="#ffff80"/>
<path d="M241.3 148.3l1.1-1h2.8v2h-2.8z" fill="none" stroke="#800000" stroke-width=".21"/>
<path d="M242.5 132.3h1.8l1 1-1 1h-1.8l-1-1z" fill-rule="evenodd" fill="#bac0ca"/>
<path d="M242.5 132.3h1.8l1 1-1 1h-1.8l-1-1z" fill="none" stroke="#a6acb6" stroke-width=".21"/>
<path d="M241.3 133l1.1-1h1.7l1.1 1-1.1 1h-1.7z" fill-rule="evenodd" fill="#d5e4ff"/>
<path d="M241.3 133l1.1-1h1.7l1.1 1-1.1 1h-1.7z" fill="none" stroke="#71809b" stroke-width=".21"/>
<path d="M242.5 139.9h1.8l1 1-1 1h-1.8l-1-1z" fill-rule="evenodd" fill="#bac0ca"/>
<path d="M242.5 139.9h1.8l1 1-1 1h-1.8l-1-1z" fill="none" stroke="#a6acb6" stroke-width=".21"/>
<path d="M241.3 140.7l1.1-1.1h1.7l1.1 1.1-1.1 1h-1.7z" fill-rule="evenodd" fill="#d5e4ff"/>
<path d="M241.3 140.7l1.1-1.1h1.7l1.1 1.1-1.1 1h-1.7z" fill="none" stroke="#71809b" stroke-width=".21"/>
<path d="M241.3 163.6l1.1-1.1h1.7l1.1 1.1-1.1 1h-1.7z" fill-rule="evenodd" fill="#ffff80"/>
<path d="M241.3 163.6l1.1-1.1h1.7l1.1 1.1-1.1 1h-1.7z" fill="none" stroke="#800000" stroke-width=".21"/>
<path d="M241.3 166.1l1.1-1h1.7l1.1 1-1.1 1h-1.7z" fill-rule="evenodd" fill="#ffff80"/>
<path d="M241.3 166.1l1.1-1h1.7l1.1 1-1.1 1h-1.7z" fill="none" stroke="#800000" stroke-width=".21"/>
<path d="M241.3 84.7h25.5v35.6h-25.5z" fill-rule="evenodd" fill="#80ff80"/>
<path d="M241.3 84.7h25.5v35.6h-25.5z" fill="none" stroke="#800000" stroke-width=".21"/>
<path d="M241.3 107.6l1.1-1h2.8v2h-2.8z" fill-rule="evenodd" fill="#ffff80"/>
<path d="M241.3 107.6l1.1-1h2.8v2h-2.8z" fill="none" stroke="#800000" stroke-width=".21"/>
<path d="M241.3 115.2l1.1-1h2.8v2h-2.8z" fill-rule="evenodd" fill="#ffff80"/>
<path d="M241.3 115.2l1.1-1h2.8v2h-2.8z" fill="none" stroke="#800000" stroke-width=".21"/>
<path d="M241.3 105.1l1.1-1.1h2.8v2.1h-2.8z" fill-rule="evenodd" fill="#ffff80"/>
<path d="M241.3 105.1l1.1-1.1h2.8v2.1h-2.8z" fill="none" stroke="#800000" stroke-width=".21"/>
<path d="M242.5 89h1.8l1 1-1 1.1h-1.8l-1-1.1z" fill-rule="evenodd" fill="#bac0ca"/>
<path d="M242.5 89h1.8l1 1-1 1.1h-1.8l-1-1.1z" fill="none" stroke="#a6acb6" stroke-width=".21"/>
<path d="M241.3 89.8l1.1-1h1.7l1.1 1-1.1 1h-1.7z" fill-rule="evenodd" fill="#d5e4ff"/>
<path d="M241.3 89.8l1.1-1h1.7l1.1 1-1.1 1h-1.7z" fill="none" stroke="#71809b" stroke-width=".21"/>
<path d="M242.5 96.6h1.8l1 1.1-1 1h-1.8l-1-1z" fill-rule="evenodd" fill="#bac0ca"/>
<path d="M242.5 96.6h1.8l1 1.1-1 1h-1.8l-1-1z" fill="none" stroke="#a6acb6" stroke-width=".21"/>
<path d="M242.4 96.4h1.7l1.1 1-1.1 1h-1.7l-1.1-1z" fill-rule="evenodd" fill="#d5e4ff"/>
<path d="M242.4 96.4h1.7l1.1 1-1.1 1h-1.7l-1.1-1z" fill="none" stroke="#71809b" stroke-width=".21"/>
<path d="M147.2 138.1v2M147.2 146.3v2" fill="none" stroke="#000" stroke-width=".25"/>
<path d="M146.2 140.2h2.1v6h-2.1z" fill="none" stroke="#00f" stroke-width=".25"/>
<path d="M145.9 150.8h2.6M147.2 148.3v2.5" fill="none" stroke="#800000" stroke-width=".25"/>
<path d="M12.4 112.7h25.4v15.2h-25.4z" fill-rule="evenodd" fill="#80ff80"/>
<path d="M12.4 112.7h25.4v15.2h-25.4z" fill="none" stroke="#800000" stroke-width=".21"/>
<path d="M34 122.9l1-1.1h2.8v2.1h-2.8z" fill-rule="evenodd" fill="#ffff80"/>
<path d="M34 122.9l1-1.1h2.8v2.1h-2.8z" fill="none" stroke="#800000" stroke-width=".21"/>
<path d="M35 116.7h2.8v2.1h-2.8l-1-1z" fill-rule="evenodd" fill="#ffff80"/>
<path d="M35 116.7h2.8v2.1h-2.8l-1-1z" fill="none" stroke="#800000" stroke-width=".21"/>
<g fill="none" stroke="#000080" stroke-width=".25">
<path d="M37.8 26.2h73.8M37.8 28.7h73.8M37.8 33.8h73.8M37.8 36.4h73.8M147.2 26.2h38.2M147.2 28.7h38.2M147.2 33.8h38.2M147.2 36.4h38.2M37.8 41.4h73.8M37.8 44h73.8M37.8 49.1h73.8M37.8 51.6h73.8"/>
<path d="M37.8 56.7h73.8M147.2 41.4h38.2M147.2 49.1h38.2M147.2 51.6h38.2M147.2 56.7h38.2M147.2 44h38.2M147.2 59.3h38.2M147.2 64.3h38.2M147.2 66.9h38.2M147.2 72h38.2M147.2 74.5h38.2M147.2 79.6h38.2"/>
<path d="M147.2 82.1h38.2M147.2 87.2h38.2M147.2 89.8h38.2M147.2 94.9h38.2M147.2 97.4h38.2M167.6 105.1h17.8M25.1 158.5h2.5v5.1M37.8 155.9h5.1M73.4 155.9h17.8v2.6M167.6 140.7h17.8M167.6 155.9h17.8M167.6 158.5h17.8"/>
<path d="M73.4 161h2.6v7.6"/>
</g>
<circle cx="91.2" cy="155.9" r=".51" fill="#000080"/>
<circle cx="91.2" cy="155.9" r=".51" fill="none" stroke="#000080" stroke-width=".21"/>
<path d="M91.2 155.9h17.9" fill="none" stroke="#000080" stroke-width=".25"/>
<circle cx="91.2" cy="155.9" r=".51" fill="#000080"/>
<circle cx="91.2" cy="155.9" r=".51" fill="none" stroke="#000080" stroke-width=".21"/>
<g fill="none" stroke="#000080" stroke-width=".25">
<path d="M259.2 56.7h10.1M37.8 72h20.4M37.8 74.5h20.4M37.8 82.1h20.4M37.8 84.7h20.4M147.2 115.2h20.4M147.2 117.8h20.4M147.2 107.6h38.2M147.2 112.7h38.2M147.2 122.9h38.2M147.2 125.4h38.2M25.1 155.9h2.5"/>
<path d="M167.6 166.1h17.8"/>
</g>
<circle cx="266.8" cy="56.7" r=".51" fill="#000080"/>
<circle cx="266.8" cy="56.7" r=".51" fill="none" stroke="#000080" stroke-width=".21"/>
<path d="M236.3 56.7h10.1" fill="none" stroke="#000080" stroke-width=".25"/>
<circle cx="243.9" cy="56.7" r=".51" fill="#000080"/>
<circle cx="243.9" cy="56.7" r=".51" fill="none" stroke="#000080" stroke-width=".21"/>
<path d="M83.6 150.8v7.7" fill="none" stroke="#000080" stroke-width=".25"/>
<circle cx="83.6" cy="150.8" r=".51" fill="#000080"/>
<circle cx="83.6" cy="150.8" r=".51" fill="none" stroke="#000080" stroke-width=".21"/>
<path d="M96.3 64.3v5.1h-2.5" fill="none" stroke="#000080" stroke-width=".25"/>
<circle cx="96.3" cy="64.3" r=".51" fill="#000080"/>
<circle cx="96.3" cy="64.3" r=".51" fill="none" stroke="#000080" stroke-width=".21"/>
<path d="M68.3 64.3h15.3M68.3 69.4h15.3M134.5 135.6v5.1h-2.6" fill="none" stroke="#000080" stroke-width=".25"/>
<circle cx="134.5" cy="135.6" r=".51" fill="#000080"/>
<circle cx="134.5" cy="135.6" r=".51" fill="none" stroke="#000080" stroke-width=".21"/>
<path d="M93.8 64.3h17.8M111.6 135.6h10.2M111.6 140.7h10.2" fill="none" stroke="#000080" stroke-width=".25"/>
<circle cx="96.3" cy="64.3" r=".51" fill="#000080"/>
<circle cx="96.3" cy="64.3" r=".51" fill="none" stroke="#000080" stroke-width=".21"/>
<path d="M282 18.6v12.7" fill="none" stroke="#000080" stroke-width=".25"/>
<circle cx="282" cy="21.1" r=".51" fill="#000080"/>
<circle cx="282" cy="21.1" r=".51" fill="none" stroke="#000080" stroke-width=".21"/>
<circle cx="282" cy="23.6" r=".51" fill="#000080"/>
<circle cx="282" cy="23.6" r=".51" fill="none" stroke="#000080" stroke-width=".21"/>
<circle cx="282" cy="26.2" r=".51" fill="#000080"/>
<circle cx="282" cy="26.2" r=".51" fill="none" stroke="#000080" stroke-width=".21"/>
<circle cx="282" cy="28.7" r=".51" fill="#000080"/>
<circle cx="282" cy="28.7" r=".51" fill="none" stroke="#000080" stroke-width=".21"/>
<path d="M236.3 26.2h10.1v2.5" fill="none" stroke="#000080" stroke-width=".25"/>
<circle cx="246.4" cy="26.2" r=".51" fill="#000080"/>
<circle cx="246.4" cy="26.2" r=".51" fill="none" stroke="#000080" stroke-width=".21"/>
<path d="M256.6 28.7h-2.5v2.6" fill="none" stroke="#000080" stroke-width=".25"/>
<circle cx="254.1" cy="28.7" r=".51" fill="#000080"/>
<circle cx="254.1" cy="28.7" r=".51" fill="none" stroke="#000080" stroke-width=".21"/>
<path d="M256.6 23.6h-2.5v5.1" fill="none" stroke="#000080" stroke-width=".25"/>
<circle cx="254.1" cy="23.6" r=".51" fill="#000080"/>
<circle cx="254.1" cy="23.6" r=".51" fill="none" stroke="#000080" stroke-width=".21"/>
<circle cx="254.1" cy="28.7" r=".51" fill="#000080"/>
<circle cx="254.1" cy="28.7" r=".51" fill="none" stroke="#000080" stroke-width=".21"/>
<path d="M256.6 18.6h-2.5v5" fill="none" stroke="#000080" stroke-width=".25"/>
<circle cx="254.1" cy="23.6" r=".51" fill="#000080"/>
<circle cx="254.1" cy="23.6" r=".51" fill="none" stroke="#000080" stroke-width=".21"/>
<path d="M246.4 26.2h10.2" fill="none" stroke="#000080" stroke-width=".25"/>
<circle cx="246.4" cy="26.2" r=".51" fill="#000080"/>
<circle cx="246.4" cy="26.2" r=".51" fill="none" stroke="#000080" stroke-width=".21"/>
<path d="M238.8 21.1v7.6" fill="none" stroke="#000080" stroke-width=".25"/>
<circle cx="238.8" cy="21.1" r=".51" fill="#000080"/>
<circle cx="238.8" cy="21.1" r=".51" fill="none" stroke="#000080" stroke-width=".21"/>
<path d="M236.3 21.1h20.3" fill="none" stroke="#000080" stroke-width=".25"/>
<circle cx="238.8" cy="21.1" r=".51" fill="#000080"/>
<circle cx="238.8" cy="21.1" r=".51" fill="none" stroke="#000080" stroke-width=".21"/>
<path d="M228.6 115.2h12.7M228.6 107.6h12.7M228.6 105.1h12.7M132 135.6h53.4M228.6 158.5h12.7M228.6 150.8h12.7M228.6 148.3h12.7M228.6 166.1h12.7M228.6 163.6h12.7" fill="none" stroke="#000080" stroke-width=".25"/>
<circle cx="134.5" cy="135.6" r=".51" fill="#000080"/>
<circle cx="134.5" cy="135.6" r=".51" fill="none" stroke="#000080" stroke-width=".21"/>
<circle cx="147.2" cy="135.6" r=".51" fill="#000080"/>
<circle cx="147.2" cy="135.6" r=".51" fill="none" stroke="#000080" stroke-width=".21"/>
<path d="M147.2 135.6v2.5" fill="none" stroke="#000080" stroke-width=".25"/>
<circle cx="147.2" cy="135.6" r=".51" fill="#000080"/>
<circle cx="147.2" cy="135.6" r=".51" fill="none" stroke="#000080" stroke-width=".21"/>
<path d="M37.8 117.8h17.8M37.8 122.9h17.8M86.2 148.3v2.5h-12.8" fill="none" stroke="#000080" stroke-width=".25"/>
<circle cx="83.6" cy="150.8" r=".51" fill="#000080"/>
<circle cx="83.6" cy="150.8" r=".51" fill="none" stroke="#000080" stroke-width=".21"/>
<path d="M37.8 64.3h20.4M37.8 66.9h20.4M37.8 77.1h20.4M37.8 61.8h20.4M167.6 148.3h17.8M167.6 150.8h17.8M167.6 145.8h17.8M167.6 161h17.8" fill="none" stroke="#000080" stroke-width=".76"/>
<path d="M228.6 97.4h12.7M228.6 89.8h12.7M228.6 133h12.7M228.6 140.7h12.7" fill="none" stroke="#cbdaff" stroke-width="1.3"/>
<g fill="none" stroke="#adbce7" stroke-width=".38">
<path d="M229.1 97l1 .9M229.1 89.3l1 .9M231.7 97l1 .9M231.7 89.3l1 .9M234.2 97l1 .9M234.2 89.3l1 .9M236.8 97l1 .9M236.8 89.3l1 .9M239.3 97l1 .9M239.3 89.3l1 .9M229.1 132.6l1 .9M231.7 132.6l1 .9"/>
<path d="M234.2 132.6l1 .9M236.8 132.6l1 .9M239.3 132.6l1 .9M229.1 140.2l1 .9M231.7 140.2l1 .9M234.2 140.2l1 .9M236.8 140.2l1 .9M239.3 140.2l1 .9"/>
</g>
<path d="M228.6 97.4h12.7M228.6 89.8h12.7M228.6 133h12.7M228.6 140.7h12.7" fill="none" stroke="#adbce7" stroke-width=".25"/>
<use href="#words"/>
</svg>
